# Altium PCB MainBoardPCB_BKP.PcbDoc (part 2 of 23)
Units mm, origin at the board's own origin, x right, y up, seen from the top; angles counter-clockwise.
Board outline 258.95 x 308.86 mm, 16 copper layers (L1, L2 (GND), L3 (Sign), L4 (GND), L5 (Sign), L6 (PWR/GND), L7(PWR/GND), L8 (Plane_GND), L9 (PWR/GND), L10 (PWR/GND), L11 (PWR/GND), L12 (Sign), L13 (GND), L14 (Sign), L15 (GND), L16), stack 2.502 mm thick; 2361 components, 1770 nets, 8410 pads, 3259 vias.
Unrouted connection lines stored in the file: 4700.

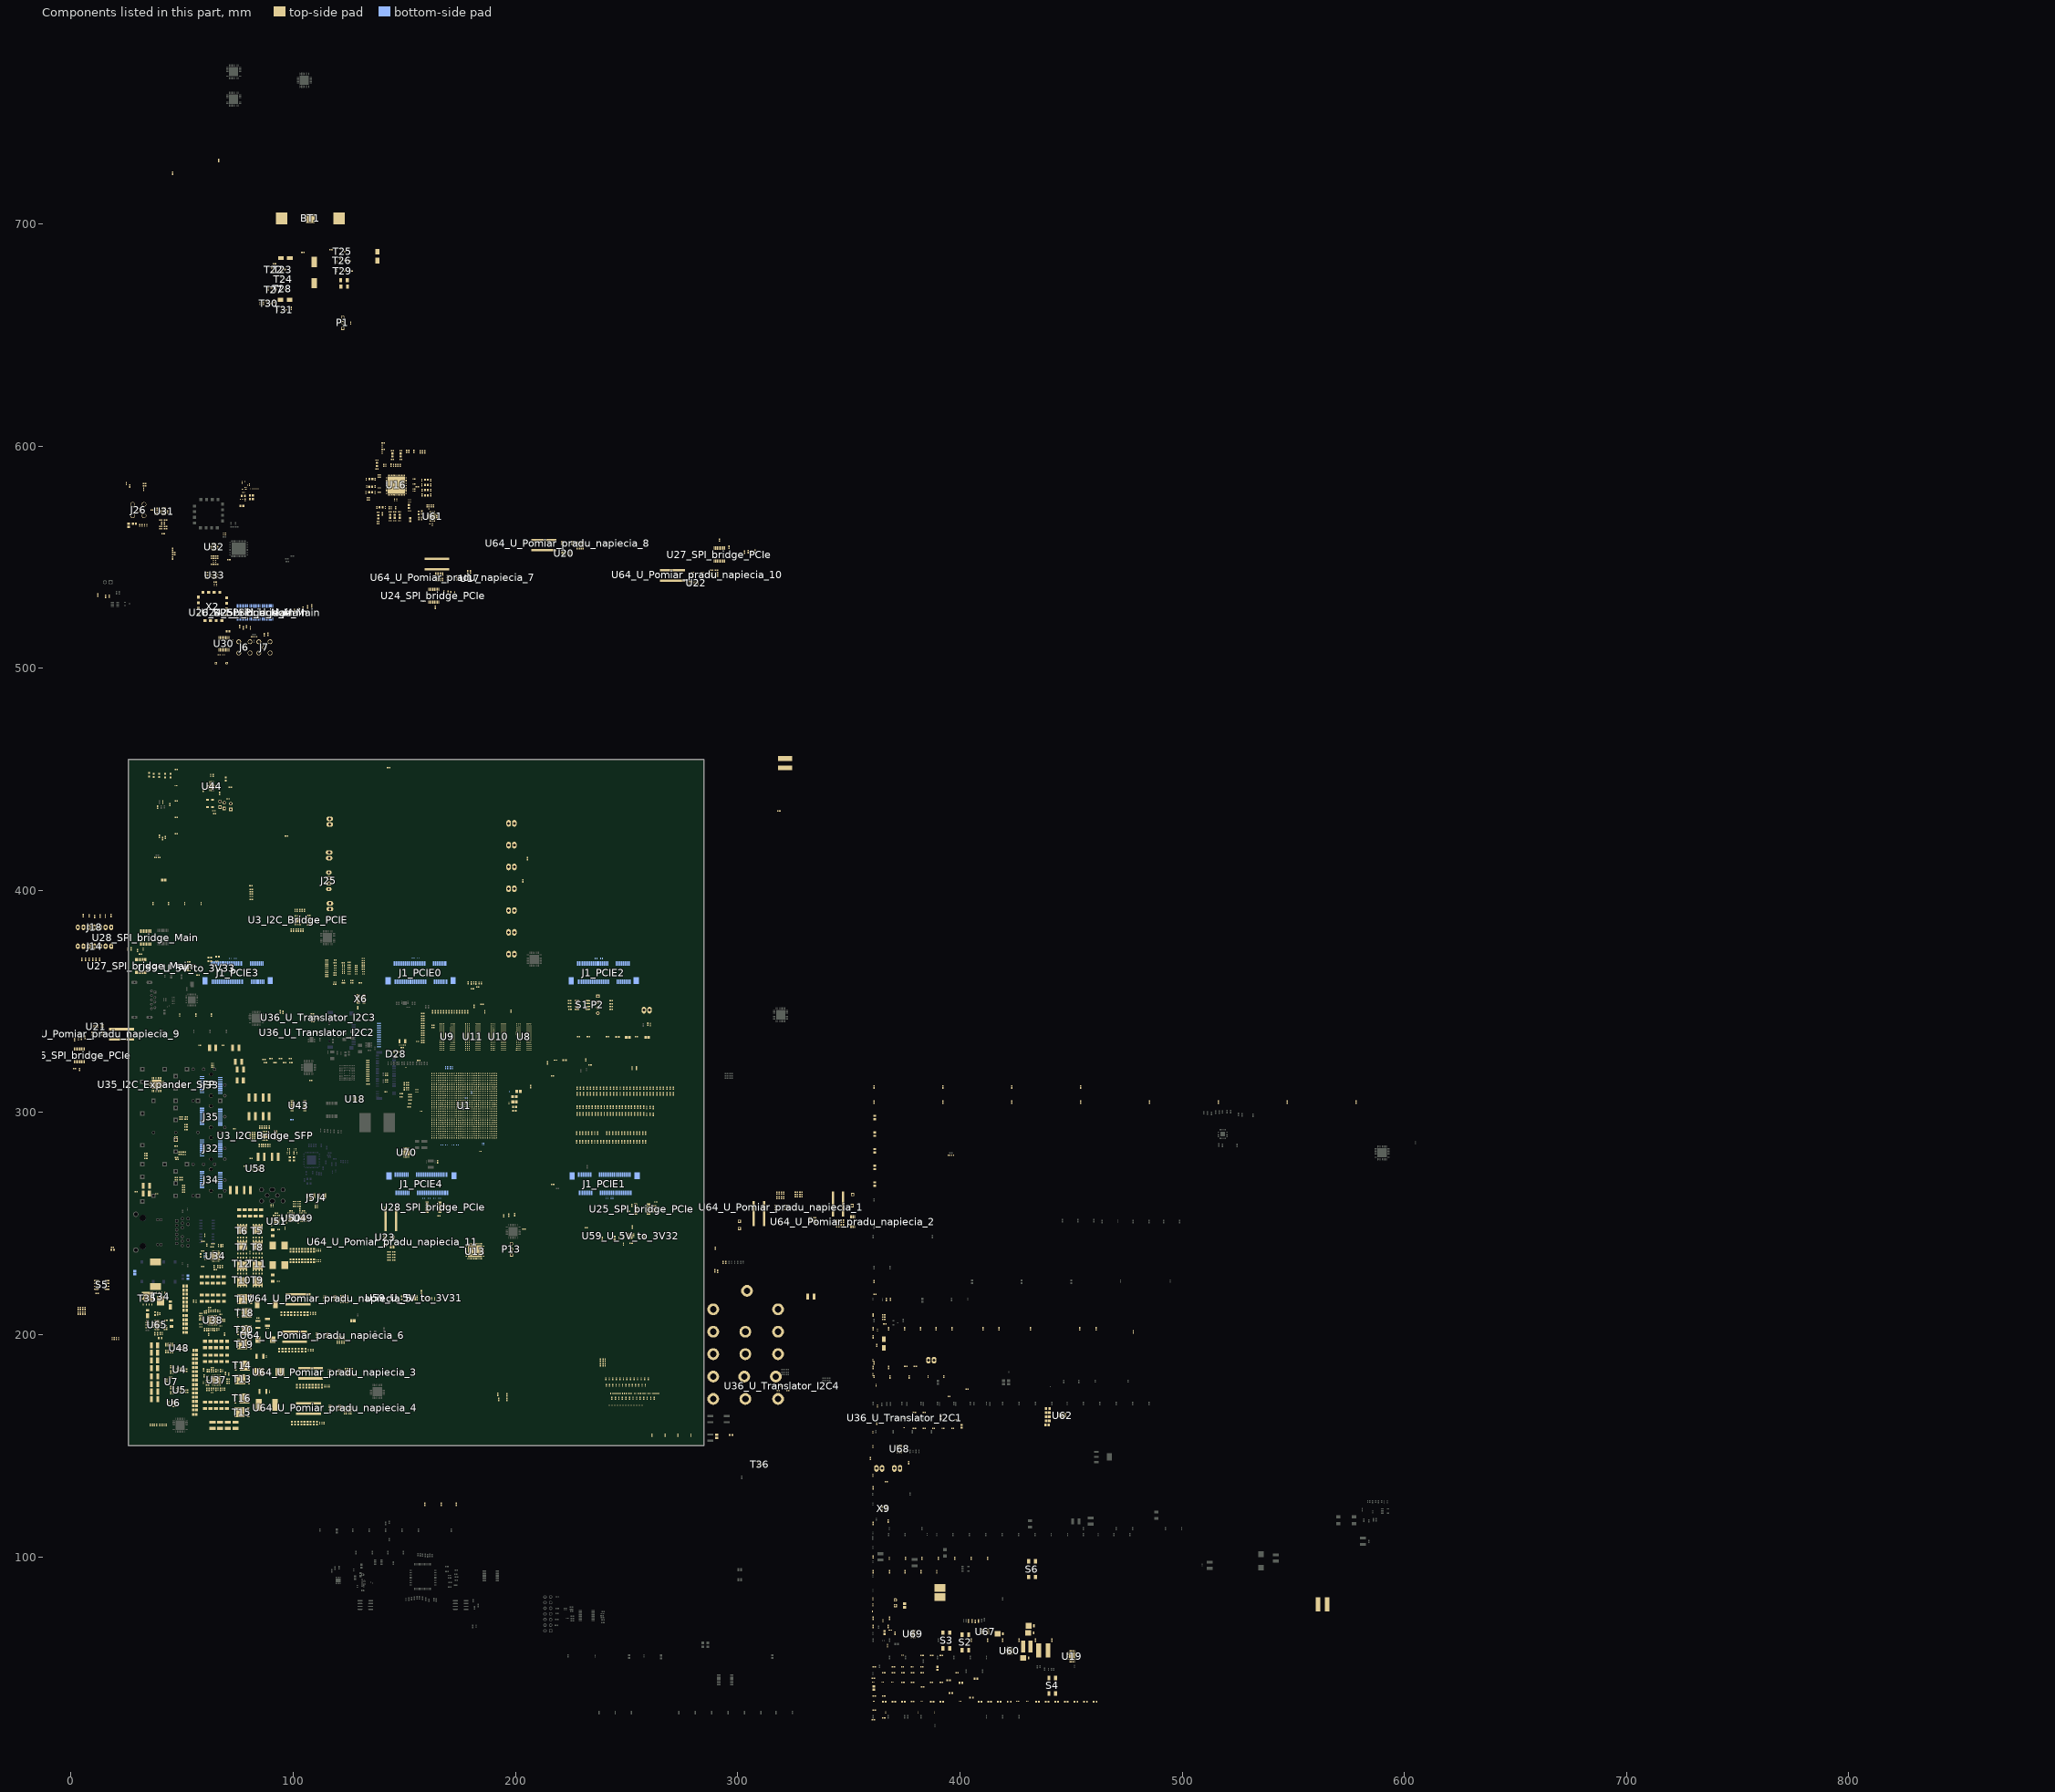
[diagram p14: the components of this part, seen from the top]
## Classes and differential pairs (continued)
component class U_TPS7A88_3V3_1V8_0V9V@2x1A: C705 C706 C707 C708 C709 C710 C711 C712 R671 R672 R673 R674 R676 R745 U70
component class U_ADP1741_3V3_0V85: C674 C675 C676 C719 FB45 R435 R644 R645 R646 R668 U69
component class LowCurr: C304 C305 C306 C307 C308 C354 C355 C603 C604 C605 C606 C607 C610 C611 C612 C613 C614 C615 C616 C617 C618 C619 C620 C621 C622 C623 C624 C625 C626 D16 D17 D18 D19 L13 L15 L16 L17 L18 R113 R114 R212 R214 R216 R218 R220 R274 R284 R305 R308 R309 U19 U67
component class U_Detektor_otwarcia: BT1 BT? C609 C678 C679 C680 D20 D21 D23 D24 J36 R647 R648 R649 R650 R651 R652 R653 R654 R655 R656 R657 R658 T22 T23 T24 T25 T26 T27 T28 T29 T30 T31
net class RAM_DQS_Strobe: DDR4_DQS_0_N DDR4_DQS_0_P DDR4_DQS_1_N DDR4_DQS_1_P DDR4_DQS_2_N DDR4_DQS_2_P DDR4_DQS_3_N DDR4_DQS_3_P DDR4_DQS_4_N DDR4_DQS_4_P DDR4_DQS_5_N DDR4_DQS_5_P DDR4_DQS_6_N DDR4_DQS_6_P DDR4_DQS_7_N DDR4_DQS_7_P DDR4_DQS_8_N DDR4_DQS_8_P
net class RAM_Data_IO: DDR4_DM0 DDR4_DM1 DDR4_DM2 DDR4_DM3 DDR4_DM4 DDR4_DM5 DDR4_DM6 DDR4_DM7 DDR4_DQ0 DDR4_DQ1 DDR4_DQ2 DDR4_DQ3 DDR4_DQ4 DDR4_DQ5 DDR4_DQ6 DDR4_DQ7 DDR4_DQ8 DDR4_DQ9 DDR4_DQ10 DDR4_DQ11 DDR4_DQ12 DDR4_DQ13 DDR4_DQ14 DDR4_DQ15 DDR4_DQ16 DDR4_DQ17 DDR4_DQ18 DDR4_DQ19 DDR4_DQ20 DDR4_DQ21 DDR4_DQ22 DDR4_DQ23 DDR4_DQ24 DDR4_DQ25 DDR4_DQ26 DDR4_DQ27 DDR4_DQ28 DDR4_DQ29 DDR4_DQ30 DDR4_DQ31 DDR4_DQ32 DDR4_DQ33 DDR4_DQ34 DDR4_DQ35 DDR4_DQ36 DDR4_DQ37 DDR4_DQ38 DDR4_DQ39 DDR4_DQ40 DDR4_DQ41 DDR4_DQ42 DDR4_DQ43 DDR4_DQ44 DDR4_DQ45 DDR4_DQ46 DDR4_DQ47 DDR4_DQ48 DDR4_DQ49 DDR4_DQ50 DDR4_DQ51 DDR4_DQ52 DDR4_DQ53 DDR4_DQ54 DDR4_DQ55 DDR4_DQ56 DDR4_DQ57 DDR4_DQ58 DDR4_DQ59 DDR4_DQ60 DDR4_DQ61 DDR4_DQ62 DDR4_DQ63
net class Power_Line_1A: 12V_LT3042 ADP1741_3.6V ETH_VDDIO NetD16_2 NetD17_1 NetD17_2 NetD18_1 NetD18_2 NetD19_1 NetD19_2 Power_3.3_1 Power_3.3_2 US+_MGTVccAux US+_Vcc_PS_DDR_504
net class Lenght_DQS_to_Data: DDR4_DM0 DDR4_DM1 DDR4_DM2 DDR4_DM3 DDR4_DM4 DDR4_DM5 DDR4_DM6 DDR4_DM7 DDR4_DQ0 DDR4_DQ1 DDR4_DQ2 DDR4_DQ3 DDR4_DQ4 DDR4_DQ5 DDR4_DQ6 DDR4_DQ7 DDR4_DQ8 DDR4_DQ9 DDR4_DQ10 DDR4_DQ11 DDR4_DQ12 DDR4_DQ13 DDR4_DQ14 DDR4_DQ15 DDR4_DQ16 DDR4_DQ17 DDR4_DQ18 DDR4_DQ19 DDR4_DQ20 DDR4_DQ21 DDR4_DQ22 DDR4_DQ23 DDR4_DQ24 DDR4_DQ25 DDR4_DQ26 DDR4_DQ27 DDR4_DQ28 DDR4_DQ29 DDR4_DQ30 DDR4_DQ31 DDR4_DQ32 DDR4_DQ33 DDR4_DQ34 DDR4_DQ35 DDR4_DQ36 DDR4_DQ37 DDR4_DQ38 DDR4_DQ39 DDR4_DQ40 DDR4_DQ41 DDR4_DQ42 DDR4_DQ43 DDR4_DQ44 DDR4_DQ45 DDR4_DQ46 DDR4_DQ47 DDR4_DQ48 DDR4_DQ49 DDR4_DQ50 DDR4_DQ51 DDR4_DQ52 DDR4_DQ53 DDR4_DQ54 DDR4_DQ55 DDR4_DQ56 DDR4_DQ57 DDR4_DQ58 DDR4_DQ59 DDR4_DQ60 DDR4_DQ61 DDR4_DQ62 DDR4_DQ63
net class Lenght_DQS_to_CK: DDR4_DQS_0_N DDR4_DQS_0_P DDR4_DQS_1_N DDR4_DQS_1_P DDR4_DQS_2_N DDR4_DQS_2_P DDR4_DQS_3_N DDR4_DQS_3_P DDR4_DQS_4_N DDR4_DQS_4_P DDR4_DQS_5_N DDR4_DQS_5_P DDR4_DQS_6_N DDR4_DQS_6_P DDR4_DQS_7_N DDR4_DQS_7_P DDR4_DQS_8_N DDR4_DQS_8_P
net class Lenght_CK_to_Addr: DDR4_CK_N DDR4_CK_P
differential pair class Diff_76_to_90_Ram_CLK: DDR4_CK
net class RAM_Adress: DDR4_A0 DDR4_A1 DDR4_A2 DDR4_A3 DDR4_A4 DDR4_A5 DDR4_A6 DDR4_A7 DDR4_A8 DDR4_A9 DDR4_A10 DDR4_A11 DDR4_A12 DDR4_A13 DDR4_ACT_N DDR4_ALERT_N DDR4_BA0 DDR4_BA1 DDR4_BG0 DDR4_CAS DDR4_CKE0 DDR4_CS_B DDR4_DQS_ODT0 DDR4_PARITY DDR4_RAM_RST_N DDR4_RAS DDR4_TEN DDR4_WE
component class U_Power_48_20V@3A: C595 C596 C597 C598 C693 C694 C695 C696 C697 C698 C699 C700 C701 C702 C703 C704 D26 D27 L22 R140 R149 R150 R159 R160 R665 R666 R667 R669 R670 R764 T34 T35 U65
net class WR_CLK_C: WR_LMK_CLK_IN_N WR_LMK_CLK_IN_P
net class WR_CLK2: WR_LMK_CLK_HF2_N WR_LMK_CLK_HF2_P
net class WR_CLK1: WR_LMK_CLK_HF1_N WR_LMK_CLK_HF1_P
component class U_Pomiar_pradu_napiecia_1: C309_U_Pomiar_pradu_napiecia_1 R448_U_Pomiar_pradu_napiecia_1 U64_U_Pomiar_pradu_napiecia_1
component class U_Pomiar_pradu_napiecia_2: C309_U_Pomiar_pradu_napiecia_2 R448_U_Pomiar_pradu_napiecia_2 U64_U_Pomiar_pradu_napiecia_2
component class U_Pomiar_pradu_napiecia_3: C309_U_Pomiar_pradu_napiecia_3 R448_U_Pomiar_pradu_napiecia_3 U64_U_Pomiar_pradu_napiecia_3
component class U_Pomiar_pradu_napiecia_4: C309_U_Pomiar_pradu_napiecia_4 R448_U_Pomiar_pradu_napiecia_4 U64_U_Pomiar_pradu_napiecia_4
net class LTC_6952_2_REF_SMA: LTC6952_1_C_N LTC6952_1_C_P
net class LTC_6952_2_REF: LTC6952_1_REF_N LTC6952_1_REF_P
component class DAC: C320 C321 C322 C323 R481 R608 R609 U30 X2 X3
net class Si53323_2_Q2_LVDS: Si53323_2_Q2_LVDS_N Si53323_2_Q2_LVDS_P
net class Si53323_1_Q2_LVDS: Si53323_1_Q2_LVDS_N Si53323_1_Q2_LVDS_P
component class SFP_Group+IMU: R469 R470 R471 R472 R473 R474 R475 R476 R477 R478 R479 R480
component class HighSpeed: R427 R449 R450 R451 R452 R453 R454 R538
component class CLK_MUX: C324 C325 C326 C327 C328 C329 C330 C333 C336 C337 C338 C339 C340 C341 C342 C343 C344 C724 C725 C726 C727 FB23 FB24 J26 R245 R246 R247 R248 R249 R250 R251 R252 R253 R254 R255 R256 R257 R258 R259 R260 R261 R262 R263 R264 R265 R291 R301 R384 R385 R386 R387 R482 R483 R484 R485 R486 R487 R488 R489 T36 U31 U32 U33
net class Si53323_2_Q2: Si53323_2_Q2_N Si53323_2_Q2_P
net class Si53323_2_Q1: Si53323_2_Q1_P
net class Si53323_2_CLK1: Si53323_2_CLK1_N Si53323_2_CLK1_P
net class Si53323_1_Q2: Si53323_1_Q2_N Si53323_1_Q2_P
net class Si53323_1_Q1: Si53323_1_Q1_N
net class RefClk_Si53323: RefClk_Si53323_P
net class MUX_DIV_OUT: OSC_Out_DIV_P
net class MUX_DIV_OUT_I: Osc_in_Si53323_2_P
net class CLM_M_OSC_IN_C: OSC_500Out
net class CLK_SMA1_C: AGND LTC6952_1_C_Out10_N LTC6952_1_C_Out10_P
net class CLK_M_OSC_In: CLK_M_OSC_In
differential pair class Diff_76_to_90_Ram_DQS: DDR4_DQS_0 DDR4_DQS_1 DDR4_DQS_2 DDR4_DQS_3 DDR4_DQS_4 DDR4_DQS_5 DDR4_DQS_6 DDR4_DQS_7 DDR4_DQS_8
net class Single_36_39_50_Adr: DDR4_A0 DDR4_A1 DDR4_A2 DDR4_A3 DDR4_A4 DDR4_A5 DDR4_A6 DDR4_A7 DDR4_A8 DDR4_A9 DDR4_A10 DDR4_A11 DDR4_A12 DDR4_A13 DDR4_ACT_N DDR4_ALERT_N DDR4_BA0 DDR4_BA1 DDR4_BG0 DDR4_CAS DDR4_CKE0 DDR4_CS_B DDR4_DQS_ODT0 DDR4_PARITY DDR4_RAM_RST_N DDR4_RAS DDR4_TEN DDR4_WE
net class Diff_76_86_90: DDR4_DQS_0_N DDR4_DQS_0_P DDR4_DQS_1_N DDR4_DQS_1_P DDR4_DQS_2_N DDR4_DQS_2_P DDR4_DQS_3_N DDR4_DQS_3_P DDR4_DQS_4_N DDR4_DQS_4_P DDR4_DQS_5_N DDR4_DQS_5_P DDR4_DQS_6_N DDR4_DQS_6_P DDR4_DQS_7_N DDR4_DQS_7_P DDR4_DQS_8_N DDR4_DQS_8_P
net class RAM_Clock_Signal: DDR4_CK_N DDR4_CK_P
component class U_Pomiar_pradu_napiecia_5: C309_U_Pomiar_pradu_napiecia_5 R448_U_Pomiar_pradu_napiecia_5 U64_U_Pomiar_pradu_napiecia_5
component class U_Pomiar_pradu_napiecia_6: C309_U_Pomiar_pradu_napiecia_6 R448_U_Pomiar_pradu_napiecia_6 U64_U_Pomiar_pradu_napiecia_6
component class U_Pomiar_pradu_napiecia_7: C309_U_Pomiar_pradu_napiecia_7 R448_U_Pomiar_pradu_napiecia_7 U64_U_Pomiar_pradu_napiecia_7
component class U_Pomiar_pradu_napiecia_8: C309_U_Pomiar_pradu_napiecia_8 R448_U_Pomiar_pradu_napiecia_8 U64_U_Pomiar_pradu_napiecia_8
component class U_Pomiar_pradu_napiecia_9: C309_U_Pomiar_pradu_napiecia_9 R448_U_Pomiar_pradu_napiecia_9 U64_U_Pomiar_pradu_napiecia_9
component class U_5V_to_3V31: C563_U_5V_to_3V31 C564_U_5V_to_3V31 C565_U_5V_to_3V31 C566_U_5V_to_3V31 C567_U_5V_to_3V31 R430_U_5V_to_3V31 R431_U_5V_to_3V31 R432_U_5V_to_3V31 U59_U_5V_to_3V31
channel class Pomiar_pradu_napiecia: U_Pomiar_pradu_napiecia_10 U_Pomiar_pradu_napiecia_11
net class Single_39_50_D: DDR4_DM0 DDR4_DM1 DDR4_DM2 DDR4_DM3 DDR4_DM4 DDR4_DM5 DDR4_DM6 DDR4_DM7 DDR4_DQ0 DDR4_DQ1 DDR4_DQ2 DDR4_DQ3 DDR4_DQ4 DDR4_DQ5 DDR4_DQ6 DDR4_DQ7 DDR4_DQ8 DDR4_DQ9 DDR4_DQ10 DDR4_DQ11 DDR4_DQ12 DDR4_DQ13 DDR4_DQ14 DDR4_DQ15 DDR4_DQ16 DDR4_DQ17 DDR4_DQ18 DDR4_DQ19 DDR4_DQ20 DDR4_DQ21 DDR4_DQ22 DDR4_DQ23 DDR4_DQ24 DDR4_DQ25 DDR4_DQ26 DDR4_DQ27 DDR4_DQ28 DDR4_DQ29 DDR4_DQ30 DDR4_DQ31 DDR4_DQ32 DDR4_DQ33 DDR4_DQ34 DDR4_DQ35 DDR4_DQ36 DDR4_DQ37 DDR4_DQ38 DDR4_DQ39 DDR4_DQ40 DDR4_DQ41 DDR4_DQ42 DDR4_DQ43 DDR4_DQ44 DDR4_DQ45 DDR4_DQ46 DDR4_DQ47 DDR4_DQ48 DDR4_DQ49 DDR4_DQ50 DDR4_DQ51 DDR4_DQ52 DDR4_DQ53 DDR4_DQ54 DDR4_DQ55 DDR4_DQ56 DDR4_DQ57 DDR4_DQ58 DDR4_DQ59 DDR4_DQ60 DDR4_DQ61 DDR4_DQ62 DDR4_DQ63
component class US+_Interrupts: R515 R522 R523 R530 R531 R546 R547 R548 R549 R550 R551 R552 R553 R554 R555 R556 R557 R607 R618 R659 R660 R661 R662 R663 R664 R688 R735 R736 R744 R765 R766 R767 R817 R818 R819 R820 R821 R822 R823 R824 R847 R848 R849 R850 R851 R852 R853 R854 R855 R856 R857 R858 R859 R860 R861 R862 R863 R864 R865 R866 R867 R868 R869 R870 R871 R872 R873 R874 R875 R876 R877 R878 R879 R880 R881 R882 R883 R884 R885 R886 R921 R922 R923 R924 R925 R926 R927 R928 R929 R930 R931 R932 R933 R934 R935 R936 R937 R938 R939 R940 R941 R942 R943 R944 R945 R946 R947 R948 R949 R950 R951 R952 R953 R954 R955 R956 R957 R958 R959 R960 R961 R962 R963 R964 R965 R966 R967 R968 R969 R970 R971 R972 R973 R974 R975 R976 R977 R978 R979 R980 R981 R982 R983 R984 R985 R986 R987 R988 R989 R990 R991 R992 R993 R994 R995 R996 R997 R998 R999 R1000
component class U_Pomiar_pradu_napiecia_10: C309_U_Pomiar_pradu_napiecia_10 R448_U_Pomiar_pradu_napiecia_10 U64_U_Pomiar_pradu_napiecia_10
component class U_Pomiar_pradu_napiecia_11: C309_U_Pomiar_pradu_napiecia_11 R448_U_Pomiar_pradu_napiecia_11 U64_U_Pomiar_pradu_napiecia_11
component class PowerDistribition: P7 P8 P9 P10 P11 R229 R230 R455 R456 R457 R458 R459 R460 R461 R462 R463 R464 R465 R466 R467 R468 R593 R594 R595 R596 R597 R598
net class Single_50: Bank505_MGTRREF0_C_N Bank505_MGTRREF0_C_P Bank505_MGTRREF2_C_N Bank505_MGTRREF2_C_P Bank505_MGTRREF3_C_N Bank505_MGTRREF3_C_P CLK_M_OSC_In CLK_SMA0_C_N CLK_SMA0_C_P LTC6952_0_Out0_N LTC6952_0_Out0_P LTC6952_0_Out1_N LTC6952_0_Out1_P LTC6952_0_Out2_N LTC6952_0_Out2_P LTC6952_0_Out3_N LTC6952_0_Out3_P LTC6952_0_Out4_N LTC6952_0_Out4_P LTC6952_0_Out5_N LTC6952_0_Out5_P LTC6952_0_Out6_N LTC6952_0_Out6_P LTC6952_0_Out7_N LTC6952_0_Out7_P LTC6952_0_Out8_N LTC6952_0_Out8_P LTC6952_0_Out9_N LTC6952_0_Out9_P LTC6952_0_Out10_N LTC6952_0_Out10_P LTC6952_0_REF_N LTC6952_0_REF_P LTC6952_1_C_N LTC6952_1_C_Out10_N LTC6952_1_C_Out10_P LTC6952_1_C_P LTC6952_1_Out0_N LTC6952_1_Out0_P LTC6952_1_Out1_N LTC6952_1_Out1_P LTC6952_1_Out2_N LTC6952_1_Out2_P LTC6952_1_Out3_N LTC6952_1_Out3_P LTC6952_1_Out4_N LTC6952_1_Out4_P LTC6952_1_Out5_N LTC6952_1_Out5_P LTC6952_1_Out6_N LTC6952_1_Out6_P LTC6952_1_Out7_N LTC6952_1_Out7_P LTC6952_1_Out8_N LTC6952_1_Out8_P LTC6952_1_Out9_N LTC6952_1_Out9_P LTC6952_1_Out10_N LTC6952_1_Out10_P LTC6952_1_REF_N LTC6952_1_REF_P LTC6952_1_VCO_N LTC6952_1_VCO_P NetC334_1 NetC335_2 NetC341_1 NetC588_1 NetC588_2 NetR543_1 NVME_C_RX_1_N NVME_C_RX_1_P NVME_C_RX_O_N NVME_C_RX_O_P NVME_C_TX_1_N NVME_C_TX_1_P NVME_C_TX_O_N NVME_C_TX_O_P NVMe_Rx_0_N NVMe_Rx_0_P NVMe_Rx_1_N NVMe_Rx_1_P NVMe_Tx_0_N NVMe_Tx_0_P NVMe_Tx_1_N NVMe_Tx_1_P OSC_500Out Osc_in_Si53323_2_P OSC_Out_DIV_N OSC_Out_DIV_P RefClk_Si53323_P SGMI_C_Rx_N SGMI_C_Rx_P SGMI_C_Tx_N SGMI_C_Tx_P SGMI_Rx_N SGMI_Rx_P SGMI_Tx_N SGMI_Tx_P Si53323_1_Q1_N Si53323_1_Q2_LVDS_N Si53323_1_Q2_LVDS_P Si53323_1_Q2_N Si53323_1_Q2_P Si53323_2_CLK1_N Si53323_2_CLK1_P Si53323_2_Q1_N Si53323_2_Q1_P Si53323_2_Q2_LVDS_N Si53323_2_Q2_LVDS_P Si53323_2_Q2_N Si53323_2_Q2_P TD_A_N TD_A_P TD_B_N TD_B_P TD_C_N TD_C_P TD_D_N TD_D_P WR_LMK_CLK_HF1_N WR_LMK_CLK_HF1_P WR_LMK_CLK_HF2_N WR_LMK_CLK_HF2_P WR_LMK_CLK_IN_N WR_LMK_CLK_IN_P XO_LMK05028_P
net class Bank505_MGTRREFx_C: Bank505_MGTRREF0_C_N Bank505_MGTRREF0_C_P Bank505_MGTRREF2_C_N Bank505_MGTRREF2_C_P Bank505_MGTRREF3_C_N Bank505_MGTRREF3_C_P NetU2_L25 NetU2_L26
net class Bank225_MGTREFx_C: Bank225_MGTREF0_C_N Bank225_MGTREF0_C_P Bank225_MGTREF1_C_N Bank225_MGTREF1_C_P
net class Bank224_MGTREFx_C: Bank224_MGTREF0_C_N Bank224_MGTREF0_C_P Bank224_MGTREF1_C_N Bank224_MGTREF1_C_P
net class Bank223_MGTREFx_C: Bank223_MGTREF0_C_N Bank223_MGTREF0_C_P Bank223_MGTREF1_C_N Bank223_MGTREF1_C_P
component class U_Translator_I2C4: TP60_U_Translator_I2C4 TP61_U_Translator_I2C4 U36_U_Translator_I2C4
differential pair class Diff_100: B223_Rx0 B223_Rx1 B223_Rx2 B223_Rx3 B223_Tx0_to_C B223_Tx0C_to_B B223_Tx1_to_C B223_Tx1C_to_B B223_Tx2_to_C B223_Tx2C_to_B B223_Tx3_to_C B223_Tx3C_to_B B224_Rx0 B224_Rx1 B224_Rx2 B224_Rx3 B224_Tx0_to_C B224_Tx0C_to_B B224_Tx1_to_C B224_Tx1C_to_B B224_Tx2_to_C B224_Tx2C_to_B B224_Tx3_to_C B224_Tx3C_to_B B225_Rx0 B225_Rx1 B225_Rx2 B225_Rx3 B225_Tx0_to_C B225_Tx0C_to_B B225_Tx1_to_C B225_Tx1C_to_B B225_Tx2_to_C B225_Tx2C_to_B B225_Tx3_to_C B225_Tx3C_to_B Bank223_MGTREF0 Bank223_MGTREF0_C Bank223_MGTREF1 Bank223_MGTREF1_C Bank224_MGTREF0 Bank224_MGTREF0_C Bank224_MGTREF1 Bank224_MGTREF1_C Bank225_MGTREF0 Bank225_MGTREF0_C Bank225_MGTREF1 Bank225_MGTREF1_C Bank505_MGTRREF0_C Bank505_MGTRREF2_C Bank505_MGTRREF3_C CLK_100 CLK_Fanout_In CLK_GTR_T1 CLK_GTR_T2 CLK_GTR_T3 CLK_Hi_Rail1 CLK_Hi_Rail1_SysRef CLK_Hi_Rail2 CLK_Hi_Rail2_SysRef CLK_M_OSC_In CLK_NVME_Conn CLK_Q223_T1 CLK_Q224_T1 CLK_Q225_T1 CLK_Q226_T1 CLK_SMA0 CLK_SMA0_C CLK_SMA1 CLK_SMA1_C CLK_SMA2 CLK_SMA2_C Data_2_RX_PCIE0 Data_2_RX_PCIE1 Data_2_RX_PCIE2 Data_2_RX_PCIE3 Data_2_TX_PCIE0 Data_2_TX_PCIE1 Data_2_TX_PCIE2 Data_2_TX_PCIE3 Data_3_RX_PCIE0 Data_3_RX_PCIE1 Data_3_RX_PCIE2 Data_3_RX_PCIE3 Data_3_TX_PCIE0 Data_3_TX_PCIE1 Data_3_TX_PCIE2 Data_3_TX_PCIE3 LTC6952_0_Out0 LTC6952_0_Out1 LTC6952_0_Out2 LTC6952_0_Out3 LTC6952_0_Out4 LTC6952_0_Out5 LTC6952_0_Out6 LTC6952_0_Out7 LTC6952_0_Out8 LTC6952_0_Out9 LTC6952_0_Out10 LTC6952_0_REF LTC6952_1_C LTC6952_1_C_Out10 LTC6952_1_Out0 LTC6952_1_Out1 LTC6952_1_Out2 LTC6952_1_Out3 LTC6952_1_Out4 LTC6952_1_Out5 LTC6952_1_Out6 LTC6952_1_Out7 LTC6952_1_Out8 LTC6952_1_Out9 LTC6952_1_Out10 LTC6952_1_REF LTC6952_1_VCO LTC6952_2_REF LTC6952_2_REF_SMA LTC6952_3_REF LTC6952_3_REF_SMA NVME_C_RX_1 NVME_C_RX_O NVME_C_TX_1 NVME_C_TX_O NVMe_CLK NVMe_Rx_0 NVMe_Rx_1 NVMe_Tx_0 NVMe_Tx_1 Osc_in_Si53323_2 OSC_Out_DIV PCIE0_CLK PCIE0_Sync PCIE0_SysRef PCIE0_SysRef_FPGA PCIE1_CLK PCIE1_Sync PCIE1_SysRef PCIE1_SysRef_FPGA PCIE2_CLK PCIE2_Sync PCIE2_SysRef PCIE2_SysRef_FPGA PCIE3_CLK PCIE3_Sync PCIE3_SysRef PCIE3_SysRef_FPGA PCIE4_CLK PCIE4_Sync PCIE4_SysRef PCIE4_SysRef_FPGA RefClk_Si53323 SFP0_Rx SFP0_Tx SFP1_Rx SFP1_Tx SFP2_Rx SFP2_Tx SFP3_Rx SFP3_Tx SGMI_C_Rx SGMI_C_Tx SGMI_CLK_C_Out SGMI_CLK_Out SGMI_Rx SGMI_Tx Si53323_1_Q1 Si53323_1_Q2 Si53323_1_Q2_LVDS Si53323_2_CLK1 Si53323_2_Q1 Si53323_2_Q2 Si53323_2_Q2_LVDS SYNC_PCIE0 SYNC_PCIE1 SYNC_PCIE2 SYNC_PCIE3 SYNC_PCIE4 SYSREF_PCIE0 SYSREF_PCIE1 SYSREF_PCIE2 SYSREF_PCIE3 SYSREF_PCIE4 TD_A TD_B TD_C TD_D WR_LMK_CLK_HF1 WR_LMK_CLK_HF2 WR_LMK_CLK_IN WR_Source_CLK
channel class Translator_I2C: U_Translator_I2C1 U_Translator_I2C2 U_Translator_I2C3
channel class 5V_to_3V3: 5V_to_3V3_for_FTDI U_5V_to_3V32 U_5V_to_3V33
net class SFP_diff: SFP0_Rx_N SFP0_Rx_P SFP0_Tx_N SFP0_Tx_P SFP1_Rx_N SFP1_Rx_P SFP1_Tx_N SFP1_Tx_P SFP2_Rx_N SFP2_Rx_P SFP2_Tx_N SFP2_Tx_P SFP3_Rx_N SFP3_Rx_P SFP3_Tx_N SFP3_Tx_P
net class C_to_Bank225: B225_Rx0_N B225_Rx0_P B225_Rx1_N B225_Rx1_P B225_Rx2_N B225_Rx2_P B225_Rx3_N B225_Rx3_P B225_Tx0C_to_B_N B225_Tx0C_to_B_P B225_Tx1C_to_B_N B225_Tx1C_to_B_P B225_Tx2C_to_B_N B225_Tx2C_to_B_P B225_Tx3C_to_B_N B225_Tx3C_to_B_P
net class C_to_Bank224: B224_Tx0C_to_B_N B224_Tx0C_to_B_P B224_Tx1C_to_B_N B224_Tx1C_to_B_P B224_Tx2C_to_B_N B224_Tx2C_to_B_P B224_Tx3C_to_B_N B224_Tx3C_to_B_P
net class C_to_Bank223: B223_Rx0_N B223_Rx0_P B223_Rx1_N B223_Rx1_P B223_Rx2_N B223_Rx2_P B223_Rx3_N B223_Rx3_P B223_Tx0C_to_B_N B223_Tx0C_to_B_P B223_Tx1C_to_B_N B223_Tx1C_to_B_P B223_Tx2C_to_B_N B223_Tx2C_to_B_P B223_Tx3C_to_B_N B223_Tx3C_to_B_P
component class U_Translator_I2C3: TP60_U_Translator_I2C3 TP61_U_Translator_I2C3 U36_U_Translator_I2C3
component class U_Translator_I2C2: TP60_U_Translator_I2C2 TP61_U_Translator_I2C2 U36_U_Translator_I2C2
component class U_Translator_I2C1: TP60_U_Translator_I2C1 TP61_U_Translator_I2C1 U36_U_Translator_I2C1
component class U_TPS7A88_5V_Dual_3: C572 C573 C574 C575 C576 C577 C578 C579 R436 R437 R438 R439 R440 R441 U61
component class U_LT3042_12V_5V_LNLDO: C580 C581 C582 C583 C584 FB34 R442 R443 R444 R445 U62
component class U_ADP1741_3: C568 C569 C570 C571 FB33 R433 R434 U60
component class U_5V_to_3V33: C563_U_5V_to_3V33 C564_U_5V_to_3V33 C565_U_5V_to_3V33 C566_U_5V_to_3V33 C567_U_5V_to_3V33 R430_U_5V_to_3V33 R431_U_5V_to_3V33 R432_U_5V_to_3V33 U59_U_5V_to_3V33
component class U_5V_to_3V32: C563_U_5V_to_3V32 C564_U_5V_to_3V32 C565_U_5V_to_3V32 C566_U_5V_to_3V32 C567_U_5V_to_3V32 R430_U_5V_to_3V32 R431_U_5V_to_3V32 R432_U_5V_to_3V32 U59_U_5V_to_3V32
component class Ram_Power: C219 C220 C221 C222 C223 C224 C225 C226 C227 C228 C229 C230 C231 C232 C233 C234 C235 C236 C237 C238 C239 C240 C241 C242 C243 C244 C245 C246 C247 C248 C249 C250 C251 C252 C253 C254 C255 C256 C257 C258 C259 C260 C261 C262 C263 C264 C265 C266 C782 C783 C784 C785 C786 C787 C788 C789 R165 R166 R167 R168 R169 R170 R171 R172
component class PS_Config: C531 C532 C533 C534 C535 C536 D5 D6 D7 D8 D9 D10 D11 D12 P2 P3 P4 P5 R346 R347 R348 R349 R350 R351 R352 R353 R354 R355 R356 R357 R358 R359 R360 R361 R367 R368 R369 R370 R371 R372 R373 R374 R375 R716 R717 R718 R719 R720 S1 S2 S3 S4 U43 U44 X5 X6
component class IMU: C561 C562 R429 R600 R601 U58
component class GTR: C525 C526 C527 C528 C529 C530 C649 C651 C653 C677 C715 C716 C717 C718 R69 R70 R126
component class "Bank 225": C291 C292 C293 C294 C295 C296 C297 C298 C299 C300 C301 C302
component class "Bank 224": C279 C280 C281 C282 C283 C284 C285 C286 C287 C288 C289 C290
component class "Bank 223": C267 C268 C269 C270 C271 C272 C273 C274 C275 C276 C277 C278
component class U_Power_Ethernet: C550 C551 C552 C553 C554 C555 C654 C655 C656 C657 R391 R392 R393 R394 R396 R397 R399 R632 R633 R634 U49 U50 U51 U68
component class U_Power_ADP1850_Dual_2: C430 C431 C432 C433 C434 C435 C436 C437 C438 C439 C440 C441 C442 C443 C444 C445 C446 C447 C448 C449 C450 C451 C452 C453 C454 C455 C456 C457 C458 C459 C460 C461 C462 C463 C464 C465 C466 C467 C468 C469 C470 C548 C549 C645 C646 C647 C648 C650 C652 L19 L20 R302 R303 R306 R307 R310 R312 R313 R314 R315 R316 R317 R318 R625 R626 R627 R628 R629 R631 R686 R687 T17 T18 T19 T20 U38
component class U_HI_Curr_ADP1850_3: C389 C390 C391 C392 C393 C394 C395 C396 C397 C398 C399 C400 C401 C402 C403 C404 C405 C406 C407 C408 C409 C410 C411 C412 C413 C414 C415 C416 C417 C418 C419 C420 C421 C422 C423 C424 C425 C426 C427 C428 C429 C637 C638 C639 C640 C641 C642 C643 C644 L11 L12 R285 R287 R288 R289 R290 R292 R293 R294 R295 R296 R297 R298 R299 R300 R619 R620 R621 R622 R623 R624 T13 T14 T15 T16 U37
component class "Zasilanie CLK": C55 C56 C57 C58 C59 C60 C61 C62 C63 C64 C65 C66 C67 C68 C69 C70 C71 C72 C73 C74 C75 C76 C77 C78 C79 C80 C81 C82 C83 C84 C85 C86 C87 C88 C89 C90 C91 C92 C93 C94 C95 C96 C97 C98 C99 C100 C101 C102 C103 C104 C105 C106 C107 C108 C109 C110 C111 C112 C113 C114 C115 C116 C117 C118 C119 C120 C121 C122 C123 C124 C125 C126 C127 C128 C129 C130 C131 C132 C133 C134 C135 C136 C137 C138 C139 C140 C141 C142 C143 C144 C145 C146 C147 C148 C149 C150 C151 C152 C153 C154 C155 C156 C157 C158 C159 C160 C161 C162 C163 C164 C165 C166 C167 C168 C169 C170 C171 C172 C173 C174 C175 C176 C177 C178 C179 C180 C181 C182 C183 C184 C185 C186 C187 C188 C189 C190 C191 C192 C193 C194 C195 C196 C197 C198 C199 C200 C201 C202 C203 C204 C205 C206 FB2 FB3 FB4 FB5 FB6 FB7 FB8 FB9 FB10 FB11 FB12 FB13 FB14 FB15 FB16 FB17 FB18 FB19 FB20 FB21 FB22 FB35 FB36 R738 R739 R740 R741 R742 R743 U16
component class PowerSelector: C4 C5 C6 C7 C8 C9 C10 C11 C12 C13 C14 C15 C16 C17 C18 C19 C20 C21 C22 C23 C24 C25 C26 C27 C28 C29 C30 C31 C32 C33 C34 C35 C312 C313 C314 C766 C767 C768 C769 C770 C771 C772 C773 C774 C775 C776 C777 C778 C779 C780 C781 R11 R12 R13 R15 R17 R18 R19 R20 R21 R23 R25 R26 R27 R28 R29 R30 R630 R677 R678 R679 R680 R681 R682 R683 R684 R685 R1052 R1053 U4 U5 U6 U7 U48
channel class SPI_Muxes: SPI_bridge_Main SPI_bridge_PCIe
channel class I2C_Expander: I2C_Expander4 I2C_Expander5
component class XilinxPower: B1 C627 C628 C629 C630 C631 C632 D28 FB38 FB39 FB40 FB41 FB42 J29 J30 R173 R276 R279 R282 R283 R286 R693 R694 R695 R696
component class "Xilinx Linux": J12 J13 J14 J15 J16 J17 J18 J19 J20 J21 J22 J23 J24 J25 P1 P13 R83 R84 R85 R86 R87 R88 R89 R90 R91 R92 R93 R94 R95 R96 R97 R98 R99 R100 R101 R102 R103 R104 R105 R106 R107 R108 R109 R110 R111 R112 R115 R116 R117 R118 R119 R120 R121 R122 R123 R362 R675 R737 R768 R769 R770 R771 R772 R773 R774 R775 R776 R777 R778 R779 R780 R781 R782 R783 R784 R785 R786 R787 R788 R789 R790 R791 R792 R793 R794 R795 R796 R797 R798 R799 R800 R801 R802 R803 R804 R805 R806 R807 R808 R809 R810 R811 R812 R813 R814 R815 R816 TP21 TP22 TP23 TP24 TP25 TP26 TP27 TP28 TP29 TP30 TP31 TP32 TP33 TP34 TP35 TP36 TP37 TP38 TP39 TP40 TP41 TP42
component class "WR CLK": C41 C42 C588 C589 C590 C591 C592 FB37 R1 R2 R125 R127 R128 R129 R130 R131 R132 R133 R134 R139 R311 R366 R498 R499 R540 R543 R544 R545 R692 R912 S6 X9
component class U_HI_Curr_ADP1850_1: C345 C346 C347 C348 C349 C350 C351 C352 C353 C356 C357 C358 C359 C360 C361 C362 C363 C364 C365 C366 C367 C368 C369 C370 C371 C372 C373 C374 C375 C376 C377 C378 C379 C380 C381 C382 C383 C384 C385 C386 C387 C388 C633 C634 C635 C636 L9 L10 R268 R271 R272 R273 R275 R277 R278 R280 R610 R611 R612 R613 R614 R615 R616 T5 T6 T7 T8 T9 T10 T11 T12 U34
component class SPI_bridge_Main: R231_SPI_bridge_Main R232_SPI_bridge_Main R233_SPI_bridge_Main R234_SPI_bridge_Main R235_SPI_bridge_Main R236_SPI_bridge_Main R237_SPI_bridge_Main R238_SPI_bridge_Main R239_SPI_bridge_Main R240_SPI_bridge_Main R425_SPI_bridge_Main R426_SPI_bridge_Main R602_SPI_bridge_Main R603_SPI_bridge_Main R604_SPI_bridge_Main R605_SPI_bridge_Main R606_SPI_bridge_Main R887_SPI_bridge_Main R888_SPI_bridge_Main R889_SPI_bridge_Main R890_SPI_bridge_Main R891_SPI_bridge_Main R892_SPI_bridge_Main R893_SPI_bridge_Main R894_SPI_bridge_Main R895_SPI_bridge_Main R896_SPI_bridge_Main R897_SPI_bridge_Main R898_SPI_bridge_Main R899_SPI_bridge_Main TP50_SPI_bridge_Main TP51_SPI_bridge_Main TP52_SPI_bridge_Main TP53_SPI_bridge_Main TP54_SPI_bridge_Main TP55_SPI_bridge_Main TP56_SPI_bridge_Main TP57_SPI_bridge_Main TP58_SPI_bridge_Main TP59_SPI_bridge_Main U24_SPI_bridge_Main U25_SPI_bridge_Main U26_SPI_bridge_Main U27_SPI_bridge_Main U28_SPI_bridge_Main
component class SPI_bridge_PCIe: R231_SPI_bridge_PCIe R232_SPI_bridge_PCIe R233_SPI_bridge_PCIe R234_SPI_bridge_PCIe R235_SPI_bridge_PCIe R236_SPI_bridge_PCIe R237_SPI_bridge_PCIe R238_SPI_bridge_PCIe R239_SPI_bridge_PCIe R240_SPI_bridge_PCIe R425_SPI_bridge_PCIe R426_SPI_bridge_PCIe R602_SPI_bridge_PCIe R603_SPI_bridge_PCIe R604_SPI_bridge_PCIe R605_SPI_bridge_PCIe R606_SPI_bridge_PCIe R887_SPI_bridge_PCIe R888_SPI_bridge_PCIe R889_SPI_bridge_PCIe R890_SPI_bridge_PCIe R891_SPI_bridge_PCIe R892_SPI_bridge_PCIe R893_SPI_bridge_PCIe R894_SPI_bridge_PCIe R895_SPI_bridge_PCIe R896_SPI_bridge_PCIe R897_SPI_bridge_PCIe R898_SPI_bridge_PCIe R899_SPI_bridge_PCIe TP50_SPI_bridge_PCIe TP51_SPI_bridge_PCIe TP52_SPI_bridge_PCIe TP53_SPI_bridge_PCIe TP54_SPI_bridge_PCIe TP55_SPI_bridge_PCIe TP56_SPI_bridge_PCIe TP57_SPI_bridge_PCIe TP58_SPI_bridge_PCIe TP59_SPI_bridge_PCIe U24_SPI_bridge_PCIe U25_SPI_bridge_PCIe U26_SPI_bridge_PCIe U27_SPI_bridge_PCIe U28_SPI_bridge_PCIe
component class SFP3: C215 C216 C217 C218 J35 L7 L8 R155 R156 R157 R158 R161 R162 R163 R164
component class SFP2: C211 C212 C213 C214 J34 L5 L6 R145 R146 R147 R148 R151 R152 R153 R154
component class SFP1: C207 C208 C209 C210 J33 L3 L4 R135 R136 R137 R138 R141 R142 R143 R144
component class Ram: C36 R31 R32 R33 R34 R35 R36 R37 R38 R39 R40 R41 R42 R43 R44 R45 R46 R47 R48 R49 R50 R51 R52 R53 R54 R55 R56 R57 R58 R59 R60 R61 R62 R63 R64 R920 U8 U9 U10 U11
component class Power4HighSpeed: R174 R175 R176 R177 R178 R179 R180 R181 R182 R183 R184 R185 R186 R187 R188 R189 R190 R191 R192 R193 R194 R195 R196 R197 R198 R199 R200 R201 R202 R203 R204 R205 R206 R207 R208 R209 R210 R211 R213 R215 R217 R219 R221 R222 R228 U17 U20 U21 U22 U23
component class I2C_Expander_SFP: C311_I2C_Expander_SFP U35_I2C_Expander_SFP
component class Ext_GPIO_Bank1: R516 R517 R518 R519 R520 R521 R524 R525 R526 R527 R528 R529 R697 R698 R699 R700 R701 R702
component class HiCurrent: C331 C332 R14 R16 R22 R24 R266 R267 R269 R304 R388 R389 R390 R561 R562 R563 R564 R565 R566 R567 R568 R569 R570 R571 R572 R573 R574 R575 R576 R577 R578 R579 R580 R581 R582 R583 R584 R585 R586 R587 R588 R589 R590 R591 R592 S5 U18
component class PCIE4: D1_PCIE4 F1_PCIE4 J1_PCIE4 MP1_PCIE4 MP2_PCIE4 MP3_PCIE4
component class PCIE3: D1_PCIE3 F1_PCIE3 J1_PCIE3 MP1_PCIE3 MP2_PCIE3 MP3_PCIE3
component class PCIE2: D1_PCIE2 F1_PCIE2 J1_PCIE2 MP1_PCIE2 MP2_PCIE2 MP3_PCIE2
component class PCIE1: D1_PCIE1 F1_PCIE1 J1_PCIE1 MP1_PCIE1 MP2_PCIE1 MP3_PCIE1
component class PCIE0: D1_PCIE0 F1_PCIE0 J1_PCIE0 MP1_PCIE0 MP2_PCIE0 MP3_PCIE0
component class LTC6952_1: C49 C50 C51 C52 J4 J5 J6 J7 R270 R534 R535 R536 U13
channel class PCIe: PCIE0 PCIE1 PCIE2 PCIE3 PCIE4
channel class I2C_Bridge: I2C_Bridge_PCIE I2C_Bridge_SFP
component class "Bank 226": U1
component class SFP0: C37 C38 C39 C40 J32 L1 L2 R65 R66 R67 R68 R71 R72 R73 R74
component class I2C_Bridge_SFP: C303_I2C_Bridge_SFP R3_I2C_Bridge_SFP R4_I2C_Bridge_SFP R5_I2C_Bridge_SFP R6_I2C_Bridge_SFP R7_I2C_Bridge_SFP R8_I2C_Bridge_SFP R9_I2C_Bridge_SFP R10_I2C_Bridge_SFP R223_I2C_Bridge_SFP R224_I2C_Bridge_SFP R225_I2C_Bridge_SFP R226_I2C_Bridge_SFP R227_I2C_Bridge_SFP R558_I2C_Bridge_SFP R559_I2C_Bridge_SFP R560_I2C_Bridge_SFP TP1_I2C_Bridge_SFP TP2_I2C_Bridge_SFP TP3_I2C_Bridge_SFP TP4_I2C_Bridge_SFP TP5_I2C_Bridge_SFP TP6_I2C_Bridge_SFP TP7_I2C_Bridge_SFP TP8_I2C_Bridge_SFP TP9_I2C_Bridge_SFP TP10_I2C_Bridge_SFP TP11_I2C_Bridge_SFP TP12_I2C_Bridge_SFP TP13_I2C_Bridge_SFP TP14_I2C_Bridge_SFP TP15_I2C_Bridge_SFP TP16_I2C_Bridge_SFP TP17_I2C_Bridge_SFP TP18_I2C_Bridge_SFP U3_I2C_Bridge_SFP
component class I2C_Bridge_PCIE: C303_I2C_Bridge_PCIE R3_I2C_Bridge_PCIE R4_I2C_Bridge_PCIE R5_I2C_Bridge_PCIE R6_I2C_Bridge_PCIE R7_I2C_Bridge_PCIE R8_I2C_Bridge_PCIE R9_I2C_Bridge_PCIE R10_I2C_Bridge_PCIE R223_I2C_Bridge_PCIE R224_I2C_Bridge_PCIE R225_I2C_Bridge_PCIE R226_I2C_Bridge_PCIE R227_I2C_Bridge_PCIE R558_I2C_Bridge_PCIE R559_I2C_Bridge_PCIE R560_I2C_Bridge_PCIE TP1_I2C_Bridge_PCIE TP2_I2C_Bridge_PCIE TP3_I2C_Bridge_PCIE TP4_I2C_Bridge_PCIE TP5_I2C_Bridge_PCIE TP6_I2C_Bridge_PCIE TP7_I2C_Bridge_PCIE TP8_I2C_Bridge_PCIE TP9_I2C_Bridge_PCIE TP10_I2C_Bridge_PCIE TP11_I2C_Bridge_PCIE TP12_I2C_Bridge_PCIE TP13_I2C_Bridge_PCIE TP14_I2C_Bridge_PCIE TP15_I2C_Bridge_PCIE TP16_I2C_Bridge_PCIE TP17_I2C_Bridge_PCIE TP18_I2C_Bridge_PCIE U3_I2C_Bridge_PCIE
differential pair Bank225_MGTREF1: +Bank225_MGTREF1_P -Bank225_MGTREF1_N
differential pair Bank225_MGTREF0: +Bank225_MGTREF0_P -Bank225_MGTREF0_N
differential pair Bank224_MGTREF1: +Bank224_MGTREF1_P -Bank224_MGTREF1_N
differential pair Bank224_MGTREF0: +Bank224_MGTREF0_P -Bank224_MGTREF0_N
differential pair Bank223_MGTREF1: +Bank223_MGTREF1_P -Bank223_MGTREF1_N
differential pair Bank223_MGTREF0: +Bank223_MGTREF0_P -Bank223_MGTREF0_N
differential pair B225_Tx3_to_C: +B225_Tx3_to_C_P -B225_Tx3_to_C_N
differential pair B225_Tx2_to_C: +B225_Tx2_to_C_P -B225_Tx2_to_C_N
differential pair B225_Tx1_to_C: +B225_Tx1_to_C_P -B225_Tx1_to_C_N
differential pair B225_Tx0_to_C: +B225_Tx0_to_C_P -B225_Tx0_to_C_N
differential pair B225_Rx3: +B225_Rx3_P -B225_Rx3_N
differential pair B225_Rx2: +B225_Rx2_P -B225_Rx2_N
differential pair B225_Rx1: +B225_Rx1_P -B225_Rx1_N
differential pair B225_Rx0: +B225_Rx0_P -B225_Rx0_N
differential pair B224_Tx3_to_C: +B224_Tx3_to_C_P -B224_Tx3_to_C_N
differential pair B224_Tx2_to_C: +B224_Tx2_to_C_P -B224_Tx2_to_C_N
differential pair B224_Tx1_to_C: +B224_Tx1_to_C_P -B224_Tx1_to_C_N
differential pair B224_Tx0_to_C: +B224_Tx0_to_C_P -B224_Tx0_to_C_N
differential pair B224_Rx3: +B224_Rx3_P -B224_Rx3_N
differential pair B224_Rx2: +B224_Rx2_P -B224_Rx2_N
differential pair B224_Rx1: +B224_Rx1_P -B224_Rx1_N
differential pair B224_Rx0: +B224_Rx0_P -B224_Rx0_N
differential pair B223_Tx3_to_C: +B223_Tx3_to_C_P -B223_Tx3_to_C_N
differential pair B223_Tx2_to_C: +B223_Tx2_to_C_P -B223_Tx2_to_C_N
differential pair B223_Tx1_to_C: +B223_Tx1_to_C_P -B223_Tx1_to_C_N
differential pair B223_Tx0_to_C: +B223_Tx0_to_C_P -B223_Tx0_to_C_N
differential pair B223_Rx3: +B223_Rx3_P -B223_Rx3_N
differential pair B223_Rx2: +B223_Rx2_P -B223_Rx2_N
differential pair B223_Rx1: +B223_Rx1_P -B223_Rx1_N
differential pair B223_Rx0: +B223_Rx0_P -B223_Rx0_N
differential pair NVME_C_RX_1: +NVME_C_RX_1_P -NVME_C_RX_1_N
differential pair LTC6952_1_VCO: +LTC6952_1_VCO_P -LTC6952_1_VCO_N
differential pair LTC6952_1_Out10: +LTC6952_1_Out10_P -LTC6952_1_Out10_N
differential pair LTC6952_1_Out9: +LTC6952_1_Out9_P -LTC6952_1_Out9_N
differential pair LTC6952_1_Out8: +LTC6952_1_Out8_P -LTC6952_1_Out8_N
differential pair LTC6952_1_Out7: +LTC6952_1_Out7_P -LTC6952_1_Out7_N
differential pair LTC6952_1_Out6: +LTC6952_1_Out6_P -LTC6952_1_Out6_N
differential pair LTC6952_1_Out5: +LTC6952_1_Out5_P -LTC6952_1_Out5_N
differential pair LTC6952_1_Out4: +LTC6952_1_Out4_P -LTC6952_1_Out4_N
differential pair LTC6952_1_Out3: +LTC6952_1_Out3_P -LTC6952_1_Out3_N
differential pair LTC6952_1_Out2: +LTC6952_1_Out2_P -LTC6952_1_Out2_N
differential pair LTC6952_1_Out1: +LTC6952_1_Out1_P -LTC6952_1_Out1_N
differential pair LTC6952_1_Out0: +LTC6952_1_Out0_P -LTC6952_1_Out0_N
differential pair LTC6952_1_C: +LTC6952_1_C_P -LTC6952_1_C_N
differential pair LTC6952_1_C_Out10: +LTC6952_1_C_Out10_P -LTC6952_1_C_Out10_N
differential pair LTC6952_0_REF: +LTC6952_0_REF_P -LTC6952_0_REF_N
differential pair LTC6952_0_Out10: +LTC6952_0_Out10_P -LTC6952_0_Out10_N
differential pair LTC6952_0_Out9: +LTC6952_0_Out9_P -LTC6952_0_Out9_N
differential pair LTC6952_0_Out8: +LTC6952_0_Out8_P -LTC6952_0_Out8_N
differential pair LTC6952_0_Out7: +LTC6952_0_Out7_P -LTC6952_0_Out7_N
differential pair LTC6952_0_Out6: +LTC6952_0_Out6_P -LTC6952_0_Out6_N
differential pair LTC6952_0_Out5: +LTC6952_0_Out5_P -LTC6952_0_Out5_N
differential pair LTC6952_0_Out4: +LTC6952_0_Out4_P -LTC6952_0_Out4_N
differential pair LTC6952_0_Out3: +LTC6952_0_Out3_P -LTC6952_0_Out3_N
differential pair LTC6952_0_Out2: +LTC6952_0_Out2_P -LTC6952_0_Out2_N
differential pair LTC6952_0_Out1: +LTC6952_0_Out1_P -LTC6952_0_Out1_N
differential pair LTC6952_0_Out0: +LTC6952_0_Out0_P -LTC6952_0_Out0_N
differential pair USB_TX: +USB_TX_P -USB_TX_N
differential pair USB_TX_C: +USB_TX_C_P -USB_TX_C_N
differential pair USB_RX: +USB_RX_P -USB_RX_N
differential pair USB_RX_C: +USB_RX_C_P -USB_RX_C_N
differential pair USB_D: +USB_D_P -USB_D_N
differential pair TD_D: +TD_D_P -TD_D_N
differential pair TD_C: +TD_C_P -TD_C_N
differential pair TD_B: +TD_B_P -TD_B_N
differential pair TD_A: +TD_A_P -TD_A_N
differential pair SGMI_Tx: +SGMI_Tx_P -SGMI_Tx_N
differential pair SGMI_Rx: +SGMI_Rx_P -SGMI_Rx_N
differential pair SGMI_C_Tx: +SGMI_C_Tx_P -SGMI_C_Tx_N
differential pair SGMI_C_Rx: +SGMI_C_Rx_P -SGMI_C_Rx_N
differential pair NVMe_Tx_1: +NVMe_Tx_1_P -NVMe_Tx_1_N
differential pair NVMe_Tx_0: +NVMe_Tx_0_P -NVMe_Tx_0_N
differential pair NVMe_Rx_1: +NVMe_Rx_1_P -NVMe_Rx_1_N
differential pair NVMe_Rx_0: +NVMe_Rx_0_P -NVMe_Rx_0_N
differential pair DDR4_DQS_8: +DDR4_DQS_8_P -DDR4_DQS_8_N
differential pair DDR4_DQS_4: +DDR4_DQS_4_P -DDR4_DQS_4_N
differential pair NVME_C_TX_O: +NVME_C_TX_O_P -NVME_C_TX_O_N
differential pair NVME_C_TX_1: +NVME_C_TX_1_P -NVME_C_TX_1_N
differential pair NVME_C_RX_O: +NVME_C_RX_O_P -NVME_C_RX_O_N
differential pair WR_LMK_CLK_IN: +WR_LMK_CLK_IN_P -WR_LMK_CLK_IN_N
differential pair WR_LMK_CLK_HF2: +WR_LMK_CLK_HF2_P -WR_LMK_CLK_HF2_N
differential pair WR_LMK_CLK_HF1: +WR_LMK_CLK_HF1_P -WR_LMK_CLK_HF1_N
differential pair LTC6952_1_REF: +LTC6952_1_REF_P -LTC6952_1_REF_N
differential pair Si53323_2_Q2_LVDS: +Si53323_2_Q2_LVDS_P -Si53323_2_Q2_LVDS_N
differential pair Si53323_1_Q2_LVDS: +Si53323_1_Q2_LVDS_P -Si53323_1_Q2_LVDS_N
differential pair Si53323_2_CLK1: +Si53323_2_CLK1_P -Si53323_2_CLK1_N
differential pair OSC_Out_DIV: +OSC_Out_DIV_P -OSC_Out_DIV_N
differential pair Osc_in_Si53323_2: +Osc_in_Si53323_2_P -Osc_in_Si53323_2_N
differential pair CLK_SMA0_C: +CLK_SMA0_C_P -CLK_SMA0_C_N
differential pair DDR4_DQS_7: +DDR4_DQS_7_P -DDR4_DQS_7_N
differential pair DDR4_DQS_6: +DDR4_DQS_6_P -DDR4_DQS_6_N
differential pair DDR4_DQS_5: +DDR4_DQS_5_P -DDR4_DQS_5_N
differential pair DDR4_DQS_3: +DDR4_DQS_3_P -DDR4_DQS_3_N
differential pair DDR4_DQS_2: +DDR4_DQS_2_P -DDR4_DQS_2_N
differential pair DDR4_DQS_1: +DDR4_DQS_1_P -DDR4_DQS_1_N
differential pair DDR4_DQS_0: +DDR4_DQS_0_P -DDR4_DQS_0_N
differential pair DDR4_CK: +DDR4_CK_P -DDR4_CK_N
differential pair Si53323_2_Q2: +Si53323_2_Q2_P -Si53323_2_Q2_N
differential pair Si53323_2_Q1: +Si53323_2_Q1_P -Si53323_2_Q1_N
differential pair Si53323_1_Q2: +Si53323_1_Q2_P -Si53323_1_Q2_N
differential pair Si53323_1_Q1: +Si53323_1_Q1_P -Si53323_1_Q1_N
differential pair RefClk_Si53323: +RefClk_Si53323_P -RefClk_Si53323_N
differential pair Bank505_MGTRREF3_C: +Bank505_MGTRREF3_C_P -Bank505_MGTRREF3_C_N
differential pair Bank505_MGTRREF2_C: +Bank505_MGTRREF2_C_P -Bank505_MGTRREF2_C_N
differential pair Bank505_MGTRREF0_C: +Bank505_MGTRREF0_C_P -Bank505_MGTRREF0_C_N
differential pair Bank225_MGTREF1_C: +Bank225_MGTREF1_C_P -Bank225_MGTREF1_C_N
differential pair Bank225_MGTREF0_C: +Bank225_MGTREF0_C_P -Bank225_MGTREF0_C_N
differential pair Bank224_MGTREF1_C: +Bank224_MGTREF1_C_P -Bank224_MGTREF1_C_N
differential pair Bank224_MGTREF0_C: +Bank224_MGTREF0_C_P -Bank224_MGTREF0_C_N
differential pair Bank223_MGTREF1_C: +Bank223_MGTREF1_C_P -Bank223_MGTREF1_C_N
differential pair Bank223_MGTREF0_C: +Bank223_MGTREF0_C_P -Bank223_MGTREF0_C_N
differential pair SFP3_Tx: +SFP3_Tx_P -SFP3_Tx_N
differential pair SFP3_Rx: +SFP3_Rx_P -SFP3_Rx_N
differential pair SFP2_Tx: +SFP2_Tx_P -SFP2_Tx_N
differential pair SFP2_Rx: +SFP2_Rx_P -SFP2_Rx_N
differential pair SFP1_Tx: +SFP1_Tx_P -SFP1_Tx_N
differential pair SFP1_Rx: +SFP1_Rx_P -SFP1_Rx_N
differential pair SFP0_Tx: +SFP0_Tx_P -SFP0_Tx_N
differential pair SFP0_Rx: +SFP0_Rx_P -SFP0_Rx_N
differential pair B225_Tx3C_to_B: +B225_Tx3C_to_B_P -B225_Tx3C_to_B_N
differential pair B225_Tx2C_to_B: +B225_Tx2C_to_B_P -B225_Tx2C_to_B_N
differential pair B225_Tx1C_to_B: +B225_Tx1C_to_B_P -B225_Tx1C_to_B_N
differential pair B225_Tx0C_to_B: +B225_Tx0C_to_B_P -B225_Tx0C_to_B_N
differential pair B224_Tx3C_to_B: +B224_Tx3C_to_B_P -B224_Tx3C_to_B_N
differential pair B224_Tx2C_to_B: +B224_Tx2C_to_B_P -B224_Tx2C_to_B_N
differential pair B224_Tx1C_to_B: +B224_Tx1C_to_B_P -B224_Tx1C_to_B_N
differential pair B224_Tx0C_to_B: +B224_Tx0C_to_B_P -B224_Tx0C_to_B_N
differential pair B223_Tx3C_to_B: +B223_Tx3C_to_B_P -B223_Tx3C_to_B_N
differential pair B223_Tx2C_to_B: +B223_Tx2C_to_B_P -B223_Tx2C_to_B_N
differential pair B223_Tx1C_to_B: +B223_Tx1C_to_B_P -B223_Tx1C_to_B_N
differential pair B223_Tx0C_to_B: +B223_Tx0C_to_B_P -B223_Tx0C_to_B_N

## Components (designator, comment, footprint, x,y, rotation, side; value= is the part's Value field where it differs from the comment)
B1 "TS920E-FL27E" Battery 253.457,320.027 r0 top
BT1 "79523141" 79523141 107.671,702.424 r0 top
C1 "100nF" "CAP 0402/1005 RF" 293.459,232.569 r90 top
C2 "100nF" "CAP 0402/1005 RF" 294.691,232.573 r90 top
C3 "100nF" "CAP 0402/1005 RF" 361.721,218.211 r0 top
C4 "22uF" "CAP 1210/3225 - 1MM" 37.591,170.893 r180 top
C5 "22uF" "CAP 1210/3225 - 1MM" 37.591,174.348 r180 top
C6 "22uF" "CAP 1210/3225 - 1MM" 37.591,181.257 r180 top
C7 "22uF" "CAP 1210/3225 - 1MM" 37.591,177.802 r180 top
C8 "100nF" "CAP 0402/1005 RF" 39.985,159.376 r270 top
C9 "100nF" "CAP 0402/1005 RF" 42.83,159.376 r270 top
C10 "100nF" "CAP 0402/1005 RF" 41.901,159.376 r270 top
C11 "100nF" "CAP 0402/1005 RF" 40.965,159.376 r270 top
C12 "22uF" "CAP 1210/3225 - 1MM" 37.51,184.916 r180 top
C13 "22uF" "CAP 1210/3225 - 1MM" 37.51,191.806 r180 top
C14 "22uF" "CAP 1210/3225 - 1MM" 37.51,195.251 r180 top
C15 "22uF" "CAP 1210/3225 - 1MM" 37.51,188.361 r180 top
C16 "100nF" "CAP 0402/1005 RF" 18.529,198.266 r270 top
C17 "100nF" "CAP 0402/1005 RF" 21.364,198.266 r270 top
C18 "100nF" "CAP 0402/1005 RF" 20.365,198.266 r270 top
C19 "100nF" "CAP 0402/1005 RF" 19.46,198.266 r270 top
C20 "10uF" "CAP 0805/2012 RF" 55.719,164.138 r180 top
C21 "10uF" "CAP 0805/2012 RF" 55.746,169.941 r180 top
C22 "10uF" "CAP 0805/2012 RF" 55.746,168.043 r180 top
C23 "10uF" "CAP 0805/2012 RF" 55.746,175.635 r180 top
C24 "4.7uF" "CAP 0805/2012 RF" 55.746,171.839 r180 top
C25 "4.7uF" "CAP 0805/2012 RF" 55.746,173.737 r180 top
C26 "4.7uF" "CAP 0805/2012 RF" 55.746,177.532 r180 top
C27 "4.7uF" "CAP 0805/2012 RF" 55.746,166.145 r180 top
C28 "10uF" "CAP 0805/2012 RF" 55.758,187.161 r180 top
C29 "10uF" "CAP 0805/2012 RF" 55.758,185.263 r180 top
C30 "10uF" "CAP 0805/2012 RF" 55.758,181.467 r180 top
C31 "10uF" "CAP 0805/2012 RF" 55.758,179.569 r180 top
C32 "4.7uF" "CAP 0805/2012 RF" 55.758,183.365 r180 top
C33 "4.7uF" "CAP 0805/2012 RF" 55.758,189.059 r180 top
C34 "4.7uF" "CAP 0805/2012 RF" 55.758,190.956 r180 top
C35 "4.7uF" "CAP 0805/2012 RF" 55.784,192.899 r180 top
C36 "10nF" "CAP 0402/1005 RF" 155.956,331.965 r180 top
C37 "100nF" "CAP 0402/1005 RF" 29.299,264.312 r0 top
C38 "22uF" "CAP 1210/3225 - 1MM" 33.871,263.55 r0 top
C39 "100nF" "CAP 0402/1005 RF" 38.57,263.423 r0 top
C40 "22uF" "CAP 1210/3225 - 1MM" 33.923,266.979 r0 top
C41 "100nF" "CAP 0402/1005 RF" 90.054,258.034 r270 top
C42 "100nF" "CAP 0402/1005 RF" 90.954,258.034 r270 top
C43 "1uF" "CAP 0402/1005 RF" 110.881,257.529 r270 top
C44 "1uF" "CAP 0402/1005 RF" 109.981,257.529 r270 top
C45 "5.6nF" "CAP 0402/1005 RF" 69.509,560.387 r270 top
C46 "200pF" "CAP 0402/1005 RF" 68.609,560.387 r270 top
C47 "1uF" "CAP 0402/1005 RF" 83.174,514.122 r0 top
C48 "1uF" "CAP 0402/1005 RF" 81.494,514.122 r180 top
C49 "1uF" "CAP 0402/1005 RF" 39.677,414.757 r0 top
C50 "1uF" "CAP 0402/1005 RF" 37.997,414.757 r180 top
C51 "1uF" "CAP 0402/1005 RF" 396.755,280.797 r0 top
C52 "1uF" "CAP 0402/1005 RF" 395.075,280.797 r180 top
C55 "0.1µF" "CAP 0201/0603 RF" 100.292,283.421 r90 top
C56 "0.1µF" "CAP 0201/0603 RF" 98.387,283.421 r90 top
C57 "0.1µF" "CAP 0201/0603 RF" 97.244,281.77 r270 top
C58 "10µF" "CAP 0402/1005 RF" 98.387,281.776 r270 top
C59 "0.1µF" "CAP 0201/0603 RF" 82.594,580.442 r90 top
C60 "0.1µF" "CAP 0201/0603 RF" 81.705,580.442 r90 top
C61 "0.1µF" "CAP 0201/0603 RF" 78.264,583.759 r90 top
C62 "10µF" "CAP 0402/1005 RF" 76.991,583.629 r90 top
C63 "100nF" "CAP 0402/1005 RF" 143.193,572.212 r270 top
C64 "100nF" "CAP 0402/1005 RF" 152.32,575.768 r0 top
C65 "0.1µF" "CAP 0201/0603 RF" 101.181,283.427 r90 top
C66 "0.1µF" "CAP 0201/0603 RF" 97.498,283.427 r90 top
C67 "100nF" "CAP 0402/1005 RF" 146.583,575.768 r270 top
C68 "10nF" "CAP 0201/0603 RF" 101.689,281.776 r270 top
C69 "10µF" "CAP 0402/1005 RF" 100.292,281.776 r270 top
C70 "100nF" "CAP 0402/1005 RF" 144.083,572.212 r270 top
C71 "0.1µF" "CAP 0201/0603 RF" 78.657,580.453 r0 top
C72 "0.1µF" "CAP 0201/0603 RF" 78.524,581.342 r0 top
C73 "0.1µF" "CAP 0201/0603 RF" 77.251,580.453 r180 top
C74 "10µF" "CAP 0402/1005 RF" 77.641,579.057 r180 top
C75 "100nF" "CAP 0402/1005 RF" 154.334,580.652 r0 top
C76 "100nF" "CAP 0402/1005 RF" 154.334,582.88 r0 top
C77 "100nF" "CAP 0402/1005 RF" 138.713,581.152 r180 top
C78 "10uF" "CAP 0402/1005 RF" 145.583,575.768 r90 top
C79 "10uF" "CAP 0402/1005 RF" 147.083,591.311 r270 top
C80 "10uF" "CAP 0402/1005 RF" 140.678,591.311 r270 top
C81 "100nF" "CAP 0402/1005 RF" 138.713,579.152 r180 top
C82 "100nF" "CAP 0402/1005 RF" 154.334,585.152 r0 top
C83 "100nF" "CAP 0402/1005 RF" 138.713,585.999 r180 top
C84 "0.1µF" "CAP 0201/0603 RF" 76.244,575.755 r90 top
C85 "0.1µF" "CAP 0201/0603 RF" 83.356,580.442 r90 top
C86 "10nF" "CAP 0201/0603 RF" 77.26,575.76 r90 top
C87 "10µF" "CAP 0402/1005 RF" 78.403,575.76 r90 top
C88 "100nF" "CAP 0402/1005 RF" 138.713,586.999 r180 top
C89 "100nF" "CAP 0402/1005 RF" 148.083,591.311 r90 top
C90 "100nF" "CAP 0402/1005 RF" 145.143,591.311 r90 top
C91 "100nF" "CAP 0402/1005 RF" 146.083,591.311 r90 top
C92 "100nF" "CAP 0402/1005 RF" 154.334,579.652 r0 top
C93 "100nF" "CAP 0402/1005 RF" 146.079,572.212 r270 top
C94 "0.1µF" "CAP 0201/0603 RF" 84.118,580.448 r90 top
C95 "0.1µF" "CAP 0201/0603 RF" 80.816,580.448 r90 top
C96 "100nF" "CAP 0402/1005 RF" 141.678,591.311 r90 top
C97 "10nF" "CAP 0201/0603 RF" 79.419,582.603 r90 top
C98 "10µF" "CAP 0402/1005 RF" 80.308,582.603 r90 top
C99 "100nF" "CAP 0402/1005 RF" 137.63,572.281 r90 top
C100 "100nF" "CAP 0402/1005 RF" 161.827,584.635 r90 top
C101 "10uF" "CAP 0402/1005 RF" 141.44,572.29 r90 top
C102 "10uF" "CAP 0402/1005 RF" 157.881,584.635 r90 top
C103 "100nF" "CAP 0402/1005 RF" 152.32,570.817 r180 top
C104 "100nF" "CAP 0402/1005 RF" 132.862,585.042 r90 top
C105 "10uF" "CAP 0402/1005 RF" 152.32,574.763 r180 top
C106 "10uF" "CAP 0402/1005 RF" 136.808,585.042 r90 top
C107 "100nF" "CAP 0402/1005 RF" 147.862,566.361 r180 top
C108 "100nF" "CAP 0402/1005 RF" 137.621,593.644 r0 top
C109 "10uF" "CAP 0402/1005 RF" 147.862,570.307 r180 top
C110 "10uF" "CAP 0402/1005 RF" 137.621,589.698 r0 top
C111 "10nF" "CAP 0201/0603 RF" 244.752,167.951 r90 top
C112 "10nF" "CAP 0201/0603 RF" 245.979,167.951 r90 top
C113 "10nF" "CAP 0201/0603 RF" 250.89,167.951 r90 top
C114 "10nF" "CAP 0201/0603 RF" 254.573,167.951 r90 top
C115 "10nF" "CAP 0201/0603 RF" 255.801,167.951 r90 top
C116 "10nF" "CAP 0201/0603 RF" 253.345,167.951 r90 top
C117 "10nF" "CAP 0201/0603 RF" 243.524,167.951 r90 top
C118 "10nF" "CAP 0201/0603 RF" 242.296,167.951 r90 top
C119 "10nF" "CAP 0201/0603 RF" 249.662,167.951 r90 top
C120 "10nF" "CAP 0201/0603 RF" 257.028,167.951 r90 top
C121 "10nF" "CAP 0201/0603 RF" 247.207,167.951 r90 top
C122 "10nF" "CAP 0201/0603 RF" 248.435,167.951 r90 top
C123 "10nF" "CAP 0201/0603 RF" 252.118,167.951 r90 top
C124 "100nF" "CAP 0402/1005 RF" 143.583,566.361 r180 top
C125 "100nF" "CAP 0402/1005 RF" 148.473,597.866 r180 top
C126 "10uF" "CAP 0402/1005 RF" 143.583,570.307 r180 top
C127 "10uF" "CAP 0402/1005 RF" 148.473,593.92 r180 top
C128 "1uF" "CAP 0402/1005 RF" 246.531,171.368 r90 top
C129 "1uF" "CAP 0402/1005 RF" 254.502,171.368 r90 top
C130 "1uF" "CAP 0402/1005 RF" 248.125,171.368 r90 top
C131 "1uF" "CAP 0402/1005 RF" 256.096,171.368 r90 top
C132 "1uF" "CAP 0402/1005 RF" 260.879,171.368 r90 top
C133 "1uF" "CAP 0402/1005 RF" 243.343,171.368 r90 top
C134 "1uF" "CAP 0402/1005 RF" 251.314,171.368 r90 top
C135 "1uF" "CAP 0402/1005 RF" 249.72,171.368 r90 top
C136 "1uF" "CAP 0402/1005 RF" 257.69,171.368 r90 top
C137 "1uF" "CAP 0402/1005 RF" 262.473,171.368 r90 top
C138 "1uF" "CAP 0402/1005 RF" 244.937,171.368 r90 top
C139 "1uF" "CAP 0402/1005 RF" 252.908,171.368 r90 top
C140 "1uF" "CAP 0402/1005 RF" 259.284,171.368 r90 top
C141 "100nF" "CAP 0402/1005 RF" 161.867,580.115 r270 top
C142 "100nF" "CAP 0402/1005 RF" 144.653,597.866 r0 top
C143 "10uF" "CAP 0402/1005 RF" 157.921,580.115 r270 top
C144 "10uF" "CAP 0402/1005 RF" 144.653,593.92 r0 top
C145 "100nF" "CAP 0402/1005 RF" 161.827,582.49 r90 top
C146 "100nF" "CAP 0402/1005 RF" 161.867,577.918 r270 top
C147 "10uF" "CAP 0402/1005 RF" 157.881,582.49 r90 top
C148 "10uF" "CAP 0402/1005 RF" 157.921,577.918 r270 top
C149 "10nF" "CAP 0201/0603 RF" 257.361,173.521 r90 top
C150 "10nF" "CAP 0201/0603 RF" 260.98,173.521 r90 top
C151 "10nF" "CAP 0201/0603 RF" 256.457,173.521 r90 top
C152 "10nF" "CAP 0201/0603 RF" 259.171,173.521 r90 top
C153 "10nF" "CAP 0201/0603 RF" 254.648,173.521 r90 top
C154 "10nF" "CAP 0201/0603 RF" 260.075,173.521 r90 top
C155 "10nF" "CAP 0201/0603 RF" 255.552,173.521 r90 top
C156 "10nF" "CAP 0201/0603 RF" 258.266,173.521 r90 top
C157 "10nF" "CAP 0201/0603 RF" 253.743,173.521 r90 top
C158 "10nF" "CAP 0201/0603 RF" 263.631,173.533 r90 top
C159 "10nF" "CAP 0201/0603 RF" 262.789,173.521 r90 top
C160 "10nF" "CAP 0201/0603 RF" 264.393,173.533 r90 top
C161 "10nF" "CAP 0201/0603 RF" 261.884,173.521 r90 top
C162 "100nF" "CAP 0402/1005 RF" 132.998,581.71 r270 top
C163 "100nF" "CAP 0402/1005 RF" 145.689,566.361 r180 top
C164 "10uF" "CAP 0402/1005 RF" 136.808,581.71 r90 top
C165 "10uF" "CAP 0402/1005 RF" 145.689,570.307 r180 top
C166 "10nF" "CAP 0201/0603 RF" 242.803,173.521 r90 top
C167 "10nF" "CAP 0201/0603 RF" 246.666,173.521 r90 top
C168 "10nF" "CAP 0201/0603 RF" 250.529,173.521 r90 top
C169 "10nF" "CAP 0201/0603 RF" 243.576,173.521 r90 top
C170 "10nF" "CAP 0201/0603 RF" 247.439,173.521 r90 top
C171 "10nF" "CAP 0201/0603 RF" 244.348,173.521 r90 top
C172 "10nF" "CAP 0201/0603 RF" 248.211,173.521 r90 top
C173 "10nF" "CAP 0201/0603 RF" 252.074,173.521 r90 top
C174 "10nF" "CAP 0201/0603 RF" 245.893,173.521 r90 top
C175 "10nF" "CAP 0201/0603 RF" 248.984,173.521 r90 top
C176 "10nF" "CAP 0201/0603 RF" 251.302,173.521 r90 top
C177 "10nF" "CAP 0201/0603 RF" 245.121,173.521 r90 top
C178 "10nF" "CAP 0201/0603 RF" 249.756,173.521 r90 top
C179 "100nF" "CAP 0402/1005 RF" 132.762,579.061 r90 top
C180 "10uF" "CAP 0402/1005 RF" 136.808,579.061 r90 top
C181 "1uF" "CAP 0402/1005 RF" 258.424,177.198 r90 top
C182 "1uF" "CAP 0402/1005 RF" 240.898,177.198 r90 top
C183 "1uF" "CAP 0402/1005 RF" 249.661,177.198 r90 top
C184 "1uF" "CAP 0402/1005 RF" 242.359,177.198 r90 top
C185 "1uF" "CAP 0402/1005 RF" 251.122,177.198 r90 top
C186 "1uF" "CAP 0402/1005 RF" 248.201,177.198 r90 top
C187 "1uF" "CAP 0402/1005 RF" 256.964,177.198 r90 top
C188 "1uF" "CAP 0402/1005 RF" 243.819,177.198 r90 top
C189 "1uF" "CAP 0402/1005 RF" 252.582,177.198 r90 top
C190 "1uF" "CAP 0402/1005 RF" 246.74,177.198 r90 top
C191 "1uF" "CAP 0402/1005 RF" 255.503,177.198 r90 top
C192 "1uF" "CAP 0402/1005 RF" 245.28,177.198 r90 top
C193 "1uF" "CAP 0402/1005 RF" 254.043,177.198 r90 top
C194 "1uF" "CAP 0402/1005 RF" 248.588,180.137 r90 top
C195 "1uF" "CAP 0402/1005 RF" 258.142,180.137 r90 top
C196 "1uF" "CAP 0402/1005 RF" 254.957,180.137 r90 top
C197 "1uF" "CAP 0402/1005 RF" 246.995,180.137 r90 top
C198 "1uF" "CAP 0402/1005 RF" 259.734,180.137 r90 top
C199 "1uF" "CAP 0402/1005 RF" 253.365,180.137 r90 top
C200 "1uF" "CAP 0402/1005 RF" 251.772,180.137 r90 top
C201 "1uF" "CAP 0402/1005 RF" 256.549,180.137 r90 top
C202 "1uF" "CAP 0402/1005 RF" 250.18,180.137 r90 top
C203 "1uF" "CAP 0402/1005 RF" 240.626,180.137 r90 top
C204 "1uF" "CAP 0402/1005 RF" 243.811,180.137 r90 top
C205 "1uF" "CAP 0402/1005 RF" 242.219,180.137 r90 top
C206 "1uF" "CAP 0402/1005 RF" 245.403,180.137 r90 top
C207 "100nF" "CAP 0402/1005 RF" 57.874,330.225 r0 top
C208 "22uF" "CAP 1210/3225 - 1MM" 63.716,329.082 r0 top
C209 "100nF" "CAP 0402/1005 RF" 68.415,330.225 r0 top
C210 "22uF" "CAP 1210/3225 - 1MM" 74.13,329.082 r0 top
C211 "100nF" "CAP 0402/1005 RF" 73.546,292.659 r180 top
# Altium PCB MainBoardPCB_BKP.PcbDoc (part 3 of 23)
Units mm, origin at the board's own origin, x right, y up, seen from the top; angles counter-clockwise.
Board outline 258.95 x 308.86 mm, 16 copper layers (L1, L2 (GND), L3 (Sign), L4 (GND), L5 (Sign), L6 (PWR/GND), L7(PWR/GND), L8 (Plane_GND), L9 (PWR/GND), L10 (PWR/GND), L11 (PWR/GND), L12 (Sign), L13 (GND), L14 (Sign), L15 (GND), L16), stack 2.502 mm thick; 2361 components, 1770 nets, 8410 pads, 3259 vias.
Unrouted connection lines stored in the file: 4700.

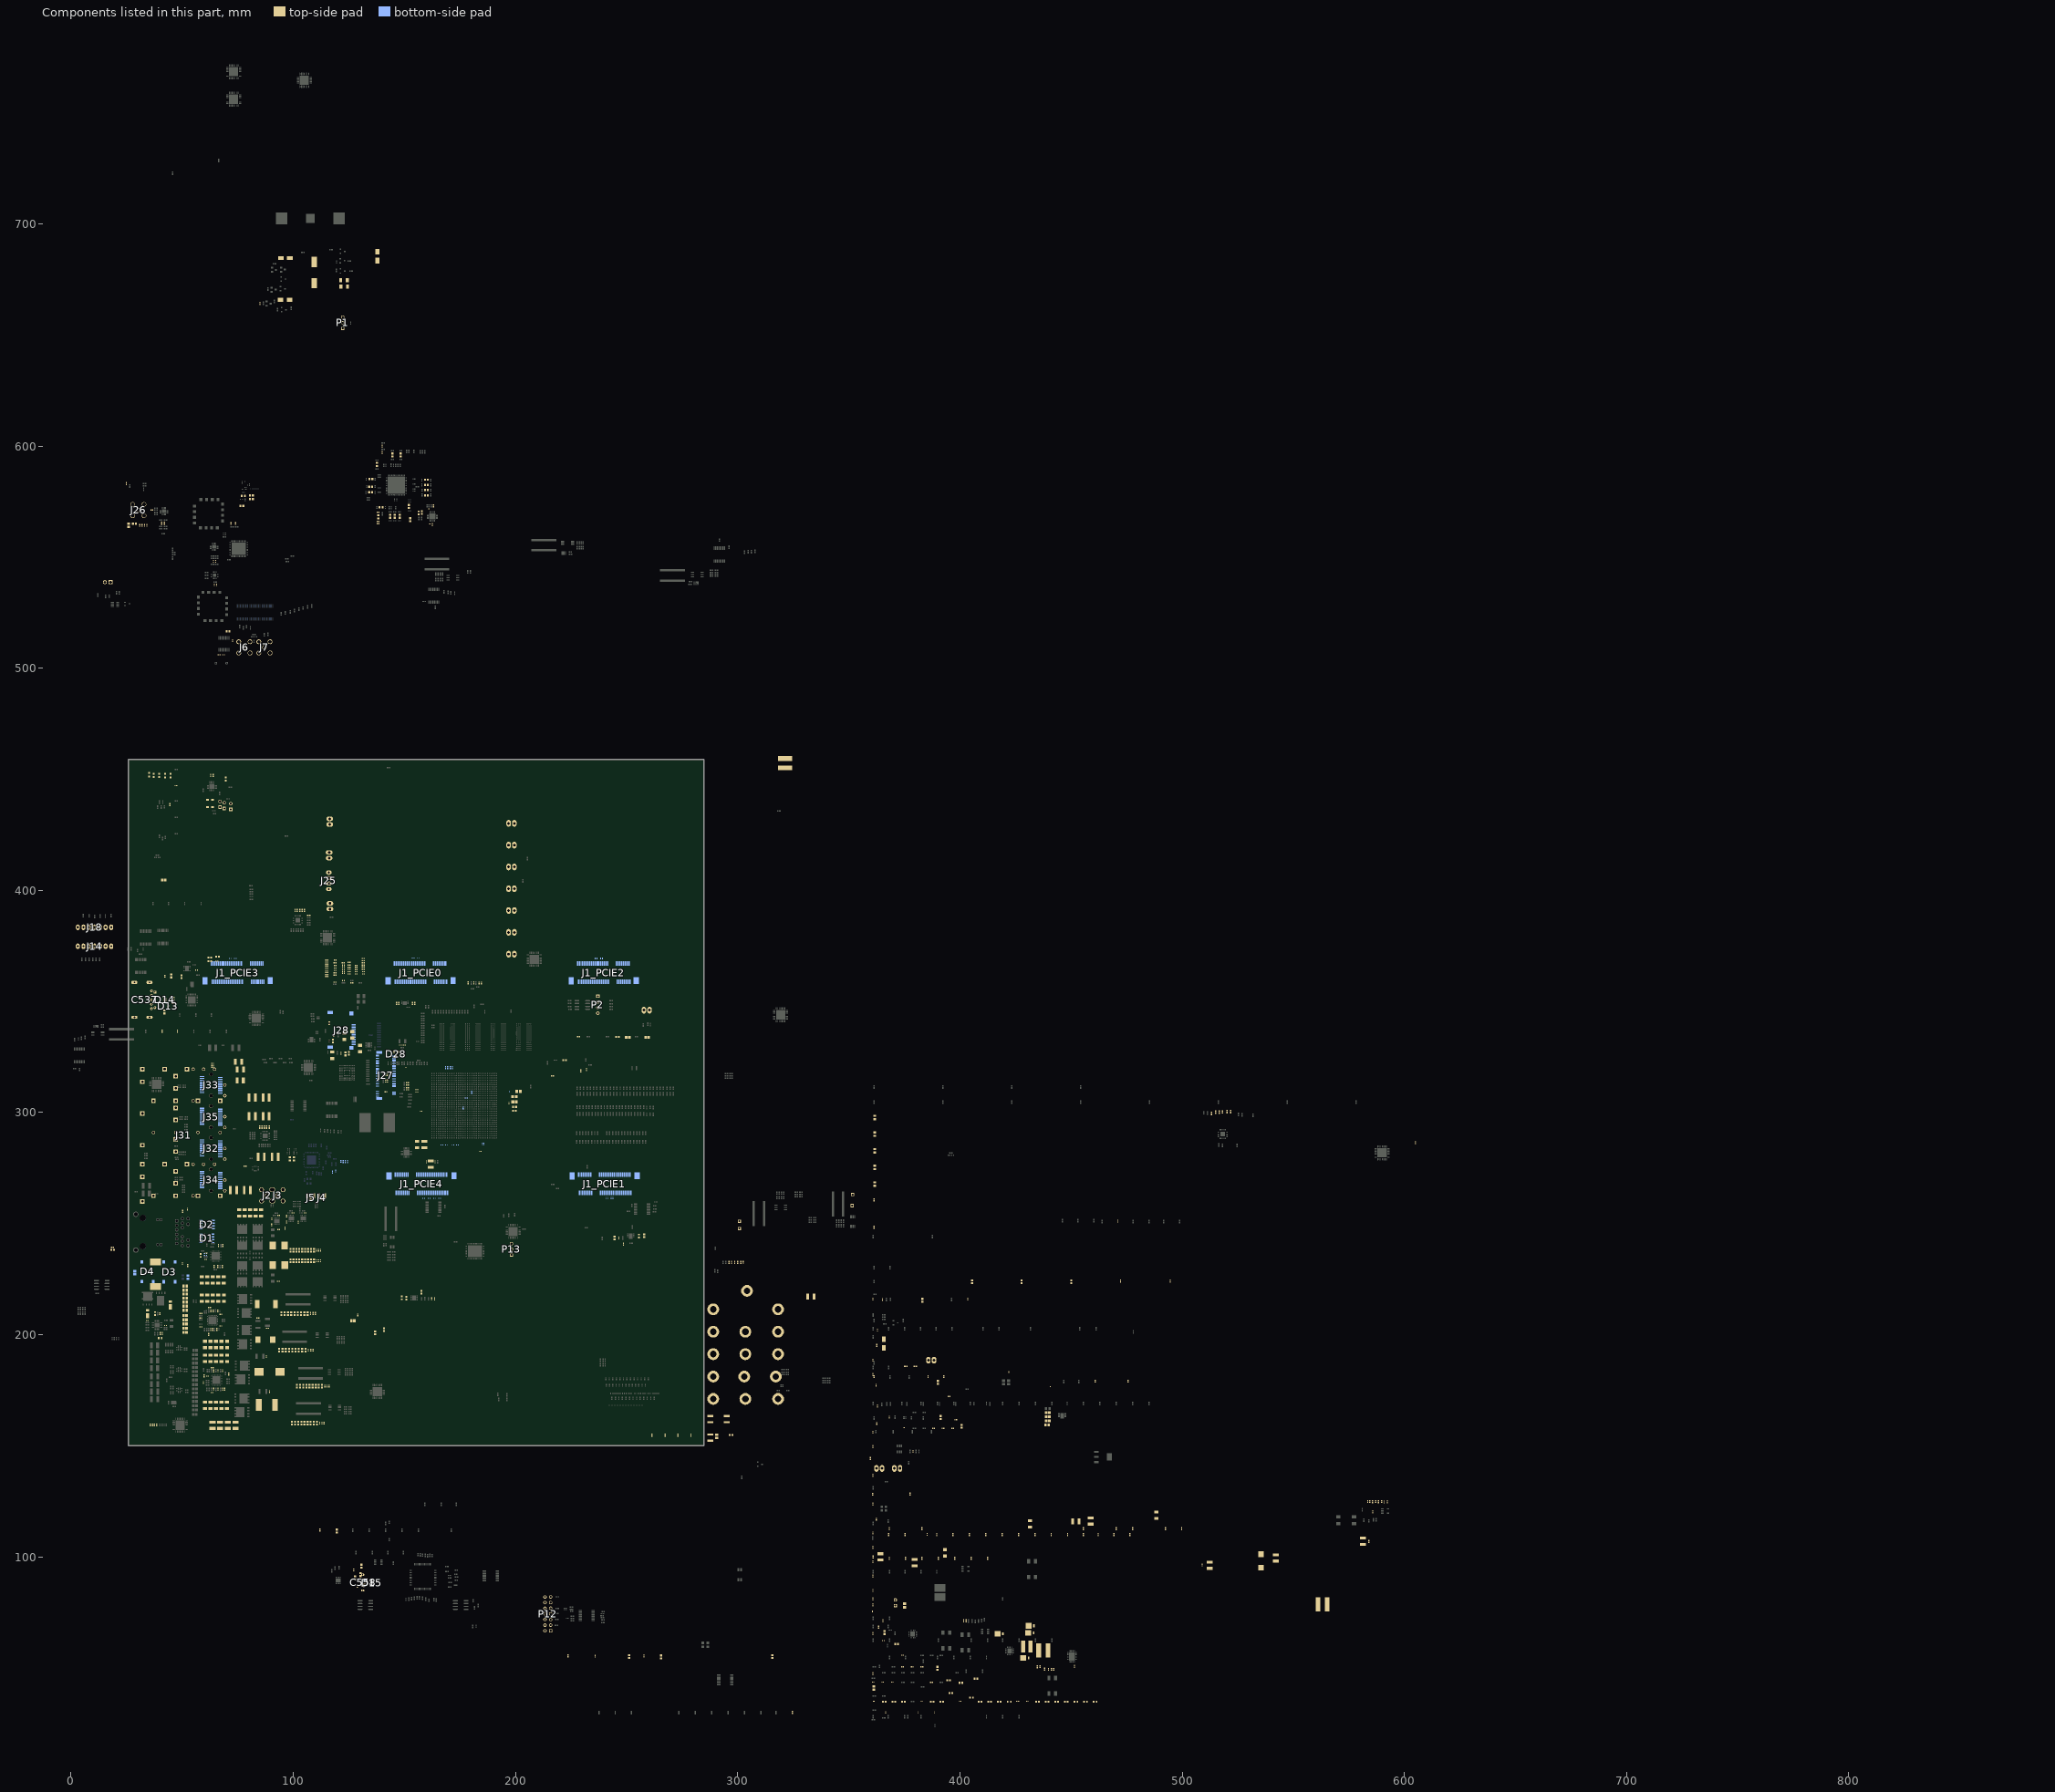
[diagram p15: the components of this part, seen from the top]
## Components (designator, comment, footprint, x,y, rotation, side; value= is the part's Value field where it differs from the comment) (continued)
C212 "22uF" "CAP 1210/3225 - 1MM" 332.956,217.068 r0 top
C213 "100nF" "CAP 0402/1005 RF" 63.716,320.358 r0 top
C214 "22uF" "CAP 1210/3225 - 1MM" 76.136,314.49 r0 top
C215 "100nF" "CAP 0402/1005 RF" 63.716,322.136 r0 top
C216 "22uF" "CAP 1210/3225 - 1MM" 75.387,322.91 r0 top
C217 "100nF" "CAP 0402/1005 RF" 63.716,321.247 r0 top
C218 "22uF" "CAP 1210/3225 - 1MM" 76.187,319.265 r0 top
C219 "100nF" "CAP 0402/1005 RF" 181.281,358.296 r90 top
C220 "100nF" "CAP 0402/1005 RF" 184.677,358.28 r90 top
C221 "100nF" "CAP 0402/1005 RF" 178.725,358.296 r90 top
C222 "100nF" "CAP 0402/1005 RF" 183.678,358.28 r90 top
C223 "4.7uF" "CAP 0402/1005 RF" 118.82,368.554 r0 top
C224 "470nF" "CAP 0402/1005 RF" 122.568,366.395 r0 top
C225 "470nF" "CAP 0402/1005 RF" 115.084,362.077 r0 top
C226 "68nF" "CAP 0402/1005 RF" 125.166,367.538 r0 top
C227 "68nF" "CAP 0402/1005 RF" 115.075,363.982 r0 top
C228 "4.7uF" "CAP 0402/1005 RF" 122.441,367.411 r0 top
C229 "470nF" "CAP 0402/1005 RF" 125.157,366.395 r0 top
C230 "470nF" "CAP 0402/1005 RF" 115.066,363.093 r0 top
C231 "68nF" "CAP 0402/1005 RF" 115.075,368.554 r0 top
C232 "68nF" "CAP 0402/1005 RF" 118.82,366.141 r0 top
C233 "4.7uF" "CAP 0402/1005 RF" 125.166,364.363 r0 top
C234 "470nF" "CAP 0402/1005 RF" 115.075,367.665 r0 top
C235 "470nF" "CAP 0402/1005 RF" 118.82,364.998 r0 top
C236 "68nF" "CAP 0402/1005 RF" 118.811,367.411 r0 top
C237 "68nF" "CAP 0402/1005 RF" 122.559,365.506 r0 top
C238 "4.7uF" "CAP 0402/1005 RF" 125.157,363.347 r0 top
C239 "470nF" "CAP 0402/1005 RF" 115.075,366.776 r0 top
C240 "470nF" "CAP 0402/1005 RF" 118.82,363.982 r0 top
C241 "68nF" "CAP 0402/1005 RF" 122.568,362.585 r0 top
C242 "68nF" "CAP 0402/1005 RF" 122.568,363.474 r0 top
C243 "100nF" "CAP 0402/1005 RF" 122.568,359.418 r0 top
C244 "100nF" "CAP 0402/1005 RF" 125.175,365.379 r180 top
C245 "100nF" "CAP 0402/1005 RF" 118.758,358.656 r0 top
C246 "100nF" "CAP 0402/1005 RF" 122.568,364.49 r180 top
C247 "4.7uF" "CAP 0402/1005 RF" 115.084,361.188 r0 top
C248 "470nF" "CAP 0402/1005 RF" 126.378,358.402 r0 top
C249 "470nF" "CAP 0402/1005 RF" 125.166,362.331 r0 top
C250 "68nF" "CAP 0402/1005 RF" 115.084,365.887 r0 top
C251 "68nF" "CAP 0402/1005 RF" 118.749,362.839 r0 top
C252 "4.7uF" "CAP 0402/1005 RF" 128.274,363.347 r0 top
C253 "470nF" "CAP 0402/1005 RF" 128.274,365.252 r0 top
C254 "470nF" "CAP 0402/1005 RF" 128.283,366.141 r0 top
C255 "68nF" "CAP 0402/1005 RF" 115.075,364.998 r0 top
C256 "68nF" "CAP 0402/1005 RF" 118.758,361.823 r0 top
C257 "4.7uF" "CAP 0402/1005 RF" 128.274,364.236 r0 top
C258 "470nF" "CAP 0402/1005 RF" 131.449,365.506 r0 top
C259 "470nF" "CAP 0402/1005 RF" 131.576,363.347 r0 top
C260 "68nF" "CAP 0402/1005 RF" 131.449,367.411 r0 top
C261 "68nF" "CAP 0402/1005 RF" 131.449,369.316 r0 top
C262 "4.7uF" "CAP 0402/1005 RF" 131.449,364.49 r0 top
C263 "470nF" "CAP 0402/1005 RF" 131.576,362.331 r0 top
C264 "470nF" "CAP 0402/1005 RF" 131.449,366.395 r0 top
C265 "68nF" "CAP 0402/1005 RF" 131.449,368.3 r0 top
C266 "68nF" "CAP 0402/1005 RF" 128.274,362.331 r0 top
C267 "100nF" "CAP 0201/0603 RF" 156.737,369.297 r90 bottom
C268 "100nF" "CAP 0201/0603 RF" 155.937,369.297 r90 bottom
C269 "100nF" "CAP 0201/0603 RF" 154.337,369.297 r90 bottom
C270 "100nF" "CAP 0201/0603 RF" 153.537,369.297 r90 bottom
C271 "100nF" "CAP 0201/0603 RF" 240.69,261.449 r270 bottom
C272 "100nF" "CAP 0201/0603 RF" 241.49,261.449 r270 bottom
C273 "10nF" "CAP 0201/0603 RF" 185.839,285.871 r270 bottom
C274 "100nF" "CAP 0201/0603 RF" 243.09,261.449 r270 bottom
C275 "100nF" "CAP 0201/0603 RF" 243.89,261.449 r270 bottom
C276 "10nF" "CAP 0201/0603 RF" 185.091,285.871 r270 bottom
C277 "10nF" "CAP 0201/0603 RF" 173.533,285.655 r270 bottom
C278 "10nF" "CAP 0201/0603 RF" 174.231,285.655 r270 bottom
C279 "100nF" "CAP 0201/0603 RF" 239.09,369.335 r90 bottom
C280 "100nF" "CAP 0201/0603 RF" 238.29,369.335 r90 bottom
C281 "100nF" "CAP 0201/0603 RF" 236.69,369.335 r90 bottom
C282 "100nF" "CAP 0201/0603 RF" 235.89,369.335 r90 bottom
C283 "100nF" "CAP 0201/0603 RF" 74.385,369.563 r90 bottom
C284 "100nF" "CAP 0201/0603 RF" 73.585,369.563 r90 bottom
C285 "10nF" "CAP 0201/0603 RF" 171.526,285.612 r270 bottom
C286 "100nF" "CAP 0201/0603 RF" 71.985,369.563 r90 bottom
C287 "100nF" "CAP 0201/0603 RF" 71.185,369.563 r90 bottom
C288 "10nF" "CAP 0201/0603 RF" 172.263,285.626 r270 bottom
C289 "10nF" "CAP 0201/0603 RF" 168.491,285.63 r270 bottom
C290 "10nF" "CAP 0201/0603 RF" 169.278,285.63 r270 bottom
C291 "100nF" "CAP 0201/0603 RF" 158.337,261.601 r270 bottom
C292 "100nF" "CAP 0201/0603 RF" 159.137,261.601 r270 bottom
C293 "100nF" "CAP 0201/0603 RF" 160.737,261.601 r270 bottom
C294 "100nF" "CAP 0201/0603 RF" 161.537,261.601 r270 bottom
C295 "100nF" "CAP 0201/0603 RF" 163.137,261.601 r270 bottom
C296 "100nF" "CAP 0201/0603 RF" 163.937,261.601 r270 bottom
C297 "10nF" "CAP 0201/0603 RF" 166.472,285.63 r270 bottom
C298 "100nF" "CAP 0201/0603 RF" 165.537,261.601 r270 bottom
C299 "100nF" "CAP 0201/0603 RF" 166.337,261.601 r270 bottom
C300 "10nF" "CAP 0201/0603 RF" 167.297,285.63 r270 bottom
C301 "10nF" "CAP 0201/0603 RF" 157.569,300.546 r0 top
C302 "10nF" "CAP 0201/0603 RF" 155.976,300.466 r0 top
C303_I2C_Bridge_GPIO "100nF" "CAP 0402/1005 RF" 604.952,286.398 r90 top (schematic designator C303)
C303_I2C_Bridge_PCIE "100nF" "CAP 0402/1005 RF" 365.392,71.231 r90 top (schematic designator C303)
C303_I2C_Bridge_SFP "100nF" "CAP 0402/1005 RF" 360.832,81.026 r90 top (schematic designator C303)
C304 "4.7µF" "CAP 0603/1608 RF" 447.942,34.836 r0 top
C305 "4.7µF" "CAP 0603/1608 RF" 452.26,34.836 r0 top
C306 "4.7µF" "CAP 0603/1608 RF" 456.578,34.836 r0 top
C307 "4.7µF" "CAP 0603/1608 RF" 460.896,34.836 r0 top
C308 "4.7 µF" "CAP 0603/1608 RF" 434.988,34.836 r0 top
C309_U_Pomiar_pradu_napiecia_1 "100nF" "CAP 0402/1005 RF" 360.832,136.677 r90 top (schematic designator C309)
C309_U_Pomiar_pradu_napiecia_2 "100nF" "CAP 0402/1005 RF" 359.74,144.301 r90 top (schematic designator C309)
C309_U_Pomiar_pradu_napiecia_3 "100nF" "CAP 0402/1005 RF" 360.832,149.631 r90 top (schematic designator C309)
C309_U_Pomiar_pradu_napiecia_4 "100nF" "CAP 0402/1005 RF" 360.832,156.108 r90 top (schematic designator C309)
C309_U_Pomiar_pradu_napiecia_5 "100nF" "CAP 0402/1005 RF" 362.585,160.004 r90 top (schematic designator C309)
C309_U_Pomiar_pradu_napiecia_6 "100nF" "CAP 0402/1005 RF" 362.928,167.852 r90 top (schematic designator C309)
C309_U_Pomiar_pradu_napiecia_7 "100nF" "CAP 0402/1005 RF" 362.306,177.245 r90 top (schematic designator C309)
C309_U_Pomiar_pradu_napiecia_8 "100nF" "CAP 0402/1005 RF" 360.832,182.016 r90 top (schematic designator C309)
C309_U_Pomiar_pradu_napiecia_9 "100nF" "CAP 0402/1005 RF" 360.832,188.493 r90 top (schematic designator C309)
C309_U_Pomiar_pradu_napiecia_10 "100nF" "CAP 0402/1005 RF" 362.61,195.139 r90 top (schematic designator C309)
C309_U_Pomiar_pradu_napiecia_11 "100nF" "CAP 0402/1005 RF" 362.915,202.053 r90 top (schematic designator C309)
C310 "100nF" "CAP 0402/1005 RF" 360.832,47.447 r90 top
C311_I2C_Expander_00 "1uF" "CAP 0402/1005 RF" 360.832,91.338 r90 top (schematic designator C311)
C311_I2C_Expander_01 "1uF" "CAP 0402/1005 RF" 360.832,97.815 r90 top (schematic designator C311)
C311_I2C_Expander_02 "1uF" "CAP 0402/1005 RF" 360.832,104.292 r90 top (schematic designator C311)
C311_I2C_Expander_10 "1uF" "CAP 0402/1005 RF" 360.832,110.769 r90 top (schematic designator C311)
C311_I2C_Expander_11 "1uF" "CAP 0402/1005 RF" 362.42,116.9 r90 top (schematic designator C311)
C311_I2C_Expander_12 "1uF" "CAP 0402/1005 RF" 360.832,123.723 r90 top (schematic designator C311)
C311_I2C_Expander_16 "1uF" "CAP 0402/1005 RF" 360.705,128.19 r90 top (schematic designator C311)
C311_I2C_Expander_17 "1uF" "CAP 0402/1005 RF" 361.302,248.323 r90 top (schematic designator C311)
C311_I2C_Expander_18 "1uF" "CAP 0402/1005 RF" 361.302,260.667 r90 top (schematic designator C311)
C311_I2C_Expander_Main_Rst "1uF" "CAP 0402/1005 RF" 360.832,84.861 r90 top (schematic designator C311)
C311_I2C_Expander_PWR_CLK "1uF" "CAP 0402/1005 RF" 363.353,68.386 r90 top (schematic designator C311)
C311_I2C_Expander_PWR_Dist "1uF" "CAP 0402/1005 RF" 360.832,65.43 r90 top (schematic designator C311)
C311_I2C_Expander_SFP "1uF" "CAP 0402/1005 RF" 360.832,78.384 r90 top (schematic designator C311)
C312 "100nF" "CAP 0402/1005 RF" 392.798,181.089 r90 top
C313 "100nF" "CAP 0402/1005 RF" 385.686,181.089 r90 top
C314 "100nF" "CAP 0402/1005 RF" 361.302,181.089 r90 top
C320 "10nF" "CAP 0402/1005 RF" 72.682,512.381 r270 top
C321 "3.3nF" "CAP 0603/1608 RF" 70.574,516.572 r180 top
C322 "27pF" "CAP 0402/1005 RF" 68.595,506.031 r180 top
C323 "27pF" "CAP 0402/1005 RF" 66.615,506.031 r0 top
C324 "10uF" "CAP 0805/2012 RF" 290.538,154.203 r90 top
C325 "100nF" "CAP 0402/1005 RF" 42.013,565.172 r270 top
C326 "1uF" "CAP 0402/1005 RF" 261.455,154.711 r90 top
C327 "1uF" "CAP 0402/1005 RF" 267.297,154.711 r90 top
C328 "1uF" "CAP 0402/1005 RF" 273.139,154.711 r90 top
C329 "1uF" "CAP 0402/1005 RF" 278.981,154.711 r90 top
C330 "100nF" "CAP 0402/1005 RF" 40.812,565.172 r270 top
C331 "1uF" "CAP 0402/1005 RF" 24.892,583.095 r270 top
C332 "1uF" "CAP 0402/1005 RF" 141.694,309.283 r180 top
C333 "10nF" "CAP 0201/0603 RF" 64.427,537.533 r270 top
C334 "100nF" "CAP 0402/1005 RF" 71.966,565.087 r270 top
C335 "100nF" "CAP 0402/1005 RF" 74.056,565.087 r270 top
C336 "100nF" "CAP 0402/1005 RF" 31.996,564.265 r90 top
C337 "100nF" "CAP 0402/1005 RF" 33.054,564.265 r90 top
C338 "100nF" "CAP 0402/1005 RF" 34.112,564.265 r90 top
C339 "10uF" "CAP 0805/2012 RF" 25.857,564.336 r90 top
C340 "1uF" "CAP 0402/1005 RF" 30.937,564.265 r90 top
C341 "100nF" "CAP 0402/1005 RF" 36.389,571.132 r0 top
C342 "100nF" "CAP 0402/1005 RF" 65.091,548.068 r90 top
C343 "100nF" "CAP 0402/1005 RF" 64.091,548.068 r90 top
C344 "10nF" "CAP 0201/0603 RF" 65.512,537.533 r270 top
C345 "22pF" "CAP 0402/1005 RF" 66.32,240.08 r270 top
C346 "100nF" "CAP 0402/1005 RF" 68.336,240.08 r90 top
C347 "10uF" "CAP 1206/3216" 78.111,254.825 r270 top
C348 "10uF" "CAP 1206/3216" 75.629,254.825 r270 top
C349 "22pF" "CAP 0402/1005 RF" 66.055,230.697 r90 top
C350 "100nF" "CAP 0402/1005 RF" 68.072,230.712 r270 top
C351 "1uF" "CAP 0402/1005 RF" 60.756,236.764 r0 top
C352 "10uF" "CAP 1206/3216" 62.772,195.58 r90 top
C353 "10uF" "CAP 1206/3216" 60.29,195.58 r90 top
C354 "4.7 µF" "CAP 0603/1608 RF" 439.306,34.836 r0 top
C355 "4.7 µF" "CAP 0603/1608 RF" 443.624,34.836 r0 top
C356 "1uF" "CAP 0402/1005 RF" 60.541,233.839 r0 top
C357 "100nF" "CAP 0402/1005 RF" 64.44,230.697 r90 top
C358 "1uF" "CAP 0603/1608 RF" 58.293,235.623 r270 top
C359 "100nF" "CAP 0402/1005 RF" 112.323,233.238 r270 top
C360 "470nF" "CAP 0402/1005 RF" 112.324,237.989 r90 top
C361 "1uF" "CAP 0402/1005 RF" 110.434,233.237 r270 top
C362 "4.7uF" "CAP 0603/1608 RF" 101.381,237.989 r90 top
C363 "10uF" "CAP 0603/1608 RF" 100.061,237.989 r90 top
C364 "22uF" "CAP 0603/1608 RF" 102.7,237.989 r90 top
C365 "10uF" "CAP 0603/1608 RF" 98.742,233.237 r270 top
C366 "22uF" "CAP 0603/1608 RF" 98.742,237.989 r90 top
C367 "10uF" "CAP 0603/1608 RF" 101.381,233.237 r270 top
C368 "22uF" "CAP 0603/1608 RF" 100.061,233.237 r270 top
C369 "10uF" "CAP 0603/1608 RF" 102.7,233.237 r270 top
C370 "22uF" "CAP 0603/1608 RF" 104.02,237.989 r90 top
C371 "10uF" "CAP 1206/3216 - 0.8MM" 67.736,195.58 r90 top
C372 "10uF" "CAP 1206/3216 - 0.8MM" 80.593,254.825 r270 top
C373 "10uF" "CAP 1206/3216 - 0.8MM" 85.557,254.825 r270 top
C374 "10uF" "CAP 1206/3216 - 0.8MM" 65.254,195.58 r90 top
C375 "10uF" "CAP 1206/3216 - 0.8MM" 83.075,254.825 r270 top
C376 "10uF" "CAP 1206/3216 - 0.8MM" 70.218,195.58 r90 top
C377 "100nF" "CAP 0402/1005 RF" 111.364,233.238 r270 top
C378 "470nF" "CAP 0402/1005 RF" 110.435,237.989 r90 top
C379 "1uF" "CAP 0402/1005 RF" 111.365,237.989 r90 top
C380 "4.7uF" "CAP 0603/1608 RF" 105.339,237.989 r90 top
C381 "10uF" "CAP 0603/1608 RF" 105.339,233.237 r270 top
C382 "22uF" "CAP 0603/1608 RF" 106.659,233.237 r270 top
C383 "10uF" "CAP 0603/1608 RF" 109.298,237.989 r90 top
C384 "22uF" "CAP 0603/1608 RF" 107.978,233.238 r270 top
C385 "10uF" "CAP 0603/1608 RF" 104.02,233.237 r270 top
C386 "22uF" "CAP 0603/1608 RF" 106.659,237.989 r90 top
C387 "10uF" "CAP 0603/1608 RF" 109.297,233.238 r270 top
C388 "22uF" "CAP 0603/1608 RF" 107.978,237.989 r90 top
C389 "22pF" "CAP 0402/1005 RF" 68.211,183.823 r270 top
C390 "100nF" "CAP 0402/1005 RF" 70.891,182.214 r90 top
C391 "10uF" "CAP 1206/3216" 61.258,224.638 r270 top
C392 "10uF" "CAP 1206/3216" 58.776,224.638 r90 top
C393 "22pF" "CAP 0402/1005 RF" 68.185,175.427 r90 top
C394 "100nF" "CAP 0402/1005 RF" 69.151,175.427 r270 top
C395 "1uF" "CAP 0402/1005 RF" 59.93,181.401 r270 top
C396 "10uF" "CAP 1206/3216" 61.334,216.433 r270 top
C397 "10uF" "CAP 1206/3216" 58.852,216.433 r90 top
C398 "1uF" "CAP 0402/1005 RF" 61.458,181.317 r0 top
C399 "100nF" "CAP 0402/1005 RF" 59.524,178.467 r90 top
C400 "10uF" "CAP 1206/3216 - 0.8MM" 68.78,216.433 r270 top
C401 "10uF" "CAP 1206/3216 - 0.8MM" 66.298,216.433 r270 top
C402 "10uF" "CAP 1206/3216 - 0.8MM" 63.816,216.433 r270 top
C403 "10uF" "CAP 1206/3216 - 0.8MM" 68.704,224.607 r90 top
C404 "10uF" "CAP 1206/3216 - 0.8MM" 66.222,224.637 r90 top
C405 "10uF" "CAP 1206/3216 - 0.8MM" 63.74,224.637 r90 top
C406 "100nF" "CAP 0402/1005 RF" 116.15,176.851 r90 top
C407 "470nF" "CAP 0402/1005 RF" 115.176,176.847 r90 top
C408 "1uF" "CAP 0402/1005 RF" 114.205,176.851 r90 top
C409 "4.7uF" "CAP 0603/1608 RF" 110.122,176.847 r90 top
C410 "10uF" "CAP 0603/1608 RF" 108.699,176.847 r90 top
C411 "22uF" "CAP 0603/1608 RF" 112.941,176.847 r90 top
C412 "10uF" "CAP 0603/1608 RF" 111.544,176.847 r90 top
C413 "22uF" "CAP 0603/1608 RF" 107.302,176.847 r90 top
C414 "10uF" "CAP 0603/1608 RF" 103.061,176.847 r90 top
C415 "22uF" "CAP 0603/1608 RF" 101.638,176.847 r90 top
C416 "10uF" "CAP 0603/1608 RF" 105.905,176.847 r90 top
C417 "22uF" "CAP 0603/1608 RF" 104.47,176.851 r90 top
C418 "100nF" "CAP 0402/1005 RF" 113.877,160.146 r90 top
C419 "470nF" "CAP 0402/1005 RF" 112.903,160.146 r90 top
C420 "1uF" "CAP 0402/1005 RF" 111.932,160.146 r90 top
C421 "4.7uF" "CAP 0603/1608 RF" 107.849,160.146 r90 top
C422 "10uF" "CAP 0603/1608 RF" 106.426,160.146 r90 top
C423 "22uF" "CAP 0603/1608 RF" 110.668,160.146 r90 top
C424 "10uF" "CAP 0603/1608 RF" 109.271,160.146 r90 top
C425 "22uF" "CAP 0603/1608 RF" 105.029,160.147 r90 top
C426 "10uF" "CAP 0603/1608 RF" 100.787,160.147 r90 top
C427 "22uF" "CAP 0603/1608 RF" 99.37,160.137 r90 top
C428 "10uF" "CAP 0603/1608 RF" 103.632,160.147 r90 top
C429 "22uF" "CAP 0603/1608 RF" 102.197,160.147 r90 top
C430 "22pF" "CAP 0402/1005 RF" 65.978,210.639 r270 top
C431 "100nF" "CAP 0402/1005 RF" 67.391,209.114 r0 top
C432 "10uF" "CAP 1206/3216" 62.758,168.173 r270 top
C433 "10uF" "CAP 1206/3216" 60.276,168.173 r90 top
C434 "22pF" "CAP 0402/1005 RF" 65.578,202.374 r90 top
C435 "100nF" "CAP 0402/1005 RF" 67.406,203.864 r0 top
C436 "1uF" "CAP 0402/1005 RF" 58.356,207.523 r0 top
C437 "10uF" "CAP 1206/3216" 62.772,189.281 r270 top
C438 "10uF" "CAP 1206/3216" 60.29,189.281 r90 top
C439 "1uF" "CAP 0402/1005 RF" 58.455,209.529 r0 top
C440 "100nF" "CAP 0402/1005 RF" 58.449,203.522 r0 top
C441 "10uF" "CAP 1206/3216 - 0.8MM" 70.218,189.281 r270 top
C442 "10uF" "CAP 1206/3216 - 0.8MM" 67.736,189.281 r270 top
C443 "10uF" "CAP 1206/3216 - 0.8MM" 65.254,189.281 r270 top
C444 "10uF" "CAP 1206/3216 - 0.8MM" 70.204,168.173 r90 top
C445 "10uF" "CAP 1206/3216 - 0.8MM" 67.722,168.173 r90 top
C446 "10uF" "CAP 1206/3216 - 0.8MM" 65.24,168.173 r90 top
C447 "100nF" "CAP 0402/1005 RF" 109.987,209.5 r90 top
C448 "470nF" "CAP 0402/1005 RF" 108.87,209.5 r90 top
C449 "1uF" "CAP 0402/1005 RF" 107.777,209.5 r90 top
C450 "4.7uF" "CAP 0603/1608 RF" 106.482,209.5 r90 top
C451 "10uF" "CAP 0603/1608 RF" 104.983,209.5 r90 top
C452 "22uF" "CAP 0603/1608 RF" 103.51,209.499 r90 top
C453 "10uF" "CAP 0603/1608 RF" 102.037,209.499 r90 top
C454 "22uF" "CAP 0603/1608 RF" 100.564,209.499 r90 top
C455 "10uF" "CAP 0603/1608 RF" 99.091,209.499 r90 top
C456 "22uF" "CAP 0603/1608 RF" 97.617,209.499 r90 top
C457 "10uF" "CAP 0603/1608 RF" 96.144,209.498 r90 top
C458 "22uF" "CAP 0603/1608 RF" 94.671,209.498 r90 top
C459 "100nF" "CAP 0402/1005 RF" 108.979,192.987 r90 top
C460 "470nF" "CAP 0402/1005 RF" 107.861,192.987 r90 top
C461 "1uF" "CAP 0402/1005 RF" 106.769,192.987 r90 top
C462 "4.7uF" "CAP 0603/1608 RF" 105.474,192.987 r90 top
C463 "10uF" "CAP 0603/1608 RF" 103.975,192.986 r90 top
C464 "22uF" "CAP 0603/1608 RF" 102.502,192.971 r90 top
C465 "10uF" "CAP 0603/1608 RF" 101.028,192.986 r90 top
C466 "22uF" "CAP 0603/1608 RF" 99.555,192.986 r90 top
C467 "10uF" "CAP 0603/1608 RF" 98.082,192.986 r90 top
C468 "22uF" "CAP 0603/1608 RF" 96.609,192.986 r90 top
C469 "10uF" "CAP 0603/1608 RF" 95.136,192.986 r90 top
C470 "22uF" "CAP 0603/1608 RF" 93.662,192.986 r90 top
C471 "100nF" "CAP 0402/1005 RF" 52.457,231.085 r90 top
C472 "100nF" "CAP 0402/1005 RF" 50.082,231.991 r90 top
C473 "100nF" "CAP 0402/1005 RF" 52.387,256.453 r270 top
C474 "100nF" "CAP 0402/1005 RF" 50.178,255.53 r270 top
C475 "Capacitor_1210" CAPC3326X17L 287.68,162.001 r90 top
C476 "Capacitor_1210" CAPC3326X17L 295.046,162.001 r90 top
C479 "100nF" "CAP 0402/1005 RF" 124.389,277.877 r90 bottom
C480 "27pF" "CAP 0402/1005 RF" 117.665,273.146 r90 bottom
C481 "27pF" "CAP 0402/1005 RF" 119.05,273.654 r90 bottom
C482 "100nF" "CAP 0402/1005 RF" 123.424,277.852 r90 bottom
C483 "100nF" "CAP 0402/1005 RF" 122.509,277.903 r90 bottom
C484 "100nF" "CAP 0402/1005 RF" 121.468,277.941 r90 bottom
C485 "1uF" "CAP 0402/1005 RF" 299.974,232.553 r90 top
C486 "1uF" "CAP 0402/1005 RF" 297.205,232.553 r90 top
C487 "100nF" "CAP 0402/1005 RF" 302.489,232.585 r90 top
C488 "100nF" "CAP 0402/1005 RF" 296.113,232.522 r90 top
C489 "10uF" "CAP 0402/1005 RF" 301.397,232.553 r90 top
C490 "10nF" "CAP 0402/1005 RF" 298.628,232.553 r90 top
C491 "1uF" "CAP 0402/1005 RF" 583.559,124.847 r90 top
C492 "1uF" "CAP 0402/1005 RF" 588.296,124.745 r90 top
C493 "1uF" "CAP 0402/1005 RF" 585.648,124.771 r90 top
C494 "100nF" "CAP 0402/1005 RF" 590.893,124.669 r90 top
C495 "100nF" "CAP 0402/1005 RF" 584.486,124.936 r90 top
C496 "100nF" "CAP 0402/1005 RF" 589.731,124.834 r90 top
C497 "10uF" "CAP 0402/1005 RF" 587.07,124.86 r90 top
C498 "10nF" "CAP 0402/1005 RF" 592.328,124.758 r90 top
C499 "1uF" "CAP 0402/1005 RF" 367.944,109.982 r90 top
C500 "1uF" "CAP 0402/1005 RF" 375.31,109.982 r90 top
C501 "100nF" "CAP 0402/1005 RF" 385.255,110.105 r90 top
C502 "100nF" "CAP 0402/1005 RF" 389.547,109.982 r90 top
C503 "10uF" "CAP 0402/1005 RF" 396.913,109.982 r90 top
C504 "10nF" "CAP 0402/1005 RF" 404.279,109.982 r90 top
C505 "1uF" "CAP 0402/1005 RF" 411.645,109.982 r90 top
C506 "1uF" "CAP 0402/1005 RF" 419.011,109.982 r90 top
C507 "1uF" "CAP 0402/1005 RF" 426.39,109.982 r90 top
C508 "1uF" "CAP 0402/1005 RF" 433.756,109.982 r90 top
C509 "100nF" "CAP 0402/1005 RF" 441.122,109.982 r90 top
C510 "100nF" "CAP 0402/1005 RF" 448.488,109.982 r90 top
C511 "100nF" "CAP 0402/1005 RF" 455.6,109.982 r90 top
C512 "100nF" "CAP 0402/1005 RF" 462.216,109.982 r90 top
C513 "10uF" "CAP 0402/1005 RF" 469.328,109.982 r90 top
C514 "10nF" "CAP 0402/1005 RF" 476.44,109.982 r90 top
C515 "4.7uF" "CAP 0603/1608 RF" 136.804,200.812 r90 top
C516 "4.7uF" "CAP 0603/1608 RF" 140.83,202.298 r90 top
C517 "100nF" "CAP 0402/1005 RF" 118.173,334.607 r90 top
C518 "2.2uF" "CAP 1206/3216 - 0.8MM" 126.632,334.937 r90 top
C519 "100nF" "CAP 0402/1005 RF" 121.45,326.621 r90 top
C520 "2.2uF" "CAP 1206/3216 - 0.8MM" 117.602,325.734 r90 top
C521 "100nF" "CAP 0402/1005 RF" 401.676,71.209 r90 top
C522 "1uF" "CAP 0402/1005 RF" 402.857,71.26 r90 top
C523 "4.7uF" "CAP 0603/1608 RF" 117.907,332.121 r90 top
C524 "4.7uF" "CAP 0603/1608 RF" 125.057,326.649 r90 top
C525 "10nF" "CAP 0402/1005 RF" 151.355,313.343 r180 top
C526 "10nF" "CAP 0402/1005 RF" 151.355,312.332 r180 top
C527 "10nF" "CAP 0402/1005 RF" 155.622,309.179 r180 top
C528 "10nF" "CAP 0402/1005 RF" 155.622,310.274 r180 top
C529 "10nF" "CAP 0402/1005 RF" 151.355,310.185 r180 top
C530 "10nF" "CAP 0402/1005 RF" 151.355,311.189 r180 top
C531 "100nF" "CAP 0402/1005 RF" 47.206,447.065 r180 top
C532 "100nF" "CAP 0402/1005 RF" 63.97,451.688 r90 top
C533 "100nF" "CAP 0402/1005 RF" 62.87,451.688 r90 top
C534 "100nF" "CAP 0402/1005 RF" 44.47,438.625 r270 top
C535 "22pF" "CAP 0402/1005 RF" 148.213,330.314 r180 top
C536 "22pF" "CAP 0402/1005 RF" 149.933,330.314 r0 top
C537 "WE-Communication Connectors 692121130100" 692121130100 35.291,358.548 r90 bottom
C538 "1uF" "CAP 0402/1005 RF" 42.177,361.364 r90 top
C539 "4.7uF" "CAP 0603/1608 RF" 49.721,361.034 r90 top
C540 "100nF" "CAP 0402/1005 RF" 45.996,351.904 r180 top
C541 "100nF" "CAP 0402/1005 RF" 46.025,351.079 r180 top
C542 "100nF" "CAP 0402/1005 RF" 46.063,350.101 r180 top
C543 "100nF" "CAP 0402/1005 RF" 46.038,348.996 r180 top
C544 "1uF" "CAP 0402/1005 RF" 403.504,215.989 r90 top
C545 "100nF" "CAP 0402/1005 RF" 360.832,215.989 r90 top
C546 "100nF" "CAP 0402/1005 RF" 365.185,215.849 r90 top
C547 "100nF" "CAP 0402/1005 RF" 378.879,147.511 r90 top
C548 "11pF" "CAP 0402/1005 RF" 62.953,210.639 r270 top
C549 "220pF" "CAP 0402/1005 RF" 62.338,212.229 r180 top
C550 "4.7uF" "CAP 0402/1005 RF" 102.225,250.563 r90 top
C551 "10uF" "CAP 0402/1005 RF" 96.268,247.873 r90 top
C552 "4.7uF" "CAP 0402/1005 RF" 96.964,250.684 r90 top
C553 "10uF" "CAP 0402/1005 RF" 96.964,253.376 r90 top
C554 "4.7uF" "CAP 0402/1005 RF" 90.265,249.429 r90 top
C555 "10uF" "CAP 0402/1005 RF" 90.322,252.088 r90 top
C558 "WR-Communication Connectors 614105150721" 614105150721 131.022,88.373 r90 top
C559 "1uF" "CAP 0402/1005 RF" 127.127,94.103 r90 top
C560 "4.7uF" "CAP 0603/1608 RF" 127.762,90.678 r90 top
C561 "100nF" "CAP 0402/1005 RF" 78.331,275.773 r0 top
C562 "100nF" "CAP 0402/1005 RF" 395.088,172.212 r0 top
C563_5V_to_3V3_for_FTDI "4.7uF" "CAP 0603/1608 RF" 405.447,223.749 r90 top (schematic designator C563)
C563_U_5V_to_3V31 "4.7uF" "CAP 0603/1608 RF" 148.838,216.538 r90 top (schematic designator C563)
C563_U_5V_to_3V32 "4.7uF" "CAP 0603/1608 RF" 255.552,244.424 r270 top (schematic designator C563)
C563_U_5V_to_3V33 "4.7uF" "CAP 0603/1608 RF" 62.446,368.071 r0 top (schematic designator C563)
C564_5V_to_3V3_for_FTDI "4.7uF" "CAP 0603/1608 RF" 427.799,223.749 r90 top (schematic designator C564)
C564_U_5V_to_3V31 "4.7uF" "CAP 0603/1608 RF" 150.832,216.448 r90 top (schematic designator C564)
C564_U_5V_to_3V32 "4.7uF" "CAP 0603/1608 RF" 257.937,244.526 r270 top (schematic designator C564)
C564_U_5V_to_3V33 "4.7uF" "CAP 0603/1608 RF" 65.875,370.103 r0 top (schematic designator C564)
C565_5V_to_3V3_for_FTDI "4.7uF" "CAP 0603/1608 RF" 450.139,223.749 r90 top (schematic designator C565)
C565_U_5V_to_3V31 "4.7uF" "CAP 0603/1608 RF" 157.664,219.018 r270 top (schematic designator C565)
C565_U_5V_to_3V32 "4.7uF" "CAP 0603/1608 RF" 244.615,243.489 r270 top (schematic designator C565)
C565_U_5V_to_3V33 "4.7uF" "CAP 0603/1608 RF" 62.423,369.722 r0 top (schematic designator C565)
C566_5V_to_3V3_for_FTDI "100nF" "CAP 0402/1005 RF" 472.313,224.079 r90 top (schematic designator C566)
C566_U_5V_to_3V31 "100nF" "CAP 0402/1005 RF" 163.601,216.148 r90 top (schematic designator C566)
C566_U_5V_to_3V32 "100nF" "CAP 0402/1005 RF" 246.545,243.522 r270 top (schematic designator C566)
C566_U_5V_to_3V33 "100nF" "CAP 0402/1005 RF" 65.568,368.071 r0 top (schematic designator C566)
C567_5V_to_3V3_for_FTDI "2.2uF" "CAP 0402/1005 RF" 494.665,224.079 r90 top (schematic designator C567)
C567_U_5V_to_3V31 "2.2uF" "CAP 0402/1005 RF" 162.312,216.16 r90 top (schematic designator C567)
C567_U_5V_to_3V32 "2.2uF" "CAP 0402/1005 RF" 248.588,240.767 r90 top (schematic designator C567)
C567_U_5V_to_3V33 "2.2uF" "CAP 0402/1005 RF" 56.473,364.058 r0 top (schematic designator C567)
C568 "4.7uF" "CAP 0402/1005 RF" 392.43,157.861 r0 top
C569 "4.7uF" "CAP 0402/1005 RF" 396.748,157.861 r0 top
C570 "4.7uF" "CAP 0402/1005 RF" 388.112,157.861 r0 top
C571 "1nF" "CAP 0201/0603 RF" 374.777,158.115 r0 top
C572 "10uF" "CAP 0603/1608 RF" 156.493,569.926 r270 top
C573 "10nF" "CAP 0201/0603 RF" 161.329,564.973 r180 top
C574 "10uF" "CAP 0805/2012 RF" 126.822,206.235 r0 top
C575 "10uF" "CAP 0805/2012 RF" 41.641,404.621 r0 top
C576 "10uF" "CAP 0603/1608 RF" 157.89,569.957 r270 top
C577 "10nF" "CAP 0201/0603 RF" 160.882,571.704 r180 top
C578 "100nF" "CAP 0402/1005 RF" 163.089,572.974 r270 top
C579 "100nF" "CAP 0402/1005 RF" 162.589,564.583 r90 top
C580 "4.7uF" "CAP 0805/2012 RF" 439.547,161.275 r0 top
C581 "10uF" "CAP 0805/2012 RF" 439.547,163.068 r0 top
C582 "4.7uF" "CAP 0805/2012 RF" 439.547,164.846 r0 top
C583 "100nF" "CAP 0402/1005 RF" 398.154,161.671 r0 top
C584 "4.7uF" "CAP 0805/2012 RF" 439.293,159.385 r0 top
C585 "100nF" "CAP 0402/1005 RF" 368.198,162.865 r90 top
C586 "2.2uF" "CAP 1206/3216 - 0.8MM" 122.999,334.34 r90 top
C587 "2.2uF" "CAP 1206/3216 - 0.8MM" 130.035,328.79 r90 top
C588 "100nF" "CAP 0402/1005 RF" 139.983,599.863 r270 top
C589 "100nF" "CAP 0402/1005 RF" 139.983,597 r270 top
C590 "100nF" "CAP 0402/1005 RF" 138.214,570.104 r0 top
C591 "10uF" "CAP 0402/1005 RF" 138.214,566.04 r0 top
C592 "100nF" "CAP 0402/1005 RF" 138.214,564.955 r0 top
C595 "10uF" "CAP 0805/2012 RF" 28.639,227.851 r90 bottom
C596 "10uF" "CAP 0805/2012 RF" 52.54,225.895 r90 bottom
C597 "1uF" "CAP 0402/1005 RF" 34.332,206.35 r0 top
C598 "10uF" "CAP 0603/1608 RF" 37.846,209.537 r270 top
C603 "43pF" "CAP 0201/0603 RF" 430.339,35.014 r0 top
C604 "1µF" "CAP 0402/1005 RF" 426.022,35.014 r0 top
C605 "100pF" "CAP 0201/0603 RF" 400.126,35.014 r0 top
C606 "4.7 µF" "CAP 0603/1608 RF" 405.267,36.589 r0 top
C607 "4.7 µF" "CAP 0603/1608 RF" 409.092,34.836 r0 top
C609 "FC0H224ZFTBR24" FC0H224ZFTBR24 109.499,678.04 r270 top
C610 "4.7 µF" "CAP 0603/1608 RF" 413.41,34.836 r0 top
C611 "4.7 µF" "CAP 0603/1608 RF" 417.728,34.836 r0 top
C612 "43pF" "CAP 0201/0603 RF" 382.854,35.014 r0 top
C613 "4.7 µF" "CAP 0603/1608 RF" 387.502,34.836 r0 top
C614 "4.7 µF" "CAP 0603/1608 RF" 391.82,34.836 r0 top
C615 "4.7 µF" "CAP 0603/1608 RF" 395.938,38.697 r0 top
C616 "100pF" "CAP 0201/0603 RF" 361.251,35.014 r0 top
C617 "4.7 µF" "CAP 0603/1608 RF" 365.9,34.836 r0 top
C618 "4.7 µF" "CAP 0603/1608 RF" 370.218,34.836 r0 top
C619 "4.7 µF" "CAP 0603/1608 RF" 374.536,34.836 r0 top
C620 "4.7 µF" "CAP 0603/1608 RF" 394.945,44.374 r0 top
C621 "4.7 µF" "CAP 0603/1608 RF" 400.494,43.307 r0 top
C622 "4.7 µF" "CAP 0603/1608 RF" 407.276,45.174 r0 top
C623 "100nF" "CAP 0402/1005 RF" 387.198,43.485 r0 top
C624 "10nF" "CAP 0201/0603 RF" 360.934,43.637 r0 top
C625 "10nF" "CAP 0201/0603 RF" 365.252,43.637 r0 top
C626 "10nF" "CAP 0201/0603 RF" 369.57,43.637 r0 top
C627 "100nF" "CAP 0201/0603 RF" 197.272,309.647 r90 bottom
C628 "470nF" "CAP 0402/1005 RF" 180.397,309.042 r90 bottom
C629 "100nF" "CAP 0201/0603 RF" 197.104,304.165 r90 top
C630 "470nF" "CAP 0402/1005 RF" 176.39,302.031 r90 bottom
C631 "10uF" "CAP 0603/1608 RF" 199.567,300.723 r180 top
C632 "470nF" "CAP 0402/1005 RF" 177.902,306.54 r0 bottom
C633 "3nF" "CAP 0402/1005 RF" 93.442,247.284 r180 top
C634 "330pF" "CAP 0402/1005 RF" 61.028,236.114 r270 bottom
C635 "6.8nF" "CAP 0402/1005 RF" 60.062,236.114 r270 bottom
C636 "3nF" "CAP 0402/1005 RF" 93.332,224.031 r180 top
C637 "1.2nF" "CAP 0402/1005 RF" 87.909,190.2 r270 top
C638 "1.2nF" "CAP 0402/1005 RF" 89.332,174.38 r270 top
C639 "47nF" "CAP 0402/1005 RF" 66.141,183.759 r270 top
C640 "47nF" "CAP 0402/1005 RF" 66.161,175.503 r90 top
C641 "470pF" "CAP 0402/1005 RF" 64.175,175.557 r90 top
C642 "56pF" "CAP 0402/1005 RF" 64.175,183.66 r270 top
C643 "8.2nF" "CAP 0402/1005 RF" 63.51,173.949 r180 top
C644 "820pF" "CAP 0402/1005 RF" 63.565,185.176 r180 top
C645 "1.2nF" "CAP 0402/1005 RF" 88.354,202.857 r180 top
C646 "1.2nF" "CAP 0402/1005 RF" 84.112,207.488 r0 top
C647 "47nF" "CAP 0402/1005 RF" 63.953,210.654 r270 top
C648 "47nF" "CAP 0402/1005 RF" 63.741,202.373 r90 top
C649 "100nF" "CAP 0402/1005 RF" 170.726,320.189 r90 bottom
C650 "180pF" "CAP 0402/1005 RF" 62.828,202.374 r90 top
C651 "100nF" "CAP 0402/1005 RF" 171.635,320.189 r90 bottom
C652 "2.2nF" "CAP 0402/1005 RF" 61.925,200.059 r90 top
C653 "100nF" "CAP 0402/1005 RF" 141.944,313.674 r180 top
C654 "100nF" "CAP 0402/1005 RF" 374.205,55.74 r0 top
C655 "5.6nF" "CAP 0402/1005 RF" 105.362,254.83 r0 top
C656 "5.6nF" "CAP 0402/1005 RF" 99.88,254.796 r0 top
C657 "5.6nF" "CAP 0402/1005 RF" 93.466,253.617 r0 top
C658 "100nF" "CAP 0402/1005 RF" 324.574,29.985 r90 top
C659 "4.7uF" "CAP 0603/1608 RF" 315.62,55.118 r90 top
C660 "100nF" "CAP 0402/1005 RF" 112.022,112.083 r90 top
C661 "4.7uF" "CAP 0603/1608 RF" 251.142,55.118 r90 top
C662 "100nF" "CAP 0402/1005 RF" 257.823,55.448 r90 top
C663 "27pF" "CAP 0402/1005 RF" 235.852,55.258 r90 top
C664 "27pF" "CAP 0402/1005 RF" 223.609,55.448 r90 top
C665 "100nF" "CAP 0402/1005 RF" 131.686,86.868 r90 top
C666 "100nF" "CAP 0402/1005 RF" 434.81,50.47 r90 top
C667 "100nF" "CAP 0402/1005 RF" 436.08,50.568 r90 top
C668 "100nF" "CAP 0402/1005 RF" 438.175,49.441 r90 top
C669 "100nF" "CAP 0402/1005 RF" 439.839,49.39 r90 top
C670 "100nF" "CAP 0402/1005 RF" 441.164,49.336 r90 top
C671 "100nF" "CAP 0402/1005 RF" 442.239,49.39 r90 top
C672 "Capacitor_1210" CAPC3326X17L 287.68,153.683 r90 top
C673 "100nF" "CAP 0402/1005 RF" 128.791,86.716 r90 top
C674 "4.7uF" "CAP 0402/1005 RF" 378.549,50.521 r0 top
C675 "4.7uF" "CAP 0402/1005 RF" 382.867,50.521 r0 top
C676 "4.7uF" "CAP 0402/1005 RF" 374.231,50.521 r0 top
C677 "100nF" "CAP 0402/1005 RF" 141.944,314.574 r180 top
C678 "100uF" "CAP 1206/3216" 122.911,671.703 r0 top
C679 "100uF" "CAP 1206/3216" 122.834,674.662 r0 top
C680 "1uF" "CAP 0402/1005 RF" 85.026,664.096 r90 top
C693 "470nF" "CAP 0402/1005 RF" 39.98,209.427 r90 top
C694 "4.7uF" "CAP 0603/1608 RF" 18.637,238.218 r0 top
C695 "10uF" "CAP 0805/2012 RF" 51.294,206.694 r180 top
C696 "10uF" "CAP 0805/2012 RF" 51.294,202.914 r180 top
C697 "10uF" "CAP 0805/2012 RF" 51.294,204.804 r180 top
C698 "10uF" "CAP 0805/2012 RF" 51.294,208.585 r180 top
C699 "10uF" "CAP 0805/2012 RF" 51.294,201.023 r180 top
C700 "1uF" "CAP 0402/1005 RF" 18.637,239.357 r0 top
C701 "12nF" "CAP 0402/1005 RF" 41.097,200.511 r90 top
C702 "36pF" "CAP 0402/1005 RF" 40.17,200.511 r90 top
C703 "15nF" "CAP 0402/1005 RF" 42.517,204.097 r180 top
C704 "1uF" "CAP 0603/1608 RF" 40.157,198.45 r180 top
C705 "10uF" "CAP 0603/1608 RF" 222.045,323.494 r0 top
C706 "10nF" "CAP 0201/0603 RF" 184.219,282.55 r180 top
C707 "10uF" "CAP 0805/2012 RF" 259.183,333.794 r0 top
C708 "10uF" "CAP 0805/2012 RF" 250.534,333.794 r0 top
C709 "10uF" "CAP 0603/1608 RF" 245.988,333.997 r0 top
C710 "10nF" "CAP 0201/0603 RF" 236.679,334.327 r0 top
C711 "100nF" "CAP 0402/1005 RF" 216.682,316.433 r0 top
C712 "100nF" "CAP 0402/1005 RF" 228.36,334.175 r0 top
C713 "100nF" "CAP 0402/1005 RF" 365.57,62.319 r0 top
C714 "330nF" "CAP 0603/1608 RF" 371.479,60.719 r0 top
C715 "100nF" "CAP 0402/1005 RF" 141.944,316.674 r180 top
C716 "100nF" "CAP 0402/1005 RF" 141.944,317.575 r180 top
C717 "100nF" "CAP 0402/1005 RF" 168.542,320.189 r90 bottom
C718 "100nF" "CAP 0402/1005 RF" 169.451,320.189 r90 bottom
C719 "1nF" "CAP 0201/0603 RF" 360.68,75.425 r90 top
C720 "1uF" "CAP 0402/1005 RF" 146.52,349.06 r90 top
C721 "1uF" "CAP 0402/1005 RF" 147.511,349.06 r90 top
C722 "1uF" "CAP 0402/1005 RF" 153.683,349.142 r90 top
C723 "1uF" "CAP 0402/1005 RF" 154.673,349.142 r90 top
C724 "10nF" "CAP 0201/0603 RF" 388.645,29.985 r90 top
C725 "10nF" "CAP 0201/0603 RF" 381.279,29.985 r90 top
C726 "10nF" "CAP 0201/0603 RF" 150.703,320.51 r90 top
C727 "10nF" "CAP 0201/0603 RF" 366.535,29.985 r90 top
C731 "2.2uF" "CAP 0402/1005 RF" 40.97,336.575 r90 top
C732 "100nF" "CAP 0402/1005 RF" 47.828,336.575 r90 top
C733 "1uF" "CAP 0402/1005 RF" 129.003,208.851 r90 top
C734 "1uF" "CAP 0402/1005 RF" 475.615,179.032 r90 top
C735 "100nF" "CAP 0402/1005 RF" 460.87,179.032 r90 top
C736 "9pF" "CAP 0201/0603 RF" 421.932,183.172 r90 top
C737 "9pF" "CAP 0201/0603 RF" 440.741,176.352 r90 top
C738 "6TPE680MI" "CAP POL 2917/7343" 535.47,98.158 r90 top
C739 "100uF" "CAP 1210/3225 - 1MM" 542.1,99.517 r90 top
C740 "4.7uF" "CAP 0402/1005 RF" 377.609,128.283 r90 top
C741 "4.7uF" "CAP 0402/1005 RF" 159.918,277.794 r90 top
C742 "100uF" "CAP 1210/3225 - 1MM" 581.393,107.01 r90 top
C743 "4.7uF" "CAP 0402/1005 RF" 584.022,106.892 r270 top
C744 "47uF" "CAP 1206/3216 - 0.8MM" 488.455,118.732 r90 top
C745 "4.7uF" "CAP 0402/1005 RF" 492.455,112.674 r90 top
C746 "4.7uF" "CAP 0402/1005 RF" 499.821,112.674 r90 top
C747 "100uF" "CAP 1210/3225 - 1MM" 512.356,96.203 r90 top
C748 "4.7uF" "CAP 0402/1005 RF" 509.029,96.317 r270 top
C749 "47uF" "CAP 1206/3216 - 0.8MM" 155.753,285.612 r270 top
C750 "4.7uF" "CAP 0402/1005 RF" 231.951,319.325 r90 top
C751 "100uF" "CAP 1210/3225 - 1MM" 452.183,115.875 r0 top
C752 "4.7uF" "CAP 0402/1005 RF" 455.612,112.674 r90 top
C753 "100uF" "CAP 1210/3225 - 1MM" 458.902,116.116 r90 top
C754 "4.7uF" "CAP 0402/1005 RF" 470.357,112.674 r90 top
C755 "4.7uF" "CAP 0402/1005 RF" 477.723,112.674 r90 top
C756 "47uF" "CAP 1206/3216 - 0.8MM" 431.546,114.821 r90 top
C757 "100uF" "CAP 1210/3225 - 1MM" 158.966,285.56 r90 top
C758 "4.7uF" "CAP 0402/1005 RF" 229.361,318.746 r90 top
C759 "47uF" "CAP 1206/3216 - 0.8MM" 393.268,101.803 r90 top
C760 "100uF" "CAP 1210/3225 - 1MM" 161.874,276.784 r270 top
C761 "4.7uF" "CAP 0402/1005 RF" 163.792,277.794 r90 top
C762 "100uF" "CAP 1210/3225 - 1MM" 364.236,99.971 r90 top
C763 "4.7uF" "CAP 0402/1005 RF" 368.211,112.674 r90 top
C764 "100uF" "CAP 1210/3225 - 1MM" 379.705,97.399 r90 top
C765 "4.7uF" "CAP 0402/1005 RF" 382.943,112.674 r90 top
C766 "22uF" "CAP 1210/3225 - 1MM" 73.992,159.249 r270 top
C767 "22uF" "CAP 1210/3225 - 1MM" 70.524,159.25 r270 top
C768 "22uF" "CAP 1210/3225 - 1MM" 67.084,159.249 r270 top
C769 "22uF" "CAP 1210/3225 - 1MM" 63.68,159.249 r270 top
C770 "100nF" "CAP 0402/1005 RF" 38.538,159.341 r270 top
C771 "100nF" "CAP 0402/1005 RF" 37.531,159.341 r270 top
C772 "100nF" "CAP 0402/1005 RF" 36.624,159.341 r270 top
C773 "100nF" "CAP 0402/1005 RF" 35.693,159.341 r270 top
C774 "10uF" "CAP 0805/2012 RF" 51.366,221.852 r0 top
C775 "10uF" "CAP 0805/2012 RF" 51.366,220.038 r0 top
C776 "10uF" "CAP 0805/2012 RF" 51.366,218.215 r0 top
C777 "10uF" "CAP 0805/2012 RF" 51.366,216.47 r0 top
C778 "4.7uF" "CAP 0805/2012 RF" 51.366,214.657 r0 top
C779 "4.7uF" "CAP 0805/2012 RF" 51.366,212.847 r0 top
C780 "4.7uF" "CAP 0805/2012 RF" 51.366,210.952 r0 top
C781 "4.7uF" "CAP 0805/2012 RF" 361.201,40.919 r90 top
C782 "4.7uF" "CAP 0402/1005 RF" 405.041,99.314 r90 top
C783 "100nF" "CAP 0402/1005 RF" 412.407,99.314 r90 top
C784 "4.7uF" "CAP 0402/1005 RF" 390.309,99.314 r90 top
C785 "100nF" "CAP 0402/1005 RF" 397.675,99.314 r90 top
C786 "4.7uF" "CAP 0402/1005 RF" 375.564,99.314 r90 top
C787 "100nF" "CAP 0402/1005 RF" 382.93,99.314 r90 top
C788 "4.7uF" "CAP 0402/1005 RF" 360.98,99.924 r90 top
C789 "100nF" "CAP 0402/1005 RF" 368.198,99.314 r90 top
C790 "100nF" "CAP 0402/1005 RF" 585.769,120.269 r90 top
C791 "100nF" "CAP 0402/1005 RF" 471.068,251.092 r90 top
C792 "100nF" "CAP 0402/1005 RF" 451.536,50.66 r90 top
D1 "SLVU2.8-4BTG TVS Array" SLVU2.8-4 61.176,243.357 r0 bottom
D2 "SLVU2.8-4BTG TVS Array" SLVU2.8-4 61.189,249.58 r0 bottom
D3 "DF01S2" "DF005S2 - DF10S2" 44.298,228.282 r90 bottom locked
D4 "DF01S2" "DF005S2 - DF10S2" 34.43,228.346 r90 bottom locked
D5 "LTST-C190GKT" "LED 0603/1608 GREEN" 37.231,451.764 r90 top
D6 "LTST-C190GKT" "LED 0603/1608 GREEN" 35.199,452.018 r90 top
D7 "LTST-C190GKT" "LED 0603/1608 GREEN" 39.629,451.764 r90 top
D8 "LTST-C190GKT" "LED 0603/1608 GREEN" 44.724,451.637 r90 top
D9 "LTST-C190GKT" "LED 0603/1608 GREEN" 42.311,451.637 r270 top
D10 "LTST-C190GKT" "LED 0603/1608 GREEN" 69.708,450.037 r270 top
D11 "BAT54T1G" BAT54T1G 63.745,439.095 r90 top
D12 "BAT54T1G" BAT54T1G 61.326,439.095 r90 top
D13 "TPD2EUSB30DRTR" TPD2EUSB30 43.739,347.942 r0 top
D14 "TPD4EUSB30DQAR" TPD4EUSB30 42.137,350.757 r180 top
D15 "TPD2EUSB30DRTR" TPD2EUSB30 135.293,88.176 r0 top
D16 "MBRM140T3" "CASE 457" 432.475,65.773 r0 top
D17 "MBRM140T3" "CASE 457" 432.576,68.961 r0 top
D18 "MBRM140T3" "CASE 457" 418.594,65.316 r0 top
D19 "MBRM140T3" "CASE 457" 430.212,54.508 r0 top
D20 "S1M-13-F" S1M-13-F 96.456,684.53 r180 top
D21 "S1M-13-F" S1M-13-F 96.291,665.798 r180 top
D23 "S1M-13-F" S1M-13-F 137.884,685.419 r270 top
D24 "S1M-13-F" S1M-13-F 365.785,195.999 r90 top
D26 "DFLS1100-7" DFLS1100 34.353,210.071 r270 top
D27 "DFLS1100-7" DFLS1100 44.666,214.084 r270 top
D28 "BAS40-04-TP" BAS40-04-TP 146.24,326.314 r270 top
F1_PCIE0 "Current" "RES 0805/2012 RF" 361.645,267.779 r90 top (schematic designator F1)
F1_PCIE1 "Current" "RES 0805/2012 RF" 361.645,275.272 r90 top (schematic designator F1)
F1_PCIE2 "Current" "RES 0805/2012 RF" 361.645,282.765 r90 top (schematic designator F1)
F1_PCIE3 "Current" "RES 0805/2012 RF" 361.645,290.258 r90 top (schematic designator F1)
F1_PCIE4 "Current" "RES 0805/2012 RF" 361.645,297.751 r90 top (schematic designator F1)
FB2 "220Ohm" "FER 0603/1608" 98.514,279.109 r90 top
FB3 "220Ohm" "FER 0603/1608" 81.157,576.135 r180 top
FB4 "220Ohm" "FER 0603/1608" 100.292,279.109 r90 top
FB5 "220Ohm" "FER 0603/1608" 77.514,577.533 r180 top
FB6 "220Ohm" "FER 0603/1608" 76.839,573.087 r180 top
FB7 "220Ohm" "FER 0603/1608" 81.157,577.786 r180 top
FB8 "220R" "FER 0603/1608" 139.493,572.359 r0 top
FB9 "220R" "FER 0603/1608" 159.922,584.827 r180 top
FB10 "220R" "FER 0603/1608" 151.93,572.731 r90 top
FB11 "220R" "FER 0603/1608" 134.885,585.046 r0 top
FB12 "220R" "FER 0603/1608" 147.857,568.362 r90 top
FB13 "220R" "FER 0603/1608" 137.57,591.701 r270 top
FB14 "220R" "FER 0603/1608" 143.583,568.362 r90 top
FB15 "220R" "FER 0603/1608" 148.365,595.961 r270 top
FB16 "220R" "FER 0603/1608" 159.922,580.152 r180 top
FB17 "220R" "FER 0603/1608" 144.583,595.961 r270 top
FB18 "220R" "FER 0603/1608" 159.922,582.499 r180 top
FB19 "220R" "FER 0603/1608" 159.922,577.8 r180 top
FB20 "220R" "FER 0603/1608" 134.863,581.652 r0 top
FB21 "220R" "FER 0603/1608" 145.583,568.362 r90 top
FB22 "220R" "FER 0603/1608" 134.863,579.152 r0 top
FB23 "Ferrite Chip" "FER 0603/1608" 297.015,154.838 r0 top
FB24 "Ferrite Chip" "FER 0603/1608" 28.564,565.036 r0 top
FB25 "Ferrite Chip" "FER 0603/1608" 123.533,326.369 r90 top
FB26 "220R" "FER 0603/1608" 45.11,361.44 r90 top
FB27 "220R" "FER 0603/1608" 41.93,345.237 r90 top
FB28 "220R" "FER 0603/1608" 390.042,178.498 r90 top
FB29 "220R" "FER 0603/1608" 383.184,215.456 r90 top
FB31 "220R" "FER 0603/1608" 130.264,91.999 r90 top
FB32 "220R" "FER 0603/1608" 130.607,95.822 r90 top
FB33 "120R" "FER 0603/1608" 400.685,158.75 r90 top
FB34 "330R" "FER 0603/1608" 391.325,162.672 r90 top
FB35 "220Ohm" "FER 0603/1608" 366.022,65.915 r90 top
FB36 "220R" "FER 0603/1608" 152.71,566.805 r270 top
FB37 "220R" "FER 0603/1608" 138.214,568.072 r270 top
FB38 "600R" "FER 0805/2012" 201.358,309.448 r180 top
FB39 "600R" "FER 0805/2012" 199.568,307.149 r180 top
FB40 "600R" "FER 0805/2012" 199.579,304.749 r180 top
FB41 "600R" "FER 0805/2012" 375.12,78.105 r90 top
FB42 "120R" "FER 0603/1608" 199.593,302.489 r180 top
FB43 "220R" "FER 0603/1608" 119.642,111.55 r90 top
FB44 "220R" "FER 0603/1608" 265.443,54.915 r90 top
FB45 "120R" "FER 0603/1608" 389.903,49.784 r90 top
J1_PCIE0 "2041262-1" "PCI Express / PCI Connectors Mini PCI-E 6.8H G/F - z otowrami" 161.187,362.892 r180 bottom locked (schematic designator J1)
J1_PCIE1 "2041262-1" "PCI Express / PCI Connectors Mini PCI-E 6.8H G/F - z otowrami" 236.24,267.894 r0 bottom locked (schematic designator J1)
J1_PCIE2 "2041262-1" "PCI Express / PCI Connectors Mini PCI-E 6.8H G/F - z otowrami" 243.54,362.892 r180 bottom locked (schematic designator J1)
J1_PCIE3 "2041262-1" "PCI Express / PCI Connectors Mini PCI-E 6.8H G/F - z otowrami" 78.835,362.892 r180 bottom locked (schematic designator J1)
J1_PCIE4 "2041262-1" "PCI Express / PCI Connectors Mini PCI-E 6.8H G/F - z otowrami" 153.887,267.894 r0 bottom locked (schematic designator J1)
J2 "5-1814832-1" TECO-5-1814832-1_V 88.279,262.674 r0 top
J3 "5-1814832-1" TECO-5-1814832-1_V 92.854,262.674 r0 top
J4 "1909763-1" TECO-1909763-1_V 112.869,262.534 r0 top
J5 "1909763-1" TECO-1909763-1_V 107.815,262.534 r0 top
J6 "5-1814832-1" TECO-5-1814832-1_V 78.016,509.333 r180 bottom
J7 "5-1814832-1" TECO-5-1814832-1_V 87.033,509.334 r180 bottom
J12 "I2C_0Master" "MOLEX KK 0022272021" 259.067,346.054 r0 top
J13 "I2C1_Master" "MOLEX KK 0022272021" 116.408,430.898 r270 top
J14 "7 Pin" "JST XH B7B-XH-A" 10.551,374.797 r180 bottom
J15 "GPIO0_12" "MOLEX KK 0022272021" 198.196,400.704 r0 top
J16 "GPIO0_23" "MOLEX KK 0022272021" 198.196,371.259 r0 top
J17 "GPIO1_38" "MOLEX KK 0022272021" 198.196,410.519 r0 top
J18 "7 Pin" "JST XH B7B-XH-A" 10.551,383.362 r0 bottom
J19 "GPIO2_66" "MOLEX KK 0022272021" 198.196,420.334 r0 top
J20 "GPIO2_70" "MOLEX KK 0022272021" 198.196,430.149 r0 top
J21 "GPIO2_72" "MOLEX KK 0022272021" 198.196,390.889 r0 top
J22 "GPIO2_73" "MOLEX KK 0022272021" 198.196,381.074 r0 top
J23 "GPIO2_74" "MOLEX KK 0022272021" 116.154,415.773 r90 top
J24 "GPIO2_75" "MOLEX KK 0022272021" 116.497,392.836 r90 top
J25 "SPI1" "JST XH B4B-XH-A" 115.989,404.283 r90 top
J26 "5-1814832-1" TECO-5-1814832-1_V 30.272,571.132 r90 bottom
J27 "Key M-SATA CHINA" "M.2 KEY M - NVMe" 141.668,316.624 r270 bottom locked
J28 "693071020811" 693071020811 119.487,337.182 r90 bottom locked
J29 "SYSMON_VP_VN" "MOLEX KK 0022272021" 371.78,139.789 r0 top
J30 "DxN_DxP" "MOLEX KK 0022272021" 363.703,139.789 r0 top
J31 "SFP Connector" 2007132 37.104,262.472 r90 bottom locked
J32 "1703820001" 1703820001 63.005,279.047 r90 bottom locked
J33 "1703820001" 1703820001 63.005,307.547 r90 bottom locked
J34 "1703820001" 1703820001 63.005,264.797 r90 bottom locked
J35 "1703820001" 1703820001 63.004,293.297 r90 bottom locked
J36 "Key" "MOLEX KK 0022272021" 387.071,188.519 r0 top
L1 "NRS4018T4R7MDGJV" NRS8040 79.329,264.987 r0 top
L2 "NRS4018T4R7MDGJV" NRS8040 73.055,264.987 r0 top
L3 "NRS4018T4R7MDGJV" NRS8040 91.846,279.997 r0 top
L4 "NRS4018T4R7MDGJV" NRS8040 85.573,279.997 r0 top
L5 "NRS4018T4R7MDGJV" NRS8040 87.768,298.256 r0 top
L6 "NRS4018T4R7MDGJV" NRS8040 81.494,298.256 r0 top
L7 "NRS4018T4R7MDGJV" NRS8040 87.768,306.777 r0 top
L8 "NRS4018T4R7MDGJV" NRS8040 81.494,306.777 r0 top
L9 "MGV0605R22M-10" MGV0605 93.417,240.05 r0 top
L10 "MGV0605R22M-10" MGV0605 93.442,231.202 r0 top
L11 "MGV10041R2M-10" "MGV1004 Series" 89.295,183.236 r0 top
L12 "744373560068" 744373560068 88.108,168.37 r0 top
L13 "CDRH5D28-8R2" CDRH5D28 321.272,457.225 r90 top
L15 "Inductance" FB0603 422.25,34.76 r0 top
L16 "CDRH5D28-4R2" CDRH5D28 437.54,57.899 r0 top
L17 "CDRH5D28-8R2" CDRH5D28 563.182,78.562 r0 top
L18 "CDRH4D28NP-3R3NC" CDRH4D28NP 430.098,59.55 r0 top
L19 "3.3uH, 13.8A" WE-CHSA_1011 87.928,213.721 r0 top
L20 "1.5 uH, 16.5 A" WE-HCC_8070 87.389,197.752 r0 top
L22 "SRP1265A-220M" SRP1265A-220M 37.948,227.19 r90 top locked
MP1_PCIE0 "M2x2.5mm" 9774025243 288.976,171.069 r90 top (schematic designator MP1)
MP1_PCIE1 "M2x2.5mm" 9774025243 288.976,181.153 r90 top (schematic designator MP1)
MP1_PCIE2 "M2x2.5mm" 9774025243 288.976,191.237 r90 top (schematic designator MP1)
MP1_PCIE3 "M2x2.5mm" 9774025243 288.976,201.32 r90 top (schematic designator MP1)
MP1_PCIE4 "M2x2.5mm" 9774025243 288.976,211.404 r90 top (schematic designator MP1)
MP2_PCIE0 "M2x2.5mm" 9774025243 303.454,171.069 r90 top (schematic designator MP2)
MP2_PCIE1 "M2x2.5mm" 9774025243 302.946,181.153 r90 top (schematic designator MP2)
MP2_PCIE2 "M2x2.5mm" 9774025243 303.454,191.237 r90 top (schematic designator MP2)
MP2_PCIE3 "M2x2.5mm" 9774025243 303.454,201.32 r90 top (schematic designator MP2)
MP2_PCIE4 "M2x2.5mm" 9774025243 304.181,219.71 r90 top (schematic designator MP2)
MP3_PCIE0 "M2x2.5mm" 9774025243 318.186,171.069 r90 top (schematic designator MP3)
MP3_PCIE1 "M2x2.5mm" 9774025243 317.17,181.153 r90 top (schematic designator MP3)
MP3_PCIE2 "M2x2.5mm" 9774025243 318.186,191.237 r90 top (schematic designator MP3)
MP3_PCIE3 "M2x2.5mm" 9774025243 318.186,201.32 r90 top (schematic designator MP3)
MP3_PCIE4 "M2x2.5mm" 9774025243 318.186,211.404 r90 top (schematic designator MP3)
P1 "Header 3" HDR1X3 122.247,652.894 r90 top
P2 "Header 4" HDR1X4 237.071,352.323 r270 top
P3 "Header 2" HDR1X2 67.041,437.464 r90 top
P4 "Header 2" HDR1X2 68.946,436.829 r90 top
P5 "Header 2" HDR1X2 71.867,436.448 r90 top
P6 "640456-2" TECO-640456-2_V 16.502,538.67 r0 top
P7 "Plug" PIN1 300.774,247.764 r90 top
P8 "Plug" PIN1 300.774,251.066 r0 top
P9 "Plug" PIN1 351.752,263.042 r90 top
P10 "Plug" PIN1 351.498,258.089 r0 top
P11 "Header 2" HDR1X2 370.942,78.054 r90 top
P12 "Header 7X2" HDR2X7 215.824,66.7 r90 top
P13 "Header 3" HDR1X3 198.222,235.864 r90 top
R1 "0R" "RES 0402/1005 RF" 379.959,185.649 r0 top
R2 "0R" "RES 0402/1005 RF" 375.628,185.649 r0 top
R3_I2C_Bridge_GPIO "1kR" "RES 0402/1005 RF" 521.872,300.439 r90 top (schematic designator R3)
R3_I2C_Bridge_PCIE "1kR" "RES 0402/1005 RF" 100.82,390.989 r90 top (schematic designator R3)
R3_I2C_Bridge_SFP "1kR" "RES 0402/1005 RF" 84.834,293.434 r90 top (schematic designator R3)
R4_I2C_Bridge_GPIO "1kR" "RES 0402/1005 RF" 520.196,300.363 r90 top (schematic designator R4)
R4_I2C_Bridge_PCIE "1kR" "RES 0402/1005 RF" 101.82,390.989 r90 top (schematic designator R4)
R4_I2C_Bridge_SFP "1kR" "RES 0402/1005 RF" 85.912,293.434 r90 top (schematic designator R4)
R5_I2C_Bridge_GPIO "1kR" "RES 0402/1005 RF" 518.202,300.253 r90 top (schematic designator R5)
R5_I2C_Bridge_PCIE "1kR" "RES 0402/1005 RF" 102.895,390.989 r90 top (schematic designator R5)
R5_I2C_Bridge_SFP "1kR" "RES 0402/1005 RF" 86.989,293.434 r90 top (schematic designator R5)
R6_I2C_Bridge_GPIO "1kR" "RES 0402/1005 RF" 516.742,300.223 r90 top (schematic designator R6)
R6_I2C_Bridge_PCIE "1kR" "RES 0402/1005 RF" 103.955,390.989 r90 top (schematic designator R6)
R6_I2C_Bridge_SFP "1kR" "RES 0402/1005 RF" 88.067,293.434 r90 top (schematic designator R6)
R7_I2C_Bridge_GPIO "1kR" "RES 0402/1005 RF" 515.065,300.096 r90 top (schematic designator R7)
R7_I2C_Bridge_PCIE "1kR" "RES 0402/1005 RF" 105.028,390.989 r90 top (schematic designator R7)
R7_I2C_Bridge_SFP "1kR" "RES 0402/1005 RF" 89.144,293.434 r90 top (schematic designator R7)
R8_I2C_Bridge_GPIO "1kR" "RES 0402/1005 RF" 513.147,299.601 r90 top (schematic designator R8)
R8_I2C_Bridge_PCIE "1kR" "RES 0402/1005 RF" 106.896,388.645 r0 top (schematic designator R8)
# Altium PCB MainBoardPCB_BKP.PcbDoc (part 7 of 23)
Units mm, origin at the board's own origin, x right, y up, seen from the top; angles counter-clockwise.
Board outline 258.95 x 308.86 mm, 16 copper layers (L1, L2 (GND), L3 (Sign), L4 (GND), L5 (Sign), L6 (PWR/GND), L7(PWR/GND), L8 (Plane_GND), L9 (PWR/GND), L10 (PWR/GND), L11 (PWR/GND), L12 (Sign), L13 (GND), L14 (Sign), L15 (GND), L16), stack 2.502 mm thick; 2361 components, 1770 nets, 8410 pads, 3259 vias.
Unrouted connection lines stored in the file: 4700.

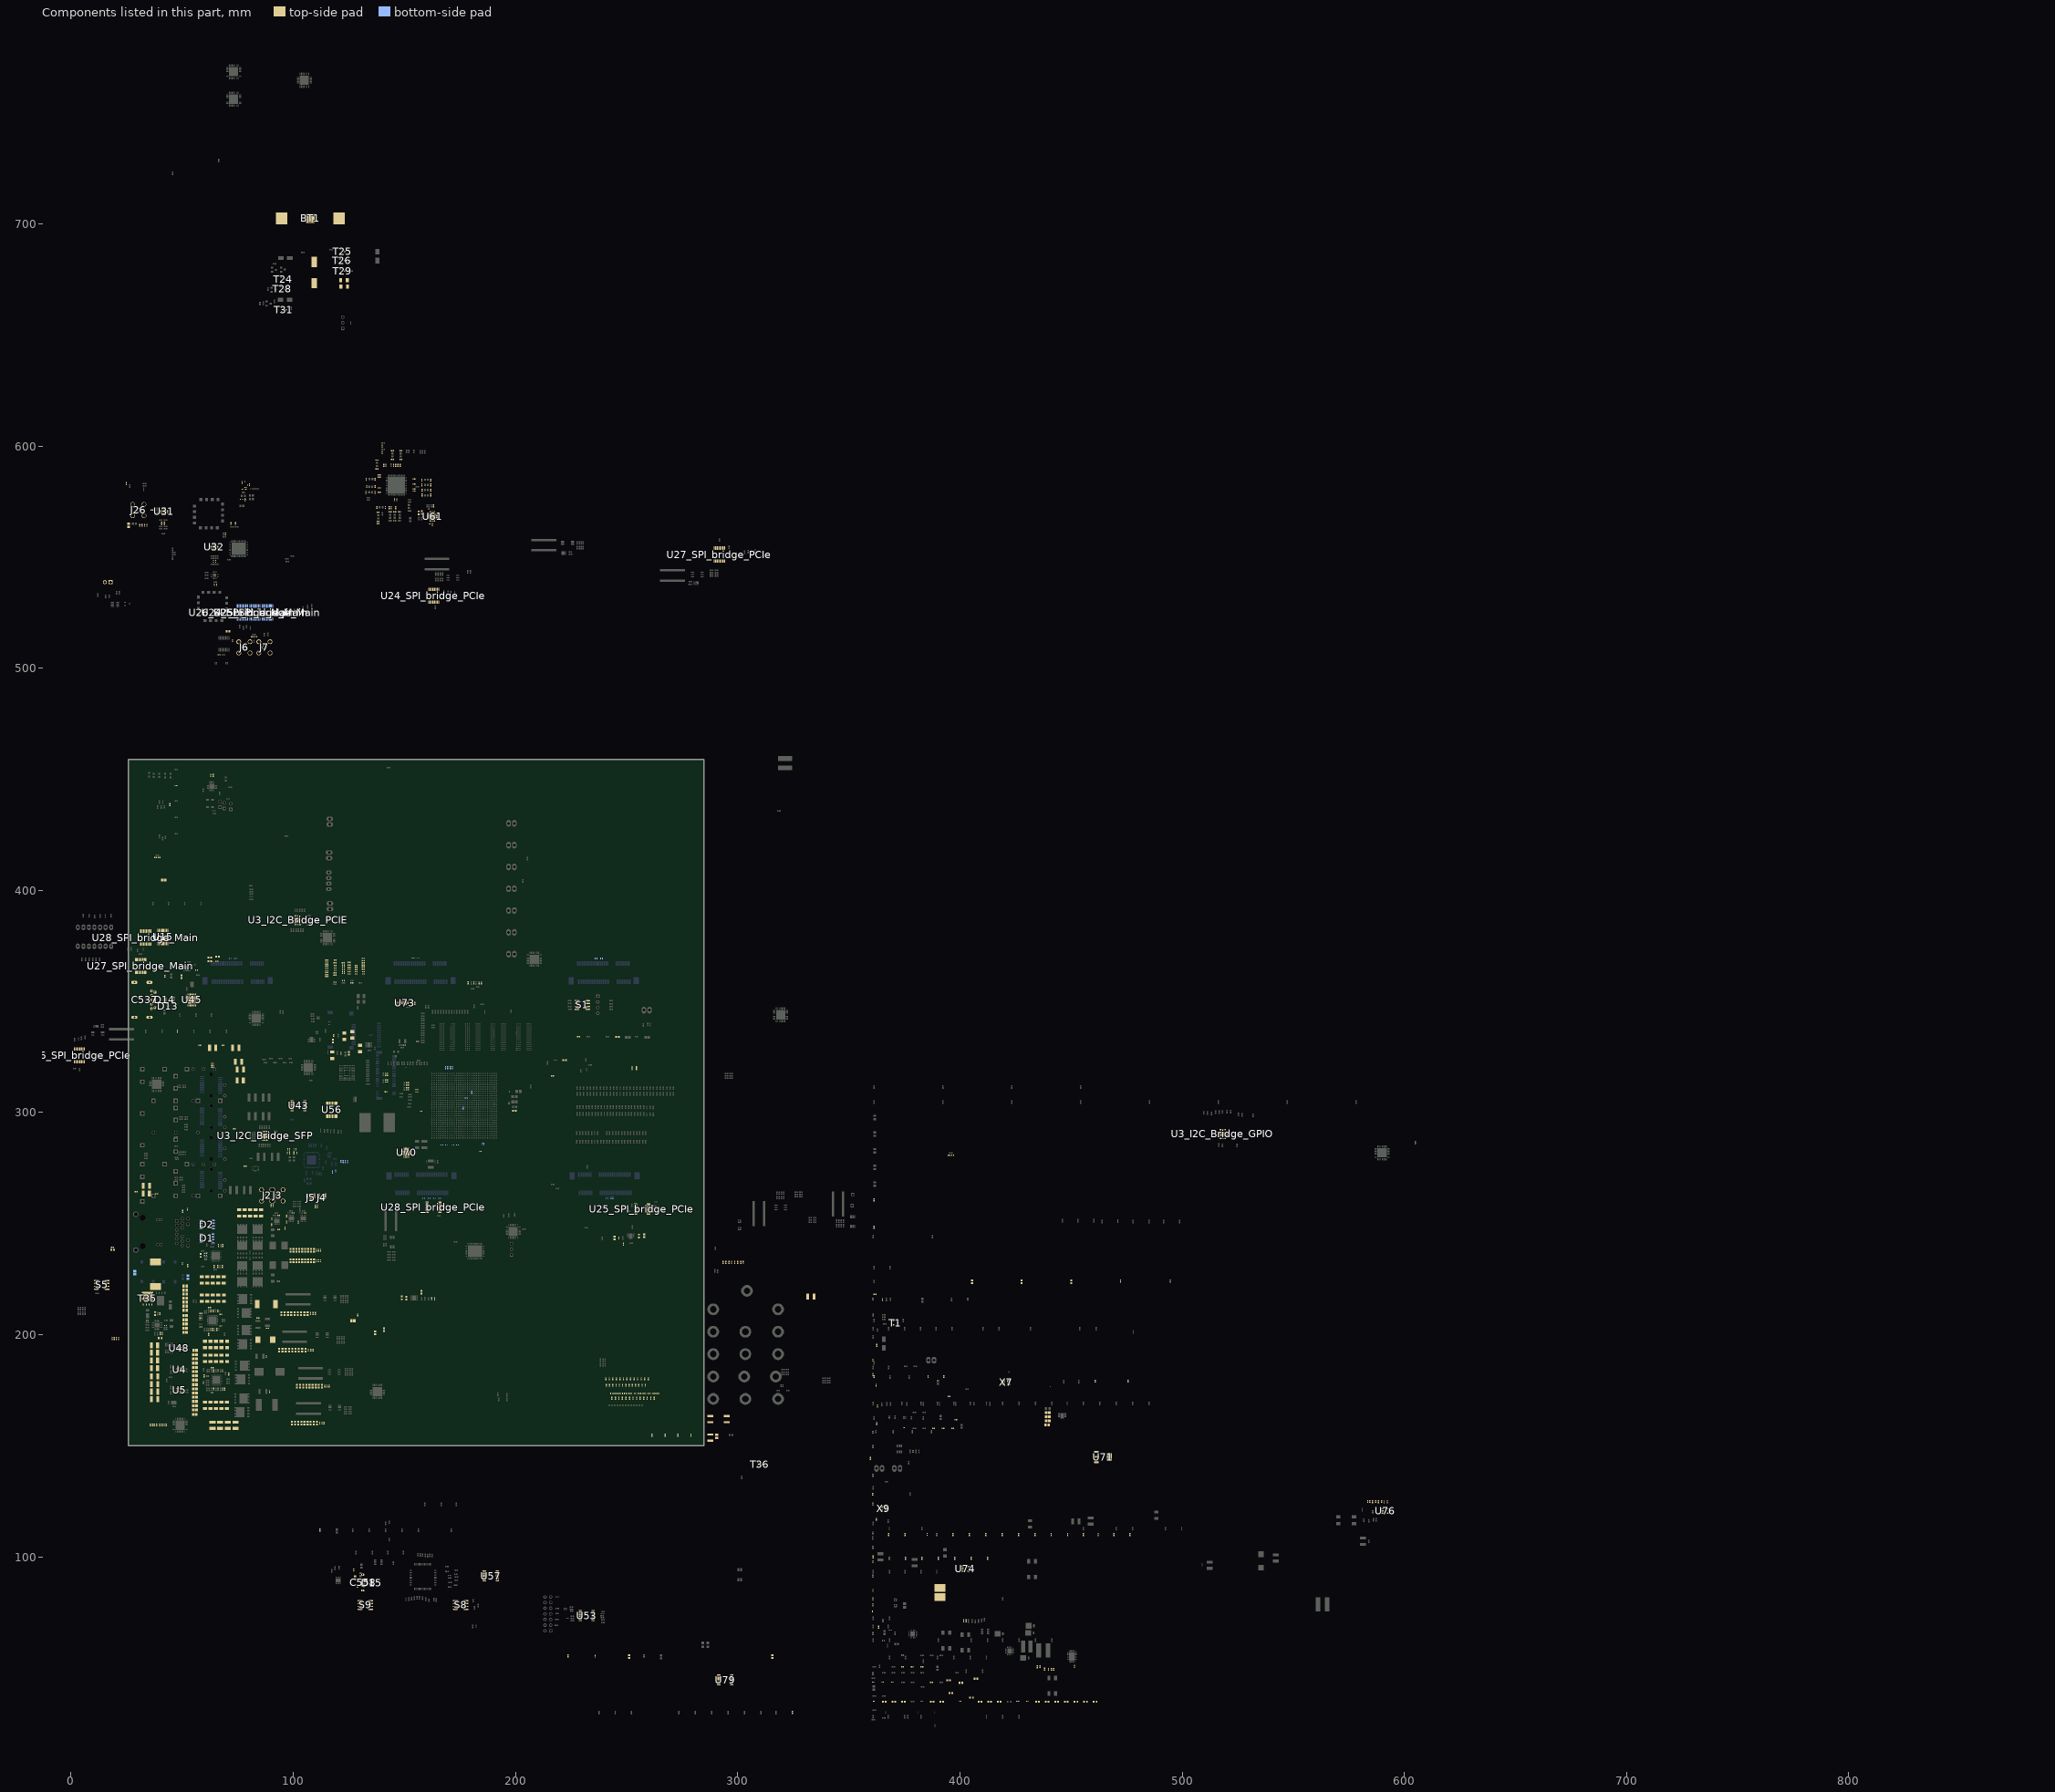
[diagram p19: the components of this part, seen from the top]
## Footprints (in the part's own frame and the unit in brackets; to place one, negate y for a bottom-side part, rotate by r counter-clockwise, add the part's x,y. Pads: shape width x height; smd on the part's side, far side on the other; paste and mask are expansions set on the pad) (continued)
SI2342DS-T1-GE3 [mm] "SOT23, 3-Leads, Body 2,92x2,37mm, Pitch 0,95mm, IPC High Density"
  rect 0.724x0.6 smd: 1(-0.984,0.95) 2(-0.984,-0.95) 3(0.984,0)
  silkscreen extent -1.11,-1.5 0.7,1.92, body extent -1.32,-1.52 1.32,1.52, height 1.12
SI53323-B-GM [mm] "QFN, 16-Leads, Body 3,00x3,00mm, Pitch 0,50mm, Thermal Pad 1,75x1,75mm, IPC High Density"
  rect 0.8x0.3 smd: 1(-1.5,0.75) 2(-1.5,0.25) 3(-1.5,-0.25) 4(-1.5,-0.75) 9(1.5,-0.75) 10(1.5,-0.25) 11(1.5,0.25) 12(1.5,0.75)
  rect 0.3x0.8 smd: 5(-0.75,-1.5) 6(-0.25,-1.5) 7(0.25,-1.5) 8(0.75,-1.5) 13(0.75,1.5) 14(0.25,1.5) 15(-0.25,1.5) 16(-0.75,1.5)
  rect 1.75x1.75 smd: 17(0,0)
  silkscreen extent -2.42,-1.65 1.65,1.65, body extent -1.5,-1.5 1.5,1.5, height 0.9
SiJ482DP [mm] "PowerPAK® SO-8L Case Outline 1"
  rect 0.82x0.41 smd: 1(-2.715,1.905) 2(-2.715,0.635) 3(-2.715,-0.635) 4(-2.715,-1.905)
  rect 3.63x4.061 smd: 5(0.75,0)
  rect 0.61x0.595 smd: ""(-0.05,2.286) ""(-0.05,-2.286)
  rect 0.51x5 smd: ""(2.8,0)
  silkscreen extent -2.84,-2.65 -1.47,2.78, body extent -2.67,-2.63 3.48,2.63, height 1.14
SiT1602B [mm] "2.5 x 2.0 x 0.75 mm"
  rect 1.1x1 smd: 1(-0.95,-0.75) 2(0.95,-0.75) 3(0.95,0.75) 4(-0.95,0.75)
  silkscreen extent -1.76,-1.31 -1.66,-1.21, body extent -1.28,-1.02 1.28,1.02, height 0.8
SLVU2.8-4 [mm] "SOIC-8 Pins 8"
  rect 1.3x0.6 smd: 1(-2.75,1.905) 2(-2.75,0.635) 3(-2.75,-0.635) 4(-2.75,-1.905) 5(2.75,-1.905) 6(2.75,-0.635) 7(2.75,0.635) 8(2.75,1.905)
  silkscreen extent -2.87,-2.5 1.6,2.88, body extent -3,-2.5 3,2.5, height 1.75
SN74AXC4T774PWR [mm] "TSOP,PW0016A, 16-Leads, Body 5,00x4,40mm, Pitch 0,65mm, IPC High Density"
  rect 1.5x0.45 smd: 1(-2.9,2.275) 2(-2.9,1.625) 3(-2.9,0.975) 4(-2.9,0.325) 5(-2.9,-0.325) 6(-2.9,-0.975) 7(-2.9,-1.625) 8(-2.9,-2.275) 9(2.9,-2.275) 10(2.9,-1.625) 11(2.9,-0.975) 12(2.9,-0.325) 13(2.9,0.325) 14(2.9,0.975) 15(2.9,1.625) 16(2.9,2.275)
  silkscreen extent -3.02,-2.55 1.85,3.17, body extent -3.2,-2.55 3.2,2.55, height 1.2
SN74LVC1G08DBVR [mm] "SOT23, 5-Leads, Body 2,90x2,80mm, Pitch 0,95mm, IPC High Density"
  rect 1.1x0.6 smd: 1(-1.3,0.95) 2(-1.3,0) 3(-1.3,-0.95) 4(1.3,-0.95) 5(1.3,0.95)
  silkscreen extent -1.42,-1.55 0.5,1.92, body extent -1.5,-1.53 1.5,1.53, height 1.45
SO8_N [mm] "SOIC, 8-Leads, Body 4.9x3.9mm, Pitch 1.27mm, IPC Medium Density"
  oval 2.2x0.6 smd: 1(-2.4,1.905) 2(-2.4,0.635) 3(-2.4,-0.635) 4(-2.4,-1.905) 5(2.4,-1.905) 6(2.4,-0.635) 7(2.4,0.635) 8(2.4,1.905)
  silkscreen extent -2.53,-2.5 0.9,2.88, body extent -2,-2.5 2,2.5, height 1.75
SRP1265A-220M [mm] "Precision Wire Wound Inductor, 2-Leads, Body 13,50x12,50mm, IPC High Density"
  rect 3.1x5 smd: 1(-5.55,0) 2(5.55,0)
  silkscreen extent -7,-6.4 7,6.4, body extent -6.85,-6.25 6.85,6.25, height 6.6
ST1L08 [mm] "DFN8 (2x3 mm) package outline"
  rect 0.5x0.3 smd: 1(-1.4,0.75) 2(-1.4,0.25) 3(-1.4,-0.25) 4(-1.4,-0.75) 5(1.4,-0.75) 6(1.4,-0.25) 7(1.4,0.25) 8(1.4,0.75)
  rect 1.9x1.75 smd: 9(0,0)
  silkscreen extent -1.91,1.06 -1.81,1.16, body extent -1.5,-1 1.5,1, height 0.9
TCA9548 [mm]
  rect 0.6x0.26 smd: 1(-1.935,1.25) 2(-1.935,0.75) 3(-1.935,0.25) 4(-1.935,-0.25) 5(-1.935,-0.75) 6(-1.935,-1.25) 13(1.935,-1.25) 14(1.935,-0.75) 15(1.935,-0.25) 16(1.935,0.25) 17(1.935,0.75) 18(1.935,1.25)
  rect 0.26x0.6 smd: 7(-1.25,-1.935) 8(-0.75,-1.935) 9(-0.25,-1.935) 10(0.25,-1.935) 11(0.75,-1.935) 12(1.25,-1.935) 19(1.25,1.935) 20(0.75,1.935) 21(0.25,1.935) 22(-0.25,1.935) 23(-0.75,1.935) 24(-1.25,1.935)
  rect 2.1x2.1 smd paste-100: 25(0,0)
  silkscreen extent -2.88,-2 2,2
TECO-5-1814832-1_V [mm] "THD, 5-Leads, Body 6.4x6.4mm, Pitch 5.08mm"
  round 2 hole 1.5: 1(0,0)
  round 2.1 hole 1.6: 2(-2.54,2.54) 3(-2.54,-2.54) 4(2.54,-2.54) 5(2.54,2.54)
  silkscreen extent -3.2,-3.2 3.2,3.2, body extent -3.21,-3.21 3.19,3.19, height 9.5
TECO-640456-2_V [mm] "HDR, 2-Leads, Body 5.715x5.08mm, Pitch 2.54mm"
  rect 1.8x1.8 hole 1.3: 1(1.27,0)
  round 1.8 hole 1.3: 2(-1.27,0)
  silkscreen extent -2.54,-2.54 3.26,3.17, body extent -2.54,-2.67 2.54,3.17, height 10.49
TECO-1909763-1_V [mm] "SMD, 3-Leads, Body 2.6x2.6mm, Height 1.25mm"
  rect 1.05x2.2 smd: 1(-1.475,0) 3(1.475,0)
  rect 1x1.05 smd: 2(0,-1.525)
  silkscreen extent -1.9,-1.77 0.55,1.3, body extent -1.5,-1.55 1.5,1.55, height 1.25
TestPoint [mm] "TestPoint,  Body 1,00x2,54x4,60mm, IPC Low Density"
  silkscreen extent -0.37,-1.27 0.5,1.27, body extent -1.27,-1.27 1.26,1.27, height 4.6
TPD2EUSB30 [mm] "SOT23, 3-Leads, Body 1,00x1,00mm, Pitch 0,35mm, IPC High Density"
  rect 0.3x0.3 smd: 1(-0.425,0.35) 2(-0.425,-0.35) 3(0.425,0)
  silkscreen extent -0.55,-0.55 0.43,1.17, body extent -0.6,-0.53 0.6,0.53, height 0.5
TPD4EUSB30 [mm] "DQA0010A, 10-Leads, Body 2,50x1,00mm, Pitch 0,50mm, IPC High Density"
  rect 0.565x0.2 smd: 1(-0.417,1) 2(-0.418,0.5) 4(-0.417,-0.5) 5(-0.417,-1) 6(0.417,-1) 7(0.417,-0.5) 9(0.417,0.5) 10(0.417,1)
  rect 0.565x0.4 smd paste-0.04: 3(-0.417,0) 8(0.417,0)
  silkscreen extent -1,-1.45 0.55,1.5, body extent -0.63,-1.3 0.63,1.3, height 0.55
TPS7A88 [mm] "RTJ (S-PWQFN-N20) 20-Leads, Body 4,00x4,00mm, Pitch 0,50mm, Thermal Pad 2,70x2,70mm, IPC High Density"
  rect 0.85x0.28 smd: 1(-1.975,1) 2(-1.975,0.5) 3(-1.975,0) 4(-1.975,-0.5) 5(-1.975,-1) 11(1.975,-1) 12(1.975,-0.5) 13(1.975,0) 14(1.975,0.5) 15(1.975,1)
  rect 0.28x0.85 smd: 6(-1,-1.975) 7(-0.5,-1.975) 8(0,-1.975) 9(0.5,-1.975) 10(1,-1.975) 16(1,1.975) 17(0.5,1.975) 18(0,1.975) 19(-0.5,1.975) 20(-1,1.975)
  rect 2.7x2.7 smd paste-3: 21(0,0)
  silkscreen extent -2.85,-2.08 2.07,2.07, body extent -2.07,-2.07 2.07,2.07, height 0.8
TPS212x [mm] "VQFN-HR - 1 mm max height"
  rect 1.05x0.4 smd: 1(-0.675,0.35) 2(-0.675,-0.35) 7(0.675,-0.35) 8(0.675,0.35)
  rect 0.2x0.6 smd: 3(-0.75,-1.15) 4(-0.25,-1.15) 5(0.25,-1.15) 6(0.75,-1.15) 9(0.75,1.15) 10(0.25,1.15) 11(-0.25,1.15) 12(-0.75,1.15)
  silkscreen extent -1.82,-1.3 1.05,1.3, body extent -1.05,-1.3 1.05,1.3, height 1
"TSX-3225 24.0000MF15X-AC6" [mm] "Ceramic Package, 4-Leads, Body 2,50x3,20mm, Pitch 1,60mm, IPC High Density"
  rect 1.4x1.15 smd: 1(-1.1,-0.8) 2(1.1,-0.8) 3(1.1,0.8) 4(-1.1,0.8)
  silkscreen extent -2,-1.7 -1.9,-1.6, body extent -1.6,-1.25 1.6,1.25, height 0.6
UA78M [mm] "SOT223, 4-Leads, DCY (R-PDSO-G4)"
  rect 2.15x0.95 smd: 1(-2.9,2.3) 2(-2.9,0) 3(-2.9,-2.3)
  rect 2.15x3.25 smd: 2(2.9,0)
  silkscreen extent -3.02,-3.35 2.05,3.45, body extent -3.5,-3.35 3.5,3.35, height 1.8
USB3320 [mm] "32-PIN QFN, 5X5MM BODY, 0.5MM PITCH"
  rect 0.75x0.25 smd: 1(-2.45,1.75) 2(-2.45,1.25) 3(-2.45,0.75) 4(-2.45,0.25) 5(-2.45,-0.25) 6(-2.45,-0.75) 7(-2.45,-1.25) 8(-2.45,-1.75) 17(2.45,-1.75) 18(2.45,-1.25) 19(2.45,-0.75) 20(2.45,-0.25) 21(2.45,0.25) 22(2.45,0.75) 23(2.45,1.25) 24(2.45,1.75)
  rect 0.25x0.75 smd: 9(-1.75,-2.45) 10(-1.25,-2.45) 11(-0.75,-2.45) 12(-0.25,-2.45) 13(0.25,-2.45) 14(0.75,-2.45) 15(1.25,-2.45) 16(1.75,-2.45) 25(1.75,2.45) 26(1.25,2.45) 27(0.75,2.45) 28(0.25,2.45) 29(-0.25,2.45) 30(-0.75,2.45) 31(-1.25,2.45) 32(-1.75,2.45)
  rect 3.3x3.3 smd paste-2: 33(0,0)
  silkscreen extent -3.47,2.43 -3.22,2.67, body extent -2.57,-2.57 2.57,2.57, height 1
WE-CHSA_1011 [mm] "SMT High Current Inductor, 2-Leads, body 10.6x10.6mm"
  rect 2.05x3.6 smd: 1(-4.05,0) 2(4.05,0)
  silkscreen extent -5.45,-5.45 5.45,5.45, body extent -5.3,-5.3 5.3,5.3, height 11
WE-HCC_8070 [mm] "SMT High Current Cube Inductor, 2-Leads, body 7.9x7.9mm"
  rect 2.3x3 smd: 1(-3.35,0) 2(3.35,0)
  silkscreen extent -4.1,-4.1 4.1,4.1, body extent -4.2,-3.95 4.2,3.95, height 7.23
WSHP2818 [mm] "Chip Resistor, 2-Leads, Body 7,10x4,60mm, IPC High Density"
  rect 3.5x5.1 smd: 1(-2.055,0) 2(2.055,0)
  body extent -3.67,-2.42 3.67,2.42, height 1.75

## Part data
B1: "BATT LITH 1.5V 5.5MAH COIN 9.5MM", Capacity=5.5mAh, Manufacturer=Seiko, Supplier Part Number 1=728-1082-ND, Voltage Rating=1.5V
BT1: "WA-BCMC Battery Holder, SMT, Battery Type 2016/2020/2025/2032"
C1 C3 C41 C42 C341 C479 C482 C483 C484 C540 C541 C542 C543 C732 C735 C790: library part Capacitor, Case/Package=0402, Case Code (Metric)=1005, Dielectric=X7R, Dielectric Material=Ceramic, Insulation Resistance=10GR, Manufacturer=Murata, Manufacturer Part Number=GRM155R71C104KA88D, Max Operating Temperature=125°C, Min Operating Temperature=-55°C, Package Quantity=1, Supplier Part Number 1=490-3261-6-ND, Tolerance=10%, Voltage=16V
C2: library part Capacitor, Case/Package=0402, Dielectric=X7R, Dielectric Material=Ceramic, Insulation Resistance=10GR, Manufacturer=Murata, Manufacturer Part Number=GRM155R71C104KA88D, Max Operating Temperature=125°C, Min Operating Temperature=-55°C, Package Quantity=1, Supplier Part Number 1=490-3261-6-ND, Tolerance=10%, Voltage=16V
C4 C5 C6 C7 C12 C13 C14 C15 C38 C40 C212 C214 C216 C218 C766 C767 C768 C769: library part Capacitor, Case Code (Imperial)=1210, Case Code (Metric)=3225, Dielectric=X5R, Manufacturer=Samsung, Manufacturer Part Number=CL32A226KAJNNNE, Max Operating Temperature=85°C, Min Operating Temperature=-55°C, Package Quantity=1, Supplier Part Number 1=1276-1101-1-ND, Tolerance=10%, Voltage=25V
C8 C9 C10 C11 C16 C17 C18 C19 C37 C39 C211 C213 C215 C217 C770 C771 C772 C773: library part Capacitor, Case Code (Imperial)=0402, Case Code (Metric)=1005, Dielectric=X7R, Manufacturer=Murata, Manufacturer Part Number=GRM155R71E104KE14J, Max Operating Temperature=125°C, Min Operating Temperature=-55°C, Package Quantity=50000, Supplier Part Number 1=490-14603-1-ND, Tolerance=10%, Voltage Rating=25V
C20 C21 C22 C23 C28 C29 C30 C31 C574 C575 C581 C774 C775 C776 C777: library part Capacitor, "CAP CER 10UF 25V X5R 0805", Case Code (Imperial)=0805, Case Code (Metric)=2012, Dielectric=X5R, Dielectric Material=Ceramic, Manufacturer=KEMET, Manufacturer Part Number=C0805C106K3PACTU, Max Operating Temperature=85°C, Min Operating Temperature=-55°C, Supplier Part Number 1=399-11939-6-ND, Tolerance=10%, Voltage=25V
C24 C25 C26 C27 C32 C33 C34 C35 C580 C582 C584 C778 C779 C780: library part Capacitor, "CAP CER 4.7UF 25V X5R 0805", Case Code (Imperial)=0805, Case Code (Metric)=2012, Dielectric=X5R, Manufacturer=Murata, Manufacturer Part Number=GRM219R61E475KA73D, Max Operating Temperature=85°C, Min Operating Temperature=-55°C, Package Quantity=4000, Supplier Part Number 1=490-12753-1-ND, Tolerance=10%, Voltage Rating=25V
C36: library part Capacitor, Case/Package=0402, Case Code (Metric)=1005, Dielectric=X7R, Dielectric Material=Ceramic, Manufacturer=KEMET, Manufacturer Part Number=C0402C103K4RACTU, Max Operating Temperature=125°C, Min Operating Temperature=-55°C, Package Quantity=1, Supplier Part Number 1=399-1038-1-ND, Tolerance=10%, Voltage=16V
C43 C44 C47 C48 C49 C50 C51 C52 C340: library part Capacitor, Case Code (Imperial)=0402, Dielectric=X5R, Dielectric Material=Ceramic, Manufacturer=KEMET, Manufacturer Part Number=C0402C105K9PACTU, Max Operating Temperature=85°C, Min Operating Temperature=-55°C, Package Quantity=1, Supplier Part Number 1=399-4873-6-ND, Tolerance=10%, Voltage=6.3V
C45: library part Capacitor, "Cap Ceramic 0.0056uF 25V X7R 10% SMD 0402 125C Paper T/R", Case Code (Imperial)=0402, Case Code (Metric)=1005, Dielectric=X7R, Manufacturer=Yageo, Manufacturer Part Number=CC0402KRX7R8BB562, Max Operating Temperature=125°C, Min Operating Temperature=-55°C, Supplier Part Number 1=311-1718-1-ND, Tolerance=10%, Voltage Rating=25V
C46: library part Capacitor, "Multilayer Ceramic Capacitors MLCC - SMD/SMT 200pF 50V NPO 5%", Case Code (Imperial)=0402, Case Code (Metric)=1005, Dielectric=C0G, Manufacturer=Yageo, Manufacturer Part Number=CC0402JRNPO9BN201, Max Operating Temperature=125°C, Min Operating Temperature=-55°C, Supplier Part Number 1=311-1664-1-ND, Tolerance=5%, Voltage Rating=50V
C55 C56 C57 C59 C60 C61 C65 C66 C71 C72 C73 C84 C85 C94 C95: library part Capacitor, "SMT Capacitor", Part Number=GRM033R61C104ME84D, Supplier Part Number 1=490-9986-1-ND
C58 C62 C69 C74 C87 C98: library part Capacitor, "SMT Capacitor", Part Number=AMK105CBJ106MV-F, Supplier Part Number 1=587-3237-1-ND
C63 C64 C67 C70 C75 C76 C77 C81 C82 C83 C88 C89 C90 C91 C92 C93 C96 C99 C100 C103 C104 C107 C108 C124 C125 C141 C142 C145 C146 C162 C163 C179 C336 C337 C338 C578 C579 C583 C590: library part Capacitor, "CAP CER 0.1UF 50V X5R 0402", Case Code (Imperial)=0402, Case Code (Metric)=1005, Dielectric=X5R, Dielectric Material=Ceramic, Manufacturer=Murata, Manufacturer Part Number=GRM155R61H104KE14D, Max Operating Temperature=85°C, Min Operating Temperature=-55°C, Package Quantity=10000, Supplier Part Number 1=490-10697-1-ND, Tolerance=10%, Voltage=50V
C68 C86 C97 C111 C112 C113 C114 C115 C116 C117 C118 C119 C120 C121 C122 C123 C149 C150 C151 C152 C153 C154 C155 C156 C157 C158 C159 C160 C161 C166 C167 C168 C169 C170 C171 C172 C173 C174 C175 C176 C177 C178 C333 C344 C573 C577: library part Capacitor, "Cap Ceramic 0.01uF 16V X5R 10% SMD 0201 85C Paper T/R", Case Code (Imperial)=0201, Case Code (Metric)=0603, Dielectric=X5R, Manufacturer=Yageo, Manufacturer Part Number=CC0201KRX5R7BB103, Max Operating Temperature=85°C, Min Operating Temperature=-55°C, Supplier Part Number 1=311-1596-1-ND, Tolerance=10%, Voltage Rating=16V
C78 C79 C80 C101 C102 C105 C106 C109 C110 C126 C127 C143 C144 C147 C148 C164 C165 C180 C591: library part Capacitor, "CAP CER 10UF 10V X5R 0402", Case Code (Imperial)=0402, Case Code (Metric)=1005, Manufacturer=Samsung, Manufacturer Part Number=CL05A106MP8NUB8, Max Operating Temperature=85°C, Min Operating Temperature=-55°C, Supplier Part Number 1=1276-6830-1-ND, Tolerance=20%, Voltage Rating=10V
C128 C129 C130 C131 C132 C133 C134 C135 C136 C137 C138 C139 C140 C181 C182 C183 C184 C185 C186 C187 C188 C189 C190 C191 C192 C193 C194 C195 C196 C197 C198 C199 C200 C201 C202 C203 C204 C205 C206: library part Capacitor, "CAP CER 1UF 10V X5R 0402", Case Code (Imperial)=0402, Case Code (Metric)=1005, Dielectric=X5R, Manufacturer=Yageo, Manufacturer Part Number=CC0402KRX5R6BB105, Max Operating Temperature=85°C, Min Operating Temperature=-55°C, Package Quantity=1, Supplier Part Number 1=311-1439-1-ND, Tolerance=10%, Voltage Rating=10V
C207 C209 C312 C313 C314: library part Capacitor, Case/Package=0402, Case Code (Metric)=1005, Dielectric=X7R, Manufacturer=Murata, Manufacturer Part Number=GRM155R71E104KE14J, Max Operating Temperature=125°C, Min Operating Temperature=-55°C, Package Quantity=50000, Supplier Part Number 1=490-14603-1-ND, Tolerance=10%, Voltage Rating=25V
C208 C210: library part Capacitor, Case/Package=1210, Case Code (Metric)=3225, Dielectric=X5R, Manufacturer=Samsung, Manufacturer Part Number=CL32A226KAJNNNE, Max Operating Temperature=85°C, Min Operating Temperature=-55°C, Package Quantity=1, Supplier Part Number 1=1276-1101-1-ND, Tolerance=10%, Voltage=25V
C219 C220 C221 C222 C243 C244 C245 C246 C359 C377 C566_U_5V_to_3V31 C566_U_5V_to_3V32 C566_U_5V_to_3V33: library part Capacitor, Case Code (Imperial)=0402, Case Code (Metric)=1005, Dielectric=X5R, Insulation Resistance=10GR, Manufacturer=Yageo, Manufacturer Part Number=CC0402KRX5R6BB104, Max Operating Temperature=85°C, Min Operating Temperature=-55°C, Package Quantity=1, Supplier Part Number 1=311-1336-1-ND, Tolerance=10%, Voltage Rating=10V
C223 C228 C233 C238 C247 C252 C257 C262 C550 C552 C554 C568 C569 C570: library part Capacitor, "0402 10 V 4.7 uF ±20% Tolerance X5R Multilayer Ceramic Chip Capacitor", Case Code (Imperial)=0402, Case Code (Metric)=1005, Manufacturer=Murata, Manufacturer Part Number=GRM155R61A475MEAAD, Max Operating Temperature=85°C, Min Operating Temperature=-55°C, Supplier Part Number 1=490-14306-1-ND, Tolerance=20%, Voltage Rating=10V
C224 C225 C229 C230 C234 C235 C239 C240 C248 C249 C253 C254 C258 C259 C263 C264: library part Capacitor, "Cap Ceramic 0.47uF 10V X5R 10% SMD 0402 85C Paper T/R", Case Code (Imperial)=0402, Case Code (Metric)=1005, Dielectric=X5R, Manufacturer=Samsung, Manufacturer Part Number=CL05A474KP5NNNC, Max Operating Temperature=85°C, Min Operating Temperature=-55°C, Supplier Part Number 1=1276-1173-1-ND, Tolerance=10%, Voltage Rating=10V
C226 C227 C231 C232 C236 C237 C241 C242 C250 C251 C255 C256 C260 C261 C265 C266: library part Capacitor, "KEMET - C0402C683K4RACTU - CAP, 0.068µF, 16V, 10%, X7R, 0402", Case Code (Imperial)=0402, Case Code (Metric)=1005, Dielectric=X7R, Dielectric Material=Ceramic, Manufacturer=KEMET, Manufacturer Part Number=C0402C683K4RACTU, Max Operating Temperature=125°C, Min Operating Temperature=-55°C, Package Quantity=1, Supplier Part Number 1=399-4904-1-ND, Tolerance=10%, Voltage=16V
C267 C269 C271 C274 C279 C281 C283 C286 C291 C293 C295 C298: library part Capacitor, "CAP CER 0.1UF 16V X5R 0201", Case Code (Metric)=0603, Case/Package=0201, Dielectric=X5R, Manufacturer=Murata, Manufacturer Part Number=GRM033R61C104ME84D, Max Operating Temperature=85°C, Min Operating Temperature=-55°C, Package Quantity=15000, Supplier Part Number 1=490-9986-1-ND, Tolerance=20%, Voltage Rating=16V
C268 C270 C272 C275 C280 C282 C284 C287 C292 C294 C296 C299 C629: library part Capacitor, "CAP CER 0.1UF 16V X5R 0201", Case Code (Imperial)=0201, Case Code (Metric)=0603, Dielectric=X5R, Manufacturer=Murata, Manufacturer Part Number=GRM033R61C104ME84D, Max Operating Temperature=85°C, Min Operating Temperature=-55°C, Package Quantity=15000, Supplier Part Number 1=490-9986-1-ND, Tolerance=20%, Voltage Rating=16V
C273 C276 C277 C278 C285 C288 C289 C290 C297 C300 C301 C302: library part Capacitor, "CAP CER 10000PF 16V X7R 0201", Dielectric=X7R, Manufacturer=Murata, Manufacturer Part Number=GRM033R71C103KE14D, Supplier Part Number 1=490-14453-1-ND, Tolerance=10%, Voltage Rating (DC)=16V
C303_I2C_Bridge_GPIO C303_I2C_Bridge_PCIE C303_I2C_Bridge_SFP C406 C418 C447 C459 C517 C519 C521 C545 C546 C547 C566_5V_to_3V3_for_FTDI C623 C649 C651 C653 C654 C677 C715 C716 C717 C718: library part Capacitor, Case/Package=0402, Case Code (Metric)=1005, Dielectric=X5R, Insulation Resistance=10GR, Manufacturer=Yageo, Manufacturer Part Number=CC0402KRX5R6BB104, Max Operating Temperature=85°C, Min Operating Temperature=-55°C, Package Quantity=1, Supplier Part Number 1=311-1336-1-ND, Tolerance=10%, Voltage Rating=10V
C304 C305 C306 C307: library part Capacitor, "SMT Capacitor", Part Number=CL10A475KO8NNNC, Supplier Part Number 1=1276-1784-2-ND
C308 C354 C355 C606 C607 C610 C611 C613 C614 C615 C617 C618 C619 C620 C621 C622: library part Capacitor, "SMT Capacitor", Part Number=CL10A475KQ8NNNC, Supplier Part Number 1=1276-1045-1-ND
C309_U_Pomiar_pradu_napiecia_1 C309_U_Pomiar_pradu_napiecia_2 C309_U_Pomiar_pradu_napiecia_3 C309_U_Pomiar_pradu_napiecia_4 C309_U_Pomiar_pradu_napiecia_5 C309_U_Pomiar_pradu_napiecia_6 C309_U_Pomiar_pradu_napiecia_7 C309_U_Pomiar_pradu_napiecia_8 C309_U_Pomiar_pradu_napiecia_9 C309_U_Pomiar_pradu_napiecia_10 C309_U_Pomiar_pradu_napiecia_11 C310 C585 C711 C712: library part Capacitor, "CAP CER 0.1UF 50V X5R 0402", Case/Package=0402, Case Code (Metric)=1005, Dielectric=X5R, Dielectric Material=Ceramic, Manufacturer=Murata, Manufacturer Part Number=GRM155R61H104KE14D, Max Operating Temperature=85°C, Min Operating Temperature=-55°C, Package Quantity=10000, Supplier Part Number 1=490-10697-1-ND, Tolerance=10%, Voltage=50V
C311_I2C_Expander_00 C311_I2C_Expander_01 C311_I2C_Expander_02 C311_I2C_Expander_10 C311_I2C_Expander_11 C311_I2C_Expander_12 C311_I2C_Expander_16 C311_I2C_Expander_17 C311_I2C_Expander_18 C311_I2C_Expander_Main_Rst C311_I2C_Expander_PWR_CLK C311_I2C_Expander_PWR_Dist C311_I2C_Expander_SFP C544 C700 C720 C721 C722 C723: library part Capacitor, "MURATA - GRT155R61E105KE01D - SMD Multilayer Ceramic Capacitor, 1 µF, 25 V, 0402 [1005 Metric], ± 10%, X5R, GRT Series - SMD Multilayer Ceramic Capacitor, 1 µF, 25 V, 0402 [1005 Metric], ± 10%, X5R, GRT Series", Case/Package=0402, Case Code (Metric)=1005, Dielectric=X5R, Manufacturer=Murata, Manufacturer Part Number=GRT155R61E105KE01D, Max Operating Temperature=85°C, Min Operating Temperature=-55°C, Ratings=AEC-Q200, Supplier Part Number 1=490-12263-1-ND, Tolerance=10%, Voltage Rating=25V
C320: library part Capacitor, Case/Package=0402, Case Code (Metric)=1005, Dielectric=X7R, Dielectric Material=Ceramic, Manufacturer=KEMET, Manufacturer Part Number=C0402C103K8RACAUTO, Max Operating Temperature=125°C, Min Operating Temperature=-55°C, Package Quantity=1, Ratings=AEC-Q200, Supplier Part Number 1=399-6827-1-ND, Tolerance=10%, Voltage Rating=10V
C321: library part Capacitor, Case/Package=0603, Case Code (Metric)=1608, Manufacturer="Wurth Electronics", Manufacturer Part Number=885012006016, Max Operating Temperature=125°C, Min Operating Temperature=-55°C, Supplier Part Number 1=732-7759-1-ND, Tolerance=5%, Voltage Rating=10V
C322 C323: library part Capacitor, Case/Package=0402, Case Code (Metric)=1005, Dielectric=C0G, Dielectric Material=Ceramic, Manufacturer=KEMET, Manufacturer Part Number=C0402C270K5GACTU, Max Operating Temperature=125°C, Min Operating Temperature=-55°C, Package Quantity=1, Supplier Part Number 1=399-8960-1-ND, Tolerance=10%, Voltage Rating=50V
C324: library part Capacitor, Case/Package=0805, Case Code (Metric)=2012, Manufacturer=Samsung, Manufacturer Part Number=CL21A106KQCLRNC, Max Operating Temperature=85°C, Min Operating Temperature=-55°C, Package Quantity=1, Supplier Part Number 1=1276-2405-1-ND, Tolerance=10%, Voltage Rating=6.3V
C325 C330 C334 C335 C342 C343: library part Capacitor, Case Code (Imperial)=0402, Case Code (Metric)=1005, Dielectric=X7R, Dielectric Material=Ceramic, Insulation Resistance=10GR, Manufacturer=Murata, Manufacturer Part Number=GRM155R71C104KA88D, Max Operating Temperature=125°C, Min Operating Temperature=-55°C, Package Quantity=1, Supplier Part Number 1=490-3261-6-ND, Tolerance=10%, Voltage=16V
C326 C327 C328 C329: library part Capacitor, Case/Package=0402, Dielectric=X5R, Dielectric Material=Ceramic, Manufacturer=KEMET, Manufacturer Part Number=C0402C105K9PACTU, Max Operating Temperature=85°C, Min Operating Temperature=-55°C, Package Quantity=1, Supplier Part Number 1=399-4873-6-ND, Tolerance=10%, Voltage=6.3V
C331 C332 C395 C398 C408 C420 C436 C439 C449 C461 C522 C538 C559 C733 C734: library part Capacitor, Case/Package=0402, Case Code (Metric)=1005, Dielectric=X5R, Manufacturer=Yageo, Manufacturer Part Number=CC0402KRX5R6BB105, Max Operating Temperature=85°C, Min Operating Temperature=-55°C, Package Quantity=1, Supplier Part Number 1=311-1439-1-ND, Tolerance=10%, Voltage Rating=10V
C339: library part Capacitor, Case Code (Imperial)=0805, Case Code (Metric)=2012, Manufacturer=Samsung, Manufacturer Part Number=CL21A106KQCLRNC, Max Operating Temperature=85°C, Min Operating Temperature=-55°C, Package Quantity=1, Supplier Part Number 1=1276-2405-1-ND, Tolerance=10%, Voltage Rating=6.3V
C345 C349 C535 C536: library part Capacitor, Case Code (Imperial)=0402, Case Code (Metric)=1005, Dielectric=C0G, Manufacturer="Kyocera AVX", Manufacturer Part Number=04025A220JAT2A, Max Operating Temperature=125°C, Min Operating Temperature=-55°C, Package Quantity=1, Supplier Part Number 1=478-1074-1-ND, Temperature Coefficient=30ppm/°C, Tolerance=5%, Voltage=50V
C346 C350 C713: library part Capacitor, Case Code (Imperial)=0402, Case Code (Metric)=1005, Dielectric=X5R, Manufacturer=Multicomp, Manufacturer Part Number=MC0402X104K160CT, Max Operating Temperature=85°C, Min Operating Temperature=-55°C, Supplier Part Number 1=2310529, Tolerance=10%, Voltage Rating=16V
C347 C348 C352 C353 C391 C392 C396 C397 C432 C433 C437 C438: library part Capacitor, Case/Package=1206, Case Code (Metric)=3216, Dielectric=X7R, Manufacturer 1=Murata, Manufacturer Part Number 1=GRM31CR71E106MA12L, Max Operating Temperature=125°C, Min Operating Temperature=-55°C, Package Quantity=1, Supplier Part Number 1=490-6519-1-ND, Tolerance=20%, Voltage=25V
C351 C356 C361 C379 C680: library part Capacitor, Case Code (Imperial)=0402, Case Code (Metric)=1005, Dielectric=X5R, Manufacturer=Yageo, Manufacturer Part Number=CC0402KRX5R6BB105, Max Operating Temperature=85°C, Min Operating Temperature=-55°C, Package Quantity=1, Supplier Part Number 1=311-1439-1-ND, Tolerance=10%, Voltage Rating=10V
C357 C399 C440: library part Capacitor, Case/Package=0402, Case Code (Metric)=1005, Dielectric=X5R, Dielectric Material=Ceramic, Manufacturer 1=KEMET, Manufacturer Part Number 1=C0402C104M8PACTU, Max Operating Temperature=85°C, Min Operating Temperature=-55°C, Package Quantity=1, Supplier Part Number 1=399-7764-1-ND, Tolerance=20%, Voltage=10V
C358: library part Capacitor, "Cap Ceramic 1uF 10V X5R 10% SMD 0603 85C Paper T/R", Case Code (Imperial)=0603, Case Code (Metric)=1608, Dielectric=X5R, Manufacturer=Samsung, Manufacturer Part Number=CL10A105KP8NNNC, Max Operating Temperature=85°C, Min Operating Temperature=-55°C, Package Quantity=1, Supplier Part Number 1=1276-1182-1-ND, Tolerance=10%, Voltage=10V
C360 C378: library part Capacitor, Case Code (Imperial)=0402, Case Code (Metric)=1005, Dielectric=X5R, Manufacturer=Samsung, Manufacturer Part Number=CL05A474KP5NNNC, Max Operating Temperature=85°C, Min Operating Temperature=-55°C, Supplier Part Number 1=1276-1173-1-ND, Tolerance=10%, Voltage Rating=10V
C362 C380 C563_U_5V_to_3V31 C563_U_5V_to_3V32 C563_U_5V_to_3V33 C564_U_5V_to_3V31 C564_U_5V_to_3V32 C564_U_5V_to_3V33 C565_U_5V_to_3V31 C565_U_5V_to_3V32 C565_U_5V_to_3V33: library part Capacitor, Case Code (Imperial)=0603, Case Code (Metric)=1608, Dielectric=X5R, Manufacturer=Samsung, Manufacturer Part Number=CL10A475KP8NNNC, Max Operating Temperature=85°C, Min Operating Temperature=-55°C, Package Quantity=1, Supplier Part Number 1=1276-1044-1-ND, Tolerance=10%, Voltage Rating=10V
C363 C365 C367 C369 C381 C383 C385 C387 C572 C576 C598 C631: library part Capacitor, Case Code (Imperial)=0603, Case Code (Metric)=1608, Dielectric=X5R, Manufacturer=Murata, Manufacturer Part Number=GRM188R61A106KE69D, Max Operating Temperature=85°C, Min Operating Temperature=-55°C, Supplier Part Number 1=490-10474-1-ND, Tolerance=10%, Voltage=10V
C364 C366 C368 C370 C382 C384 C386 C388: library part Capacitor, Case Code (Imperial)=0603, Case Code (Metric)=1608, Dielectric=X5R, Manufacturer=Murata, Manufacturer Part Number=GRM188R61A226ME15D, Max Operating Temperature=85°C, Min Operating Temperature=-55°C, Package Quantity=4000, Supplier Part Number 1=490-10476-1-ND, Tolerance=20%, Voltage Rating=10V
C371 C372 C373 C374 C375 C376: library part Capacitor, "Cap Ceramic 10uF 25V X5R 10% SMD 1206 85C Embossed T/R", Case Code (Imperial)=1206, Case Code (Metric)=3216, Dielectric=X5R, Manufacturer=Samsung, Manufacturer Part Number=CL31A106KAHNNNE, Max Operating Temperature=85°C, Min Operating Temperature=-55°C, Supplier Part Number 1=1276-1075-1-ND, Tolerance=10%, Voltage=25V
C389 C393 C430 C434: library part Capacitor, Case/Package=0402, Case Code (Metric)=1005, Dielectric=C0G, Manufacturer="Kyocera AVX", Manufacturer Part Number=04025A220JAT2A, Max Operating Temperature=125°C, Min Operating Temperature=-55°C, Package Quantity=1, Supplier Part Number 1=478-1074-1-ND, Temperature Coefficient=30ppm/°C, Tolerance=5%, Voltage=50V
C390 C394 C431 C435 C658 C660 C662 C665 C666 C667 C668 C669 C670 C671 C673 C783 C785 C787 C789 C791 C792: library part Capacitor, Case/Package=0402, Case Code (Metric)=1005, Dielectric=X5R, Manufacturer=Multicomp, Manufacturer Part Number=MC0402X104K160CT, Max Operating Temperature=85°C, Min Operating Temperature=-55°C, Supplier Part Number 1=2310529, Tolerance=10%, Voltage Rating=16V
C400 C401 C402 C403 C404 C405 C441 C442 C443 C444 C445 C446: library part Capacitor, "Cap Ceramic 10uF 25V X5R 10% SMD 1206 85C Embossed T/R", Case/Package=1206, Case Code (Metric)=3216, Dielectric=X5R, Manufacturer=Samsung, Manufacturer Part Number=CL31A106KAHNNNE, Max Operating Temperature=85°C, Min Operating Temperature=-55°C, Supplier Part Number 1=1276-1075-1-ND, Tolerance=10%, Voltage=25V
C407 C419 C448 C460: library part Capacitor, Case/Package=0402, Case Code (Metric)=1005, Dielectric=X5R, Manufacturer=Samsung, Manufacturer Part Number=CL05A474KP5NNNC, Max Operating Temperature=85°C, Min Operating Temperature=-55°C, Supplier Part Number 1=1276-1173-1-ND, Tolerance=10%, Voltage Rating=10V
C409 C421 C450 C462 C515 C516 C523 C524 C539 C560 C563_5V_to_3V3_for_FTDI C564_5V_to_3V3_for_FTDI C565_5V_to_3V3_for_FTDI C659 C661: library part Capacitor, Case/Package=0603, Case Code (Metric)=1608, Dielectric=X5R, Manufacturer=Samsung, Manufacturer Part Number=CL10A475KP8NNNC, Max Operating Temperature=85°C, Min Operating Temperature=-55°C, Package Quantity=1, Supplier Part Number 1=1276-1044-1-ND, Tolerance=10%, Voltage Rating=10V
C410 C412 C414 C416 C422 C424 C426 C428 C451 C453 C455 C457 C463 C465 C467 C469 C705 C709: library part Capacitor, Case/Package=0603, Case Code (Metric)=1608, Dielectric=X5R, Manufacturer=Murata, Manufacturer Part Number=GRM188R61A106KE69D, Max Operating Temperature=85°C, Min Operating Temperature=-55°C, Supplier Part Number 1=490-10474-1-ND, Tolerance=10%, Voltage=10V
C411 C413 C415 C417 C423 C425 C427 C429 C452 C454 C456 C458 C464 C466 C468 C470: library part Capacitor, Case/Package=0603, Case Code (Metric)=1608, Dielectric=X5R, Manufacturer=Murata, Manufacturer Part Number=GRM188R61A226ME15D, Max Operating Temperature=85°C, Min Operating Temperature=-55°C, Package Quantity=4000, Supplier Part Number 1=490-10476-1-ND, Tolerance=20%, Voltage Rating=10V
C471 C472 C473 C474: library part Capacitor, Case/Package=0402, Case Code (Metric)=1005, Dielectric=X5R, Manufacturer 1=Yageo, Manufacturer Part Number 1=CC0402KRX5R8BB104, Max Operating Temperature=85°C, Min Operating Temperature=-55°C, Supplier Part Number 1=311-1697-1-ND, Tolerance=10%, Voltage Rating=25V
C475 C476 C672: "CAP CER 1210 4.7NF 2000V X7R 10%", Capacitance="#Circular Reference?", Case/Package=1210, Case Code (Metric)=3225, Manufacturer=KEMET, Manufacturer Part Number=C1210X472KGRACAUTO, Max Operating Temperature=125°C, Min Operating Temperature=-55°C, Ratings=AEC-Q200, Supplier Part Number 1=399-16765-1-ND, Tolerance=10%, Voltage Rating=2kV
C480 C481: library part Capacitor, "Multilayer Ceramic Capacitors MLCC - SMD/SMT 16V 27pF C0G 0402 10% Tol", Case/Package=0402, Case Code (Metric)=1005, Dielectric=C0G, Manufacturer="Kyocera AVX", Manufacturer Part Number=0402YA270KAT2A, Max Operating Temperature=125°C, Min Operating Temperature=-55°C, Package Quantity=10000, Supplier Part Number 1=66M2135, Tolerance=10%, Voltage Rating=16V
C485 C486 C491 C492 C493 C499 C500 C505 C506 C507 C508: library part Capacitor, Case/Package=0402, Dielectric=X5R, Dielectric Material=Ceramic, Manufacturer 1=KEMET, Manufacturer Part Number 1=C0402C105K9PACTU, Max Operating Temperature=85°C, Min Operating Temperature=-55°C, Package Quantity=1, Supplier Part Number 1=399-4873-6-ND, Tolerance=10%, Voltage=6.3V
C487 C488 C494 C495 C496 C501 C502 C509 C510 C511 C512 C561 C562: library part Capacitor, Case/Package=0402, Case Code (Metric)=1005, Dielectric=X5R, Dielectric Material=Ceramic, Manufacturer 1=KEMET, Manufacturer Part Number 1=C0402C104M9PACTU, Max Operating Temperature=85°C, Min Operating Temperature=-55°C, Package Quantity=1, Supplier Part Number 1=399-8944-1-ND, Tolerance=20%, Voltage Rating=6.3V
C489 C497 C503 C513: library part Capacitor, Case/Package=0402, Case Code (Metric)=1005, Manufacturer 1=Murata, Manufacturer Part Number 1=GRJ155R60J106ME11D, Max Operating Temperature=85°C, Min Operating Temperature=-55°C, Supplier Part Number 1=490-13211-1-ND, Tolerance=20%, Voltage Rating=6.3V
C490 C498 C504 C514: library part Capacitor, Case/Package=0402, Case Code (Metric)=1005, Dielectric=X5R, Dielectric Material=Ceramic, Manufacturer 1=KEMET, Manufacturer Part Number 1=C0402C103K4PACTU, Max Operating Temperature=85°C, Min Operating Temperature=-55°C, Supplier Part Number 1=399-11930-1-ND, Tolerance=10%, Voltage Rating=16V
C518 C520 C567_5V_to_3V3_for_FTDI C586 C587: library part Capacitor, "CAP CER 2.2UF 6.3V X5R 0402", Case/Package=0402, Case Code (Metric)=1005, Dielectric=X5R, Manufacturer="Taiyo Yuden", Manufacturer Part Number=JMK105BJ225KV-F, Max Operating Temperature=85°C, Min Operating Temperature=-55°C, Package Quantity=10000, Supplier Part Number 1=587-5867-1-ND, Tolerance=10%, Voltage Rating=6.3V
C525 C526 C527 C528 C529 C530: library part Capacitor, Case Code (Imperial)=0402, Case Code (Metric)=1005, Dielectric=X7R, Dielectric Material=Ceramic, Manufacturer=KEMET, Manufacturer Part Number=C0402C103K8RACAUTO, Max Operating Temperature=125°C, Min Operating Temperature=-55°C, Package Quantity=1, Ratings=AEC-Q200, Supplier Part Number 1=399-6827-1-ND, Tolerance=10%, Voltage Rating=10V
C531 C532 C533 C534 C588 C589 C592: library part Capacitor, "Cap Ceramic 0.1uF 25V X7R 20% SMD 0402 125C Paper T/R", Case Code (Imperial)=0402, Case Code (Metric)=1005, Dielectric=X7R, Manufacturer=Murata, Manufacturer Part Number=GRM155R71E104ME14D, Max Operating Temperature=125°C, Min Operating Temperature=-55°C, Package Quantity=10000, Supplier Part Number 1=490-13341-1-ND, Tolerance=20%, Voltage Rating=25V
C537: "WR-COM USB 3.0 Horizontal Type A", Manufacturer="Würth Elektronik eiSos GmbH", partNo=692121130100
C548: library part Capacitor, Case/Package=0402, Case Code (Metric)=1005, Dielectric=C0G, Manufacturer=Yageo, Manufacturer Part Number=CC0402JRNPO9BN110, Max Operating Temperature=125°C, Min Operating Temperature=-55°C, Package Quantity=1, Supplier Part Number 1=311-1015-1-ND, Tolerance=5%, Voltage Rating=50V
C549: library part Capacitor, Case/Package=0402, Case Code (Metric)=1005, Dielectric=X7R, Dielectric Material=Ceramic, Insulation Resistance=100GR, Manufacturer=Yageo, Manufacturer Part Number=CC0402KRX7R9BB221, Max Operating Temperature=125°C, Min Operating Temperature=-55°C, Package Quantity=1, Supplier Part Number 1=311-1035-1-ND, Tolerance=10%, Voltage Rating=50V
C551 C553 C555: library part Capacitor, "CAP CER 10UF 6.3V X5R 0402", Case/Package=0402, Case Code (Metric)=1005, Manufacturer=Murata, Manufacturer Part Number=GRJ155R60J106ME11D, Max Operating Temperature=85°C, Min Operating Temperature=-55°C, Supplier Part Number 1=490-13211-1-ND, Tolerance=20%, Voltage Rating=6.3V
C558: "WR-COM_USB_Micro Type B_Vertical_THT", Manufacturer="Würth Elektronik eiSos GmbH", partNo=614105150721
C567_U_5V_to_3V31 C567_U_5V_to_3V32 C567_U_5V_to_3V33: library part Capacitor, "CAP CER 2.2UF 6.3V X5R 0402", Case Code (Imperial)=0402, Case Code (Metric)=1005, Dielectric=X5R, Manufacturer="Taiyo Yuden", Manufacturer Part Number=JMK105BJ225KV-F, Max Operating Temperature=85°C, Min Operating Temperature=-55°C, Package Quantity=10000, Supplier Part Number 1=587-5867-1-ND, Tolerance=10%, Voltage Rating=6.3V
C571 C719: library part Capacitor, "CAP CER 1000PF 25V X5R 0201", Case/Package=0201, Dielectric=X5R, Manufacturer=Murata, Manufacturer Part Number=GRM033R61E102KA01D, Max Operating Temperature=85°C, Min Operating Temperature=-55°C, Supplier Part Number 1=490-14452-1-ND, Tolerance=10%, Voltage Rating (DC)=25V
C595 C596 C695 C696 C697 C698 C699: library part Capacitor, Dielectric=X5R, Manufacturer=Murata, Manufacturer Part Number=GRM21BR61H106KE43L, Supplier Part Number 1=490-18663-1-ND, Tolerance=10%, Voltage Rating (DC)=50V
C597: library part Capacitor, "MURATA - GRT155R61E105KE01D - SMD Multilayer Ceramic Capacitor, 1 µF, 25 V, 0402 [1005 Metric], ± 10%, X5R, GRT Series - SMD Multilayer Ceramic Capacitor, 1 µF, 25 V, 0402 [1005 Metric], ± 10%, X5R, GRT Series", Case Code (Imperial)=0402, Case Code (Metric)=1005, Dielectric=X5R, Manufacturer=Murata, Manufacturer Part Number=GRT155R61E105KE01D, Max Operating Temperature=85°C, Min Operating Temperature=-55°C, Ratings=AEC-Q200, Supplier Part Number 1=490-12263-1-ND, Tolerance=10%, Voltage Rating=25V
C603 C612: library part Capacitor, Case/Package=0201, Case Code (Metric)=0603, Dielectric=C0G, Manufacturer=Murata, Manufacturer Part Number=GRM0335C1H430GA01D, Max Operating Temperature=125°C, Min Operating Temperature=-55°C, Package Quantity=15000, Supplier Part Number 1=490-14799-1-ND, Tolerance=2%, Voltage Rating=50V
C604: library part Capacitor, "SMT Capacitor", Part Number=CL05A105MQ5NNNC, Supplier Part Number 1=1276-1235-6-ND
C605 C616: library part Capacitor, Case/Package=0201, Case Code (Metric)=0603, Dielectric=C0G, Manufacturer=Murata, Manufacturer Part Number=GRM0335C1E101JA01D, Max Operating Temperature=125°C, Min Operating Temperature=-55°C, Package Quantity=15000, Supplier Part Number 1=490-3160-1-ND, Tolerance=5%, Voltage=25V
C609: "Supercapacitors / Ultracapacitors 0.22F 5.5volts SMD Super Capacitor", Capacitance=220mF, Case/Package=Radial, ESR (Equivalent Series Resistance)=25R, Leakage Current=330uA, Manufacturer=KEMET, Max Operating Temperature=70°C, Min Operating Temperature=-25°C, Package Quantity=500, Supplier Part Number 1=18X4838, Tolerance=80%, Voltage=5.5V
C624 C625 C626: library part Capacitor, Case/Package=0201, Case Code (Metric)=0603, Dielectric=X5R, Manufacturer=Yageo, Manufacturer Part Number=CC0201KRX5R7BB103, Max Operating Temperature=85°C, Min Operating Temperature=-55°C, Supplier Part Number 1=311-1596-1-ND, Tolerance=10%, Voltage Rating=16V
C627: library part Capacitor, "CAP CER 0.1UF 16V X5R 0201", Case/Package=0201, Case Code (Metric)=0603, Dielectric=X5R, Manufacturer=Murata, Manufacturer Part Number=GRM033R61C104ME84D, Max Operating Temperature=85°C, Min Operating Temperature=-55°C, Package Quantity=15000, Supplier Part Number 1=490-9986-1-ND, Tolerance=20%, Voltage Rating=16V
C628: library part Capacitor, "Multilayer Ceramic Capacitors MLCC - SMD/SMT 470nF 6.3V X5R 10%", Case/Package=0402, Case Code (Metric)=1005, Dielectric=X5R, Manufacturer=Yageo, Manufacturer Part Number=CC0402KRX5R5BB474, Max Operating Temperature=85°C, Min Operating Temperature=-55°C, Supplier Part Number 1=311-1684-1-ND, Tolerance=10%, Voltage Rating=6.3V
C630 C632: library part Capacitor, "Multilayer Ceramic Capacitors MLCC - SMD/SMT 470nF 6.3V X5R 10%", Case Code (Imperial)=0402, Case Code (Metric)=1005, Dielectric=X5R, Manufacturer=Yageo, Manufacturer Part Number=CC0402KRX5R5BB474, Max Operating Temperature=85°C, Min Operating Temperature=-55°C, Supplier Part Number 1=311-1684-1-ND, Tolerance=10%, Voltage Rating=6.3V
C633 C636: library part Capacitor, Case/Package=0402, Case Code (Metric)=1005, Dielectric=U2J, Manufacturer=Murata, Manufacturer Part Number=GRM1557U1A302JA01D, Max Operating Temperature=125°C, Min Operating Temperature=-55°C, Package Quantity=10000, Supplier Part Number 1=490-8243-1-ND, Tolerance=5%, Voltage Rating=10V
C634: library part Capacitor, Case/Package=0402, Case Code (Metric)=1005, Dielectric=X7R, Dielectric Material=Ceramic, Insulation Resistance=100GR, Manufacturer=Yageo, Manufacturer Part Number=CC0402KRX7R9BB331, Max Operating Temperature=125°C, Min Operating Temperature=-55°C, Package Quantity=1, Supplier Part Number 1=311-1027-1-ND, Tolerance=10%, Voltage Rating=50V
C635: library part Capacitor, Case/Package=0402, Case Code (Metric)=1005, Dielectric=X7R, Manufacturer=Yageo, Manufacturer Part Number=CC0402KRX7R9BB682, Max Operating Temperature=125°C, Min Operating Temperature=-55°C, Supplier Part Number 1=311-1726-1-ND, Tolerance=10%, Voltage=50V
C637 C638 C645 C646: library part Capacitor, "CAP CER 1200PF 50V X7R 0402", Case Code (Imperial)=0402, Case Code (Metric)=1005, Dielectric=X7R, Manufacturer=Yageo, Manufacturer Part Number=CC0402KRX7R9BB122, Max Operating Temperature=125°C, Min Operating Temperature=-55°C, Package Quantity=1, Supplier Part Number 1=311-1031-1-ND, Tolerance=10%, Voltage Rating=50V
C639 C640 C647 C648: library part Capacitor, Case/Package=0402, Case Code (Metric)=1005, Dielectric=X7R, Insulation Resistance=10GR, Manufacturer=Yageo, Manufacturer Part Number=CC0402KRX7R8BB473, Max Operating Temperature=125°C, Min Operating Temperature=-55°C, Supplier Part Number 1=311-1717-1-ND, Tolerance=10%, Voltage Rating=25V
C641: library part Capacitor, Case/Package=0402, Dielectric=X7R, Dielectric Material=Ceramic, Manufacturer=KEMET, Manufacturer Part Number=C0402C471K5RACTU, Max Operating Temperature=125°C, Min Operating Temperature=-55°C, Supplier Part Number 1=399-1025-1-ND, Tolerance=10%, Voltage=50V
C642: library part Capacitor, Case/Package=0402, Case Code (Metric)=1005, Dielectric=C0G, Manufacturer=Yageo, Manufacturer Part Number=CC0402JRNPO9BN560, Max Operating Temperature=125°C, Min Operating Temperature=-55°C, Package Quantity=1, Supplier Part Number 1=311-1022-1-ND, Tolerance=5%, Voltage Rating=50V
C643: library part Capacitor, Case/Package=0402, Case Code (Metric)=1005, Dielectric=X7R, Manufacturer=Yageo, Manufacturer Part Number=CC0402KRX7R7BB822, Max Operating Temperature=125°C, Min Operating Temperature=-55°C, Package Quantity=1, Supplier Part Number 1=311-1041-1-ND, Tolerance=10%, Voltage Rating=16V
C644: library part Capacitor, Case/Package=0402, Case Code (Metric)=1005, Dielectric=X7R, Manufacturer=Yageo, Manufacturer Part Number=CC0402KRX7R9BB821, Max Operating Temperature=125°C, Min Operating Temperature=-55°C, Package Quantity=10000, Supplier Part Number 1=311-1727-1-ND, Tolerance=10%, Voltage=50V
C650: library part Capacitor, Case/Package=0402, Case Code (Metric)=1005, Dielectric=C0G, Manufacturer=Yageo, Manufacturer Part Number=CC0402JRNPO9BN181, Max Operating Temperature=125°C, Min Operating Temperature=-55°C, Supplier Part Number 1=311-1663-1-ND, Tolerance=5%, Voltage Rating=50V
C652: library part Capacitor, Case/Package=0402, Case Code (Metric)=1005, Dielectric=X7R, Manufacturer=Yageo, Manufacturer Part Number=CC0402KRX7R7BB222, Max Operating Temperature=125°C, Min Operating Temperature=-55°C, Package Quantity=10000, Supplier Part Number 1=311-1707-1-ND, Tolerance=10%, Voltage Rating=16V
C655 C656 C657: library part Capacitor, Case/Package=0402, Case Code (Metric)=1005, Dielectric=X7R, Manufacturer=Yageo, Manufacturer Part Number=CC0402KRX7R8BB562, Max Operating Temperature=125°C, Min Operating Temperature=-55°C, Supplier Part Number 1=311-1718-1-ND, Tolerance=10%, Voltage Rating=25V
C663 C664: library part Capacitor, "KEMET - C0402C270J5GACTU - Multilayer Ceramic Capacitor, C Series, 27 pF, -  5%, C0G / NP0, 50 V, 0402 [1005 Metric] RoHS Compliant: Yes", Case/Package=0402, Case Code (Metric)=1005, Dielectric=C0G, Dielectric Material=Ceramic, Manufacturer=KEMET, Manufacturer Part Number=C0402C270J5GACTU, Max Operating Temperature=125°C, Min Operating Temperature=-55°C, Package Quantity=1, Supplier Part Number 1=399-1016-1-ND, Temperature Coefficient=30ppm/°C, Tolerance=5%, Voltage=50V
C674 C675 C676 C782 C784 C786 C788: library part Capacitor, "0402 10 V 4.7 uF ±20% Tolerance X5R Multilayer Ceramic Chip Capacitor", Case/Package=0402, Case Code (Metric)=1005, Manufacturer=Murata, Manufacturer Part Number=GRM155R61A475MEAAD, Max Operating Temperature=85°C, Min Operating Temperature=-55°C, Supplier Part Number 1=490-14306-1-ND, Tolerance=20%, Voltage Rating=10V
C678 C679: library part Capacitor, "Cap Ceramic 100uF 6.3V X6T 20% Pad SMD 1206 105C T/R", Case Code (Imperial)=1206, Case Code (Metric)=3216, Dielectric=X6T, Dielectric Material=Ceramic, Manufacturer=Murata, Manufacturer Part Number=GRM31CD80J107ME39L, Max Operating Temperature=105°C, Min Operating Temperature=-55°C, Package Quantity=2000, Supplier Part Number 1=490-10525-1-ND, Tolerance=20%, Voltage=6.3V
C693: library part Capacitor, "CAP CER 0.47UF 25V X5R 0402", Case/Package=0402, Case Code (Metric)=1005, Manufacturer=Murata, Manufacturer Part Number=GRT155R61E474KE01D, Max Operating Temperature=85°C, Min Operating Temperature=-55°C, Ratings=AEC-Q200, Supplier Part Number 1=490-12269-1-ND, Tolerance=10%, Voltage Rating=25V
C694: library part Capacitor, "0603 4.7 uF 35 V ±10% Tolerance X5R Multilayer Ceramic Chip Capacitor", Case/Package=0603, Case Code (Metric)=1608, Dielectric=X5R, Manufacturer=Murata, Manufacturer Part Number=GRM188R6YA475KE15D, Max Operating Temperature=85°C, Min Operating Temperature=-55°C, Package Quantity=4000, Supplier Part Number 1=490-7205-6-ND, Tolerance=10%, Voltage=35V
C701: library part Capacitor, "CAP, MLCC, X7R, 0.012UF, 16V, 0402; Product Range:C Series; Capacitance:0.012 F; Capacitance Tolerance: 10%; Dielectric Characteristic:X7R; Voltage Rating:16V; Ceramic Capacitor Case:0402 [1005 Metric]; Operating Temperature ;RoHS Compliant: Yes", Case/Package=0402, Case Code (Metric)=1005, Dielectric=X7R, Dielectric Material=Ceramic, Manufacturer=KEMET, Manufacturer Part Number=C0402C123K4RACTU, Max Operating Temperature=125°C, Min Operating Temperature=-55°C, Package Quantity=1, Supplier Part Number 1=399-4875-1-ND, Tolerance=10%, Voltage=16V
C702: library part Capacitor, "Ceramic Capacitor 36PF 50V, C0G, 5%, 0402, Full Reel", Case/Package=0402, Case Code (Metric)=1005, Dielectric=C0G, Manufacturer="Kyocera AVX", Manufacturer Part Number=04025A360JAT2A, Max Operating Temperature=125°C, Min Operating Temperature=-55°C, Package Quantity=10000, Supplier Part Number 1=478-10099-1-ND, Tolerance=5%, Voltage Rating=50V
C703: library part Capacitor, "Cap Ceramic 0.015uF 25V X7R 10% SMD 0402 125C Paper T/R", Case/Package=0402, Case Code (Metric)=1005, Dielectric=X7R, Manufacturer=Yageo, Manufacturer Part Number=CC0402KRX7R8BB153, Max Operating Temperature=125°C, Min Operating Temperature=-55°C, Supplier Part Number 1=311-1713-1-ND, Tolerance=10%, Voltage Rating=25V
C704: library part Capacitor, "Cap Ceramic 1uF 10V X5R 10% SMD 0603 85C Paper T/R", Case/Package=0603, Case Code (Metric)=1608, Dielectric=X5R, Manufacturer=Samsung, Manufacturer Part Number=CL10A105KP8NNNC, Max Operating Temperature=85°C, Min Operating Temperature=-55°C, Package Quantity=1, Supplier Part Number 1=1276-1182-1-ND, Tolerance=10%, Voltage=10V
C706 C710: library part Capacitor, "Cap Ceramic 0.01uF 16V X5R 10% SMD 0201 85C Paper T/R", Case/Package=0201, Case Code (Metric)=0603, Dielectric=X5R, Manufacturer=Yageo, Manufacturer Part Number=CC0201KRX5R7BB103, Max Operating Temperature=85°C, Min Operating Temperature=-55°C, Supplier Part Number 1=311-1596-1-ND, Tolerance=10%, Voltage Rating=16V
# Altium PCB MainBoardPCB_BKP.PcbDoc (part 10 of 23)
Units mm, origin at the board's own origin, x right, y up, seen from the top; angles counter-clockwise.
Board outline 258.95 x 308.86 mm, 16 copper layers (L1, L2 (GND), L3 (Sign), L4 (GND), L5 (Sign), L6 (PWR/GND), L7(PWR/GND), L8 (Plane_GND), L9 (PWR/GND), L10 (PWR/GND), L11 (PWR/GND), L12 (Sign), L13 (GND), L14 (Sign), L15 (GND), L16), stack 2.502 mm thick; 2361 components, 1770 nets, 8410 pads, 3259 vias.
Unrouted connection lines stored in the file: 4700.

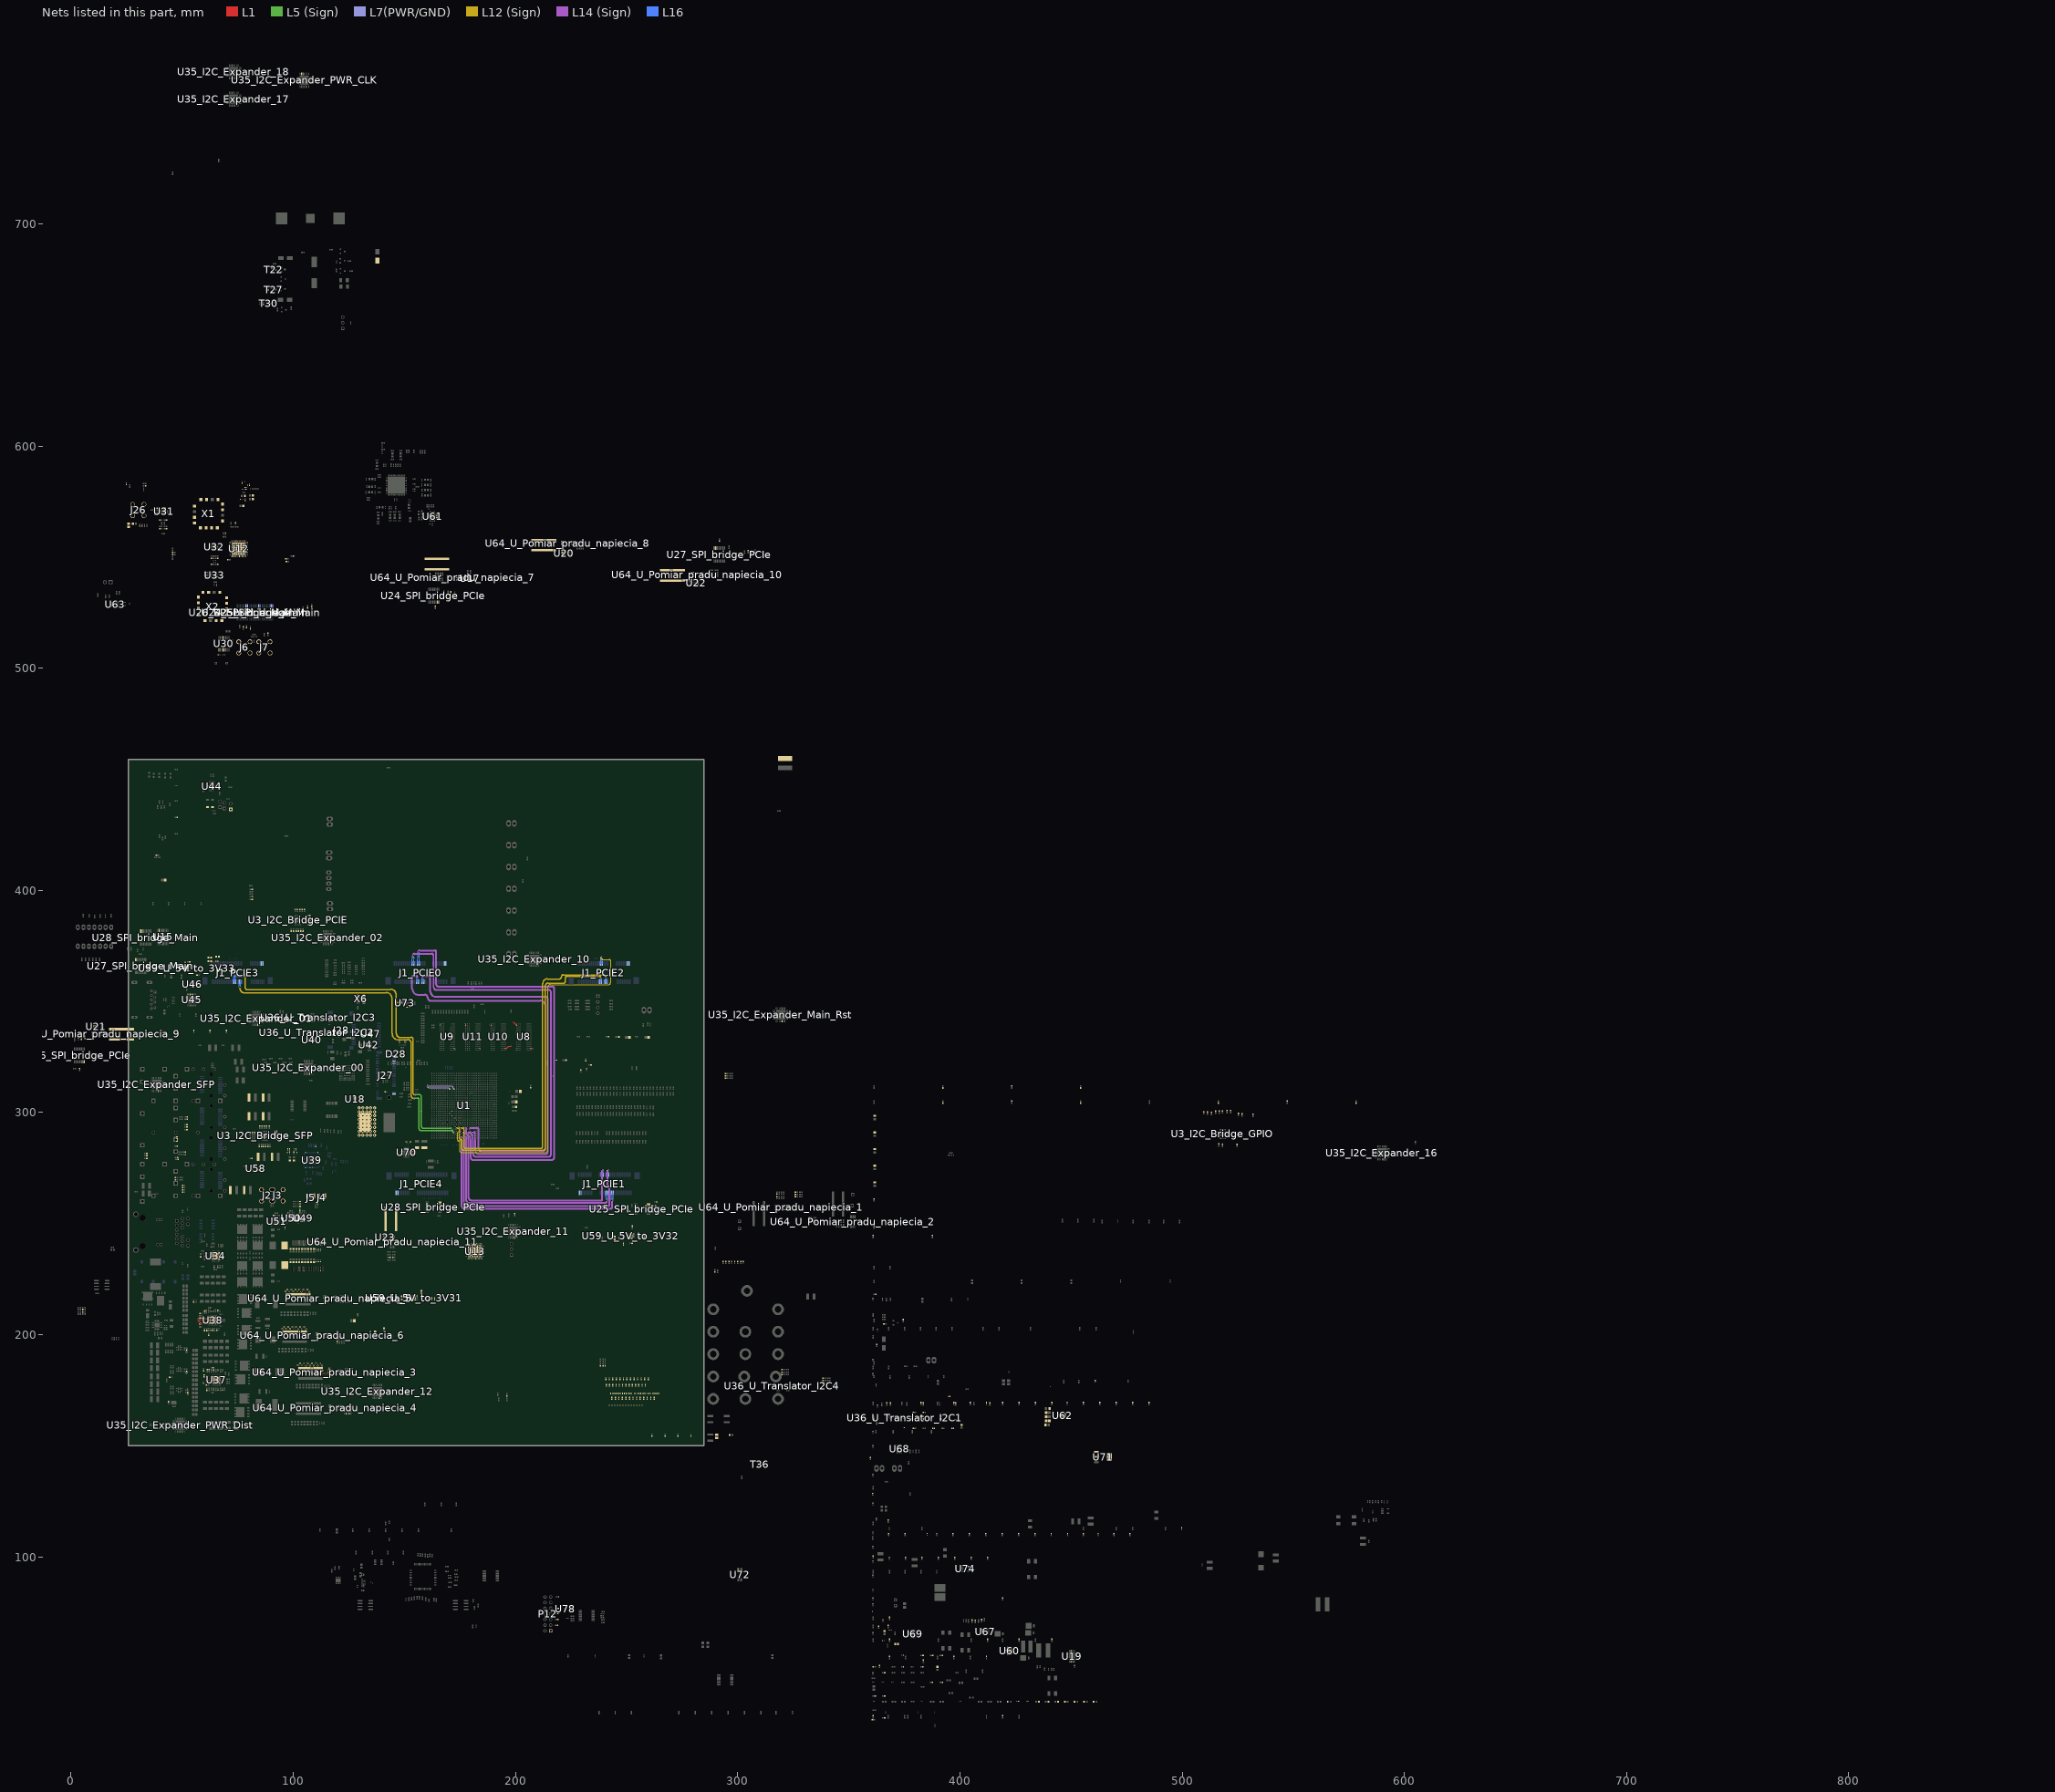
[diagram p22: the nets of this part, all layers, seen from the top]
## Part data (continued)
X3: library part MP024S, "CRYSTAL 2.4576MHZ 32PF T/H", ESR (Equivalent Series Resistance)=300R, Frequency Stability=50ppm, Frequency Tolerance=30ppm, Load Capacitance=32pF, Manufacturer=CTS, Max Operating Temperature=70°C, Min Operating Temperature=-20°C, Package Quantity=100, Supplier Part Number 1=CTX069-ND
X4: "CRYSTAL 25.0000MHZ 18PF SMD", Case/Package=SMD/SMT, ESR (Equivalent Series Resistance)=50R, Frequency=25MHz, Frequency Stability=30ppm, Frequency Tolerance=50ppm, Load Capacitance=18pF, Manufacturer 1=Epson, Max Operating Temperature=70°C, Min Operating Temperature=-20°C, Package Quantity=250, Supplier Part Number 1=SER3691CT-ND
X5: library part FC-13532.7680KA-A5, "CRYSTAL 32.7680 KHZ 12.5PF SMD", Case/Package=SMD/SMT, ESR (Equivalent Series Resistance)=70kR, Frequency Tolerance=20ppm, Load Capacitance=12.5pF, Manufacturer=Epson, Max Operating Temperature=85°C, Min Operating Temperature=-40°C, Supplier Part Number 1=SER4103CT-ND
X6: "SMD Crystal Oscillator 50MHz 3.3V 4-Pin SMD Tray", Case/Package=SMD/SMT, Frequency=50MHz, Frequency Stability=20ppm, Manufacturer="Silicon Labs", Operating Supply Voltage=3.3V, Package Quantity=1, Supplier Part Number 1=336-5245-ND
X7: "CRYSTAL 24.00 MHZ 9.0PF SMD", Case/Package=SMD/SMT, ESR (Equivalent Series Resistance)=40R, Frequency=24MHz, Frequency Stability=15ppm, Frequency Tolerance=10ppm, Load Capacitance=9pF, Manufacturer 1=Epson, Max Operating Temperature=85°C, Min Operating Temperature=-40°C, Supplier Part Number 1=SER4180DKR-ND
X8: Manufacturer 1="ECS International", Supplier Part Number 1=XC2904CT-ND
X9: "OSC MEMS 48.0000MHZ LVCMOS SMD", Case/Package=SMD/SMT, Frequency=48MHz, Frequency Stability=25ppm, Manufacturer=SiTime, Max Operating Temperature=85°C, Max Supply Current=4.5mA, Min Operating Temperature=-40°C, Supplier Part Number 1=1473-30890-1-ND

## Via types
v1: diameter 0.5, hole 0.2, L1 to L16, tented both sides, 1212 vias
v2: diameter 0.5, hole 0.2, L1 to L16, 476 vias
v3: diameter 0.5/0.35/0.35/0.35/0.35/0.35/0.35/0.35/0.35/0.35/0.35/0.35/0.35/0.35/0.35/0.5 (per signal layer), hole 0.15, L1 to L16, tented both sides, 463 vias
v4: diameter 0.35/0/0.35 (per signal layer), hole 0.127, L1 to L3 (Sign), tented both sides, 282 vias
v5: diameter 0.5/0.35/0.35/0.35/0.35/0.35/0.35/0.35/0.35/0.35/0.35/0.35/0.35/0.35/0.35/0.5 (per signal layer), hole 0.2, L1 to L16, tented both sides, 222 vias
v6: diameter 0.8, hole 0.4, L1 to L16, tented both sides, 168 vias
v7: diameter 2.54, hole 1.02, L1 to L16, 113 vias
v8: diameter 1.4, hole 0.5, L1 to L16, tented both sides, 80 vias
v9: diameter 0.5/0/0.5 (per signal layer), hole 0.2, L14 (Sign) to L16, tented both sides, 52 vias
v10: diameter 0.35, hole 0.127, L1 to L2 (GND), tented both sides, 36 vias
v11: diameter 0.35, hole 0.127, L1 to L16, tented both sides, 16 vias
v12: diameter 0.4, hole 0.2, L1 to L16, 16 vias
v13: diameter 0.25, hole 0.2, L1 to L16, 16 vias
v14: diameter 0.3, hole 0.2, L1 to L16, 15 vias
v15: diameter 0.35/0/0.35 (per signal layer), hole 0.127, L1 to L3 (Sign), 12 vias
v16: diameter 0.45, hole 0.15, L1 to L16, 12 vias
v17: diameter 0.5/0.35/0.35/0.35/0.35/0.35/0.35/0.35/0.35/0.35/0.35/0.35/0.35/0.35/0.35/0.45 (per signal layer), hole 0.15, L1 to L16, tented both sides, 10 vias
v18: diameter 0.2/0/0.2 (per signal layer), hole 0.1, L1 to L3 (Sign), tented both sides, 9 vias
v19: diameter 0.4, hole 0.1, L1 to L16, 7 vias
v20: diameter 1.15, hole 1.15, L1 to L16, 6 vias
v21: diameter 1.65, hole 1.65, L1 to L16, 6 vias
v22: diameter 0.5, hole 0.2, L3 (Sign) to L6 (PWR/GND), tented both sides, 6 vias
v23: diameter 0.35/0/0.35 (per signal layer), hole 0.127, L14 (Sign) to L16, tented both sides, 5 vias
v24: diameter 0.2, hole 0.1, L1 to L16, 4 vias
v25: diameter 0.4, hole 0.2, L1 to L16, tented both sides, 2 vias
v26: diameter 0.4, hole 0.15, L1 to L16, 2 vias
v27: diameter 0.5/0.35/0.35/0.35/0.35/0.35/0.35/0.35/0.35/0.35/0.35/0.35/0.35/0.35/0.35/0.5 (per signal layer), hole 0.15, L1 to L16, 2 vias
v28: diameter 0.35, hole 0.127, L3 (Sign) to L6 (PWR/GND), tented both sides, 2 vias
v29: diameter 5.5, hole 3.5, L1 to L16, 1 vias
v30: diameter 0.5/0.35/0.35/0.35/0.35/0.35/0.35/0.35/0.35/0.35/0.35/0.35/0.35/0.35/0.35/0.5 (per signal layer), hole 0.2, L1 to L16, 1 vias
v31: diameter 0.35/0.35/0.35 (per signal layer), hole 0.127, L1 to L3 (Sign), tented both sides, 1 vias
v32: diameter 0.45/0/0.45 (per signal layer), hole 0.15, L1 to L3 (Sign), tented both sides, 1 vias
v33: diameter 0.45/0/0.45 (per signal layer), hole 0.2, L14 (Sign) to L16, tented both sides, 1 vias
v34: diameter 0.35, hole 0.127, L2 (GND) to L3 (Sign), 1 vias
v35: diameter 0.35, hole 0.127, L1 to L2 (GND), 1 vias

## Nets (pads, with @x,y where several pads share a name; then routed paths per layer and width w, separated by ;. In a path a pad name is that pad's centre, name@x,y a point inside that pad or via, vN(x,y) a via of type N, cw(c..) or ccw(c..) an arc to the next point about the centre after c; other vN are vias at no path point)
0.85V@40A_INA: C359.2 C360.2 C361.2 C362.2 C363.2 C364.2 C365.2 C366.2 C367.2 C368.2 C369.2 C370.2 C377.2 C378.2 C379.2 C380.2 C381.2 C382.2 C383.2 C384.2 C385.2 C386.2 C387.2 C388.2 L9.2 L10.2 R617.1 U72.10 | length 0.2
  L7(PWR/GND) w0.3: 116.278,181.956 116.278,182.159
  other v1: 99.543,228.727 100.232,228.727 100.922,228.727 101.612,228.727 102.302,228.727 102.991,228.727 103.681,228.727 104.371,228.727 105.061,228.727 105.75,228.727 106.44,228.727 107.13,228.727 107.82,228.727 108.509,228.727 109.199,228.727 109.889,228.727 110.579,228.727 111.268,228.727 111.958,228.727 112.648,228.727 113.338,228.727 99.554,229.517 100.244,229.517 100.933,229.517 101.623,229.517 102.313,229.517 103.003,229.517 103.693,229.517 104.382,229.517 105.072,229.517 105.762,229.517 106.452,229.517 107.141,229.517 107.831,229.517 108.521,229.517 109.211,229.517 109.9,229.517 110.59,229.517 111.28,229.517 111.97,229.517 112.659,229.517 113.349,229.517 99.554,230.34 100.244,230.34 100.933,230.34 101.623,230.34 102.313,230.34 103.003,230.34 103.693,230.34 104.382,230.34 105.072,230.34 105.762,230.34 106.452,230.34 107.141,230.34 107.831,230.34 108.521,230.34 109.211,230.34 109.9,230.34 110.59,230.34 111.28,230.34 111.97,230.34 112.659,230.34 113.349,230.34 99.543,240.424 100.232,240.424 100.922,240.424 101.612,240.424 102.302,240.424 102.991,240.424 103.681,240.424 104.371,240.424 105.061,240.424 105.75,240.424 106.44,240.424 107.13,240.424 107.82,240.424 108.509,240.424 109.199,240.424 109.889,240.424 110.579,240.424 111.268,240.424 111.958,240.424 112.648,240.424 113.338,240.424 99.554,241.214 100.244,241.214 100.933,241.214 101.623,241.214 102.313,241.214 103.003,241.214 103.693,241.214 104.382,241.214 105.072,241.214 105.762,241.214 106.452,241.214 107.141,241.214 107.831,241.214 108.521,241.214 109.211,241.214 109.9,241.214 110.59,241.214 111.28,241.214 111.97,241.214 112.659,241.214 113.349,241.214 99.554,242.037 100.244,242.037 100.933,242.037 101.623,242.037 102.313,242.037 103.003,242.037 103.693,242.037 104.382,242.037 105.072,242.037 105.762,242.037 106.452,242.037 107.141,242.037 107.831,242.037 108.521,242.037 109.211,242.037 109.9,242.037 110.59,242.037 111.28,242.037 111.97,242.037 112.659,242.037 113.349,242.037
  other v8: 129.565,289.776 131.318,289.776 133.071,289.776 134.823,289.776 136.576,289.776 129.565,291.529 131.318,291.529 133.071,291.529 134.823,291.529 136.576,291.529 129.565,293.282 131.318,293.282 133.071,293.282 134.823,293.282 136.576,293.282 129.565,295.034 131.318,295.034 133.071,295.034 134.823,295.034 136.576,295.034 129.565,296.787 131.318,296.787 133.071,296.787 134.823,296.787 136.576,296.787 129.565,298.539 131.318,298.539 133.071,298.539 134.823,298.539 136.576,298.539 129.565,300.292 131.318,300.292 133.071,300.292 134.823,300.292 136.576,300.292 129.565,302.045 131.318,302.045 133.071,302.045 134.823,302.045 136.576,302.045
  other v20: 143.119,326.624
  other v21: 143.118,306.624
0V9@1A_REG3: C709.2 C710.2 R673.2 U1.A10 U1.C10 U1.F8 U1.H8 U1.M8 U1.P8 U70.11 U70.12 | length 2.8
  L1 w0.3: U70.11@152.889,281.004 v6(153.784,281.004) v6@153.797,281.004 ; U70.12@152.889,281.504 v6(154.745,281.503)
  other v3: 167.397,295.539 169.397,295.539 173.397,295.539 175.397,295.539 162.397,297.539 164.397,297.539
  other v6: 151.752,286.093 150.812,286.74 152.781,286.779
0V85@2A: C675.2 C746.2 FB45.2 U1.J23 U1.L23 | length 24.2
  L7(PWR/GND) w0.254: 160.122,311.721 160.769,311.074 169.862,311.074 170.397,310.539 ; 160.223,312.509 160.706,312.026 171.59,312.026 171.907,311.709 171.907,311.029 172.397,310.539
1V0@1.5A: C505.2 C506.2 C507.2 C508.2 C509.2 C510.2 C511.2 C512.2 C513.2 C514.2 C555.2 R397.2 U39.6 U39.24 U39.31 U39.42 U51.8
1V8@0.5A_ADC_filtered: C705.2 C706.2 C749.2 C750.2 C757.1 C758.2 D28.3 FB38.1 FB40.1 FB42.1 R671.2 R694.1 R745.2 U1.K10 U1.L10 U1.M10 U1.N10 U1.P10 U1.T22 U1.U21 U1.V21 U1.V22 U70.14 U70.15 | length 3.6
  L1 w0.254: v5(183.074,282.55) C706.2@183.959,282.55
  L1 w0.3: U70.14@152.889,282.504 v6(154.745,282.504) ; U70.15@152.889,283.003 v6(153.784,283.003) v6@153.797,283.003
  other v3: 171.397,297.539 172.397,297.539 173.397,297.539 174.397,297.539 175.397,297.539
  other v5: 178.397,308.539 179.397,308.539 177.397,309.539 179.397,309.539
1V8@1.5A: C1.2 C2.2 C485.2 C486.2 C487.2 C488.2 C489.2 C490.2 C553.2 C561.2 R394.2 U39.13 U39.48 U45.28 U45.30 U50.8 U58.8
2V5@1.5A: C499.2 C500.2 C501.2 C502.2 C503.2 C504.2 C551.2 C782.2 C783.2 C784.2 C785.2 C786.2 C787.2 C788.2 C789.2 R391.2 R392.2 U8.B1 U8.R6 U9.B1 U9.R6 U10.B1 U10.R6 U11.B1 U11.R6 U39.3 U39.9 U49.8 | length 8.4
  L1 w0.2: U8.B1@206.857,328.86 v3(207.785,328.86)
  L1 w0.25: U9.B1@172.476,328.86 v3(172.879,328.457) ; v3(177.133,339.664) U11.R6@177.536,339.26 ; U11.B1@183.936,328.86 v3(184.507,328.86) ; v3(188.593,339.664) U10.R6@188.997,339.26
  L1 w0.254: 199.032,340.739 199.094,340.676 199.094,340.623 U8.R6@200.457,339.26
  L1 w0.3: U10.B1@195.397,328.86 195.841,328.86 196.888,329.908 198.022,329.908 198.044,329.886 v1(198.044,329.87)
  L16 w0.3: v1(198.044,329.87) v1@198.044,329.895
3.3V_LN_1: C55.2 C56.2 C59.2 C60.2 C65.2 C66.2 C71.2 C72.2 C84.2 C85.2 C94.2 C95.2 C569.2 FB2.1 FB3.1 FB4.1 FB5.1 FB6.1 FB7.1 FB33.2
3.3V_PS_Config: X6.1 X6.4
3.3V_Stable_1: C149.2 C150.2 C151.2 C152.2 C153.2 C154.2 C155.2 C156.2 C157.2 C158.2 C159.2 C160.2 C161.2 C181.2 C182.2 C183.2 C184.2 C185.2 C186.2 C187.2 C188.2 C189.2 C190.2 C191.2 C192.2 C193.2 C565_U_5V_to_3V33.2 C566_U_5V_to_3V33.2 C567_U_5V_to_3V33.2 R430_U_5V_to_3V33.2 R431_U_5V_to_3V33.2 U12.2 U12.5 U12.8 U12.11 U12.14 U12.17 U12.20 U12.23 U12.26 U12.29 U12.32 U12.35 U59_U_5V_to_3V33.8
3.3V_Stable_2: C166.2 C167.2 C168.2 C169.2 C170.2 C171.2 C172.2 C173.2 C174.2 C175.2 C176.2 C177.2 C178.2 C194.2 C195.2 C196.2 C197.2 C198.2 C199.2 C200.2 C201.2 C202.2 C203.2 C204.2 C205.2 C206.2 C565_U_5V_to_3V32.2 C566_U_5V_to_3V32.2 C567_U_5V_to_3V32.2 R430_U_5V_to_3V32.2 R431_U_5V_to_3V32.2 U13.2 U13.5 U13.8 U13.11 U13.14 U13.17 U13.20 U13.23 U13.26 U13.29 U13.32 U13.35 U59_U_5V_to_3V32.8
3.3V_Stable_3: C111.2 C112.2 C113.2 C114.2 C115.2 C116.2 C117.2 C118.2 C119.2 C120.2 C121.2 C122.2 C123.2 C128.2 C129.2 C130.2 C131.2 C132.2 C133.2 C134.2 C135.2 C136.2 C137.2 C138.2 C139.2 C140.2 C565_U_5V_to_3V31.2 C566_U_5V_to_3V31.2 C567_U_5V_to_3V31.2 R430_U_5V_to_3V31.2 R431_U_5V_to_3V31.2 U59_U_5V_to_3V31.8
3V3_NVMe: C332.2 J27.2 J27.4 J27.12 J27.14 J27.16 J27.18 J27.62 J27.64 J27.66 U18.C2 U18.D1 U18.D2 U18.E1 U18.E2 U18.F1 U18.F2
3V3_RAIL: C303_I2C_Bridge_GPIO.2 C303_I2C_Bridge_PCIE.2 C303_I2C_Bridge_SFP.2 C309_U_Pomiar_pradu_napiecia_1.2 C309_U_Pomiar_pradu_napiecia_2.2 C309_U_Pomiar_pradu_napiecia_3.2 C309_U_Pomiar_pradu_napiecia_4.2 C309_U_Pomiar_pradu_napiecia_5.2 C309_U_Pomiar_pradu_napiecia_6.2 C309_U_Pomiar_pradu_napiecia_7.2 C309_U_Pomiar_pradu_napiecia_8.2 C309_U_Pomiar_pradu_napiecia_9.2 C309_U_Pomiar_pradu_napiecia_10.2 C309_U_Pomiar_pradu_napiecia_11.2 C310.2 C311_I2C_Expander_00.2 C311_I2C_Expander_01.2 C311_I2C_Expander_02.2 C311_I2C_Expander_10.2 C311_I2C_Expander_11.2 C311_I2C_Expander_12.2 C311_I2C_Expander_16.2 C311_I2C_Expander_17.2 C311_I2C_Expander_18.2 C311_I2C_Expander_Main_Rst.2 C311_I2C_Expander_PWR_CLK.2 C311_I2C_Expander_PWR_Dist.2 C311_I2C_Expander_SFP.2 C324.2 C331.2 C339.2 C545.2 C546.2 C550.2 C552.2 C554.2 C562.2 C585.2 C623.2 C654.2 C676.2 C707.2 C708.2 C721.2 C732.2 C735.2 C792.2 F1_PCIE0.2 F1_PCIE1.2 F1_PCIE2.2 F1_PCIE3.2 F1_PCIE4.2 FB23.1 FB24.1 J28.4 L1.1 L2.1 L3.1 L4.1 L5.1 L6.1 L7.1 L8.1 P12.1 R3_I2C_Bridge_GPIO.2 R3_I2C_Bridge_PCIE.2 R3_I2C_Bridge_SFP.2 R4_I2C_Bridge_GPIO.2 R4_I2C_Bridge_PCIE.2 R4_I2C_Bridge_SFP.2 R5_I2C_Bridge_GPIO.2 R5_I2C_Bridge_PCIE.2 R5_I2C_Bridge_SFP.2 R6_I2C_Bridge_GPIO.2 R6_I2C_Bridge_PCIE.2 R6_I2C_Bridge_SFP.2 R7_I2C_Bridge_GPIO.2 R7_I2C_Bridge_PCIE.2 R7_I2C_Bridge_SFP.2 R8_I2C_Bridge_GPIO.2 R8_I2C_Bridge_PCIE.2 R8_I2C_Bridge_SFP.2 R9_I2C_Bridge_GPIO.2 R9_I2C_Bridge_PCIE.2 R9_I2C_Bridge_SFP.2 R10_I2C_Bridge_GPIO.2 R10_I2C_Bridge_PCIE.2 R10_I2C_Bridge_SFP.2 R11.2 R13.1 R16.1 R29.2 R30.2 R65.2 R66.2 R67.2 R68.2 R71.2 R72.2 R124.2 R135.2 R136.2 R137.2 R138.2 R141.2 R142.2 R145.2 R146.2 R147.2 R148.2 R151.2 R152.2 R155.2 R156.2 R157.2 R158.2 R161.2 R162.2 R175.1 R179.1 R184.1 R188.1 R193.1 R197.1 R202.1 R206.1 R211.1 R219.1 R223_I2C_Bridge_GPIO.2 R223_I2C_Bridge_PCIE.2 R223_I2C_Bridge_SFP.2 R224_I2C_Bridge_GPIO.2 R224_I2C_Bridge_PCIE.2 R224_I2C_Bridge_SFP.2 R225_I2C_Bridge_GPIO.2 R225_I2C_Bridge_PCIE.2 R225_I2C_Bridge_SFP.2 R226_I2C_Bridge_GPIO.2 R226_I2C_Bridge_PCIE.2 R226_I2C_Bridge_SFP.2 R227_I2C_Bridge_GPIO.2 R227_I2C_Bridge_PCIE.2 R227_I2C_Bridge_SFP.2 R230.1 R231_SPI_bridge_Main.2 R231_SPI_bridge_PCIe.2 R233_SPI_bridge_Main.2 R233_SPI_bridge_PCIe.2 R236_SPI_bridge_Main.2 R236_SPI_bridge_PCIe.2 R238_SPI_bridge_PCIe.2 R240_SPI_bridge_Main.2 R240_SPI_bridge_PCIe.2 R241.2 R243.2 R252.2 R253.2 R281.2 R287.2 R376.2 R377.2 R378.2 R388.1 R425_SPI_bridge_Main.2 R425_SPI_bridge_PCIe.2 R426_SPI_bridge_Main.1 R426_SPI_bridge_PCIe.1 R427.2 R428.2 R429.2 R448_U_Pomiar_pradu_napiecia_3.2 R449.2 R451.2 R453.2 R455.2 R458.2 R462.2 R463.1 R468.1 R469.2 R471.2 R473.2 R475.2 R477.2 R479.2 R492.2 R494.2 R496.2 R500.2 R502.2 R504.2 R508.2 R510.2 R512.2 R516.2 R518.2 R520.2 R524.2 R526.2 R528.2 R538.2 R558_I2C_Bridge_GPIO.2 R558_I2C_Bridge_PCIE.2 R558_I2C_Bridge_SFP.2 R559_I2C_Bridge_GPIO.2 R559_I2C_Bridge_PCIE.2 R559_I2C_Bridge_SFP.2 R560_I2C_Bridge_GPIO.2 R560_I2C_Bridge_PCIE.2 R560_I2C_Bridge_SFP.2 R562.1 R566.1 R570.1 R574.1 R578.1 R582.1 R586.1 R590.1 R596.1 R599.2 R600.2 R603_SPI_bridge_Main.1 R603_SPI_bridge_PCIe.1 R604_SPI_bridge_Main.2 R604_SPI_bridge_PCIe.2 R605_SPI_bridge_Main.1 R605_SPI_bridge_PCIe.1 R630.1 R632.2 R633.2 R634.2 R646.1 R676.2 R691.1 R697.2 R699.2 R701.2 R703.2 R705.2 R707.2 R730.2 R731.2 R732.2 R733.2 R734.2 R738.2 R740.2 R742.2 R746.2 R747.2 R748.2 R749.2 R750.2 R751.2 R752.2 R753.2 R754.2 R755.2 R756.2 R757.2 R758.2 R760.2 R762.2 R825.1 R826.1 R827.1 R828.1 R829.2 R831.2 R833.2 R841.2 R843.2 R845.2 R887_SPI_bridge_Main.1 R887_SPI_bridge_PCIe.1 R888_SPI_bridge_Main.2 R888_SPI_bridge_PCIe.2 R889_SPI_bridge_Main.1 R889_SPI_bridge_PCIe.1 R891_SPI_bridge_Main.1 R891_SPI_bridge_PCIe.1 R892_SPI_bridge_Main.2 R892_SPI_bridge_PCIe.2 R893_SPI_bridge_Main.1 R893_SPI_bridge_PCIe.1 R895_SPI_bridge_Main.1 R895_SPI_bridge_PCIe.1 R896_SPI_bridge_Main.2 R896_SPI_bridge_PCIe.2 R897_SPI_bridge_Main.1 R897_SPI_bridge_PCIe.1 R899_SPI_bridge_Main.1 R899_SPI_bridge_PCIe.1 R1002.2 U3_I2C_Bridge_GPIO.21 U3_I2C_Bridge_PCIE.21 U3_I2C_Bridge_SFP.21 U15.15 U18.C3 U18.D3 U18.D4 U18.E3 U18.E4 U18.F3 U18.F4 U19.13 U19.16 U24_SPI_bridge_Main.15 U24_SPI_bridge_Main.16 U24_SPI_bridge_PCIe.15 U24_SPI_bridge_PCIe.16 U25_SPI_bridge_Main.15 U25_SPI_bridge_Main.16 U25_SPI_bridge_PCIe.15 U25_SPI_bridge_PCIe.16 U26_SPI_bridge_Main.15 U26_SPI_bridge_Main.16 U26_SPI_bridge_PCIe.15 U26_SPI_bridge_PCIe.16 U27_SPI_bridge_Main.16 U27_SPI_bridge_PCIe.15 U27_SPI_bridge_PCIe.16 U28_SPI_bridge_Main.15 U28_SPI_bridge_Main.16 U28_SPI_bridge_PCIe.15 U28_SPI_bridge_PCIe.16 U35_I2C_Expander_00.5 U35_I2C_Expander_01.5 U35_I2C_Expander_02.5 U35_I2C_Expander_10.5 U35_I2C_Expander_11.5 U35_I2C_Expander_12.5 U35_I2C_Expander_16.5 U35_I2C_Expander_17.5 U35_I2C_Expander_18.5 U35_I2C_Expander_Main_Rst.5 U35_I2C_Expander_PWR_CLK.5 U35_I2C_Expander_PWR_Dist.5 U35_I2C_Expander_SFP.5 U36_U_Translator_I2C1.7 U36_U_Translator_I2C2.7 U36_U_Translator_I2C3.2 U36_U_Translator_I2C3.7 U36_U_Translator_I2C4.7 U45.32 U47.A4 U49.1 U49.2 U50.1 U50.2 U51.1 U51.2 U58.5 U63.3 U64_U_Pomiar_pradu_napiecia_1.6 U64_U_Pomiar_pradu_napiecia_2.6 U64_U_Pomiar_pradu_napiecia_3.6 U64_U_Pomiar_pradu_napiecia_3.8 U64_U_Pomiar_pradu_napiecia_3.9 U64_U_Pomiar_pradu_napiecia_4.6 U64_U_Pomiar_pradu_napiecia_5.6 U64_U_Pomiar_pradu_napiecia_6.6 U64_U_Pomiar_pradu_napiecia_7.6 U64_U_Pomiar_pradu_napiecia_8.6 U64_U_Pomiar_pradu_napiecia_9.6 U64_U_Pomiar_pradu_napiecia_10.6 U64_U_Pomiar_pradu_napiecia_11.6 U67.1 U68.1 U69.1 U69.2 U69.3 U69.15 U69.16 U70.1 U70.2 U70.4 U70.5 U72.6 U73.2 U74.5 U78.5 | length 15
  L1 w0.254: U64_U_Pomiar_pradu_napiecia_3.9@116.278,182.659 U64_U_Pomiar_pradu_napiecia_3.8@116.278,183.159 ; U64_U_Pomiar_pradu_napiecia_3.6@116.278,184.159 116.278,184.858 v6(116.281,184.861)
  L1 w0.3: R448_U_Pomiar_pradu_napiecia_3.2@107.759,184.901 107.759,183.101 108.201,182.659 U64_U_Pomiar_pradu_napiecia_3.9@116.278,182.659
  L1 w0.5: v6(52.01,182.749) R11.2@52.01,183.563 ; v6(52.018,192.237) R13.1@52.018,193.051 ; v6(52.5,173.277) R630.1@52.5,174.091 ; 52.5,175.125 52.5,175.939
  other v6: 112.903,186.048 109.306,186.088 111.104,186.068 107.508,186.109 105.71,186.129 103.911,186.149 102.113,186.169 110.215,186.977 112.014,186.957 108.417,186.998 106.619,187.018 103.022,187.058 104.821,187.038
5V_LN: C580.2 R443.2 R608.2 U12.42 U30.1 U30.5 U62.9 U62.10 X2.14
5V_RAIL: C3.2 C515.2 C516.2 C563_U_5V_to_3V31.2 C563_U_5V_to_3V32.2 C563_U_5V_to_3V33.2 C564_U_5V_to_3V31.2 C564_U_5V_to_3V32.2 C564_U_5V_to_3V33.2 C574.2 C575.2 C720.2 C733.2 D23.2 R315.2 R448_U_Pomiar_pradu_napiecia_6.2 R651.2 R656.2 T22.1 T27.2 T30.2 U40.1 U40.2 U40.3 U42.1 U42.2 U42.3 U45.21 U46.C3 U46.D3 U46.D4 U46.E3 U46.E4 U46.F3 U46.F4 U59_U_5V_to_3V31.1 U59_U_5V_to_3V31.2 U59_U_5V_to_3V32.1 U59_U_5V_to_3V32.2 U59_U_5V_to_3V33.1 U59_U_5V_to_3V33.2 U61.1 U61.2 U61.4 U61.5 U64_U_Pomiar_pradu_napiecia_6.8 U64_U_Pomiar_pradu_napiecia_6.9 U73.1
  other v6: 105.778,202.507 102.181,202.548 103.98,202.527 100.383,202.568 98.585,202.588 96.787,202.608 94.988,202.629 103.091,203.437 104.889,203.416 101.292,203.457 99.494,203.477 95.898,203.517 97.696,203.497
12V_LT3042: C304.1 C305.1 C306.1 C307.1 C604.2 C714.2 FB34.1 L15.1 R448_U_Pomiar_pradu_napiecia_5.2 R626.2 U17.C3 U17.D3 U17.D4 U17.E3 U17.E4 U17.F3 U17.F4 U19.9 U19.11 U19.26 U19.28 U20.C3 U20.D3 U20.D4 U20.E3 U20.E4 U20.F3 U20.F4 U21.C3 U21.D3 U21.D4 U21.E3 U21.E4 U21.F3 U21.F4 U22.C3 U22.D3 U22.D4 U22.E3 U22.E4 U22.F3 U22.F4 U23.C3 U23.D3 U23.D4 U23.E3 U23.E4 U23.F3 U23.F4 U64_U_Pomiar_pradu_napiecia_5.8 U64_U_Pomiar_pradu_napiecia_5.9 U71.1 | length 0.4
  L1 w0.254: R626.2@59.997,210.611 59.997,210.961
  other v6: 107.235,219.335 105.437,219.355 103.638,219.375 100.042,219.416 101.84,219.395 98.244,219.436 96.446,219.456 106.346,220.244 104.548,220.264 100.951,220.305 102.749,220.284 99.153,220.325 97.355,220.345
12V_PCIE0: R448_U_Pomiar_pradu_napiecia_7.1 U17.C2 U17.D1 U17.D2 U17.E1 U17.E2 U17.F1 U17.F2 U64_U_Pomiar_pradu_napiecia_7.10
12V_PCIE0_CM: J1_PCIE0.2 J1_PCIE0.4 R448_U_Pomiar_pradu_napiecia_7.2 U64_U_Pomiar_pradu_napiecia_7.8 U64_U_Pomiar_pradu_napiecia_7.9
12V_PCIE1: R448_U_Pomiar_pradu_napiecia_8.1 U20.C2 U20.D1 U20.D2 U20.E1 U20.E2 U20.F1 U20.F2 U64_U_Pomiar_pradu_napiecia_8.10
12V_PCIE1_CM: J1_PCIE1.2 J1_PCIE1.4 R448_U_Pomiar_pradu_napiecia_8.2 U64_U_Pomiar_pradu_napiecia_8.8 U64_U_Pomiar_pradu_napiecia_8.9
12V_PCIE2: R448_U_Pomiar_pradu_napiecia_9.1 U21.C2 U21.D1 U21.D2 U21.E1 U21.E2 U21.F1 U21.F2 U64_U_Pomiar_pradu_napiecia_9.10
12V_PCIE2_CM: J1_PCIE2.2 J1_PCIE2.4 R448_U_Pomiar_pradu_napiecia_9.2 U64_U_Pomiar_pradu_napiecia_9.8 U64_U_Pomiar_pradu_napiecia_9.9
12V_PCIE3: R448_U_Pomiar_pradu_napiecia_10.1 U22.C2 U22.D1 U22.D2 U22.E1 U22.E2 U22.F1 U22.F2 U64_U_Pomiar_pradu_napiecia_10.10
12V_PCIE3_CM: J1_PCIE3.2 J1_PCIE3.4 R448_U_Pomiar_pradu_napiecia_10.2 U64_U_Pomiar_pradu_napiecia_10.8 U64_U_Pomiar_pradu_napiecia_10.9
12V_PCIE4: R448_U_Pomiar_pradu_napiecia_11.1 U23.C2 U23.D1 U23.D2 U23.E1 U23.E2 U23.F1 U23.F2 U64_U_Pomiar_pradu_napiecia_11.10
12V_PCIE4_CM: J1_PCIE4.2 J1_PCIE4.4 R448_U_Pomiar_pradu_napiecia_11.2 U64_U_Pomiar_pradu_napiecia_11.8 U64_U_Pomiar_pradu_napiecia_11.9
\I\N\T\: R709.2 U39.44
\M\R\: D11.1 D12.1 P5.1 R371.1 U44.13
ADP1741_3.6V: C308.2 C354.2 C355.2 C570.2 C603.2 L13.2 R113.2 U60.1 U60.2 U60.3 U60.15 U60.16
ADP1741_EN: U35_I2C_Expander_PWR_CLK.20 U60.4
ADP1741_PG: U35_I2C_Expander_PWR_CLK.19 U60.5
ADP_Vin_1: C395.2 R285.2 U37.3
ADP_Vin_2: C436.2 R303.2 U38.3 | length 2.8
  L1 w0.254: C436.2@58.746,207.523 59.82,207.523 60.129,207.214 U38.3@61.453,207.214
AGND: C45.1 C46.1 C55.1 C56.1 C57.1 C58.1 C59.1 C60.1 C61.1 C62.1 C65.1 C66.1 C68.1 C69.1 C71.1 C72.1 C73.1 C74.1 C84.1 C85.1 C86.1 C87.1 C94.1 C95.1 C97.1 C98.1 C111.1 C112.1 C113.1 C114.1 C115.1 C116.1 C117.1 C118.1 C119.1 C120.1 C121.1 C122.1 C123.1 C128.1 C129.1 C130.1 C131.1 C132.1 C133.1 C134.1 C135.1 C136.1 C137.1 C138.1 C139.1 C140.1 C149.1 C150.1 C151.1 C152.1 C153.1 C154.1 C155.1 C156.1 C157.1 C158.1 C159.1 C160.1 C161.1 C166.1 C167.1 C168.1 C169.1 C170.1 C171.1 C172.1 C173.1 C174.1 C175.1 C176.1 C177.1 C178.1 C181.1 C182.1 C183.1 C184.1 C185.1 C186.1 C187.1 C188.1 C189.1 C190.1 C191.1 C192.1 C193.1 C194.1 C195.1 C196.1 C197.1 C198.1 C199.1 C200.1 C201.1 C202.1 C203.1 C204.1 C205.1 C206.1 C322.1 C323.1 C324.1 C326.1 C327.1 C328.1 C329.1 C335.1 C336.1 C337.1 C338.1 C339.1 C340.1 C344.2 C563_U_5V_to_3V31.1 C563_U_5V_to_3V32.1 C563_U_5V_to_3V33.1 C564_U_5V_to_3V31.1 C564_U_5V_to_3V32.1 C564_U_5V_to_3V33.1 C565_U_5V_to_3V31.1 C565_U_5V_to_3V32.1 C565_U_5V_to_3V33.1 C566_U_5V_to_3V31.1 C566_U_5V_to_3V32.1 C566_U_5V_to_3V33.1 C567_U_5V_to_3V31.1 C567_U_5V_to_3V32.1 C567_U_5V_to_3V33.1 C568.1 C569.1 C570.1 C571.2 C580.1 C581.1 C582.1 C583.1 C584.1 C713.1 C714.1 FB35.2 J2.2 J2.3 J2.4 J2.5 J3.2 J3.3 J3.4 J3.5 J4.1 J4.3 J5.1 J5.3 J6.2 J6.3 J6.4 J6.5 J7.2 J7.3 J7.4 J7.5 J26.2 J26.3 J26.4 J26.5 R76.2 R79.1 R246.1 R247.1 R248.1 R249.2 R254.1 R255.1 R256.1 R258.2 R261.1 R262.1 R263.1 R264.1 R265.1 R291.2 R301.2 R387.1 R432_U_5V_to_3V31.1 R432_U_5V_to_3V32.1 R432_U_5V_to_3V33.1 R434.1 R444.1 R445.1 R482.2 R483.2 R487.1 R609.1 T36.2 U12.36 U12.41 U12.53 U13.36 U13.41 U13.53 U30.4 U30.13 U31.1 U31.2 U31.17 U32.1 U32.17 U33.5 U33.6 U33.14 U33.17 U59_U_5V_to_3V31.4 U59_U_5V_to_3V31.9 U59_U_5V_to_3V32.4 U59_U_5V_to_3V32.9 U59_U_5V_to_3V33.4 U59_U_5V_to_3V33.9 U60.6 U60.17 U62.5 U62.8 U62.11 U71.2 X1.1 X1.3 X1.4 X1.5 X1.6 X1.7 X1.8 X1.9 X1.11 X1.12 X1.13 X1.15 X1.16 X2.1 X2.3 X2.4 X2.5 X2.6 X2.7 X2.8 X2.9 X2.11 X2.12 X2.13 X2.15 X2.16
  other v2: 421.804,57.122 422.904,57.122 421.804,58.222 422.904,58.222 445.646,162.76 446.408,162.76 445.646,163.522 446.408,163.522 445.646,164.284 446.408,164.284 153.862,215.991 154.862,215.991 153.862,216.991 154.862,216.991 179.025,235.341 180.125,235.341 181.225,235.341 182.325,235.341 183.425,235.341 184.525,235.341 179.025,236.441 180.125,236.441 181.225,236.441 182.325,236.441 183.425,236.441 184.525,236.441 179.025,237.541 180.125,237.541 181.225,237.541 182.325,237.541 183.425,237.541 184.525,237.541 179.025,238.641 180.125,238.641 181.225,238.641 182.325,238.641 183.425,238.641 184.525,238.641 179.025,239.741 180.125,239.741 181.225,239.741 182.325,239.741 183.425,239.741 184.525,239.741 251.341,243.886 252.341,243.886 251.341,244.886 252.341,244.886 51.646,364.32 52.646,364.32 51.646,365.32 52.646,365.32 72.752,551.515 73.852,551.515 74.952,551.515 76.052,551.515 77.152,551.515 78.252,551.515 72.752,552.614 73.852,552.614 74.952,552.614 76.052,552.614 77.152,552.614 78.252,552.614 72.752,553.715 73.852,553.715 74.952,553.715 76.052,553.715 77.152,553.715 78.252,553.715 72.752,554.814 73.852,554.814 74.952,554.814 76.052,554.814 77.152,554.814 78.252,554.814 72.752,555.915 73.852,555.915 74.952,555.915 76.052,555.915 77.152,555.915 78.252,555.915
  other v12: 64.083,541.374 65.033,541.374 64.083,542.323 65.033,542.323
AGND_1: C389.1 C393.1 C395.1 C398.1 C399.1 C639.1 C640.1 C641.1 C642.1 C643.1 C644.1 R290.1 R294.1 R300.1 U37.6 U37.33
  other v2: 64.825,178.017 66.025,178.017 63.875,178.967 64.825,178.967 66.025,178.967 66.975,178.967 63.875,180.167 64.825,180.167 66.025,180.167 66.975,180.167 64.825,181.117 66.025,181.117
AGND_2: C430.1 C434.1 C436.1 C439.1 C440.1 C548.1 C549.1 C647.1 C648.1 C650.1 C652.1 R312.1 R318.1 R627.1 U38.6 U38.33 | length 7.4
  L1 w0.254: R312.1@57.926,204.716 57.926,205.54 57.15,206.316 57.15,207.205 57.468,207.523 C436.1@57.967,207.523 ; 57.937,205.529 59.906,205.529 60.091,205.714 U38.6@61.453,205.714
  other v2: 63.103,204.914 64.303,204.914 62.153,205.864 63.103,205.864 64.303,205.864 65.253,205.864 62.153,207.064 63.103,207.064 64.303,207.064 65.253,207.064 63.103,208.014 64.303,208.014
  other v16: 60.944,210.483 62.953,211.029 63.953,211.044 62.838,212.229
Analog0_R: R395.1 U1.K11
Analog1_R: R398.1 U1.K13
Analog2_R: R506.1 U1.J12
ANGD: C345.1 C349.1 C351.1 C356.1 C357.1 C358.2 C634.1 C635.1 R273.1 U34.6 U34.33
  other v2: 64.472,233.839 65.672,233.839 63.522,234.789 64.472,234.789 65.672,234.789 66.622,234.789 63.522,235.989 64.472,235.989 65.672,235.989 66.622,235.989 64.472,236.939 65.672,236.939
  other v16: 66.055,230.182 64.44,230.197 59.876,233.839 60.241,236.629 63.839,239.52 66.32,240.47
B223_Rx0_N: J1_PCIE0.21 U1.W3 | length 181.2
  L14 (Sign) w0.076: v3(180.397,290.539) 180.397,290.732 cw(c180.584,290.732) 180.584,290.919 181.534,290.919 cw(c181.534,290.652) 181.8,290.652 181.8,287.539 ccw(c181.8,287.487) 181.748,287.487
  L14 (Sign) w0.08: v9(158.037,360.528) ccw(c158.037,360.638) 158.147,360.638 158.147,360.947 cw(c158.819,360.947) 158.819,361.619 161.315,361.619 cw(c161.315,361.009) 161.925,361.009 161.925,354.495 ccw(c164.06,354.495) 164.06,352.36 164.224,352.36 209.588,352.36 213.296,352.36 cw(c213.296,350.825) 214.832,350.825 214.832,282.283 cw(c213.728,282.283) 213.728,281.179 183.375,281.179 cw(c183.375,282.806) 181.748,282.806 181.748,287.487
  L16 w0.081: J1_PCIE0.21@157.937,358.792 157.937,359.725 cw(c158.044,359.725) 158.044,359.832 158.044,360.528 v9(158.037,360.528)
B223_Rx0_P: J1_PCIE0.19 U1.W4 | length 179.2
  L14 (Sign) w0.076: v3(180.397,291.539) 180.397,291.381 ccw(c180.584,291.381) 180.584,291.195 181.534,291.195 cw(c181.534,290.652) 182.076,290.652 182.076,287.539 cw(c182.076,287.487) 182.128,287.487
  L14 (Sign) w0.08: v9(158.637,360.528) cw(c158.637,360.638) 158.527,360.638 158.527,360.947 cw(c158.819,360.947) 158.819,361.239 161.315,361.239 cw(c161.315,361.009) 161.545,361.009 161.545,354.495 ccw(c164.06,354.495) 164.06,351.98 164.224,351.98 209.588,351.981 213.296,351.981 cw(c213.296,350.825) 214.452,350.825 214.452,282.283 cw(c213.728,282.283) 213.728,281.559 183.375,281.559 cw(c183.375,282.806) 182.128,282.806 182.128,287.487
  L16 w0.081: v9(158.637,360.528) 158.63,360.528 158.63,359.832 cw(c158.63,359.725) 158.737,359.725 J1_PCIE0.19@158.737,358.792
B223_Rx1_N: J1_PCIE0.27 U1.V5 | length 183.3
  L14 (Sign) w0.076: v3(179.397,292.539) cw(c179.759,292.539) 179.759,292.902 182.791,292.902 cw(c182.791,292.417) 183.275,292.417 183.275,287.539 ccw(c183.275,287.487) 183.223,287.487
  L14 (Sign) w0.08: v9(155.637,360.528) ccw(c155.637,360.638) 155.747,360.638 155.747,360.952 ccw(c155.461,360.952) 155.461,361.239 154,361.239 ccw(c154,360.959) 153.721,360.959 153.721,355.764 ccw(c156.261,355.764) 156.261,353.224 159.246,353.224 cw(c159.246,351.815) 160.655,351.815 ccw(c162.002,351.815) 162.002,350.468 163.678,350.468 207.899,350.468 211.136,350.468 cw(c211.136,347.928) 213.676,347.928 213.676,283.87 cw(c212.204,283.87) 212.204,282.398 184.836,282.398 cw(c184.836,284.011) 183.223,284.011 183.223,287.487
  L16 w0.081: J1_PCIE0.27@155.537,358.792 155.537,359.725 cw(c155.644,359.725) 155.644,359.832 155.644,360.528 v9(155.637,360.528)
B223_Rx1_P: J1_PCIE0.25 U1.V6 | length 183.8
  L14 (Sign) w0.076: v3(179.397,293.539) ccw(c179.759,293.539) 179.759,293.177 182.791,293.177 cw(c182.791,292.417) 183.551,292.417 183.551,287.539 cw(c183.551,287.487) 183.603,287.487
  L14 (Sign) w0.08: v9(156.237,360.528) cw(c156.237,360.638) 156.127,360.638 156.127,360.952 ccw(c155.461,360.952) 155.461,361.619 154,361.619 ccw(c154,360.959) 153.341,360.959 153.341,355.764 ccw(c156.261,355.764) 156.261,352.844 159.246,352.844 cw(c159.246,351.815) 160.275,351.815 ccw(c162.002,351.815) 162.002,350.088 163.678,350.088 207.899,350.088 211.136,350.088 cw(c211.136,347.928) 213.296,347.928 213.296,283.87 cw(c212.204,283.87) 212.204,282.778 184.836,282.778 cw(c184.836,284.011) 183.603,284.011 183.603,287.487
  L16 w0.081: v9(156.237,360.528) 156.23,360.528 156.23,359.832 cw(c156.23,359.725) 156.337,359.725 J1_PCIE0.25@156.337,358.792
B223_Rx2_N: J1_PCIE1.21 U1.T5 | length 110
  L14 (Sign) w0.076: v3(177.397,292.539) 177.397,292.765 cw(c177.533,292.765) 177.533,292.902 177.608,292.902 cw(c177.608,292.76) 177.749,292.76 177.749,290.313 ccw(c178.156,290.313) 178.156,289.907 178.523,289.907 cw(c178.523,289.674) 178.755,289.674 178.755,287.591 cw(c178.703,287.591) 178.703,287.539
  L14 (Sign) w0.08: 178.703,287.539 178.703,261.645 ccw(c180.022,261.645) 180.022,260.326 238.773,260.326 ccw(c238.773,260.833) 239.28,260.833 239.28,274.121 cw(c239.39,274.121) v9(239.39,274.231)
  L16 w0.081: v9(239.39,274.231) 239.382,274.231 239.382,273.034 cw(c239.382,272.927) 239.49,272.927 J1_PCIE1.21@239.49,271.994
B223_Rx2_P: J1_PCIE1.19 U1.T6 | length 109.2
  L14 (Sign) w0.076: v3(177.397,293.539) 177.397,293.314 ccw(c177.533,293.314) 177.533,293.177 177.608,293.177 cw(c177.608,292.76) 178.025,292.76 178.025,290.313 ccw(c178.156,290.313) 178.156,290.182 178.523,290.182 cw(c178.523,289.674) 179.031,289.674 179.031,287.591 ccw(c179.083,287.591) 179.083,287.539
  L14 (Sign) w0.08: 179.083,287.539 179.083,261.645 ccw(c180.022,261.645) 180.022,260.706 238.773,260.706 ccw(c238.773,260.833) 238.9,260.833 238.9,274.121 ccw(c238.79,274.121) v9(238.79,274.231)
  L16 w0.081: J1_PCIE1.19@238.69,271.994 238.69,272.927 cw(c238.797,272.927) 238.797,273.034 238.797,274.231 v9(238.79,274.231)
B223_Rx3_N: J1_PCIE1.27 U1.R3 | length 117.9
  L14 (Sign) w0.076: v3(176.397,290.539) 176.397,290.756 cw(c176.543,290.756) 176.543,290.902 176.664,290.902 cw(c176.664,290.779) 176.786,290.779 176.786,290.449 176.786,287.591 cw(c176.734,287.591) 176.734,287.539
  L14 (Sign) w0.08: 176.734,287.539 176.734,258.775 ccw(c177.787,258.775) 177.787,257.722 241.643,257.722 ccw(c241.643,258.61) 242.531,258.61 242.531,265.134 ccw(c240.586,265.134) 241.961,266.509 ; v9(241.79,274.231) ccw(c241.79,274.121) 241.68,274.121 241.68,267.188 ccw(c242.639,267.188) 241.96,266.509
  L16 w0.081: v9(241.79,274.231) 241.782,274.231 241.782,273.034 cw(c241.782,272.927) 241.89,272.927 J1_PCIE1.27@241.89,271.994
B223_Rx3_P: J1_PCIE1.25 U1.R4 | length 117.2
  L14 (Sign) w0.076: v3(176.397,291.539) 176.397,291.323 ccw(c176.543,291.323) 176.543,291.177 176.664,291.177 cw(c176.664,290.779) 177.062,290.779 177.062,287.591 ccw(c177.114,287.591) 177.114,287.539
  L14 (Sign) w0.08: 177.114,287.539 177.114,258.775 ccw(c177.787,258.775) 177.787,258.102 241.643,258.102 ccw(c241.643,258.61) 242.151,258.61 242.151,265.133 ccw(c240.584,265.133) 241.692,266.241 241.691,266.242 cw(c242.634,267.186) 241.3,267.186 241.3,274.121 ccw(c241.19,274.121) v9(241.19,274.231)
  L16 w0.081: J1_PCIE1.25@241.09,271.994 241.09,272.927 cw(c241.197,272.927) 241.197,273.034 241.197,274.231 v9(241.19,274.231)
B223_Tx0_to_C_N: C268.1 J1_PCIE0.26 | length 2
  L16 w0.081: J1_PCIE0.26@155.937,366.992 C268.1@155.937,369.037
B223_Tx0_to_C_P: C267.1 J1_PCIE0.24 | length 2
  L16 w0.081: J1_PCIE0.24@156.737,366.992 C267.1@156.737,369.037
B223_Tx0C_to_B_N: C268.2 U1.V1 | length 206.3
  L14 (Sign) w0.076: v3(179.397,288.539) 179.397,288.657 cw(c179.641,288.657) 179.641,288.902 cw(c179.641,288.813) 179.73,288.813 179.73,287.539 ccw(c179.73,287.487) 179.678,287.487
  L14 (Sign) w0.08: v9(156.063,372.428) 156.071,372.428 ccw(c156.071,372.529) 156.173,372.529 cw(c156.807,372.529) 156.807,373.163 163.652,373.163 cw(c163.652,372.223) 164.592,372.223 164.592,357.478 ccw(c165.113,357.478) 165.113,356.958 211.76,356.958 216.294,356.958 cw(c216.294,355.511) 217.74,355.511 217.74,279.959 cw(c216.319,279.959) 216.319,278.538 180.861,278.538 cw(c180.861,279.72) 179.678,279.72 179.678,287.487
  L16 w0.08: 156.063,369.747 v9(156.063,372.428)
  L16 w0.081: C268.2@155.937,369.557 155.937,369.621 cw(c156.063,369.621) 156.063,369.747
B223_Tx0C_to_B_P: C267.2 U1.V2 | length 204.3
  L14 (Sign) w0.076: v3(179.397,289.539) 179.397,289.422 ccw(c179.641,289.422) 179.641,289.177 cw(c179.641,288.813) 180.006,288.813 180.006,287.539 cw(c180.006,287.487) 180.058,287.487
  L14 (Sign) w0.08: v9(156.663,372.428) 156.654,372.428 cw(c156.654,372.529) 156.553,372.529 cw(c156.807,372.529) 156.807,372.783 163.652,372.783 cw(c163.652,372.223) 164.212,372.223 164.212,357.478 ccw(c165.113,357.478) 165.113,356.578 211.76,356.578 216.294,356.578 cw(c216.294,355.511) 217.361,355.511 217.361,279.959 cw(c216.319,279.959) 216.319,278.917 180.861,278.917 cw(c180.861,279.72) 180.058,279.72 180.058,287.487
  L16 w0.08: v9(156.663,372.428) 156.663,369.821 ccw(c156.737,369.821) 156.737,369.747
  L16 w0.081: C267.2@156.737,369.557 156.737,369.747
B223_Tx1_to_C_N: C270.1 J1_PCIE0.32 | length 2
  L16 w0.081: J1_PCIE0.32@153.537,366.992 C270.1@153.537,369.037
B223_Tx1_to_C_P: C269.1 J1_PCIE0.30 | length 2
  L16 w0.081: J1_PCIE0.30@154.337,366.992 C269.1@154.337,369.037
B223_Tx1C_to_B_N: C270.2 U1.U3 | length 202.2
  L14 (Sign) w0.076: v3(178.397,290.539) 178.397,290.648 cw(c178.651,290.648) 178.651,290.902 179.506,290.902 cw(c179.506,290.678) 179.73,290.678 179.73,290.427 ccw(c180.276,290.427) 180.276,289.881 180.425,289.881 cw(c180.425,289.547) 180.759,289.547 180.759,287.539 ccw(c180.759,287.487) 180.707,287.487
  L14 (Sign) w0.08: v9(153.637,370.637) ccw(c153.637,370.747) 153.747,370.747 153.747,370.942 cw(c154.445,370.942) 154.445,371.639 162.255,371.639 cw(c162.255,370.51) 163.384,370.51 163.384,356.222 ccw(c164.173,356.222) 164.173,355.434 164.694,355.434 211.137,355.434 214.681,355.434 cw(c214.681,353.847) 216.267,353.847 216.267,281.241 cw(c214.947,281.241) 214.947,279.922 182.181,279.922 cw(c182.181,281.396) 180.707,281.396 180.707,287.487
  L16 w0.081: C270.2@153.537,369.557 153.537,369.64 cw(c153.644,369.64) 153.644,369.747 v9@153.644,370.637 ; v9(153.637,370.637) v9@153.644,370.637 ; v9@153.637,370.713 153.644,370.713 v9@153.644,370.637
B223_Tx1C_to_B_P: C269.2 U1.U4 | length 200.3
  L14 (Sign) w0.076: v3(178.397,291.539) 178.397,291.431 ccw(c178.651,291.431) 178.651,291.177 179.506,291.177 cw(c179.506,290.678) 180.006,290.678 180.006,290.427 ccw(c180.276,290.427) 180.276,290.157 180.425,290.157 cw(c180.425,289.547) 181.035,289.547 181.035,287.539 cw(c181.035,287.487) 181.087,287.487
  L14 (Sign) w0.08: v9(154.237,370.637) cw(c154.237,370.747) 154.127,370.747 154.127,370.942 cw(c154.445,370.942) 154.445,371.259 162.255,371.259 cw(c162.255,370.51) 163.005,370.51 163.005,356.222 ccw(c164.173,356.222) 164.173,355.054 164.706,355.054 211.137,355.054 214.681,355.054 cw(c214.681,353.847) 215.887,353.847 215.887,281.241 cw(c214.947,281.241) 214.947,280.302 182.181,280.302 cw(c182.181,281.396) 181.087,281.396 181.087,287.487
  L16 w0.081: v9(154.237,370.637) v9@154.23,370.637 ; v9@154.237,370.713 154.23,370.713 v9@154.23,370.637 ; C269.2@154.337,369.557 154.337,369.64 ccw(c154.23,369.64) 154.23,369.747 v9@154.23,370.637
B223_Tx2_to_C_N: C272.1 J1_PCIE1.26 | length 2.1
  L16 w0.081: C272.1@241.49,261.709 241.49,262.753 J1_PCIE1.26@241.49,263.794
B223_Tx2_to_C_P: C271.1 J1_PCIE1.24 | length 2.1
  L16 w0.081: C271.1@240.69,261.709 J1_PCIE1.24@240.69,263.794
B223_Tx2C_to_B_N: C272.2 U1.T1 | length 95.1
  L14 (Sign) w0.076: v3(177.397,288.539) 177.397,288.803 cw(c177.495,288.803) 177.495,288.902 177.595,288.902 cw(c177.595,288.76) 177.737,288.76 177.737,287.539 ccw(c177.737,287.487) 177.684,287.487
  L14 (Sign) w0.08: 177.684,287.487 177.684,260.416 ccw(c178.854,260.416) 178.854,259.246 240.589,259.246 ccw(c240.589,259.944) 241.286,259.944 241.286,260.335 v9(241.39,260.439)
  L16 w0.081: v9(241.39,260.439) v9(241.39,260.439) 241.382,260.445 241.382,261.082 C272.2@241.49,261.189
B223_Tx2C_to_B_P: C271.2 U1.T2 | length 94.4
  L14 (Sign) w0.076: v3(177.397,289.539) 177.397,289.276 ccw(c177.495,289.276) 177.495,289.177 177.595,289.177 cw(c177.595,288.76) 178.012,288.76 178.012,287.539 cw(c178.012,287.487) 178.064,287.487
  L14 (Sign) w0.08: 178.064,287.487 178.064,260.416 ccw(c178.854,260.416) 178.854,259.626 240.589,259.626 ccw(c240.589,259.944) 240.906,259.944 240.906,260.322 v9(240.79,260.439)
  L16 w0.081: C271.2@240.69,261.189 240.797,261.082 240.797,260.445 240.791,260.439 v9(240.79,260.439)
B223_Tx3_to_C_N: C275.1 J1_PCIE1.32 | length 2.1
  L16 w0.081: C275.1@243.89,261.709 J1_PCIE1.32@243.89,263.794
B223_Tx3_to_C_P: C274.1 J1_PCIE1.30 | length 2.1
  L16 w0.081: C274.1@243.09,261.709 J1_PCIE1.30@243.09,263.794
B223_Tx3C_to_B_N: C275.2 U1.P1 | length 104.8
  L14 (Sign) w0.076: v3(175.397,288.539) 175.397,288.696 cw(c175.603,288.696) 175.603,288.902 cw(c175.603,288.747) 175.758,288.747 175.758,287.591 cw(c175.706,287.591) 175.706,287.539
  L14 (Sign) w0.08: 175.706,287.539 175.706,257.785 ccw(c176.949,257.785) 176.949,256.541 242.9,256.541 ccw(c242.9,257.321) 243.68,257.321 243.68,260.342 v11(243.782,260.445)
  L16 w0.081: v11(243.782,260.445) 243.782,261.082 C275.2@243.89,261.189
B223_Tx3C_to_B_P: C274.2 U1.P2 | length 104
  L14 (Sign) w0.076: v3(175.397,289.539) 175.397,289.383 ccw(c175.603,289.383) 175.603,289.177 cw(c175.603,288.747) 176.033,288.747 176.033,287.591 ccw(c176.085,287.591) 176.085,287.539
  L14 (Sign) w0.08: 176.085,287.539 176.085,257.785 ccw(c176.949,257.785) 176.949,256.921 242.9,256.921 ccw(c242.9,257.321) 243.3,257.321 243.3,260.342 v11(243.197,260.445)
  L16 w0.081: C274.2@243.09,261.189 243.197,261.082 v11(243.197,260.445)
B224_Rx0_N: J1_PCIE2.21 U1.P5 | length 153.1
  L12 (Sign) w0.073: v3(175.397,292.539) cw(c175.797,292.539) 175.797,292.939 176.478,292.939 cw(c176.478,292.633) 176.784,292.633 176.784,287.539 176.784,284.293 ccw(c177.228,284.293) 177.228,283.849 211.544,283.849 ccw(c211.544,284.582) 212.277,284.582 212.277,357.895 cw(c214.351,357.895) 214.351,359.969 219.706,359.969 ccw(c219.706,361.023) 220.76,361.023 cw(c221.611,361.023) 221.611,361.874 239.712,361.874 cw(c239.712,361.008) 240.578,361.008 240.578,360.619 cw(c240.386,360.619) v11(240.386,360.426)
  L16 w0.081: J1_PCIE2.21@240.29,358.792 240.29,359.725 cw(c240.397,359.725) 240.397,359.832 240.397,360.426 v11(240.386,360.426)
B224_Rx0_P: J1_PCIE2.19 U1.P6 | length 153.4
  L12 (Sign) w0.073: v3(175.397,293.539) ccw(c175.797,293.539) 175.797,293.139 176.478,293.139 cw(c176.478,292.633) 176.984,292.633 176.984,287.539 176.984,284.293 ccw(c177.228,284.293) 177.228,284.048 211.544,284.048 ccw(c211.544,284.582) 212.077,284.582 212.077,357.895 cw(c214.351,357.895) 214.351,360.168 219.706,360.168 ccw(c219.706,361.023) 220.561,361.023 cw(c221.611,361.023) 221.611,362.073 239.712,362.073 cw(c239.712,361.008) 240.778,361.008 240.778,360.619 ccw(c240.971,360.619) v11(240.971,360.426)
  L16 w0.081: v11(240.971,360.426) 240.971,360.312 240.982,360.312 240.982,359.832 cw(c240.982,359.725) 241.09,359.725 J1_PCIE2.19@241.09,358.792
B224_Rx1_N: J1_PCIE2.27 U1.M5 | length 153.6
  L12 (Sign) w0.073: v3(173.397,292.539) cw(c173.797,292.539) 173.797,292.939 174.497,292.939 cw(c174.497,292.659) 174.777,292.659 174.777,288.09 ccw(c175.209,288.09) 175.209,287.658 175.713,287.658 cw(c175.713,287.539) 175.832,287.539 175.832,283.607 ccw(c176.327,283.607) 176.327,283.112 212.865,283.112 ccw(c212.865,283.909) 213.661,283.909 213.661,357.26 cw(c214.541,357.26) 214.541,358.14 221.624,358.14 ccw(c221.624,359.169) 222.653,359.169 222.653,360.867 cw(c223.037,360.867) 223.037,361.251 237.924,361.251 cw(c237.924,361.01) 238.165,361.01 238.165,360.644 cw(c237.973,360.644) v11(237.973,360.451)
  L16 w0.081: J1_PCIE2.27@237.89,358.792 237.89,359.725 cw(c237.997,359.725) 237.997,359.832 237.997,360.427 ccw(c237.973,360.427) v11(237.973,360.451)
B224_Rx1_P: J1_PCIE2.25 U1.M6 | length 153.9
  L12 (Sign) w0.073: v3(173.397,293.539) ccw(c173.797,293.539) 173.797,293.139 174.497,293.139 cw(c174.497,292.659) 174.977,292.659 174.977,288.09 ccw(c175.209,288.09) 175.209,287.858 175.713,287.858 cw(c175.713,287.539) 176.031,287.539 176.031,283.607 ccw(c176.327,283.607) 176.327,283.312 212.865,283.312 ccw(c212.865,283.909) 213.462,283.909 213.462,357.26 cw(c214.541,357.26) 214.541,358.34 221.624,358.34 ccw(c221.624,359.169) 222.453,359.169 222.453,360.867 cw(c223.037,360.867) 223.037,361.451 237.924,361.451 cw(c237.924,361.01) 238.365,361.01 238.365,360.644 ccw(c238.558,360.644) v11(238.558,360.451)
  L16 w0.081: v11(238.558,360.451) 238.558,360.273 ccw(c238.582,360.273) 238.582,360.248 238.582,359.832 cw(c238.582,359.725) 238.69,359.725 J1_PCIE2.25@238.69,358.792
B224_Rx2_N: J1_PCIE3.21 U1.L3 | length 160.2
  L5 (Sign) w0.073: v1(154.445,306.14) cw(c154.645,306.14) 154.645,306.34 156.168,306.34 cw(c156.168,305.981) 156.528,305.981 156.528,292.57 ccw(c157.159,292.57) 157.159,291.939 161.397,291.939 171.599,291.938 cw(c171.599,291.719) 171.818,291.719 171.818,291.303 ccw(c172.161,291.303) 172.161,290.96 cw(c172.161,290.725) 172.397,290.725 v3(172.397,290.539)
  L12 (Sign) w0.073: v1(75.685,356.4) cw(c75.685,356.2) 75.885,356.2 75.885,355.841 ccw(c77.901,355.841) 77.901,353.826 141.834,353.826 cw(c141.834,351.286) 144.374,351.286 144.374,335.47 ccw(c147.113,335.47) 147.113,332.731 151.393,332.731 cw(c151.393,331.013) 153.111,331.013 153.111,307.191 ccw(c153.962,307.191) 153.962,306.34 154.244,306.34 cw(c154.244,306.14) v1(154.445,306.14)
  L16 w0.081: J1_PCIE3.21@75.585,358.792 75.585,357.859 ccw(c75.692,357.859) 75.692,357.751 75.692,356.4 v1(75.685,356.4)
B224_Rx2_P: J1_PCIE3.19 U1.L4 | length 159.8
  L5 (Sign) w0.073: v1(154.445,306.74) ccw(c154.645,306.74) 154.645,306.54 156.168,306.54 cw(c156.168,305.981) 156.727,305.981 156.727,292.57 ccw(c157.159,292.57) 157.159,292.138 161.397,292.138 171.599,292.138 cw(c171.599,291.719) 172.018,291.719 172.018,291.303 ccw(c172.161,291.303) 172.161,291.16 ccw(c172.161,291.396) 172.397,291.396 v3(172.397,291.539)
  L12 (Sign) w0.073: v1(76.285,356.4) ccw(c76.285,356.2) 76.084,356.2 76.084,355.841 ccw(c77.901,355.841) 77.901,354.025 141.834,354.025 cw(c141.834,351.286) 144.573,351.286 144.573,335.47 ccw(c147.113,335.47) 147.113,332.93 151.393,332.93 cw(c151.393,331.013) 153.311,331.013 153.311,307.191 ccw(c153.962,307.191) 153.962,306.54 154.244,306.54 ccw(c154.244,306.74) v1(154.445,306.74)
  L16 w0.081: v1(76.285,356.4) 76.277,356.4 76.277,357.751 ccw(c76.277,357.859) 76.385,357.859 J1_PCIE3.19@76.385,358.792
B224_Rx3_N: J1_PCIE3.27 U1.K5 | length 168.2
  L5 (Sign) w0.073: v1(154.862,307.762) cw(c155.062,307.762) 155.062,307.962 156.62,307.962 cw(c156.62,306.984) 157.598,306.984 157.598,293.599 ccw(c158.257,293.599) 158.257,292.94 161.397,292.94 171.247,292.939 cw(c171.247,292.789) 171.397,292.789 v3(171.397,292.539)
  L12 (Sign) w0.073: v1(78.237,362.522) cw(c78.237,362.321) 78.438,362.321 78.438,355.867 ccw(c78.996,355.867) 78.996,355.308 143.84,355.308 cw(c143.84,352.866) 146.282,352.866 146.282,335.47 ccw(c148.048,335.47) 148.048,333.705 153.039,333.705 cw(c153.039,332.778) 153.966,332.778 153.966,308.429 ccw(c154.432,308.429) 154.432,307.962 154.662,307.962 cw(c154.662,307.762) v1(154.862,307.762)
  L16 w0.081: J1_PCIE3.27@73.185,358.792 73.185,359.725 cw(c73.292,359.725) 73.292,359.832 73.292,361.111 cw(c74.068,361.111) 74.068,361.888 78.005,361.888 ccw(c78.005,362.128) 78.245,362.128 78.245,362.522 v1(78.237,362.522)
B224_Rx3_P: J1_PCIE3.25 U1.K6 | length 167.9
  L5 (Sign) w0.073: v1(154.862,308.362) ccw(c155.062,308.362) 155.062,308.162 156.62,308.162 cw(c156.62,306.984) 157.797,306.984 157.797,293.599 ccw(c158.257,293.599) 158.257,293.139 161.397,293.139 171.247,293.139 ccw(c171.247,293.289) 171.397,293.289 v3(171.397,293.539)
  L12 (Sign) w0.073: v1(78.837,362.522) ccw(c78.837,362.321) 78.637,362.321 78.637,355.867 ccw(c78.996,355.867) 78.996,355.507 143.84,355.507 cw(c143.84,352.866) 146.482,352.866 146.482,335.47 ccw(c148.048,335.47) 148.048,333.904 153.039,333.904 cw(c153.039,332.778) 154.165,332.778 154.165,308.429 ccw(c154.432,308.429) 154.432,308.162 154.662,308.162 ccw(c154.662,308.362) v1(154.862,308.362)
  L16 w0.081: J1_PCIE3.25@73.985,358.792 73.985,359.725 ccw(c73.877,359.725) 73.877,359.832 73.877,361.111 cw(c74.068,361.111) 74.068,361.302 78.005,361.302 ccw(c78.005,362.128) 78.83,362.128 78.83,362.522 v1(78.837,362.522)
B224_Tx0_to_C_N: C280.1 J1_PCIE2.26 | length 2.2
  L16 w0.081: J1_PCIE2.26@238.29,366.992 238.397,367.099 238.397,368.967 C280.1@238.29,369.075
B224_Tx0_to_C_P: C279.1 J1_PCIE2.24 | length 2.2
  L16 w0.081: J1_PCIE2.24@239.09,366.992 238.982,367.099 238.982,368.967 C279.1@239.09,369.075
B224_Tx0C_to_B_N: C280.2 U1.N3 | length 169.5
  L12 (Sign) w0.073: v3(174.397,290.539) 174.397,290.698 ccw(c174.155,290.698) 174.155,290.939 ccw(c174.155,290.774) 173.99,290.774 173.99,287.539 ccw(c174.332,287.539) 174.332,287.198 174.634,287.198 cw(c174.634,286.74) 175.091,286.74 175.091,282.464 ccw(c175.539,282.464) 175.539,282.016 213.373,282.016 ccw(c213.373,283.248) 214.605,283.248 214.605,356.464 cw(c215.697,356.464) 215.697,357.556 241.795,357.556 ccw(c241.795,358.635) 242.875,358.635 242.875,368.109 ccw(c242.16,368.109) 242.16,368.824 239.208,368.824 cw(c239.208,369.443) 238.59,369.443 238.59,370.177 ccw(c238.397,370.177) v11(238.397,370.37)
  L16 w0.081: C280.2@238.29,369.595 238.29,369.678 cw(c238.397,369.678) 238.397,369.785 v11(238.397,370.37)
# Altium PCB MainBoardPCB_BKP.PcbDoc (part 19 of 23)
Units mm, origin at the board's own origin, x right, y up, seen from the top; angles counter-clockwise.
Board outline 258.95 x 308.86 mm, 16 copper layers (L1, L2 (GND), L3 (Sign), L4 (GND), L5 (Sign), L6 (PWR/GND), L7(PWR/GND), L8 (Plane_GND), L9 (PWR/GND), L10 (PWR/GND), L11 (PWR/GND), L12 (Sign), L13 (GND), L14 (Sign), L15 (GND), L16), stack 2.502 mm thick; 2361 components, 1770 nets, 8410 pads, 3259 vias.
Unrouted connection lines stored in the file: 4700.

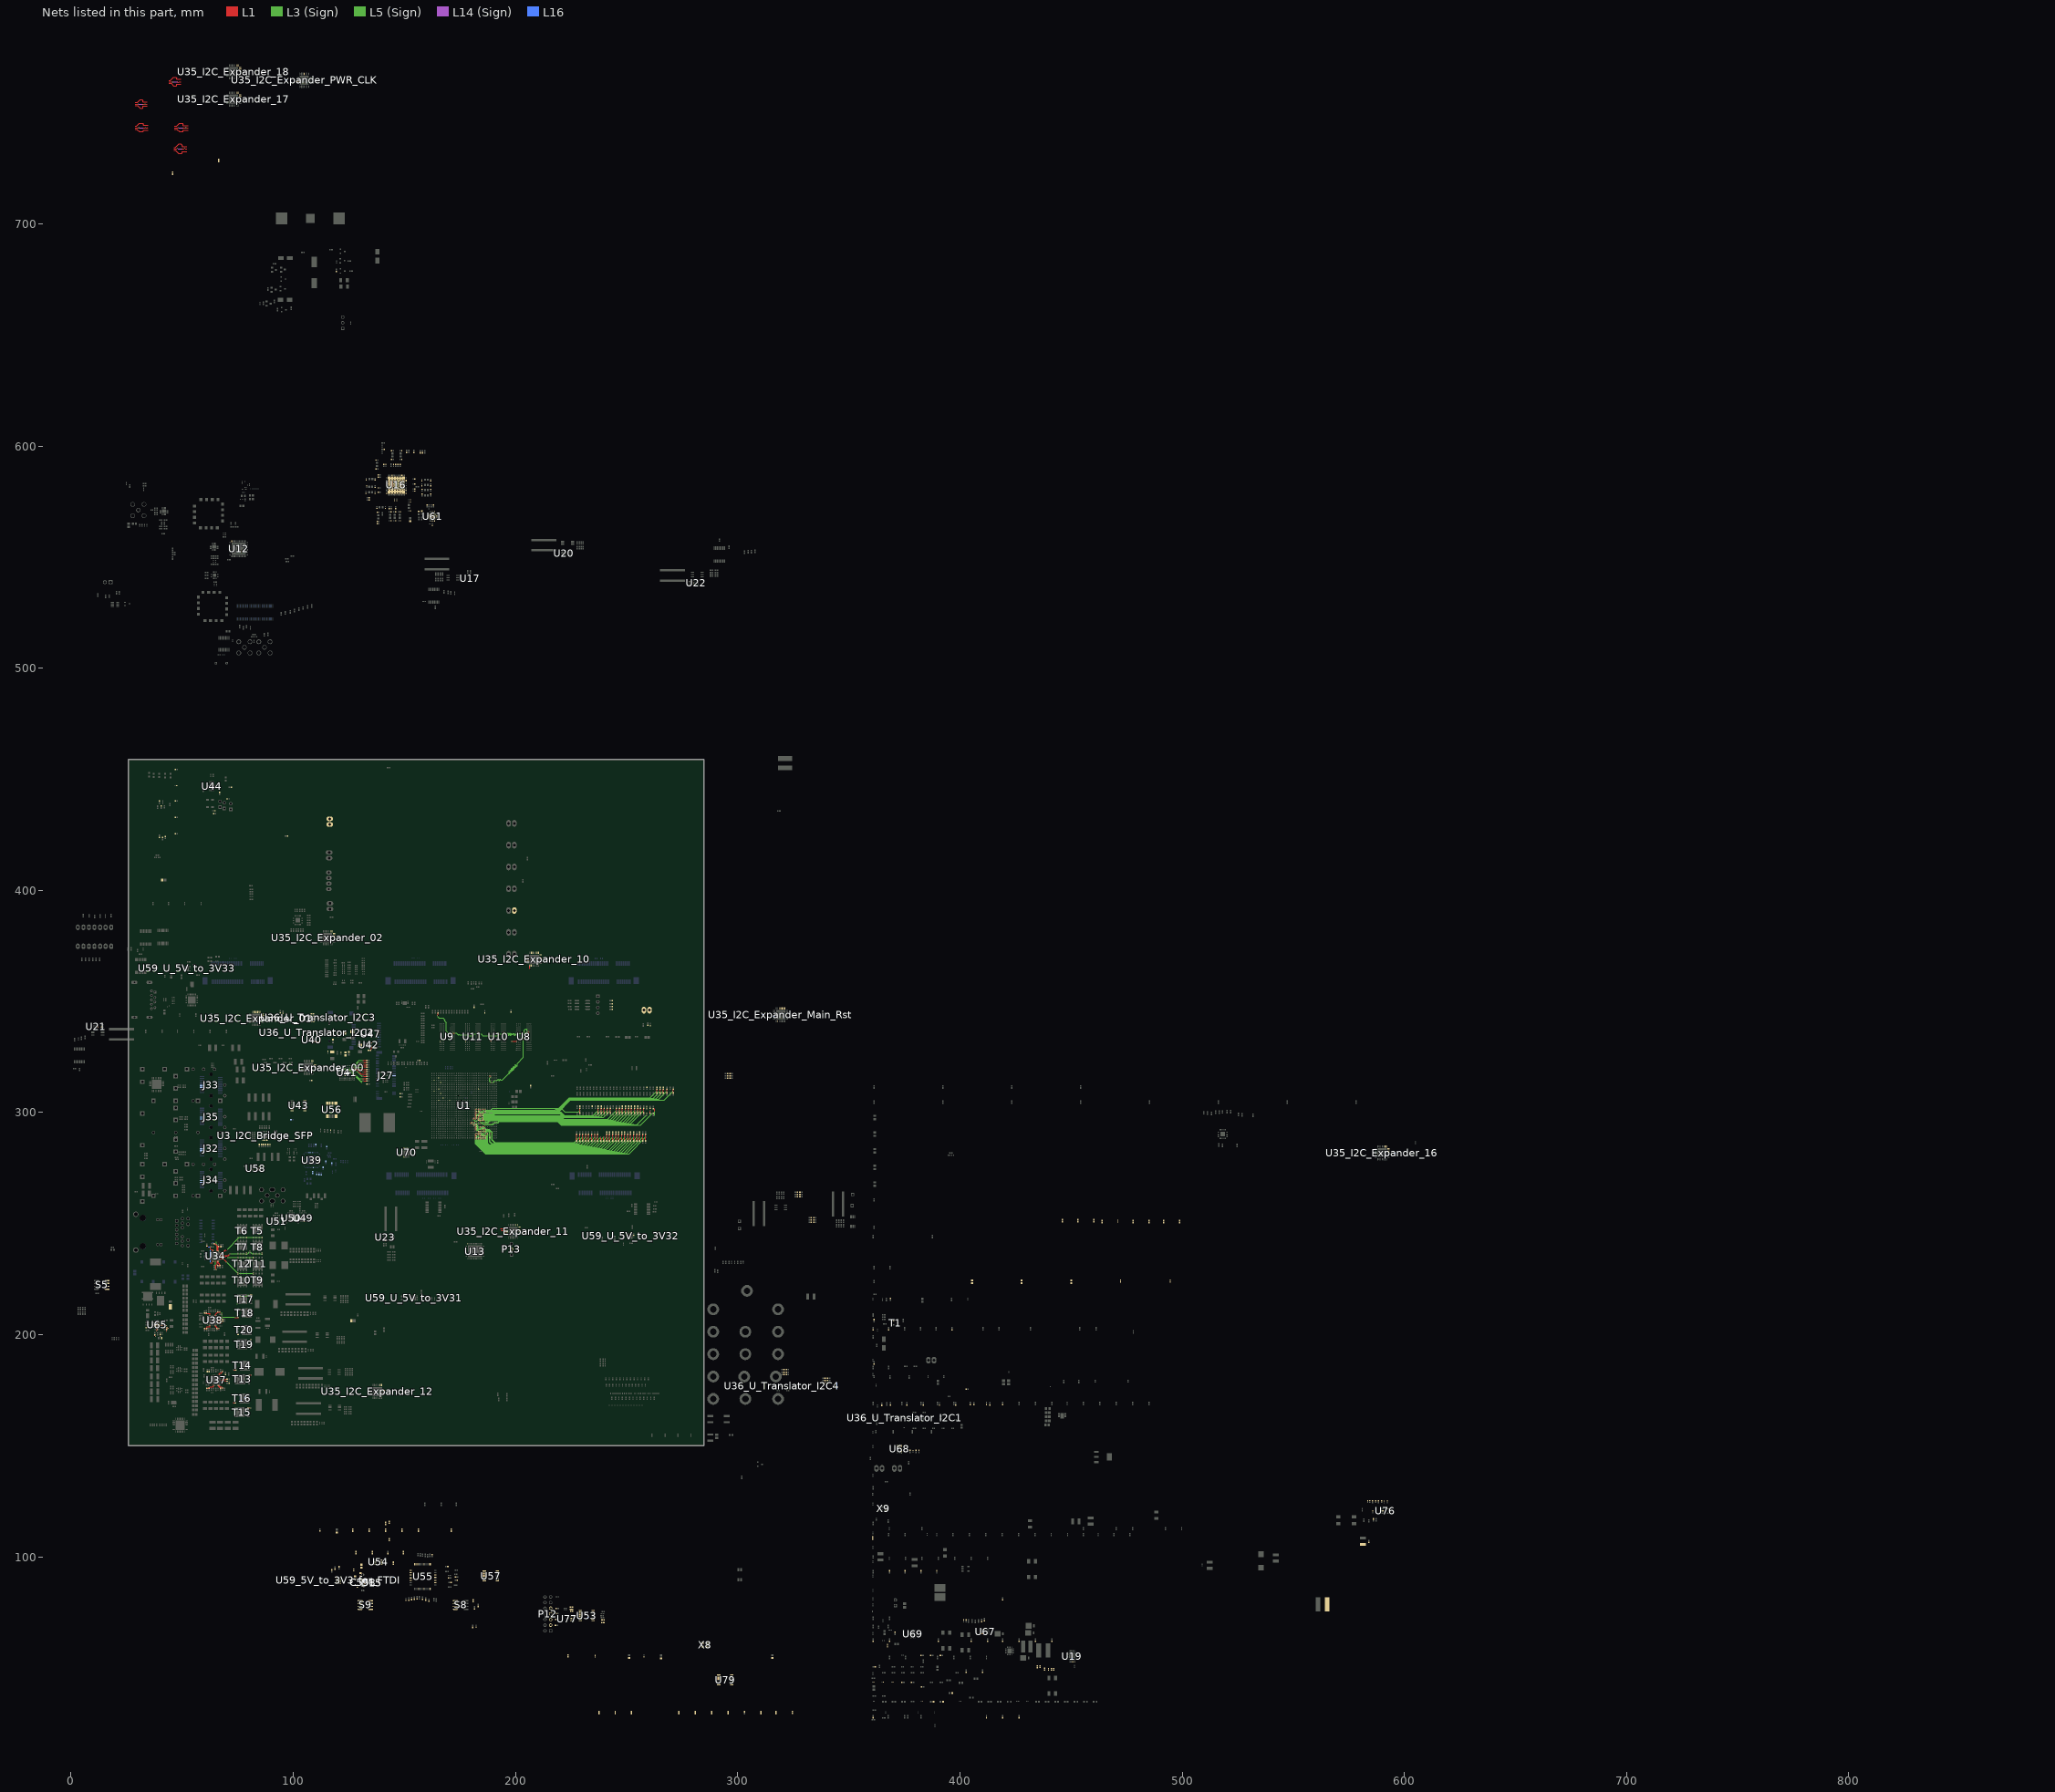
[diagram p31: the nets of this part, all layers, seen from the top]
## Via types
v1: diameter 0.5, hole 0.2, L1 to L16, tented both sides, 1212 vias
v2: diameter 0.5, hole 0.2, L1 to L16, 476 vias
v3: diameter 0.5/0.35/0.35/0.35/0.35/0.35/0.35/0.35/0.35/0.35/0.35/0.35/0.35/0.35/0.35/0.5 (per signal layer), hole 0.15, L1 to L16, tented both sides, 463 vias
v4: diameter 0.35/0/0.35 (per signal layer), hole 0.127, L1 to L3 (Sign), tented both sides, 282 vias
v5: diameter 0.5/0.35/0.35/0.35/0.35/0.35/0.35/0.35/0.35/0.35/0.35/0.35/0.35/0.35/0.35/0.5 (per signal layer), hole 0.2, L1 to L16, tented both sides, 222 vias
v6: diameter 0.8, hole 0.4, L1 to L16, tented both sides, 168 vias
v7: diameter 2.54, hole 1.02, L1 to L16, 113 vias
v8: diameter 1.4, hole 0.5, L1 to L16, tented both sides, 80 vias
v9: diameter 0.5/0/0.5 (per signal layer), hole 0.2, L14 (Sign) to L16, tented both sides, 52 vias
v10: diameter 0.35, hole 0.127, L1 to L2 (GND), tented both sides, 36 vias
v11: diameter 0.35, hole 0.127, L1 to L16, tented both sides, 16 vias
v12: diameter 0.4, hole 0.2, L1 to L16, 16 vias
v13: diameter 0.25, hole 0.2, L1 to L16, 16 vias
v14: diameter 0.3, hole 0.2, L1 to L16, 15 vias
v15: diameter 0.35/0/0.35 (per signal layer), hole 0.127, L1 to L3 (Sign), 12 vias
v16: diameter 0.45, hole 0.15, L1 to L16, 12 vias
v17: diameter 0.5/0.35/0.35/0.35/0.35/0.35/0.35/0.35/0.35/0.35/0.35/0.35/0.35/0.35/0.35/0.45 (per signal layer), hole 0.15, L1 to L16, tented both sides, 10 vias
v18: diameter 0.2/0/0.2 (per signal layer), hole 0.1, L1 to L3 (Sign), tented both sides, 9 vias
v19: diameter 0.4, hole 0.1, L1 to L16, 7 vias
v20: diameter 1.15, hole 1.15, L1 to L16, 6 vias
v21: diameter 1.65, hole 1.65, L1 to L16, 6 vias
v22: diameter 0.5, hole 0.2, L3 (Sign) to L6 (PWR/GND), tented both sides, 6 vias
v23: diameter 0.35/0/0.35 (per signal layer), hole 0.127, L14 (Sign) to L16, tented both sides, 5 vias
v24: diameter 0.2, hole 0.1, L1 to L16, 4 vias
v25: diameter 0.4, hole 0.2, L1 to L16, tented both sides, 2 vias
v26: diameter 0.4, hole 0.15, L1 to L16, 2 vias
v27: diameter 0.5/0.35/0.35/0.35/0.35/0.35/0.35/0.35/0.35/0.35/0.35/0.35/0.35/0.35/0.35/0.5 (per signal layer), hole 0.15, L1 to L16, 2 vias
v28: diameter 0.35, hole 0.127, L3 (Sign) to L6 (PWR/GND), tented both sides, 2 vias
v29: diameter 5.5, hole 3.5, L1 to L16, 1 vias
v30: diameter 0.5/0.35/0.35/0.35/0.35/0.35/0.35/0.35/0.35/0.35/0.35/0.35/0.35/0.35/0.35/0.5 (per signal layer), hole 0.2, L1 to L16, 1 vias
v31: diameter 0.35/0.35/0.35 (per signal layer), hole 0.127, L1 to L3 (Sign), tented both sides, 1 vias
v32: diameter 0.45/0/0.45 (per signal layer), hole 0.15, L1 to L3 (Sign), tented both sides, 1 vias
v33: diameter 0.45/0/0.45 (per signal layer), hole 0.2, L14 (Sign) to L16, tented both sides, 1 vias
v34: diameter 0.35, hole 0.127, L2 (GND) to L3 (Sign), 1 vias
v35: diameter 0.35, hole 0.127, L1 to L2 (GND), 1 vias

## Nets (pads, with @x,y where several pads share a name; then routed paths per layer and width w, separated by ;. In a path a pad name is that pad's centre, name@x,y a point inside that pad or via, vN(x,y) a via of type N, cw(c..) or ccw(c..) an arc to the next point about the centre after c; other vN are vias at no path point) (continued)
DDR4_WE: R55.1 U1.AG29 U8.L2 U9.L2 U10.L2 U11.L2 | length 108.5
  L1 w0.116: U9.L2@171.676,336.06 v3(172.079,335.657) ; U11.L2@183.136,336.06 v3(183.54,335.657) ; U1.AG29@188.397,316.539 188.811,316.125 v4(188.811,316.088) ; U10.L2@194.597,336.06 v3(195,335.657) ; v3(205.653,336.464) U8.L2@206.057,336.06
  L1 w0.155: v1(165.186,343.555) R55.1@165.186,344.8
  L5 (Sign) w0.092: 168.291,341.085 168.291,341.007 168.793,340.505 168.793,336.675 170.132,335.336 170.605,335.336 170.62,335.351 170.791,335.351 171.097,335.657 171.317,335.657 v3(172.079,335.657) 172.129,335.706 173.291,335.706 174.157,334.84 174.291,334.84 ccw(c174.291,334.93) 174.38,334.93 174.38,334.97 cw(c174.47,334.97) 174.47,335.06 174.739,335.06 cw(c174.739,334.97) 174.828,334.97 174.828,334.93 ccw(c174.918,334.93) 174.918,334.84 176.289,334.84 178.225,334.84 178.587,334.478 180.897,334.478 181.669,335.25 182.326,335.25 182.733,335.657 ; v3(205.653,336.464) 205.316,336.464 204.486,335.634 204.352,335.634 cw(c204.352,335.724) 204.262,335.724 204.262,335.829 ccw(c204.173,335.829) 204.173,335.919 203.904,335.919 ccw(c203.904,335.829) 203.814,335.829 203.814,335.724 cw(c203.725,335.724) 203.725,335.634 203.456,335.634 cw(c203.456,335.724) 203.367,335.724 203.367,335.75 ccw(c203.277,335.75) 203.277,335.839 203.008,335.839 ccw(c203.008,335.75) 202.919,335.75 202.919,335.724 cw(c202.829,335.724) 202.829,335.634 202.552,335.634 201.349,335.634 200.925,335.21 200.79,335.21 ccw(c200.79,335.12) 200.701,335.12 200.701,335.023 cw(c200.611,335.023) 200.611,334.933 200.342,334.933 cw(c200.342,335.023) 200.253,335.023 200.253,335.21 200.253,335.257 ccw(c200.163,335.257) 200.163,335.347 199.895,335.347 ccw(c199.895,335.257) 199.805,335.257 199.805,335.21 199.805,334.893 cw(c199.715,334.893) 199.715,334.803 199.447,334.803 cw(c199.447,334.893) 199.357,334.893 199.357,335.21 199.357,335.257 ccw(c199.268,335.257) 199.268,335.347 198.999,335.347 ccw(c198.999,335.257) 198.909,335.257 cw(c198.862,335.257) 198.862,335.21 198.509,335.21 cw(c198.509,335.257) 198.462,335.257 ccw(c198.372,335.257) 198.372,335.347 198.103,335.347 ccw(c198.103,335.257) 198.014,335.257 198.014,335.209 198.014,334.893 cw(c197.924,334.893) 197.924,334.803 197.656,334.803 cw(c197.656,334.893) 197.566,334.893 197.566,335.209 197.566,335.526 ccw(c197.476,335.526) 197.476,335.616 197.208,335.616 ccw(c197.208,335.526) 197.118,335.526 197.118,335.209 197.118,334.893 cw(c197.029,334.893) 197.029,334.803 196.76,334.803 cw(c196.76,334.893) 196.67,334.893 196.67,335.209 196.67,335.526 ccw(c196.581,335.526) 196.581,335.616 196.312,335.616 ccw(c196.312,335.526) 196.223,335.526 196.223,335.299 cw(c196.133,335.299) 196.133,335.209 195.783,335.209 195.721,335.209 195.274,335.657 v3(195,335.657) 194.193,335.657 193.797,335.26 192.558,335.26 191.777,334.48 188.561,334.48 188.457,334.48 ccw(c188.457,334.411) 188.387,334.411 cw(c188.318,334.411) 188.318,334.341 188.111,334.341 cw(c188.111,334.411) 188.041,334.411 188.041,334.48 188.041,334.707 ccw(c187.972,334.707) 187.972,334.776 187.764,334.776 ccw(c187.764,334.707) 187.695,334.707 187.695,334.549 cw(c187.626,334.549) 187.626,334.48 186.969,334.48 185.344,334.48 184.556,335.267 184.187,335.267 183.798,335.657 v3(183.54,335.657) ; 182.733,335.657 v3(183.54,335.657) ; 182.733,335.657 v3(183.54,335.657)
  L5 (Sign) w0.151: v1(165.186,343.555) 165.186,342.893 165.535,342.544 167.348,342.544 168.291,341.601 168.291,341.085
  L3 (Sign) w0.092: v4(188.811,316.088) 188.92,316.088 188.563,315.731 188.563,315.57 188.335,315.341 188.335,314.327 188.397,314.264 188.397,314.06 188.826,313.631 190.119,313.631 190.33,313.842 190.33,314.212 190.592,314.473 191.534,314.473 191.651,314.59 191.872,314.59 191.971,314.59 ccw(c191.971,314.689) 192.07,314.689 cw(c192.169,314.689) 192.169,314.788 192.368,314.788 cw(c192.368,314.689) 192.467,314.689 192.467,314.59 ccw(c192.566,314.59) 192.566,314.491 192.765,314.491 ccw(c192.765,314.59) 192.864,314.59 192.864,314.697 cw(c192.963,314.697) 192.963,314.796 193.162,314.796 cw(c193.162,314.697) 193.261,314.697 193.261,314.689 ccw(c193.36,314.689) 193.36,314.59 193.789,314.59 194.01,314.59 ; 194.009,314.591 196.884,317.466 196.995,317.576 cw(c197.065,317.506) 197.135,317.576 197.133,317.579 ; 197.132,317.579 ccw(c197.203,317.649) 197.273,317.579 197.413,317.719 ccw(c197.343,317.79) 197.413,317.86 197.345,317.927 196.991,318.281 cw(c197.062,318.352) 196.991,318.422 197.132,318.562 cw(c197.202,318.492) 197.272,318.562 197.626,318.208 197.694,318.14 ccw(c197.764,318.211) 197.834,318.14 197.975,318.281 ccw(c197.904,318.351) 197.975,318.421 197.907,318.489 197.553,318.843 cw(c197.623,318.913) 197.553,318.983 197.693,319.124 cw(c197.763,319.053) 197.834,319.124 198.188,318.77 198.255,318.702 ccw(c198.325,318.772) 198.396,318.702 198.536,318.842 ccw(c198.466,318.912) 198.536,318.983 198.468,319.05 198.114,319.404 cw(c198.184,319.475) 198.114,319.545 198.255,319.685 cw(c198.325,319.615) 198.395,319.685 198.749,319.331 198.817,319.263 ccw(c198.887,319.333) 198.957,319.263 199.097,319.404 ccw(c199.027,319.474) 199.097,319.544 199.03,319.612 198.676,319.966 cw(c198.746,320.036) 198.676,320.106 198.816,320.247 cw(c198.886,320.176) 198.956,320.247 199.311,319.892 199.376,319.827 ccw(c199.446,319.897) 199.516,319.827 199.656,319.968 ccw(c199.586,320.038) 199.656,320.108 199.591,320.173 199.237,320.527 cw(c199.307,320.597) 199.237,320.668 199.377,320.808 cw(c199.448,320.738) 199.518,320.808 199.872,320.454 199.937,320.389 ccw(c200.007,320.459) 200.078,320.389 200.218,320.529 ccw(c200.148,320.599) 200.218,320.669 200.153,320.735 199.799,321.089 cw(c199.869,321.159) 199.799,321.229 199.939,321.369 cw(c200.009,321.299) 200.079,321.369 200.433,321.015 200.504,320.945 ccw(c200.574,321.015) 200.644,320.945 200.784,321.085 ccw(c200.714,321.156) 200.784,321.226 cw(c200.855,321.296) 200.784,321.366 200.855,321.436 200.855,322.107 203.626,324.879 203.626,335.895 203.898,336.168 203.898,336.931 203.91,336.942 203.91,336.947 204.419,337.456 204.423,337.456 204.635,337.668 205.034,337.668 205.263,337.439 205.263,336.855 v3(205.653,336.464)
DDR4_ZQ: R920.1 U1.AB23
DDR4_ZQ_1: R61.1 U8.F6 | length 2.2
  L1 w0.254: v1(198.343,331.916) 198.475,332.048 200.445,332.048 U8.F6@200.457,332.06
DDR4_ZQ_2: R62.1 U10.F6 | length 0.6
  L1 w0.25: v3(188.593,332.464) U10.F6@188.997,332.06
DDR4_ZQ_3: R63.1 U9.F6
DDR4_ZQ_4: R64.1 U11.F6
DEVSLP: J27.38
DH1: T5.4 T6.4 U34.23 | length 21.5
  L1 w0.254: U34.23@67.322,236.639 67.949,236.639 69.436,238.125 v4(70.117,238.125) ; T5.4@85.882,243.723 v4(85.882,243.755)
  L3 (Sign) w0.254: v4(70.117,238.125) 75.714,243.723 v4(78.882,243.723) 78.914,243.755 v4(85.882,243.755)
DH1_1: T13.4 U37.23 | length 1.1
  L1 w0.5: T13.4@80.042,181.813 v1(81.129,181.813)
DH1_2: T17.4 U38.23 | length 13.5
  L1 w0.254: U38.23@65.953,207.714 67.479,207.714 v4(67.796,208.031) ; v4(80.18,217.889) T17.4@80.998,217.889
  L3 (Sign) w0.254: v4(67.796,208.031) 67.796,210.036 ; 74.923,213.696 74.923,216.666 75.567,217.31 79.083,217.31 79.662,217.889 v4(80.18,217.889)
DH2: T9.4 T10.4 U34.18 | length 17.5
  L1 w0.254: U34.18@67.322,234.139 67.324,234.137 68.428,234.137 v4(69.863,232.702) ; v4(82.067,227.505) T9.4@82.072,227.501
  L3 (Sign) w0.254: v4(69.863,232.702) 75.064,227.501 v4(75.078,227.501) 75.082,227.505 v4(82.067,227.505)
DH2_1: T15.4 U37.18 | length 1.1
  L1 w0.5: T15.4@79.789,167.011 v1(80.876,167.011)
DH2_2: T19.4 U38.18 | length 1.9
  L1 w0.254: U38.18@65.953,205.214 67.536,205.214 67.744,205.006
DL1: R275.2 T7.4 T8.4 U34.21 | length 19.6
  L1 w0.254: U34.21@67.322,235.639 70.805,235.639 v4(71.387,236.22) ; v4(85.869,236.489) T8.4@85.882,236.489
  L3 (Sign) w0.254: v4(71.387,236.22) 71.655,236.489 v4(78.867,236.489) 79.613,236.489 v4(80.488,237.364) 81.363,236.489 v4(85.869,236.489)
DL1_1: R292.2 T14.4 U37.21 | length 3.6
  L1 w0.254: U37.21@67.675,179.817 68.726,179.817 68.825,179.915 R292.2@70.161,179.915
  L1 w0.5: v1(73.127,184.15) T14.4@74.214,184.15
DL1_2: R629.2 T18.4 U38.21 | length 10.5
  L1 w0.254: U38.21@65.953,206.714 66.916,206.714 67.166,206.964 R629.2@68.206,206.964 ; v4(73.85,207.802) 73.855,207.797 T18.4@75.173,207.797
  L3 (Sign) w0.254: v4(67.43,206.951) 68.28,207.802 v4(73.85,207.802)
DL2: R280.2 T11.4 T12.4 U34.20 | length 15.8
  L1 w0.254: U34.20@67.322,235.139 69.941,235.139 v4(70.129,234.95)
  L3 (Sign) w0.254: v4(70.129,234.95) 70.316,234.764 v4(75.072,234.764) v4(82.072,234.764) ; v4(80.488,233.889) 80.488,234.764
DL2_1: R299.2 T16.4 U37.20 | length 3.7
  L1 w0.254: U37.20@67.675,179.317 69.396,179.317 69.646,179.067 R299.2@70.211,179.067
  L1 w0.5: v1(72.923,169.38) T16.4@74.01,169.38
DL2_2: R317.2 T20.4 U38.20 | length 2.3
  L1 w0.254: U38.20@65.953,206.214 66.991,206.214 67.166,206.039 68.212,206.039 R317.2@68.206,206.039
eMMC_clk: R112.2 U41.M6 | length 13.8
  L1 w0.098: v4(131.416,314.211) 133.103,314.211 R112.2@133.116,314.223
  L3 (Sign) w0.098: v18(121.938,318.591) 122.886,319.54 125.022,319.54 130.352,314.211 v4(131.416,314.211)
eMMC_cmd: R111.2 U41.M5 | length 13.3
  L1 w0.098: v4(131.407,315.214) R111.2@133.116,315.214
  L3 (Sign) w0.098: v18(121.938,319.091) 122.157,319.091 122.804,319.738 125.104,319.738 129.629,315.214 v4(131.407,315.214)
eMMC_data0: R105.2 U41.A3 | length 6.2
  L1 w0.098: v4(131.407,321.335) R105.2@133.116,321.335
  L3 (Sign) w0.098: v18(127.438,320.091) 128.682,321.335 v4(131.407,321.335)
eMMC_data1: R107.2 U41.A4 | length 5.8
  L1 w0.098: U41.A4@127.438,319.591 130.833,319.591 131.121,319.303 R107.2@133.116,319.303
eMMC_data2: R108.2 U41.A5 | length 6.4
  L1 w0.098: U41.A5@127.438,319.091 128.558,319.091 130.378,317.271 R108.2@133.116,317.271
eMMC_data3: R110.2 U41.B2 | length 7.3
  L1 w0.098: v32(131.416,323.367) R110.2@133.116,323.367
  L3 (Sign) w0.098: v18(126.938,320.591) 129.714,323.367 v32(131.416,323.367)
eMMC_data4: R101.2 U41.B3 | length 7.1
  L1 w0.098: v18(126.929,320.091) U41.B3@126.938,320.091 ; v4(131.407,322.351) R101.2@133.116,322.351
  L3 (Sign) w0.098: v18(126.929,320.091) 128.897,322.059 128.905,322.059 129.197,322.351 v4(131.407,322.351)
eMMC_data5: R102.2 U41.B4 | length 6.6
  L1 w0.098: v4(131.407,320.319) 131.466,320.319 131.665,320.518 132.917,320.518 R102.2@133.116,320.319
  L3 (Sign) w0.098: v18(126.938,319.591) 127.478,319.591 128.207,320.319 v4(131.407,320.319)
eMMC_data6: R103.2 U41.B5 | length 6.5
  L1 w0.098: v4(131.407,318.287) R103.2@133.116,318.287
  L3 (Sign) w0.098: v18(126.938,319.091) 130.427,319.091 131.231,318.287 v4(131.407,318.287)
eMMC_data7: R104.2 U41.B6 | length 7.1
  L1 w0.098: v4(131.416,316.255) R104.2@133.116,316.255
  L3 (Sign) w0.098: v18(126.938,318.591) 128.563,318.591 130.899,316.255 v4(131.416,316.255)
eMMC_PG1: R340.1 U35_I2C_Expander_11.26 U40.5 | length 5.7
  L1 w0.2: U40.5@109.512,331.771 111.571,331.771 112.037,332.237 R340.1@112.037,332.287 ; 193.626,246.96 194.644,246.96 195.844,245.76 U35_I2C_Expander_11.26@196.064,245.76
eMMC_PG2: R343.1 R345.2 U35_I2C_Expander_11.25 U42.5 | length 7.2
  L1 w0.2: R343.1@134.727,328.019 134.777,328.019 135.276,328.517 U42.5@135.276,329.46 136.554,329.46 R345.2@136.729,329.285 136.729,329.235 137.029,328.935 137.111,328.935 ; 193.176,247.718 194.536,247.718 195.844,246.41 U35_I2C_Expander_11.25@196.064,246.41
eMMC_rst: R99.1 R797.1 U41.K5 | length 10.4
  L1 w0.254: U41.K5@122.938,319.091 v18(122.949,319.091)
  L3 (Sign) w0.098: v18(122.949,319.091) 123.199,319.341 124.94,319.341 130.638,313.643 130.831,313.643
eMMC_Vcc: C517.2 C518.2 C523.2 C586.2 FB25.1 R339.2 R340.2 U40.8 U41.E6 U41.F5 U41.J10 U41.K9
eMMC_VccQ: C519.2 C520.2 C524.2 C587.2 FB25.2 R342.2 R343.2 U41.C6 U41.M4 U41.N4 U41.P3 U41.P5 U42.8
eMMC_Vddim: C521.2 C522.2 U41.C2
EN1: U35_I2C_Expander_PWR_CLK.26 U61.20
EN1_TPS: R277.2 R278.2 U34.14 U34.27 U70.20 | length 21.1
  L1 w0.254: R278.2@64.339,240.856 64.783,240.856 65.822,239.817 U34.27@65.822,237.639 ; v4(65.39,229.317) 65.295,229.412 65.295,231.213 65.815,231.733 65.815,232.984 65.82,232.989 65.82,233.137 U34.14@65.822,233.139
  L3 (Sign) w0.254: v4(65.39,229.317) 65.1,229.607 65.1,237.122 65.822,237.843 65.822,240.309 65.39,240.741 65.39,241.677
EN2: U35_I2C_Expander_PWR_CLK.27 U61.6
EN2_TPS: R745.1 U70.6 U70.17
EN_0.85V_REG1: S5.8 U34.1 U34.8
En_0V85@2A: R296.2 R435.2 U37.14 | length 1.9
  L1 w0.254: U37.14@66.175,177.317 66.177,177.315 66.177,176.889 66.836,176.23 66.841,176.23 67.204,175.867 R296.2@67.204,175.817
EN_1V0@1.5A: R634.1 U51.3 U68.4
EN_1V8@1.5A: R633.1 U50.3 U68.5
EN_2V5@1.5A: R632.1 U49.3 U68.6
EN_3V3V_REG0: S5.6 U37.1
EN_5V_REG0: S5.7 U38.8
EN_12@8A: S5.5 U38.1
EN_Detect: R655.2 U35_I2C_Expander_00.26
EN_PS_LTC6952_1: U35_I2C_Expander_PWR_CLK.18 U59_U_5V_to_3V33.3
EN_PS_LTC6952_2: U35_I2C_Expander_PWR_CLK.22 U59_U_5V_to_3V32.3
EN_PS_LTC6952_3: U35_I2C_Expander_PWR_CLK.24 U59_U_5V_to_3V31.3
En_PWRSwitch_PCIE0: U17.A2 U35_I2C_Expander_10.19
En_PWRSwitch_PCIE1: U20.A2 U35_I2C_Expander_10.2
En_PWRSwitch_PCIE2: U21.A2 U35_I2C_Expander_10.17
En_PWRSwitch_PCIE3: U22.A2 U35_I2C_Expander_10.20
En_PWRSwitch_PCIE4: U23.A2 U35_I2C_Expander_10.1 | length 2
  L1 w0.2: U23.A2@141.573,242.742 141.579,242.736 141.579,242.204 141.591,242.192 ; U35_I2C_Expander_10.1@206.48,366.065 206.48,364.914 206.701,364.693 v15(206.701,364.689)
EN_SEQ_LT3504: R646.2 U67.3 U69.5
EN_VSUP_1V2: C626.2 R309.1 U19.12
EN_VSUP_1V8: C625.2 R308.1 U19.15
EN_VSUP_3V3: C624.2 R305.1 U19.14
Enable_CLK: U12.40 U13.40 U35_I2C_Expander_Main_Rst.2
ETH_VDDIO: C491.2 C492.2 C493.2 C494.2 C495.2 C496.2 C497.2 C498.2 C531.1 C547.2 C612.2 C613.2 C614.2 C615.2 C742.1 C743.2 C790.2 L17.2 R83.2 R84.2 R85.2 R86.2 R97.2 R98.2 R99.2 R106.1 R123.2 R216.1 R319.2 R320.2 R322.2 R323.2 R333.1 R336.1 R337.1 R338.1 R346.1 R347.1 R348.1 R349.2 R350.2 R351.2 R352.2 R353.1 R354.2 R355.1 R356.1 R357.2 R367.2 R368.2 R369.2 R370.2 R371.2 R372.2 R381.2 R382.2 R709.1 R710.2 R715.2 R716.2 R717.2 R718.2 R719.2 R737.2 R911.1 U1.B22 U1.B27 U1.D18 U1.D23 U1.D28 U1.E21 U1.E26 U1.F19 U1.J18 U1.N20 U1.P18 U36_U_Translator_I2C2.2 U39.19 U39.30 U39.41 U43.1 U43.2 U43.7 U43.8 U43.15 U43.16 U44.1 U47.B3 U53.15 U56.15 U57.15 U68.3 U76.5
  other v5: 175.397,305.539 174.397,307.539
EXPANDER_RESET: J21.2 P13.2 R811.1 R1003.2 T1.1
FB1/FB2: R271.1 R273.2 U34.10 U34.31 | length 12.3
  L1 w0.254: R271.1@61.041,239.87 61.041,239.82 v26(61.441,239.42) ; v19(62.82,232.364) 63.543,232.364 63.82,232.64 63.82,233.137 U34.10@63.822,233.139 ; R273.2@62.939,239.52 62.822,239.403 v19(62.822,238.22) 62.831,238.229 63.571,238.229 63.82,237.981 63.82,237.641 U34.31@63.822,237.639
  L16 w0.254: v26(61.441,239.42) 62.674,239.42 62.774,239.52 v26(62.814,239.52) ; v19(62.82,232.364) 62.821,232.365 v19(62.822,238.22) v19(62.822,238.22)
FB1_1: R287.1 R290.2 U37.31
FB1_2: R626.1 R627.2 U38.31 | length 3.3
  L1 w0.254: R626.1@59.997,209.711 60.008,209.722 60.932,209.722 R627.2@60.944,209.733 61.102,209.575 62.252,209.575 62.453,209.374 U38.31@62.453,208.714
FB2_1: R297.1 R300.2 U37.10 | length 4.1
  L1 w0.254: R300.2@61.068,175.851 R297.1@62.14,175.851 62.14,176.257 62.455,176.572 63.749,176.572 64.175,176.997 U37.10@64.175,177.317
FB2_2: R315.1 R318.2 U38.10 | length 3.5
  L1 w0.254: R318.2@60.114,202.723 R315.1@61.041,202.723 61.041,203.148 61.384,203.491 62.28,203.491 62.453,203.664 U38.10@62.453,204.214
Flag_PWRSwitch_PCIE0: R618.2 U17.A3
Flag_PWRSwitch_PCIE1: R688.2 U20.A3
Flag_PWRSwitch_PCIE2: R744.2 U21.A3
Flag_PWRSwitch_PCIE3: R767.2 U22.A3
Flag_PWRSwitch_PCIE4: R819.2 U23.A3
FTD_DS_Dir1: R411.2 R412.2 U56.1
FTD_DS_Dir2: R413.2 R414.2 U56.2
FTD_DS_Dir3: R415.2 R416.2 U56.7
FTD_DS_Dir4: R418.2 R421.2 U56.8
FTD_JTAG_Dir1: R402.2 R403.2 U53.1
FTD_JTAG_Dir2: R404.2 R405.2 U53.2
FTD_JTAG_Dir3: R406.2 R407.2 U53.7
FTD_JTAG_Dir4: R408.2 R409.2 U53.8
FTD_U1_DIR1: R722.2 R723.2 U79.1
FTD_U1_DIR2: R724.2 R725.2 U79.2
FTD_U1_DIR3: R726.2 R727.2 U79.7
FTD_U1_DIR4: R728.2 R729.2 U79.8
FTD_U_DIR1: R636.2 R637.2 U57.1
FTD_U_DIR2: R638.2 R639.2 U57.2
FTD_U_DIR3: R640.2 R641.2 U57.7
FTD_U_DIR4: R642.2 R643.2 U57.8
FTDI_5V: C559.2 C560.2 C563_5V_to_3V3_for_FTDI.2 C564_5V_to_3V3_for_FTDI.2 FB31.1 U59_5V_to_3V3_for_FTDI.1 U59_5V_to_3V3_for_FTDI.2 U59_5V_to_3V3_for_FTDI.3
FTDI_DM: C558.2 D15.2 U55.7
FTDI_DP: C558.3 D15.1 U55.8
FTDI_EECLK: R417.2 U54.4 U55.62
FTDI_EECS: R420.2 U54.5 U55.63
FTDI_EED: R419.1 U54.3 U55.61
FTDI_GND: C559.1 C560.1 C563_5V_to_3V3_for_FTDI.1 C564_5V_to_3V3_for_FTDI.1 C565_5V_to_3V3_for_FTDI.1 C566_5V_to_3V3_for_FTDI.1 C567_5V_to_3V3_for_FTDI.1 C658.1 C659.1 C660.1 C661.1 C662.1 C663.1 C664.1 C665.1 C666.1 C667.1 C668.1 C669.1 C670.1 C671.1 C673.1 C791.1 FB32.1 R403.1 R405.1 R407.1 R409.1 R412.1 R414.1 R416.1 R421.1 R423.1 R432_5V_to_3V3_for_FTDI.1 R637.1 R639.1 R641.1 R643.1 R723.1 R725.1 R727.1 R729.1 S9.5 S9.6 S9.7 S9.8 U53.10 U54.2 U55.1 U55.5 U55.10 U55.11 U55.13 U55.15 U55.25 U55.35 U55.47 U55.51 U56.10 U57.10 U59_5V_to_3V3_for_FTDI.4 U59_5V_to_3V3_for_FTDI.9 U77.2 U79.10 X8.2 X8.4
  other v2: 119.68,88.921 120.68,88.921 119.68,89.921 120.68,89.921
FTDI_JTAG_ON: R1001.1 R1034.2
FTDI_JTAG_ON_1: R401.1 R1001.2 S8.1 S9.1 U35_I2C_Expander_01.17 U53.9
FTDI_JTAG_ON_2: R410.1 S8.2 S9.2 U35_I2C_Expander_01.18 U56.9
FTDI_JTAG_ON_3: R635.1 S8.3 S9.3 U35_I2C_Expander_01.19 U57.9
FTDI_JTAG_ON_4: R721.1 S8.4 S9.4 U35_I2C_Expander_01.20 U79.9
FTDI_LS_UART0_RXD: R1039.2 U79.4
FTDI_LS_UART0_TXD: R1038.2 U79.3
FTDI_LS_UART2_CTS_B: R1011.1 U55.41
FTDI_LS_UART2_RTS_B: R1010.1 U55.40
FTDI_LS_UART2_RXD: R1045.2 U57.6
FTDI_LS_UART2_TXD: R1044.2 U57.5
FTDI_LS_UART_RXD: R1047.2 U57.4
FTDI_LS_UART_TXD: R1046.2 U57.3
FTDI_PS_POR: R1036.2 U77.1
FTDI_PS_SRST+B: R1037.2 U77.3
FTDI_Sock_GND: C558.5 FB32.2
FTDI_TCK: P12.5 R732.1 R1030.2 U53.5 U56.5
FTDI_TDI: P12.9 R734.1 R1031.2 U53.3 U56.3
FTDI_TDO: P12.7 R733.1 R1032.2 U53.6 U56.6
FTDI_TMS: P12.3 R731.1 R1033.2 U53.4 U56.4
FTDI_VBUS: C558.1 FB31.2
FTDI_VCC1P8: C665.2 C666.2 C667.2 C673.2 U55.12 U55.37 U55.49 U55.64
FTDI_VccIO: C565_5V_to_3V3_for_FTDI.2 C566_5V_to_3V3_for_FTDI.2 C567_5V_to_3V3_for_FTDI.2 C658.2 C668.2 C669.2 C670.2 C671.2 C791.2 FB43.1 FB44.1 R401.2 R402.1 R404.1 R406.1 R408.1 R410.2 R411.1 R413.1 R415.1 R417.1 R418.1 R420.1 R422.2 R424.1 R430_5V_to_3V3_for_FTDI.2 R431_5V_to_3V3_for_FTDI.2 R635.2 R636.1 R638.1 R640.1 R642.1 R721.2 R722.1 R724.1 R726.1 R728.1 R1048.1 R1049.1 R1050.1 R1051.1 U53.16 U54.6 U55.20 U55.31 U55.42 U55.50 U55.56 U56.16 U57.16 U59_5V_to_3V3_for_FTDI.8 U77.5 U79.16
FTDI_X_IN: C663.2 U55.2 X8.1
FTDI_X_OUT: C664.2 U55.3 X8.3
GEM3_MDC: R815.1 U39.16
GEM3_MDIO: R333.2 R816.1 U39.17
GPIO_ETH_EXPANDER: R715.1 U35_I2C_Expander_11.27 U76.2
GPIO_Exp10_Adress0: R492.1 R493.1 U35_I2C_Expander_00.13 | length 6.5
  L1 w0.254: 28.866,754.573 29.85,754.573 31.1,755.823 31.958,755.823 32.35,755.431 32.35,754.947 34.201,754.947
GPIO_Exp10_Adress1: R494.1 R495.1 U35_I2C_Expander_00.12 | length 6.3
  L1 w0.254: 28.866,753.923 28.869,753.92 v2(30.185,753.92) ; 32.35,753.92 v2(33.331,753.92) 34.201,753.92
  L14 (Sign) w0.254: v2(30.185,753.92) v2(33.331,753.92)
GPIO_Exp10_Adress2: R496.1 R497.1 U35_I2C_Expander_00.11 | length 6.5
  L1 w0.254: 28.866,753.273 29.851,753.273 31.045,752.079 32.149,752.079 32.349,752.279 32.349,752.913 34.201,752.914
GPIO_Exp10_Int0: R871.2 U35_I2C_Expander_00.16
GPIO_Exp10_Int1: R872.2 U35_I2C_Expander_00.15
GPIO_Exp11_Adress0: R500.1 R501.1 U35_I2C_Expander_01.13 | length 7.3
  L1 w0.254: 46.225,734.318 46.966,734.318 47,734.284 48.609,735.893 49.467,735.893 49.948,735.412 49.948,734.884 50.059,734.774 52.054,734.774
GPIO_Exp11_Adress1: R502.1 R503.1 U35_I2C_Expander_01.12 | length 8
  L1 w0.254: 46.225,733.668 46.231,733.675 v2(47.851,733.675) ; v2@51.122,733.678 50.062,733.678 50.059,733.681 51.122,733.681 v2(51.124,733.679) ; v2@51.123,733.677 52.051,733.677 52.054,733.674
  L14 (Sign) w0.254: v2(47.851,733.675) 51.119,733.675 v2(51.124,733.679)
GPIO_Exp11_Adress2: R504.1 R505.1 U35_I2C_Expander_01.11 | length 7.2
  L1 w0.254: 46.225,733.018 47,733.018 48.406,731.612 49.806,731.612 50.059,731.865 50.059,732.575 50.062,732.578 51.301,732.578 51.304,732.581 52.054,732.581
GPIO_Exp11_Int0: R873.2 U35_I2C_Expander_01.16
GPIO_Exp11_Int1: R874.2 U35_I2C_Expander_01.15
GPIO_Exp12_Adress0: R508.1 R509.1 U35_I2C_Expander_02.13 | length 6.8
  L1 w0.254: 28.866,743.907 29.502,743.907 30.702,745.107 32.286,745.107 32.636,744.757 32.636,744.305 34.522,744.305 34.525,744.307
GPIO_Exp12_Adress1: R510.1 R511.1 U35_I2C_Expander_02.12 | length 6.6
  L1 w0.254: 28.866,743.257 v2(30.485,743.257) ; 32.636,743.257 32.669,743.224 v2(33.526,743.224) 33.544,743.242 34.507,743.242 34.525,743.26
  L14 (Sign) w0.254: v2(30.485,743.257) 30.518,743.224 v2(33.526,743.224)
GPIO_Exp12_Adress2: R512.1 R513.1 U35_I2C_Expander_02.11 | length 6.7
  L1 w0.254: 28.866,742.607 29.552,742.607 30.702,741.457 32.286,741.457 32.586,741.757 32.586,742.155 32.636,742.205 34.522,742.205 34.525,742.207
GPIO_Exp12_Int0: R875.2 U35_I2C_Expander_02.16
GPIO_Exp12_Int1: R876.2 U35_I2C_Expander_02.15
GPIO_Exp13_Adress0: R516.1 R517.1 U35_I2C_Expander_10.13 | length 7.2
  L1 w0.254: 46.512,743.907 47.563,743.907 48.763,745.107 50.142,745.107 50.501,744.748 50.501,744.257 52.592,744.257
GPIO_Exp13_Adress1: R518.1 R519.1 U35_I2C_Expander_10.12 | length 8.5
  L1 w0.254: 46.512,743.257 46.529,743.241 v2(48.3,743.241) ; 52.592,743.257 52.59,743.255 51.702,743.255 v2(51.7,743.253) ; v2(51.7,743.253) 50.512,743.253 50.5,743.241 50.508,743.249 51.696,743.249 v2(51.7,743.253)
  L14 (Sign) w0.254: v2(48.3,743.241) 48.312,743.253 v2(51.7,743.253)
GPIO_Exp13_Adress2: R520.1 R521.1 U35_I2C_Expander_10.11 | length 7.3
  L1 w0.254: 46.512,742.607 47.563,742.607 48.757,741.413 50.35,741.413 50.5,741.563 50.5,742.213 52.592,742.213
GPIO_Exp13_Int0: R877.2 U35_I2C_Expander_10.16
GPIO_Exp13_Int1: R878.2 U35_I2C_Expander_10.15
GPIO_Exp14_Adress0: R524.1 R525.1 U35_I2C_Expander_11.13 | length 6.3
  L1 w0.254: 44.163,764.504 44.747,764.504 46.118,765.874 47.178,765.874 47.527,765.526 47.527,765.119 47.598,765.048 49.317,765.048
GPIO_Exp14_Adress1: R526.1 R527.1 U35_I2C_Expander_11.12 | length 6
  L1 w0.254: 44.163,763.854 44.211,763.902 44.235,763.878 v2(45.665,763.878) ; 47.598,763.943 v2(48.377,763.943) 49.317,763.943
  L14 (Sign) w0.254: v2(45.665,763.878) 47.574,763.878 47.598,763.902 ; 47.582,763.943 v2(48.377,763.943)
GPIO_Exp14_Adress2: R528.1 R529.1 U35_I2C_Expander_11.11 | length 6.2
  L1 w0.254: 44.163,763.204 45.067,763.204 46.217,762.054 47.327,762.054 47.599,762.327 47.599,762.831 49.318,762.831
GPIO_Exp14_Int0: R879.2 U35_I2C_Expander_11.16
GPIO_Exp14_Int1: R880.2 U35_I2C_Expander_11.15
GPIO_Exp15_Adress0: R697.1 R698.1 U35_I2C_Expander_12.13
GPIO_Exp15_Adress1: R699.1 R700.1 U35_I2C_Expander_12.12
GPIO_Exp15_Adress2: R701.1 R702.1 U35_I2C_Expander_12.11
GPIO_Exp15_Int0: R881.2 U35_I2C_Expander_12.16
GPIO_Exp15_Int1: R882.2 U35_I2C_Expander_12.15
GPIO_Exp16_Adress0: R703.1 R704.1 U35_I2C_Expander_16.13
GPIO_Exp16_Adress1: R705.1 R706.1 U35_I2C_Expander_16.12
GPIO_Exp16_Adress2: R707.1 R708.1 U35_I2C_Expander_16.11
GPIO_Exp16_Int0: R961.2 U35_I2C_Expander_16.16
GPIO_Exp16_Int1: R962.2 U35_I2C_Expander_16.15
GPIO_Exp17_Adress0: R829.1 R830.1 U35_I2C_Expander_17.13
GPIO_Exp17_Adress1: R831.1 R832.1 U35_I2C_Expander_17.12
GPIO_Exp17_Adress2: R833.1 R834.1 U35_I2C_Expander_17.11
GPIO_Exp17_Int0: R963.2 U35_I2C_Expander_17.16
GPIO_Exp17_Int1: R964.2 U35_I2C_Expander_17.15
GPIO_Exp18_Adress0: R841.1 R842.1 U35_I2C_Expander_18.13
GPIO_Exp18_Adress1: R843.1 R844.1 U35_I2C_Expander_18.12
GPIO_Exp18_Adress2: R845.1 R846.1 U35_I2C_Expander_18.11
GPIO_Exp18_Int0: R965.2 U35_I2C_Expander_18.16
GPIO_Exp18_Int1: R966.2 U35_I2C_Expander_18.15
GPIO_Exp_Reset0: R746.1 U35_I2C_Expander_00.14 U35_I2C_Expander_01.14 U35_I2C_Expander_02.14 U35_I2C_Expander_Main_Rst.17
GPIO_Exp_Reset1: R747.1 U35_I2C_Expander_10.14 U35_I2C_Expander_11.14 U35_I2C_Expander_12.14 U35_I2C_Expander_Main_Rst.18
GPIO_Exp_Reset2: R748.1 U35_I2C_Expander_16.14 U35_I2C_Expander_17.14 U35_I2C_Expander_18.14 U35_I2C_Expander_Main_Rst.19
Ground: C63.2 C64.2 C67.2 C70.2 C75.2 C76.2 C77.2 C78.1 C79.1 C80.1 C81.2 C82.2 C83.2 C88.2 C89.2 C90.2 C91.2 C92.2 C93.2 C96.2 C99.1 C100.1 C101.1 C102.1 C103.1 C104.1 C105.1 C106.1 C107.1 C108.1 C109.1 C110.1 C124.1 C125.1 C126.1 C127.1 C141.1 C142.1 C143.1 C144.1 C145.1 C146.1 C147.1 C148.1 C162.1 C163.1 C164.1 C165.1 C179.1 C180.1 C572.1 C574.1 C575.1 C576.1 C578.1 C579.1 C590.1 C591.1 C592.1 FB36.2 R437.1 R439.1 R545.1 U16.44 U16.65 U61.3 U61.8 U61.13 U61.18 U61.21 X9.2
  other v2: 161.689,567.432 162.589,567.432 163.489,567.432 161.689,568.332 162.589,568.332 163.489,568.332 161.689,569.232 162.589,569.232 163.489,569.232 143.953,578.802 145.143,578.802 146.333,578.802 147.523,578.802 148.713,578.802 142.733,580.022 143.953,580.022 145.143,580.022 146.333,580.022 147.523,580.022 148.713,580.022 149.933,580.022 142.733,581.212 143.953,581.212 145.143,581.212 146.333,581.212 147.523,581.212 148.713,581.212 149.933,581.212 142.733,582.402 143.953,582.402 145.143,582.402 146.333,582.402 147.523,582.402 148.713,582.402 149.933,582.402 142.733,583.592 143.953,583.592 145.143,583.592 146.333,583.592 147.523,583.592 148.713,583.592 149.933,583.592 142.733,584.782 143.953,584.782 145.143,584.782 146.333,584.782 147.523,584.782 148.713,584.782 149.933,584.782 143.953,586.002 145.143,586.002 146.333,586.002 147.523,586.002 148.713,586.002
Ground_PWR_PoE: C702.1 C703.1 C704.1 D27.2 R159.1 R160.1 R667.1 R670.2 U65.3 U65.8 U65.21 | length 4.9
  L1 w0.254: v1(37.668,199.124) R670.2@37.668,199.938 ; v1(38.76,201.663) U65.3@38.76,202.478 ; v1(40.17,199.307) C702.1@40.17,200.121 ; U65.8@40.6,204.318 v1(41.478,204.318) ; v1(42.978,201.451) R667.1@42.978,202.265 ; R160.1@42.978,203.203 v1(43.793,203.203)
  other v2: 38.21,203.768 39.31,203.768 38.21,204.868 39.31,204.868
HW_Conf_05028: R128.1 R129.1 U16.64
I2C0Master_SCL: J12.1 R85.1 R774.1 U36_U_Translator_I2C3.3
I2C0Master_SDA: J12.2 R86.1 R775.1 U36_U_Translator_I2C3.4
I2C1Master_SCL: J13.1 R83.1 R772.1 U36_U_Translator_I2C2.3
I2C1Master_SDA: J13.2 R84.1 R773.1 U36_U_Translator_I2C2.4
I2C_05028_SCL: R130.2 R132.1 U16.36
I2C_05028_SDA: R131.2 R134.1 U16.35
I2C_SCL_SFP0: J32.5 R559_I2C_Bridge_SFP.1 U3_I2C_Bridge_SFP.2
I2C_SCL_SFP1: J33.5 R227_I2C_Bridge_SFP.1 U3_I2C_Bridge_SFP.4
I2C_SCL_SFP2: J34.5 R225_I2C_Bridge_SFP.1 U3_I2C_Bridge_SFP.6
I2C_SCL_SFP3: J35.5 R223_I2C_Bridge_SFP.1 U3_I2C_Bridge_SFP.8
I2C_SDA_SFP0: J32.4 R560_I2C_Bridge_SFP.1 U3_I2C_Bridge_SFP.1
I2C_SDA_SFP1: J33.4 R558_I2C_Bridge_SFP.1 U3_I2C_Bridge_SFP.3
I2C_SDA_SFP2: J34.4 R226_I2C_Bridge_SFP.1 U3_I2C_Bridge_SFP.5
I2C_SDA_SFP3: J35.4 R224_I2C_Bridge_SFP.1 U3_I2C_Bridge_SFP.7
I2CFPGA_Master_SCL: R363.2 U1.AG1 U36_U_Translator_I2C1.3 U36_U_Translator_I2C4.3
I2CFPGA_Master_SDA: R364.2 U1.AF3 U36_U_Translator_I2C1.4 U36_U_Translator_I2C4.4 | length 0.7
  L1 w0.116: v4(186.909,290.052) U1.AF3@187.397,290.539
ILIM1: C345.2 R610.1 U34.26 | length 3.2
  L1 w0.254: U34.26@66.321,237.64 C345.2@66.32,239.69 66.38,239.63 67.318,239.63 R610.1@67.378,239.57
ILIM1_1: C389.2 R619.1 U37.26 | length 2.5
  L1 w0.254: U37.26@66.675,181.817 66.675,182.331 67.04,182.696 67.474,182.696 C389.2@68.211,183.433
ILIM1_2: C430.2 R625.2 U38.26 | length 3
  L1 w0.254: U38.26@64.953,208.714 64.953,209.219 65.973,210.239 66.991,210.239 R625.2@67.001,210.229
ILIM2: C349.2 R611.1 U34.15 | length 3.5
  L1 w0.254: C349.2@66.055,231.087 66.075,231.067 R611.1@67.093,231.067 ; U34.15@66.322,233.139 66.322,232.29 66.315,232.283 66.94,231.658 66.94,231.22 R611.1@67.093,231.067 ; R611.1@67.113,231.047 R611.1@67.093,231.067
ILIM2_1: C393.2 R620.1 U37.15 | length 2.6
  L1 w0.254: U37.15@66.675,177.317 66.675,176.892 66.983,176.584 67.861,176.584 68.185,176.26 C393.2@68.185,175.817
ILIM2_2: C434.2 R302.2 U38.15 | length 2.6
  L1 w0.254: U38.15@64.953,204.214 64.955,204.212 64.955,203.839 65.578,203.216 C434.2@65.578,202.764 66.405,202.764 66.453,202.812 R302.2@66.453,202.813
IMU_INT1: R822.2 U58.4
IMU_INT2: R851.2 U58.9
InSel_05028_00: U16.20 U35_I2C_Expander_10.23
InSel_05028_01: U16.17 U35_I2C_Expander_10.24
InSel_05028_10: U16.28 U35_I2C_Expander_10.25
InSel_05028_11: U16.29 U35_I2C_Expander_10.26
INTA_EXP_MAIN: R972.2 U35_I2C_Expander_Main_Rst.16
INTB_EXP_MAIN: R973.2 U35_I2C_Expander_Main_Rst.15
Interrupt0: R515.2 R530.1 U1.AC12 | length 64.3
  L1 w0.116: v4(183.909,299.052) U1.AC12@184.397,299.539
  L1 w0.12: R515.2@242.686,299.747 v4(242.686,300.816) R530.1@242.686,301.885
  L3 (Sign) w0.12: v4(183.909,299.052) 184.231,299.052 184.566,299.387 185.092,299.387 185.665,298.814 190.286,298.814 190.571,299.099 190.574,299.099 190.574,299.191 190.771,299.387 191.048,299.387 191.063,299.372 219.918,299.372 221.576,297.714 239.584,297.714 v4(242.686,300.816)
Interrupt1: R522.2 R547.1 U1.AD12 | length 65.8
  L1 w0.116: v4(184.909,299.052) U1.AD12@185.397,299.539
  L1 w0.12: R522.2@245.413,299.747 v4(245.413,300.816) R547.1@245.413,301.885
  L3 (Sign) w0.12: v4(184.909,299.052) 184.962,299.052 185.187,298.827 185.304,298.827 185.537,298.594 191.055,298.594 191.057,298.597 192.397,298.597 220.071,298.597 221.739,296.929 241.526,296.929 v4(245.413,300.816)
Interrupt2: R531.2 R550.1 U1.AA12 | length 63.5
  L1 w0.116: v4(181.909,299.052) U1.AA12@182.397,299.539
  L1 w0.12: R531.2@239.96,299.747 v4(239.96,300.816) R550.1@239.96,301.885
  L3 (Sign) w0.12: v4(181.909,299.052) 183.125,299.052 183.9,299.827 185.275,299.827 185.278,299.823 185.291,299.823 185.86,299.255 189.976,299.255 190.26,299.539 190.3,299.539 190.588,299.827 191.23,299.827 191.246,299.812 220.1,299.812 221.759,298.154 237.298,298.154 v4(239.96,300.816)
Interrupt3: R548.2 R553.1 U1.AA11 | length 65.3
  L1 w0.116: v4(181.909,298.052) U1.AA11@182.397,298.539
  L1 w0.12: R548.2@241.323,299.747 v4(241.323,300.816) R553.1@241.323,301.885
  L3 (Sign) w0.12: v4(181.909,298.052) 182.436,298.052 183.991,299.607 185.183,299.607 185.187,299.603 185.2,299.603 185.769,299.034 190.195,299.034 190.354,299.193 190.354,299.282 190.68,299.607 191.139,299.607 191.155,299.592 220.009,299.592 221.667,297.934 238.441,297.934 v4(241.323,300.816)
Interrupt4: R551.2 R556.1 U1.AB11 | length 69.4
  L1 w0.116: v4(182.909,298.052) U1.AB11@183.397,298.539
  L1 w0.12: R551.2@246.776,299.747 v4(246.776,300.816) R556.1@246.776,301.885
  L3 (Sign) w0.12: v4(182.909,298.052) 183.464,298.607 185.213,298.607 185.446,298.374 191.146,298.374 191.149,298.377 192.397,298.377 219.98,298.377 221.648,296.709 242.669,296.709 v4(246.776,300.816)
Interrupt5: R554.2 R618.1 U1.AC11 | length 69.8
  L1 w0.116: v4(183.909,298.052) U1.AC11@184.397,298.539
  L1 w0.12: R554.2@248.14,299.747 v4(248.14,300.816) R618.1@248.14,301.885
  L3 (Sign) w0.12: v4(183.909,298.052) 184.244,298.387 185.122,298.387 185.355,298.154 191.237,298.154 191.24,298.157 192.397,298.157 219.889,298.157 221.557,296.489 243.813,296.489 v4(248.14,300.816)
Interrupt6: R557.2 R688.1 U1.AD11 | length 70
  L1 w0.116: v4(184.909,298.052) U1.AD11@185.397,298.539
  L1 w0.12: R557.2@249.503,299.747 v4(249.503,300.816) R688.1@249.503,301.885
  L3 (Sign) w0.12: v4(184.909,298.052) 184.953,298.008 185.19,298.008 185.263,297.934 191.328,297.934 191.331,297.937 192.397,297.937 219.798,297.937 221.465,296.269 244.956,296.269 v4(249.503,300.816)
Interrupt7: R659.2 R744.1 U1.AD10 | length 74.5
  L1 w0.116: v4(184.909,297.052) U1.AD10@185.397,297.539
  L1 w0.12: R659.2@253.593,299.747 v4(253.593,300.816) R744.1@253.593,301.885
  L3 (Sign) w0.12: v4(184.909,297.052) 187.895,297.052 188.11,297.267 191.594,297.267 191.604,297.277 192.397,297.277 219.524,297.277 221.192,295.609 248.386,295.609 v4(253.593,300.816)
Interrupt8: R661.2 R767.1 U1.AB10 | length 75.1
  L1 w0.116: v4(182.909,297.052) U1.AB10@183.397,297.539
  L1 w0.12: R661.2@252.23,299.747 v4(252.23,300.816) R767.1@252.23,301.885
  L3 (Sign) w0.12: v4(182.909,297.052) 184.2,297.052 184.556,297.409 187.808,297.409 187.886,297.487 191.503,297.487 191.513,297.497 192.397,297.497 219.615,297.497 221.283,295.829 247.243,295.829 v4(252.23,300.816)
Interrupt9: R663.2 R819.1 U1.AB9 | length 71.3
  L1 w0.116: U1.AB9@183.397,296.539 v4(183.884,296.052)
  L3 (Sign) w0.12: v4(183.884,296.052) 184.397,295.539 185.885,295.539 186.023,295.402 187.642,295.402 188.443,296.202 188.586,296.202 188.771,296.387 219.17,296.387 220.828,294.729 253.162,294.729
Interrupt10: R735.2 R822.1 U1.Y10 | length 80.7
  L1 w0.116: v4(180.909,297.052) U1.Y10@181.397,297.539
  L1 w0.12: R735.2@254.956,299.747 v4(254.956,300.816) R822.1@254.956,301.885
  L3 (Sign) w0.12: v4(180.909,297.052) 180.909,296.915 181.775,296.05 182.588,296.05 183.197,296.659 187.814,296.659 188.202,297.047 191.686,297.047 191.695,297.057 219.433,297.057 221.101,295.389 249.529,295.389 v4(254.956,300.816)
Interrupt11: R765.2 R851.1 U1.AA10 | length 74.7
  L1 w0.116: v4(181.909,297.052) U1.AA10@182.397,297.539
  L1 w0.12: R765.2@250.866,299.747 v4(250.866,300.816) R851.1@250.866,301.885
  L3 (Sign) w0.12: v4(181.909,297.052) 182.279,297.421 184.197,297.421 184.426,297.65 187.738,297.65 187.802,297.714 191.419,297.714 191.422,297.717 192.397,297.717 219.707,297.717 221.374,296.049 246.099,296.049 v4(250.866,300.816)
Interrupt12: R817.2 R854.1 U1.AC9 | length 77.6
  L1 w0.116: U1.AC9@184.397,296.539 v4(184.884,296.052)
  L1 w0.12: R817.2@256.32,299.747 v4(256.32,300.816) R854.1@256.32,301.885
  L3 (Sign) w0.12: v4(184.884,296.052) 185.145,296.052 185.481,296.389 187.854,296.389 188.293,296.827 191.777,296.827 191.786,296.837 219.342,296.837 221.01,295.169 250.673,295.169 v4(256.32,300.816)
Interrupt13: R820.2 R857.1 U1.AD9 | length 78.3
  L1 w0.116: U1.AD9@185.397,296.539 v4(185.884,296.052)
  L1 w0.12: R820.2@257.683,299.747 v4(257.683,300.816) R857.1@257.683,301.885
  L3 (Sign) w0.12: v4(185.884,296.052) 186.167,296.052 186.538,295.681 187.584,295.681 188.509,296.607 191.868,296.607 191.878,296.617 219.251,296.617 220.919,294.949 251.816,294.949 v4(257.683,300.816)
Interrupt14: R823.2 R860.1 U1.AC6 | length 54.7
  L1 w0.116: v4(183.909,293.052) U1.AC6@184.397,293.539
  L1 w0.12: R823.2@228.908,287.208 v4(228.908,288.874) R860.1@228.908,290.21
  L3 (Sign) w0.12: v4(183.909,293.052) 185.865,293.052 186.855,292.062 188.138,292.062 189.281,290.919 189.281,287.515 190.348,286.448 190.468,286.448 190.625,286.292 226.596,286.292 227.779,287.475 227.779,287.745 v4(228.908,288.874)
Interrupt15: R847.2 R862.1 U1.AD6 | length 80
  L1 w0.116: U1.AD6@185.397,293.539 v4(185.884,294.027)
  L3 (Sign) w0.12: v4(185.884,294.027) 186.354,294.497 189.748,294.497 190.666,295.415 192.176,295.415 192.684,295.923 219.012,295.923 220.645,294.289 256.227,294.289 261.537,299.599
Interrupt16: R849.2 R863.1 U1.W8 | length 58.6
  L1 w0.116: v4(179.909,295.052) U1.W8@180.397,295.539
  L1 w0.12: R849.2@227.559,287.208 v4(227.559,288.874) R863.1@227.559,290.21
  L3 (Sign) w0.12: v4(179.909,295.052) 180.436,295.052 180.873,294.615 182.423,294.615 183.515,293.522 185.814,293.522 186.931,292.405 188.227,292.405 189.509,291.122 189.509,287.719 190.716,286.512 226.504,286.512 227.559,287.566 v4(227.559,288.874)
Interrupt17: R852.2 R864.1 U1.Y8 | length 86.2
  L1 w0.116: v4(180.909,295.052) U1.Y8@181.397,295.539
  L1 w0.12: R852.2@260.604,299.693 v4(260.604,300.762) ; 262.602,300.686 262.602,301.756
  L3 (Sign) w0.12: v4(180.909,295.052) 185.123,295.052 185.464,294.711 186.257,294.711 186.263,294.717 189.657,294.717 190.575,295.635 192.084,295.635 192.614,296.164 219.081,296.164 220.736,294.509 254.72,294.509 259.046,298.835 ; 262.602,298.706 262.602,300.686
Interrupt18: R855.2 R865.1 U1.Y7 | length 60.7
  L1 w0.116: v4(180.909,294.052) U1.Y7@181.397,294.539
  L1 w0.12: R855.2@230.258,287.208 v4(230.258,288.874) R865.1@230.258,290.21
  L3 (Sign) w0.12: v4(180.909,294.052) 181.39,294.052 181.733,294.395 182.224,294.395 182.956,293.662 182.956,293.04 183.286,292.71 185.851,292.71 186.727,291.833 187.96,291.833 188.506,291.287 188.506,289.103 188.574,289.034 188.574,286.939 189.442,286.072 227.455,286.072 v4(230.258,288.874)
Interrupt19: R858.2 R866.1 U1.AA7 | length 62.2
  L1 w0.116: v4(181.909,294.052) U1.AA7@182.397,294.539
  L1 w0.12: R858.2@232.957,287.208 v4(232.957,288.874) R866.1@232.957,290.21
  L3 (Sign) w0.12: v4(181.909,294.052) 182.587,293.374 182.587,293.098 183.221,292.464 184.997,292.464 186.504,290.957 186.875,290.957 187.541,290.291 187.541,289.712 187.579,289.674 187.579,286.169 188.201,285.547 229.629,285.547 v4(232.957,288.874)
Interrupt20: R861.1 R867.1 U1.AD5 | length 61.4
  L1 w0.116: v4(184.909,292.052) U1.AD5@185.397,292.539
  L1 w0.12: R861.1@235.656,287.208 v4(235.656,288.874) R867.1@235.656,290.21
  L3 (Sign) w0.12: v4(184.909,292.052) 184.909,291.722 185.28,291.351 185.28,290.589 185.822,290.047 186.322,290.047 187.139,289.23 187.139,285.987 188.032,285.094 231.875,285.094 v4(235.656,288.874)
Interrupt21: R523.1 R868.1 U1.AE5 | length 56
  L1 w0.116: v4(185.909,292.052) U1.AE5@186.397,292.539
  L1 w0.12: R523.1@231.607,287.208 v4(231.607,288.874) R868.1@231.607,290.21
  L3 (Sign) w0.12: v4(185.909,292.052) 185.976,292.052 186.715,291.313 186.995,291.313 187.198,291.516 187.966,291.516 188.286,291.196 188.286,286.694 189.15,285.83 228.563,285.83 v4(231.607,288.874)
Interrupt22: R546.1 R869.1 U1.AD4 | length 62.1
  L1 w0.116: v4(184.909,291.052) U1.AD4@185.397,291.539
  L1 w0.12: R546.1@237.005,287.208 v4(237.005,288.874) R869.1@237.005,290.21
  L3 (Sign) w0.12: v4(184.909,291.052) 184.909,290.648 185.731,289.827 186.23,289.827 186.919,289.138 186.919,285.896 187.941,284.874 233.005,284.874 v4(237.005,288.874)
Interrupt23: R549.1 R870.1 U1.AE4 | length 58.3
  L1 w0.116: v4(185.909,291.052) U1.AE4@186.397,291.539
  L1 w0.12: R549.1@234.306,287.208 v4(234.306,288.874) R870.1@234.306,290.21
  L3 (Sign) w0.12: v4(185.909,291.052) 186.462,290.5 186.949,290.5 187.287,290.162 187.287,289.471 187.359,289.399 187.359,286.078 188.123,285.314 230.746,285.314 v4(234.306,288.874)
Interrupt24: R552.1 R871.1 U1.AB4 | length 81.5
  L1 w0.116: v4(182.909,291.052) U1.AB4@183.397,291.539
  L1 w0.12: R552.1@251.85,287.158 v4(251.85,288.824) R871.1@251.85,290.16
  L3 (Sign) w0.12: v4(182.909,291.052) 182.909,290.674 183.515,290.068 183.515,285.877 186.952,282.441 245.466,282.441 v4(251.85,288.824)
Interrupt25: R555.1 R872.1 U1.AC4 | length 70.8
  L1 w0.116: v4(183.909,291.052) U1.AC4@184.397,291.539
  L1 w0.12: R555.1@243.753,287.208 v4(243.753,288.874) R872.1@243.753,290.21
  L3 (Sign) w0.12: v4(183.909,291.052) 183.928,291.034 183.928,290.697 185.574,289.05 185.574,285.684 187.49,283.769 238.647,283.769 v4(243.753,288.874)
Interrupt26: R607.1 R873.1 U1.AA6 | length 66.2
  L1 w0.116: v4(181.909,293.052) U1.AA6@182.397,293.539
  L1 w0.12: R607.1@238.355,287.258 v4(238.355,288.924)
  L3 (Sign) w0.12: v4(181.909,293.052) 183.331,291.63 184.116,291.63 184.574,291.172 184.574,290.672 185.64,289.607 186.139,289.607 186.699,289.047 186.699,285.804 187.855,284.649 234.079,284.649 v4(238.355,288.924)
Interrupt27: R660.1 R874.1 U1.AA5 | length 67.3
  L1 w0.116: v4(181.909,292.052) U1.AA5@182.397,292.539
  L1 w0.12: R660.1@239.704,287.208 v4(239.704,288.874)
  L3 (Sign) w0.12: v4(181.909,292.052) 182.598,292.052 183.24,291.41 184.025,291.41 184.354,291.081 184.354,290.581 185.549,289.387 186.048,289.387 186.479,288.956 186.479,285.713 187.764,284.429 235.259,284.429 v4(239.704,288.874)
Interrupt28: R662.1 R875.1 U1.AD2 | length 70.1
  L1 w0.116: v4(184.909,289.052) U1.AD2@185.397,289.539
  L1 w0.12: R662.1@245.102,287.208 v4(245.102,288.874) R875.1@245.102,290.21
  L3 (Sign) w0.12: v4(184.909,289.052) 185.293,288.668 185.293,285.655 187.399,283.549 239.777,283.549 v4(245.102,288.874)
Interrupt29: R664.1 R876.1 U1.AE2 | length 64.6
  L1 w0.116: v4(185.909,289.052) U1.AE2@186.397,289.539
  L1 w0.12: R664.1@241.054,287.208 v4(241.054,288.874) R876.1@241.054,290.21
  L3 (Sign) w0.12: v4(185.909,289.052) 186.244,288.717 186.244,285.637 187.672,284.209 236.388,284.209 v4(241.054,288.874)
Interrupt30: R736.1 R877.1 U1.AD1 | length 70.8
  L1 w0.116: v4(184.909,288.052) U1.AD1@185.397,288.539
  L1 w0.12: R736.1@246.452,287.208 v4(246.452,288.874) R877.1@246.452,290.21
  L3 (Sign) w0.12: v4(184.909,288.052) 184.909,285.727 187.308,283.329 240.906,283.329 v4(246.452,288.874)
Interrupt31: R766.1 R878.1 U1.AE1 | length 65.3
  L1 w0.116: v4(185.909,288.052) U1.AE1@186.397,288.539
  L1 w0.12: R766.1@242.403,287.208 v4(242.403,288.874) R878.1@242.403,290.21
  L3 (Sign) w0.12: v4(185.909,288.052) 185.909,285.661 187.581,283.989 237.518,283.989 v4(242.403,288.874)
Interrupt32: R818.1 R879.1 U1.AC3 | length 75
  L1 w0.116: v4(183.909,290.052) U1.AC3@184.397,290.539
  L1 w0.12: R818.1@247.801,287.208 v4(247.801,288.874) R879.1@247.801,290.21
  L3 (Sign) w0.12: v4(183.909,290.052) 184.389,289.573 184.389,288.851 184.569,288.671 184.569,285.756 187.217,283.109 242.036,283.109 v4(247.801,288.874)
Interrupt33: R821.1 R880.1 U1.AC2 | length 75.7
  L1 w0.116: v4(183.909,289.052) U1.AC2@184.397,289.539
  L1 w0.12: R821.1@249.151,287.158 R821.1@249.151,287.208 v4(249.151,288.824) R880.1@249.151,290.16
  L3 (Sign) w0.12: v4(183.909,289.052) 183.909,288.785 184.266,288.428 184.266,285.749 187.126,282.889 243.215,282.889 v4(249.151,288.824)
Interrupt34: R824.1 R881.1 U1.AA3 | length 86.1
  L1 w0.116: v4(181.909,290.052) U1.AA3@182.397,290.539
  L1 w0.12: R824.1@255.898,287.208 v4(255.898,288.874) R881.1@255.898,290.21
  L3 (Sign) w0.12: v4(181.909,290.052) 181.909,289.692 182.55,289.052 182.55,285.909 186.678,281.781 248.805,281.781 v4(255.898,288.874)
Interrupt35: R848.1 R882.1 U1.AB3 | length 82.3
  L1 w0.116: v4(182.909,290.052) U1.AB3@183.397,290.539
  L1 w0.12: R848.1@253.199,287.208 v4(253.199,288.874) R882.1@253.199,290.21
  L3 (Sign) w0.12: v4(182.909,290.052) 182.909,289.797 183.248,289.458 183.248,285.833 186.86,282.221 246.546,282.221 v4(253.199,288.874)
Interrupt36: R850.1 R883.1 U1.AB1 | length 82
  L1 w0.116: v4(182.909,288.052) U1.AB1@183.397,288.539
  L1 w0.12: R850.1@254.549,287.208 v4(254.549,288.874) R883.1@254.549,290.21
  L3 (Sign) w0.12: v4(182.909,288.052) 182.909,285.86 186.769,282.001 247.675,282.001 v4(254.549,288.874)
Interrupt37: R853.1 R884.1 U1.AC1 | length 76.4
  L1 w0.116: v4(183.909,288.052) U1.AC1@184.397,288.539
  L1 w0.12: R853.1@250.5,287.158 R853.1@250.5,287.208 v4(250.5,288.824) R884.1@250.5,290.16
  L3 (Sign) w0.12: v4(183.909,288.052) 183.909,285.794 187.035,282.669 244.345,282.669 v4(250.5,288.824)
Interrupt38: R856.1 R885.1 U1.AA2 | length 86.8
  L1 w0.116: v4(181.909,289.052) U1.AA2@182.397,289.539
  L1 w0.12: R856.1@257.248,287.208 v4(257.248,288.874) R885.1@257.248,290.21
  L3 (Sign) w0.12: v4(181.909,289.052) 181.909,288.816 182.244,288.481 182.244,285.903 186.587,281.561 249.934,281.561 v4(257.248,288.874)
Interrupt39: R859.1 R886.1 U1.AA1 | length 87.5
  L1 w0.116: v4(181.909,288.052) U1.AA1@182.397,288.539
  L1 w0.12: R859.1@258.597,287.208 v4(258.597,288.874) R886.1@258.597,290.21
  L3 (Sign) w0.12: v4(181.909,288.052) 181.909,285.927 186.496,281.341 251.064,281.341 v4(258.597,288.874)
Interrupt40: R921.2 R961.1 U1.AA13 | length 51.7
  L1 w0.116: v4(181.909,300.052) U1.AA13@182.397,300.539
  L1 w0.12: R921.2@229.053,299.747 v4(229.053,300.816) R961.1@229.053,301.885
  L3 (Sign) w0.12: v4(181.909,300.052) 182.285,300.052 182.639,300.406 188.26,300.406 189.682,301.828 220.573,301.828 222.231,300.17 228.407,300.17 v4(229.053,300.816)
Interrupt41: R923.2 R962.1 U1.AB13 | length 60.7
  L1 w0.116: v4(182.909,300.052) U1.AB13@183.397,300.539
  L1 w0.12: R923.2@238.596,299.747 v4(238.596,300.816) R962.1@238.596,301.885
  L3 (Sign) w0.12: v4(182.909,300.052) 185.384,300.052 185.961,299.475 189.862,299.475 190.146,299.759 190.209,299.759 190.497,300.047 191.322,300.047 191.337,300.032 220.192,300.032 221.85,298.374 236.154,298.374 v4(238.596,300.816)
Interrupt42: R925.2 R963.1 U1.AE14 | length 83.7
  L1 w0.116: v5@185.909,301.052 U1.AE14@186.397,301.539
  L1 w0.12: R925.2@263.613,308.751 v1(263.613,309.607) R963.1@263.613,310.463
  L5 (Sign) w0.12: v5(185.904,301.057) 217.843,301.057 218.172,301.387 219.059,301.387 224.317,306.644 260.65,306.644 v1(263.613,309.607)
Interrupt43: R927.2 R964.1 U1.AE13 | length 56.2
  L1 w0.116: v4(185.909,300.052) U1.AE13@186.397,300.539
  L1 w0.12: R927.2@237.233,299.747 v4(237.233,300.816) R964.1@237.233,301.885
  L3 (Sign) w0.12: v4(185.909,300.052) 186.267,299.695 189.509,299.695 189.793,299.979 190.118,299.979 190.406,300.267 191.413,300.267 191.428,300.252 220.283,300.252 221.941,298.594 235.011,298.594 v4(237.233,300.816)
Interrupt44: R929.2 R965.1 U1.AC14 | length 89.3
  L1 w0.116: v5@183.909,301.052 U1.AC14@184.397,301.539
  L1 w0.12: R929.2@266.607,308.751 v1(266.607,309.607) R965.1@266.607,310.463
  L5 (Sign) w0.12: v5(183.904,301.057) 184.26,301.057 185.014,300.304 218.155,300.304 218.797,300.947 219.241,300.947 224.499,306.204 263.204,306.204 v1(266.607,309.607)
Interrupt45: R931.2 R966.1 U1.AD14 | length 86.5
  L1 w0.116: v5@184.909,301.052 U1.AD14@185.397,301.539
  L1 w0.12: R931.2@265.11,308.751 v1(265.11,309.607) R966.1@265.11,310.463
  L5 (Sign) w0.12: v5(184.904,301.057) 185.213,301.057 185.649,300.622 218.023,300.622 218.568,301.167 219.15,301.167 224.408,306.424 261.927,306.424 v1(265.11,309.607)
Interrupt46: R933.2 R967.1 U1.AA14 | length 96.5
  L1 w0.116: v5@181.909,301.052 U1.AA14@182.397,301.539
  L1 w0.12: R933.2@271.098,308.751 v1(271.098,309.607) R967.1@271.098,310.463
  L5 (Sign) w0.12: v5(181.904,301.057) 183.508,299.453 218.507,299.453 219.341,300.287 219.514,300.287 224.772,305.544 267.035,305.544 v1(271.098,309.607)
Interrupt47: R935.2 R968.1 U1.AB14 | length 92
  L1 w0.116: v5@182.909,301.052 U1.AB14@183.397,301.539
  L1 w0.12: R935.2@268.104,308.751 v1(268.104,309.607) R968.1@268.104,310.463
  L5 (Sign) w0.12: v5(182.904,301.057) 183.143,301.057 184.137,300.063 218.255,300.063 218.918,300.727 219.332,300.727 224.59,305.984 264.481,305.984 v1(268.104,309.607)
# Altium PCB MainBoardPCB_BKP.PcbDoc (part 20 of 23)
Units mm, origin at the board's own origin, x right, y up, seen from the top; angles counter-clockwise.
Board outline 258.95 x 308.86 mm, 16 copper layers (L1, L2 (GND), L3 (Sign), L4 (GND), L5 (Sign), L6 (PWR/GND), L7(PWR/GND), L8 (Plane_GND), L9 (PWR/GND), L10 (PWR/GND), L11 (PWR/GND), L12 (Sign), L13 (GND), L14 (Sign), L15 (GND), L16), stack 2.502 mm thick; 2361 components, 1770 nets, 8410 pads, 3259 vias.
Unrouted connection lines stored in the file: 4700.

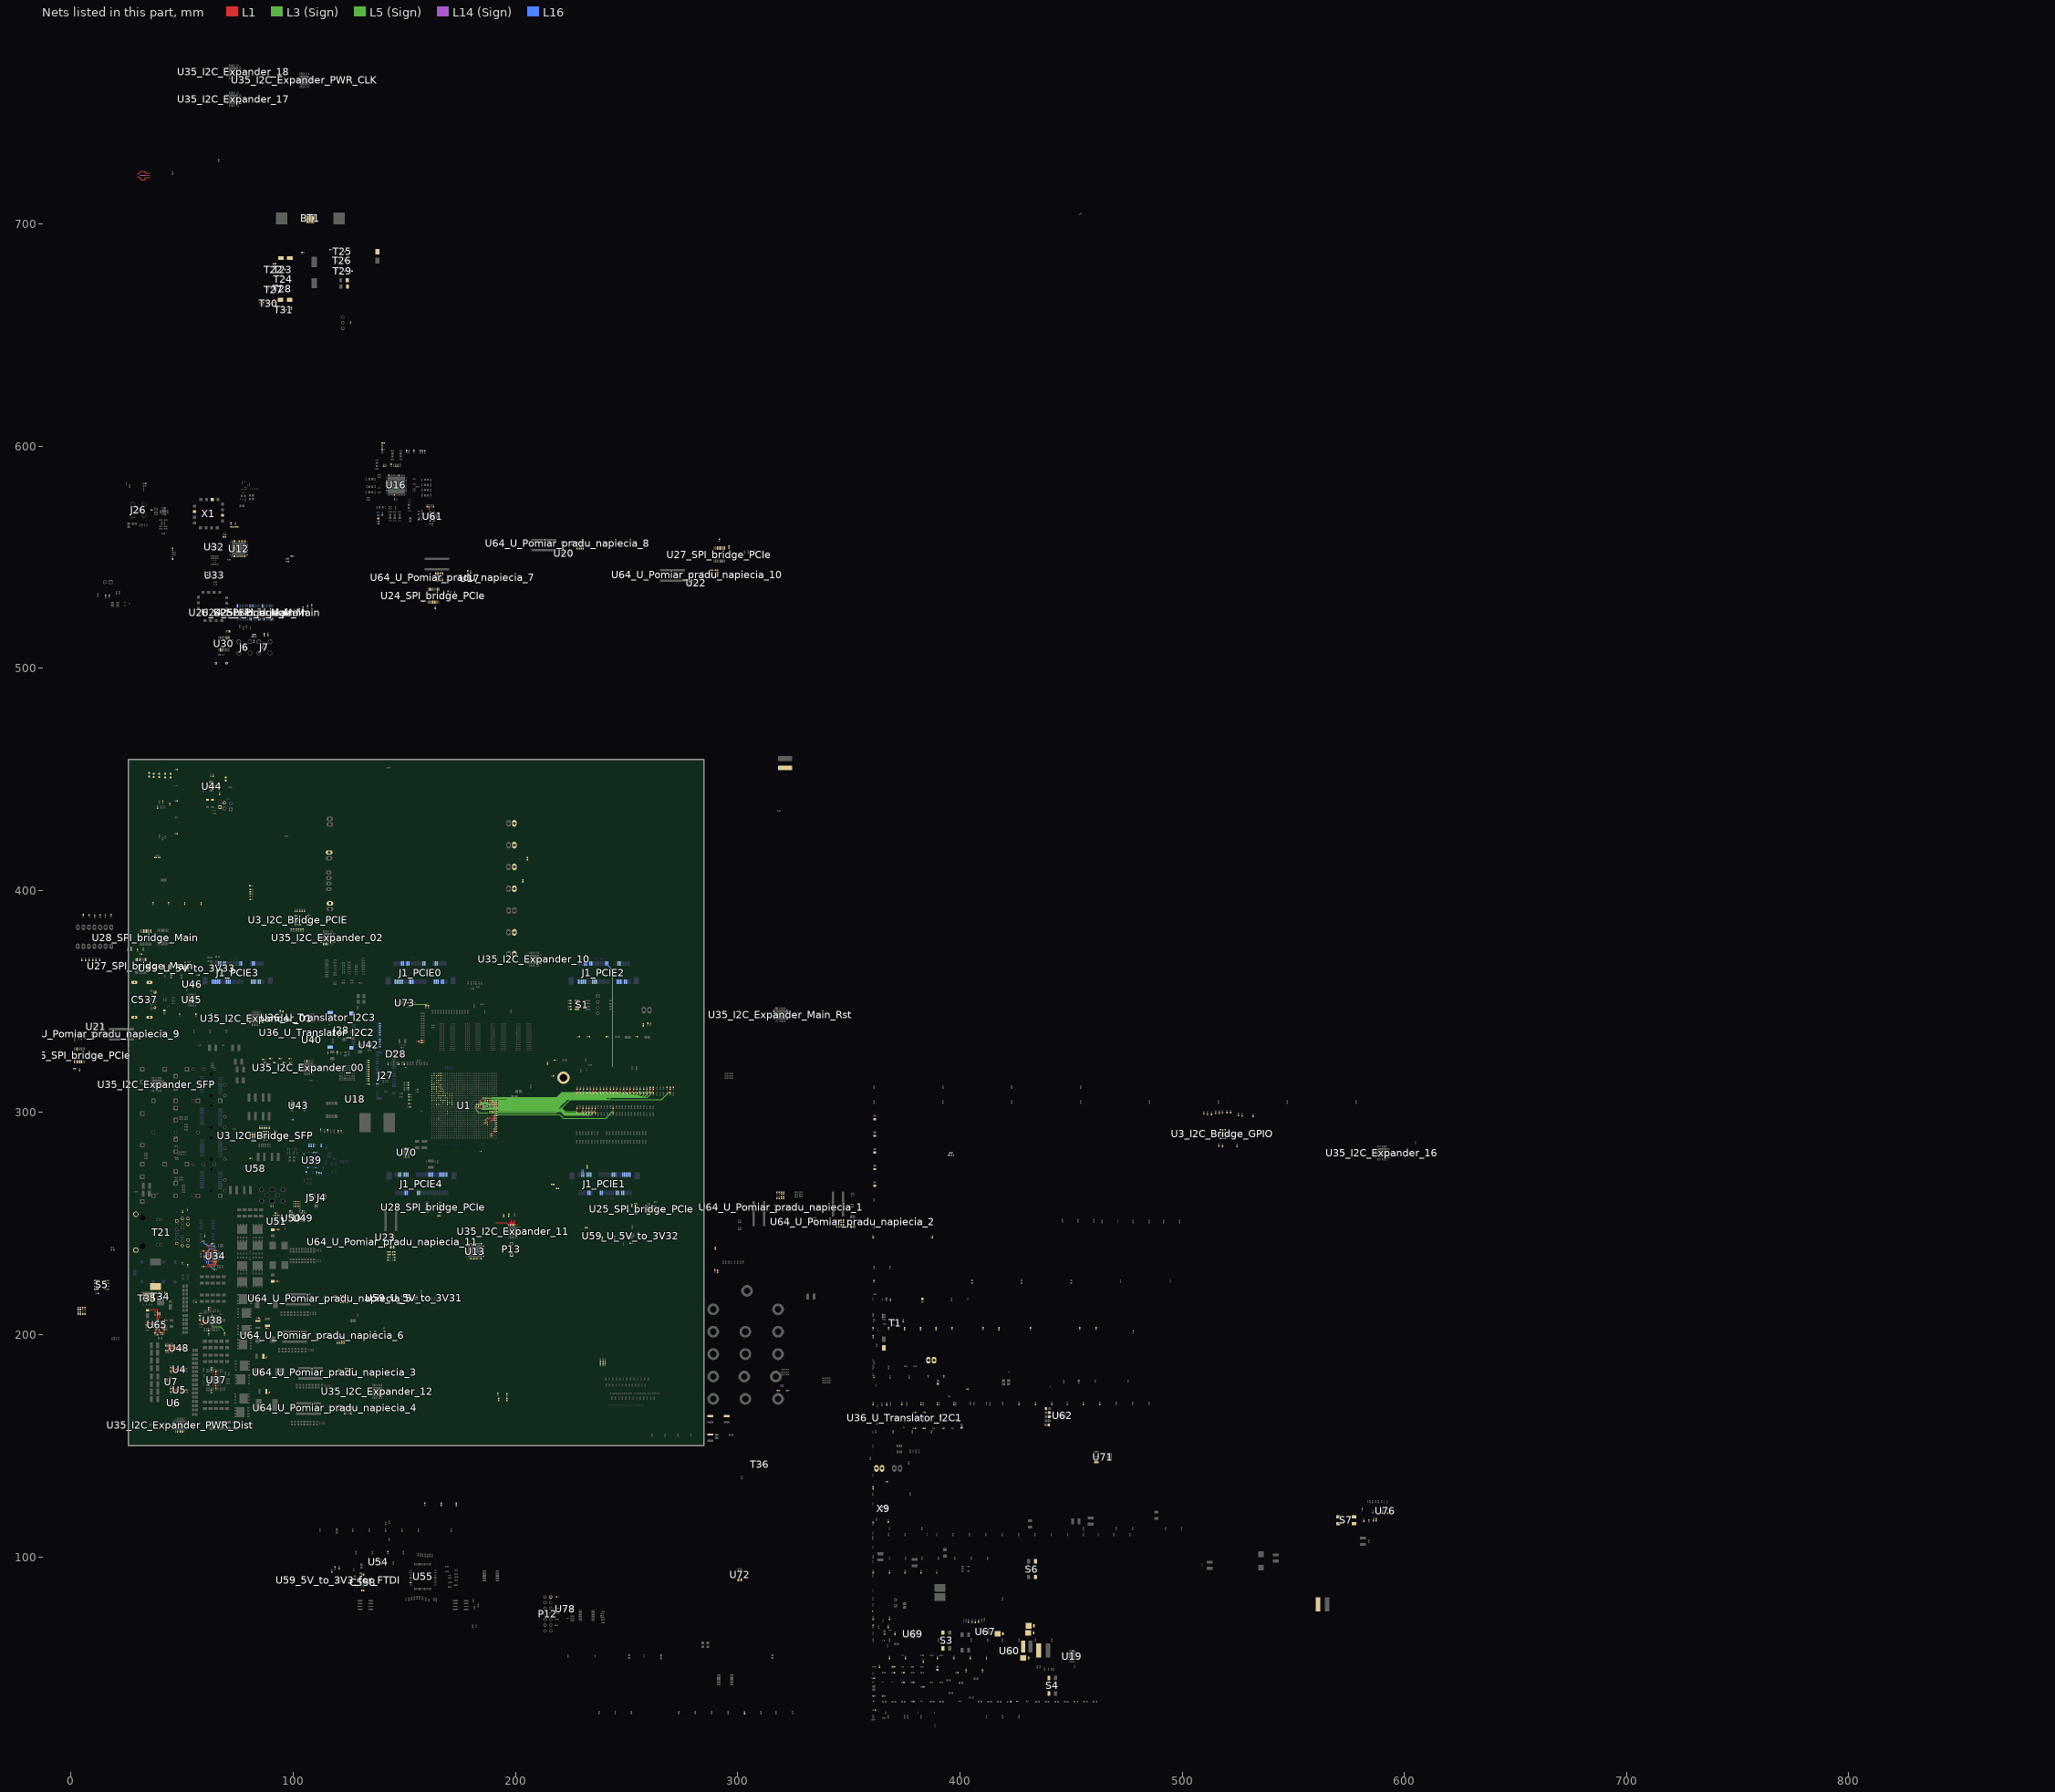
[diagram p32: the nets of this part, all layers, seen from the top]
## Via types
v1: diameter 0.5, hole 0.2, L1 to L16, tented both sides, 1212 vias
v2: diameter 0.5, hole 0.2, L1 to L16, 476 vias
v3: diameter 0.5/0.35/0.35/0.35/0.35/0.35/0.35/0.35/0.35/0.35/0.35/0.35/0.35/0.35/0.35/0.5 (per signal layer), hole 0.15, L1 to L16, tented both sides, 463 vias
v4: diameter 0.35/0/0.35 (per signal layer), hole 0.127, L1 to L3 (Sign), tented both sides, 282 vias
v5: diameter 0.5/0.35/0.35/0.35/0.35/0.35/0.35/0.35/0.35/0.35/0.35/0.35/0.35/0.35/0.35/0.5 (per signal layer), hole 0.2, L1 to L16, tented both sides, 222 vias
v6: diameter 0.8, hole 0.4, L1 to L16, tented both sides, 168 vias
v7: diameter 2.54, hole 1.02, L1 to L16, 113 vias
v8: diameter 1.4, hole 0.5, L1 to L16, tented both sides, 80 vias
v9: diameter 0.5/0/0.5 (per signal layer), hole 0.2, L14 (Sign) to L16, tented both sides, 52 vias
v10: diameter 0.35, hole 0.127, L1 to L2 (GND), tented both sides, 36 vias
v11: diameter 0.35, hole 0.127, L1 to L16, tented both sides, 16 vias
v12: diameter 0.4, hole 0.2, L1 to L16, 16 vias
v13: diameter 0.25, hole 0.2, L1 to L16, 16 vias
v14: diameter 0.3, hole 0.2, L1 to L16, 15 vias
v15: diameter 0.35/0/0.35 (per signal layer), hole 0.127, L1 to L3 (Sign), 12 vias
v16: diameter 0.45, hole 0.15, L1 to L16, 12 vias
v17: diameter 0.5/0.35/0.35/0.35/0.35/0.35/0.35/0.35/0.35/0.35/0.35/0.35/0.35/0.35/0.35/0.45 (per signal layer), hole 0.15, L1 to L16, tented both sides, 10 vias
v18: diameter 0.2/0/0.2 (per signal layer), hole 0.1, L1 to L3 (Sign), tented both sides, 9 vias
v19: diameter 0.4, hole 0.1, L1 to L16, 7 vias
v20: diameter 1.15, hole 1.15, L1 to L16, 6 vias
v21: diameter 1.65, hole 1.65, L1 to L16, 6 vias
v22: diameter 0.5, hole 0.2, L3 (Sign) to L6 (PWR/GND), tented both sides, 6 vias
v23: diameter 0.35/0/0.35 (per signal layer), hole 0.127, L14 (Sign) to L16, tented both sides, 5 vias
v24: diameter 0.2, hole 0.1, L1 to L16, 4 vias
v25: diameter 0.4, hole 0.2, L1 to L16, tented both sides, 2 vias
v26: diameter 0.4, hole 0.15, L1 to L16, 2 vias
v27: diameter 0.5/0.35/0.35/0.35/0.35/0.35/0.35/0.35/0.35/0.35/0.35/0.35/0.35/0.35/0.35/0.5 (per signal layer), hole 0.15, L1 to L16, 2 vias
v28: diameter 0.35, hole 0.127, L3 (Sign) to L6 (PWR/GND), tented both sides, 2 vias
v29: diameter 5.5, hole 3.5, L1 to L16, 1 vias
v30: diameter 0.5/0.35/0.35/0.35/0.35/0.35/0.35/0.35/0.35/0.35/0.35/0.35/0.35/0.35/0.35/0.5 (per signal layer), hole 0.2, L1 to L16, 1 vias
v31: diameter 0.35/0.35/0.35 (per signal layer), hole 0.127, L1 to L3 (Sign), tented both sides, 1 vias
v32: diameter 0.45/0/0.45 (per signal layer), hole 0.15, L1 to L3 (Sign), tented both sides, 1 vias
v33: diameter 0.45/0/0.45 (per signal layer), hole 0.2, L14 (Sign) to L16, tented both sides, 1 vias
v34: diameter 0.35, hole 0.127, L2 (GND) to L3 (Sign), 1 vias
v35: diameter 0.35, hole 0.127, L1 to L2 (GND), 1 vias

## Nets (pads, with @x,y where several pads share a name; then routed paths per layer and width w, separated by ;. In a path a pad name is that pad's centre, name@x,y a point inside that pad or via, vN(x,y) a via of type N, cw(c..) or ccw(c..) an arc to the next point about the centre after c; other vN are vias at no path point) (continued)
Interrupt48: R937.2 R969.1 U1.AA15 | length 95.5
  L1 w0.116: v5@181.909,302.052 U1.AA15@182.397,302.539
  L1 w0.12: R937.2@269.601,308.751 v1(269.601,309.607) R969.1@269.601,310.463
  L5 (Sign) w0.12: v5(181.904,302.057) 182.296,301.666 182.296,300.977 183.489,299.784 218.37,299.784 219.094,300.507 219.423,300.507 224.681,305.764 265.758,305.764 v1(269.601,309.607)
Interrupt49: R939.2 R970.1 U1.AB15 | length 85.3
  L1 w0.116: v5@182.909,302.052 U1.AB15@183.397,302.539
  L1 w0.12: R939.2@262.116,308.751 v1(262.116,309.607) R970.1@262.116,310.463
  L5 (Sign) w0.12: v5(182.904,302.057) 184.124,302.057 184.76,301.422 217.692,301.422 217.877,301.607 218.968,301.607 224.225,306.864 259.373,306.864 v1(262.116,309.607)
Interrupt50: R941.2 R971.1 U1.AD15 | length 81.5
  L1 w0.116: v5@184.909,302.052 U1.AD15@185.397,302.539
  L1 w0.12: R941.2@260.619,308.751 v1(260.619,309.607) R971.1@260.619,310.463
  L5 (Sign) w0.12: v5(184.904,302.057) 185.267,302.057 185.623,301.701 217.576,301.701 217.702,301.827 218.877,301.827 224.134,307.084 258.096,307.084 v1(260.619,309.607)
Interrupt51: R943.2 R972.1 U1.AE15 | length 78.7
  L1 w0.116: v5(185.909,302.052) U1.AE15@186.397,302.539
  L1 w0.12: R943.2@259.122,308.751 v1(259.122,309.607) R972.1@259.122,310.463
  L5 (Sign) w0.12: v5(185.909,302.052) 185.915,302.047 218.785,302.047 224.043,307.304 256.819,307.304 v1(259.122,309.607)
Interrupt52: R945.2 R973.1 U1.AG13 | length 51.1
  L1 w0.116: v4(187.909,300.052) U1.AG13@188.397,300.539
  L1 w0.12: R945.2@234.506,299.747 v4(234.506,300.816) R973.1@234.506,301.885
  L3 (Sign) w0.12: v4(187.909,300.052) 188.265,300.052 188.631,300.418 189.935,300.418 190.224,300.707 191.595,300.707 191.61,300.692 220.465,300.692 222.123,299.034 232.724,299.034 v4(234.506,300.816)
Interrupt53: R947.2 R974.1 U1.AH13 | length 51.5
  L1 w0.116: v4(188.909,300.052) U1.AH13@189.397,300.539
  L1 w0.12: R947.2@235.87,299.747 v4(235.87,300.816) R974.1@235.87,301.885
  L3 (Sign) w0.12: v4(188.909,300.052) 189.556,300.052 189.702,300.199 190.027,300.199 190.315,300.487 191.504,300.487 191.519,300.472 220.374,300.472 222.032,298.814 233.868,298.814 v4(235.87,300.816)
Interrupt54: R949.2 R975.1 U1.AK13 | length 45.4
  L1 w0.116: U1.AK13@191.397,300.539 v4@191.884,301.027
  L1 w0.12: R949.2@233.143,299.747 v4(233.143,300.816) R975.1@233.143,301.885
  L3 (Sign) w0.12: v4(191.878,301.027) 220.441,301.027 222.099,299.369 231.696,299.369 v4(233.143,300.816)
Interrupt55: R951.2 R976.1 U1.AK12 | length 58.1
  L1 w0.116: v4(190.909,299.052) U1.AK12@191.397,299.539
  L1 w0.12: R951.2@244.05,299.747 v4(244.05,300.816) R976.1@244.05,301.885
  L3 (Sign) w0.12: v4(190.909,299.052) 219.927,299.052 221.585,297.394 240.628,297.394 v4(244.05,300.816)
Interrupt56: R953.2 R977.1 U1.AJ14 | length 44.6
  L1 w0.116: v4(189.909,301.052) U1.AJ14@190.397,301.539
  L1 w0.12: R953.2@230.416,299.747 v4(230.416,300.816) R977.1@230.416,301.885
  L3 (Sign) w0.12: v4(189.909,301.052) 190.444,301.587 220.503,301.587 222.161,299.929 229.529,299.929 v4(230.416,300.816)
Interrupt57: R955.2 R978.1 U1.AK14 | length 45
  L1 w0.116: v4(190.909,301.052) U1.AK14@191.397,301.539
  L1 w0.12: R955.2@231.78,299.747 v4(231.78,300.816) R978.1@231.78,301.885
  L3 (Sign) w0.12: v4(190.909,301.052) 191.224,301.367 220.412,301.367 222.07,299.709 230.673,299.709 v4(231.78,300.816)
Interrupt58: R957.2 R979.1 U1.AJ15 | length 58.7
  L1 w0.116: U1.AJ15@190.397,302.539 v4(190.884,303.027)
  L1 w0.12: R957.2@244.153,308.751 v4(244.152,309.607) R979.1@244.152,310.463
  L3 (Sign) w0.12: v4(190.884,303.027) 191.092,303.027 191.465,302.654 218.844,302.654 220.526,304.336 221.093,304.336 223.107,306.35 240.895,306.35 v4(244.152,309.607)
Interrupt59: R959.2 R980.1 U1.AK15 | length 55.9
  L1 w0.116: U1.AK15@191.397,302.539 v4@191.884,303.027
  L1 w0.12: R959.2@242.656,308.751 v4(242.655,309.607) R980.1@242.655,310.463
  L3 (Sign) w0.12: v4(191.878,303.027) 218.689,303.027 220.218,304.556 221.002,304.556 223.025,306.578 239.626,306.578 v4(242.655,309.607)
Interrupt60: R922.1 R981.1 U1.AC16 | length 77.6
  L1 w0.116: v5@183.909,303.052 U1.AC16@184.397,303.539
  L1 w0.12: R922.1@256.128,308.751 v1(256.128,309.607) R981.1@256.128,310.463
  L5 (Sign) w0.12: v5(183.904,303.057) 184.43,303.057 184.765,303.392 185.342,303.392 185.611,303.124 195.529,303.124 196.022,303.617 196.08,303.617 197.971,305.509 219.309,305.509 221.614,307.814 254.335,307.814 v1(256.128,309.607)
Interrupt61: R924.1 R982.1 U1.AD16 | length 78
  L1 w0.116: v5@184.909,303.052 U1.AD16@185.397,303.539
  L1 w0.12: R924.1@257.625,308.751 v1(257.625,309.607) R982.1@257.625,310.463
  L5 (Sign) w0.12: v5(184.904,303.057) 185.058,302.904 195.62,302.904 196.114,303.397 196.171,303.397 198.062,305.289 219.4,305.289 221.705,307.594 255.612,307.594 v1(257.625,309.607)
Interrupt62: R926.1 R983.1 U1.AA16 | length 76.7
  L1 w0.116: v5@181.909,303.052 U1.AA16@182.397,303.539
  L1 w0.12: R926.1@253.134,308.751 v1(253.134,309.607) R983.1@253.134,310.463
  L5 (Sign) w0.12: v5(181.904,303.057) 182.141,303.057 182.791,303.708 184.277,303.708 184.65,304.081 184.72,304.081 184.733,304.094 186.856,304.094 187.331,303.619 195.33,303.619 195.347,303.636 195.419,303.636 195.84,304.057 195.897,304.057 197.793,305.953 219.125,305.953 221.43,308.258 249.079,308.258 ; 249.079,308.254 251.781,308.254 v1(253.134,309.607)
Interrupt63: R928.1 R984.1 U1.AB16 | length 77.3
  L1 w0.116: v5@182.909,303.052 U1.AB16@183.397,303.539
  L1 w0.12: R928.1@254.631,308.751 v1(254.631,309.607) R984.1@254.631,310.463
  L5 (Sign) w0.12: v5(182.904,303.057) 183.345,303.057 183.68,303.392 184.343,303.392 184.825,303.874 186.765,303.874 187.296,303.344 195.366,303.344 195.438,303.416 195.51,303.416 195.931,303.837 195.988,303.837 197.88,305.729 219.218,305.729 221.523,308.034 253.058,308.034 v1(254.631,309.607)
Interrupt64: R930.1 R985.1 U1.AC17 | length 72.8
  L1 w0.116: v5@183.909,304.052 U1.AC17@184.397,304.539
  L1 w0.12: R930.1@251.637,308.751 v1(251.637,309.607) R985.1@251.637,310.463
  L5 (Sign) w0.12: v5(183.904,304.057) 183.92,304.057 184.163,304.301 184.629,304.301 184.642,304.314 186.947,304.314 187.414,303.847 195.248,303.847 195.256,303.856 195.328,303.856 195.749,304.277 195.806,304.277 197.714,306.184 219.029,306.184 221.334,308.49 250.508,308.49 ; 250.508,308.478 v1(251.637,309.607)
Interrupt65: R932.1 R986.1 U1.AC18 | length 71.3
  L1 w0.116: v5@183.909,305.052 U1.AC18@184.397,305.539
  L1 w0.12: R932.1@250.14,308.751 v1(250.14,309.607) R986.1@250.14,310.463
  L5 (Sign) w0.12: v5(183.904,305.057) 184.441,304.521 184.537,304.521 184.551,304.534 187.038,304.534 187.496,304.076 195.237,304.076 195.658,304.497 195.715,304.497 197.631,306.413 218.934,306.413 221.239,308.718 249.251,308.718 v1(250.14,309.607)
Interrupt66: R934.1 R987.1 U1.AD19 | length 46.7
  L1 w0.116: v4(184.909,306.052) U1.AD19@185.397,306.539
  L1 w0.12: R934.1@227.686,308.751 v4(227.686,309.607) R987.1@227.686,310.463
  L3 (Sign) w0.12: v4(184.909,306.052) 184.983,306.052 185.522,306.591 186.563,306.591 186.639,306.667 189.586,306.667 189.674,306.756 220.091,306.756 222.141,308.805 226.884,308.805 v4(227.686,309.607)
Interrupt67: R936.1 R988.1 U1.AE19 | length 47.1
  L1 w0.116: v4(185.909,306.052) U1.AE19@186.397,306.539
  L1 w0.12: R936.1@229.183,308.751 v4(229.183,309.607) R988.1@229.183,310.463
  L3 (Sign) w0.12: v4(185.909,306.052) 186.156,306.299 186.682,306.299 186.771,306.387 187.048,306.387 190.578,306.387 190.662,306.471 217.263,306.471 217.328,306.536 220.182,306.536 222.232,308.585 228.161,308.585 v4(229.183,309.607)
Interrupt68: R938.1 R989.1 U1.AG16 | length 43.8
  L1 w0.116: v4(187.909,303.052) U1.AG16@188.397,303.539
  L1 w0.12: R938.1@227.69,299.747 v4(227.69,300.816) R989.1@227.69,301.885
  L3 (Sign) w0.12: v4(187.909,303.052) 188.854,302.108 192.397,302.108 220.605,302.108 222.263,300.45 227.323,300.45 v4(227.69,300.816)
Interrupt69: R940.1 R990.1 U1.AH16 | length 57.4
  L1 w0.116: v4(188.909,303.052) U1.AH16@189.397,303.539
  L1 w0.12: R940.1@241.159,308.751 v4(241.158,309.607) R990.1@241.158,310.463
  L3 (Sign) w0.12: v4(188.909,303.052) 189.319,303.052 189.695,303.428 218.523,303.428 219.87,304.776 220.911,304.776 222.955,306.82 238.371,306.82 v4(241.158,309.607)
Interrupt70: R942.1 R991.1 U1.AJ16 | length 61.4
  L1 w0.116: v4(189.909,303.052) U1.AJ16@190.397,303.539
  L1 w0.12: R942.1@245.649,308.751 v4(245.649,309.607) R991.1@245.649,310.463
  L3 (Sign) w0.12: v4(189.909,303.052) 190.562,302.4 218.949,302.4 220.665,304.116 221.185,304.116 223.164,306.096 242.138,306.096 v4(245.649,309.607)
Interrupt71: R944.1 R992.1 U1.AK16 | length 51
  L1 w0.116: U1.AK16@191.397,303.539 v4@191.884,304.027
  L1 w0.12: R944.1@238.165,308.751 v4(238.164,309.607) R992.1@238.164,310.463
  L3 (Sign) w0.12: v4(191.878,304.027) 218.275,304.027 219.464,305.216 220.729,305.216 222.778,307.265 235.822,307.265 v4(238.164,309.607)
Interrupt72: R946.1 R993.1 U1.AH17 | length 51
  L1 w0.116: v4(188.909,304.052) U1.AH17@189.397,304.539
  L1 w0.12: R946.1@235.171,308.751 v4(235.17,309.607) R993.1@235.17,310.463
  L3 (Sign) w0.12: v4(188.909,304.052) 189.276,304.419 190.06,304.419 190.263,304.622 218.028,304.622 219.062,305.656 220.547,305.656 222.596,307.705 233.268,307.705 v4(235.17,309.607)
Interrupt73: R948.1 R994.1 U1.AJ17 | length 51.5
  L1 w0.116: v4(189.909,304.052) U1.AJ17@190.397,304.539
  L1 w0.12: R948.1@236.668,308.751 v4(236.667,309.607) R994.1@236.667,310.463
  L3 (Sign) w0.12: v4(189.909,304.052) 190.235,304.052 190.564,304.381 190.765,304.381 190.771,304.387 218.126,304.387 219.175,305.436 220.638,305.436 222.687,307.485 234.545,307.485 v4(236.667,309.607)
Interrupt74: R950.1 R995.1 U1.AK17 | length 53.8
  L1 w0.116: v4(190.909,304.052) U1.AK17@191.397,304.539
  L1 w0.12: R950.1@239.662,308.751 v4(239.661,309.607) R995.1@239.661,310.463
  L3 (Sign) w0.12: v4(190.909,304.052) 191.209,304.052 191.604,303.657 218.428,303.657 219.767,304.996 220.82,304.996 222.87,307.045 237.099,307.045 v4(239.661,309.607)
Interrupt75: R952.1 R996.1 U1.AK18 | length 46.1
  L1 w0.116: U1.AK18@191.397,305.539 v4(191.884,305.052)
  L1 w0.12: R952.1@233.674,308.751 v4(233.674,309.607) R996.1@233.674,310.463
  L3 (Sign) w0.12: v4(191.884,305.052) 217.85,305.052 218.674,305.876 220.456,305.876 222.505,307.925 231.991,307.925 v4(233.674,309.607)
Interrupt76: R954.1 R997.1 U1.AG18 | length 47.1
  L1 w0.116: v4(187.909,305.052) U1.AG18@188.397,305.539
  L1 w0.12: R954.1@230.68,308.751 v4(230.68,309.607) R997.1@230.68,310.463
  L3 (Sign) w0.12: v4(187.909,305.052) 188.292,305.435 189.126,305.435 189.393,305.702 217.581,305.702 218.195,306.316 220.273,306.316 222.323,308.365 229.438,308.365 v4(230.68,309.607)
Interrupt77: R956.1 R998.1 U1.AH18 | length 47.6
  L1 w0.116: v4(188.909,305.052) U1.AH18@189.397,305.539
  L1 w0.12: R956.1@232.177,308.751 v4(232.177,309.607) R998.1@232.177,310.463
  L3 (Sign) w0.12: v4(188.909,305.052) 189.177,305.052 189.535,305.41 217.702,305.41 218.388,306.096 220.364,306.096 222.414,308.145 230.714,308.145 v4(232.177,309.607)
Interrupt78: R958.1 R999.1 U1.AE18 | length 65.5
  L1 w0.116: v5@185.909,305.052 U1.AE18@186.397,305.539
  L1 w0.12: R958.1@247.146,308.751 v1(247.146,309.607) R999.1@247.146,310.463
  L5 (Sign) w0.12: v5(185.904,305.057) 186.274,305.057 186.652,305.435 196.024,305.435 197.46,306.87 218.745,306.87 221.05,309.175 246.714,309.175 v1(247.146,309.607)
Interrupt79: R960.1 R1000.1 U1.AF18 | length 66.3
  L1 w0.116: v5@186.909,305.052 U1.AF18@187.397,305.539
  L1 w0.12: R960.1@248.643,308.751 v1(248.643,309.607) R1000.1@248.643,310.463
  L5 (Sign) w0.12: v5(186.906,305.092) 186.941,305.057 188.776,305.057 189.117,304.717 195.624,304.717 197.548,306.642 218.839,306.642 221.145,308.947 247.983,308.947 v1(248.643,309.607)
JTAG_CLK: R1042.2 U39.20
JTAG_TDI: R336.2 R1040.2 U39.23
JTAG_TDO: R337.2 R1043.2 U39.21
JTAG_TMS: R338.2 R1041.2 U39.22
LED_0: R329.1 U39.47
LED_0_RJ: R329.2 T21.17
LED_1: R330.1 U39.46
LED_1_RJ: R330.2 T21.18
LED_2: R331.1 U39.45
LED_2_RJ: R331.2 T21.19
LED_3: R332.2 U39.39
LED_3_RJ: R332.1 T21.20
LTC6952_0_Out0_N: U1.AH2 U12.33 | length 0.7
  L1 w0.116: v4(188.909,289.052) U1.AH2@189.397,289.539
LTC6952_0_Out0_P: U1.AH3 U12.34 | length 0.7
  L1 w0.116: v4(188.909,290.052) U1.AH3@189.397,290.539
LTC6952_0_Out1_N: C528.1 U12.30
LTC6952_0_Out1_P: C527.1 U12.31
LTC6952_0_Out2_N: C526.1 U12.27
LTC6952_0_Out2_P: C525.1 U12.28
LTC6952_0_Out3_N: U1.D9 U12.24
  other v3: 165.397,296.539
LTC6952_0_Out3_P: U1.D10 U12.25
  other v3: 165.397,297.539
LTC6952_0_Out4_N: U12.21
LTC6952_0_Out4_P: U12.22
LTC6952_0_Out5_N: U12.18
LTC6952_0_Out5_P: U12.19
LTC6952_0_Out6_N: C530.1 U12.15
LTC6952_0_Out6_P: C529.1 U12.16
LTC6952_0_Out7_N: U12.12
LTC6952_0_Out7_P: U12.13
LTC6952_0_Out8_N: R534.1 U12.9 U13.38
LTC6952_0_Out8_P: R534.2 U12.10 U13.37
LTC6952_0_Out9_N: R535.1 U12.6 U13.48
LTC6952_0_Out9_P: R535.2 U12.7 U13.47
LTC6952_0_Out10_N: C48.1 R82.1 U12.3
LTC6952_0_Out10_P: C47.1 R82.2 U12.4
LTC6952_0_REF_N: C43.1 R78.2 U12.45
LTC6952_0_REF_P: C44.1 R78.1 U12.46
LTC6952_1_C_N: C50.1 J5.2 R270.1
LTC6952_1_C_Out10_N: C52.2 J6.1
LTC6952_1_C_Out10_P: C51.2 J7.1
LTC6952_1_C_P: C49.1 J4.2 R270.2
LTC6952_1_CP_Out: C46.2 R77.2 U12.43 X1.2
LTC6952_1_Out0_N: U13.33
LTC6952_1_Out0_P: U13.34
LTC6952_1_Out1_N: J1_PCIE0.7 U13.30
LTC6952_1_Out1_P: J1_PCIE0.5 U13.31
LTC6952_1_Out2_N: J1_PCIE4.7 U13.27
LTC6952_1_Out2_P: J1_PCIE4.5 U13.28
LTC6952_1_Out3_N: J1_PCIE1.7 U13.24 | length 2.2
  L16 w0.081: 230.582,274.117 230.582,273.034 cw(c230.582,272.927) 230.69,272.927 J1_PCIE1.7@230.69,271.994
LTC6952_1_Out3_P: J1_PCIE1.5 U13.25 | length 2.2
  L16 w0.081: J1_PCIE1.5@229.89,271.994 229.89,272.927 cw(c229.997,272.927) 229.997,273.034 229.997,274.117
LTC6952_1_Out4_N: J1_PCIE3.7 U13.21
LTC6952_1_Out4_P: J1_PCIE3.5 U13.22
LTC6952_1_Out5_N: J1_PCIE2.7 U13.18
LTC6952_1_Out5_P: J1_PCIE2.5 U13.19
LTC6952_1_Out6_N: C42.2 U13.15
LTC6952_1_Out6_P: C41.2 U13.16
LTC6952_1_Out7_N: J27.53 U13.12
LTC6952_1_Out7_P: J27.55 U13.13
LTC6952_1_Out8_N: U13.9
LTC6952_1_Out8_P: U13.10
LTC6952_1_Out9_N: U13.6
LTC6952_1_Out9_P: U13.7
LTC6952_1_Out10_N: C52.1 R536.1 U13.3
LTC6952_1_Out10_P: C51.1 R536.2 U13.4
LTC6952_1_REF_N: C50.2 U13.46
LTC6952_1_REF_P: C49.2 U13.45
LTC6952_1_Temp: R395.2 U12.49
LTC6952_1_VCO_N: C334.2 R80.1 R532.2 U12.38
LTC6952_1_VCO_P: R80.2 R533.1 U12.37
LTC6952_2_Temp: R398.2 U13.49
LTC6952_3_Temp: R506.2
MainExpReset: R1002.1 T1.3 U35_I2C_Expander_Main_Rst.14
MIO_0: R768.2 U1.H17
MIO_1: R769.2 U1.A20
MIO_2: R770.2 U1.B19
MIO_3: R771.2 U1.D19
MIO_4: R772.2 U1.J17
MIO_5: R773.2 U1.C19
MIO_6: R774.2 U1.D20
MIO_7: R775.2 U1.E19
MIO_8: R776.2 U1.E20
MIO_9: R777.2 U1.F20
MIO_10: R778.2 U1.F18
MIO_11: R779.2 U1.G18
MIO_12: R780.2 U1.H18
MIO_13: R87.1 U1.G19
MIO_14: R88.1 U1.E18
MIO_15: R89.1 U1.J19
MIO_16: R90.1 U1.K17
MIO_17: R91.1 U1.C18
MIO_18: R92.1 U1.K18
MIO_19: R93.1 U1.K16
MIO_20: R94.1 U1.A19
MIO_21: R95.1 U1.H19
MIO_22: R96.1 U1.F17
MIO_23: R781.2 U1.K19
MIO_24: R782.2 U1.A18
MIO_25: R783.2 U1.B18
MIO_26: R784.2 U1.B20
MIO_27: R785.2 U1.B21
MIO_28: R786.2 U1.A21
MIO_29: R787.2 U1.D21
MIO_30: R788.2 U1.C21
MIO_31: R789.2 U1.A22
MIO_32: R790.2 U1.G20
MIO_33: R791.2 U1.C22
MIO_34: R792.2 U1.B24
MIO_35: R793.2 U1.B23
MIO_36: R794.2 U1.D22
MIO_37: R795.2 U1.F21
MIO_38: R796.2 U1.C23
MIO_39: R101.1 U1.E22
MIO_40: R102.1 U1.C24
MIO_41: R103.1 U1.D24
MIO_42: R104.1 U1.E23
MIO_43: R797.2 U1.F22
MIO_44: R798.2 U1.E24
MIO_45: R799.2 U1.F23
MIO_46: R105.1 U1.K20
MIO_47: R107.1 U1.K21
MIO_48: R108.1 U1.J21
MIO_49: R110.1 U1.G21
MIO_50: R111.1 U1.J20
MIO_51: R112.1 U1.H21
MIO_52: R362.1 U1.A24
MIO_53: R800.2 U1.B25
MIO_54: R115.1 U1.A23
MIO_55: R801.2 U1.B26
MIO_56: R116.1 U1.A25
MIO_57: R117.1 U1.A26
MIO_58: R118.1 U1.A28
MIO_59: R119.1 U1.A27
MIO_60: R120.1 U1.C26
MIO_61: R121.1 U1.B29
MIO_62: R122.1 U1.B28
MIO_63: R802.2 U1.A29
MIO_64: R803.2 U1.B30
MIO_65: R804.2 U1.D25
MIO_66: R805.2 U1.C27
MIO_67: R806.2 U1.C28
MIO_68: R807.2 U1.C29
MIO_69: R808.2 U1.D27
MIO_70: R809.2 U1.D26
MIO_71: R810.2 U1.D30
MIO_72: R811.2 U1.E27
MIO_73: R812.2 U1.E30
MIO_74: R813.2 U1.E29
MIO_75: R814.2 U1.D29
MIO_76: R815.2 U1.E28
MIO_77: R816.2 U1.E25
MIO_GPIO_0_12: J15.2 R780.1
MIO_GPIO_0_23: J16.2 R98.1 R781.1
MIO_GPIO_1_38: J17.2 R796.1
MIO_GPIO_2_66: J19.2 R805.1
MIO_GPIO_2_70: J20.2 R809.1
MIO_GPIO_2_73: J22.2 R812.1
MIO_GPIO_2_74: J23.2 R813.1 U36_U_Translator_I2C2.8
MIO_GPIO_2_75: J24.2 R814.1 U36_U_Translator_I2C3.8
MODE: R669.2 R670.1 U65.2 | length 3.6
  L1 w0.254: R670.1@37.668,200.838 38.26,200.838 ; U65.2@38.26,202.478 38.26,200.838 ; R669.2@38.887,199.931 38.537,199.931 38.26,200.208 38.26,200.838
NetBT1_2: BT1.2 R650.1 T22.2
NetC36_1: C36.1 R52.2 R54.2 | length 3.4
  L1 w0.5: R52.2@157.837,331.433 156.878,331.433 C36.1@156.346,331.965 156.903,332.522 R54.2@157.837,332.522
NetC45_2: C45.2 R77.1
NetC78_2: C78.2 U16.7
NetC79_2: C79.2 U16.38
NetC80_2: C80.2 U16.48
NetC91_1: C91.1 U16.39
NetC96_1: C96.1 U16.47
NetC312_2: C312.2 U4.11
NetC313_2: C313.2 U5.11
NetC314_1: C314.1 U48.11
NetC320_1: C320.1 U30.9
NetC321_1: C321.1 U30.10
NetC322_2: C322.2 U30.3 X3.1
NetC323_2: C323.2 U30.2 X3.2
NetC334_1: C334.1 X1.10
NetC335_2: C335.2 R532.1 R533.2
NetC341_1: C341.1 J26.1
NetC351_2: C351.2 R268.2 U34.3 | length 4.2
  L1 w0.254: R268.2@59.692,237.714 60.97,237.714 61.118,237.565 61.118,236.791 C351.2@61.146,236.764 61.151,236.764 61.776,236.139 U34.3@62.822,236.139
NetC356_2: C356.2 R272.2 R277.1 R278.1 U34.2 U34.4 U34.7 U34.9 U34.32 | length 23.6
  L1 w0.254: U34.4@62.822,235.639 61.694,235.639 61.667,235.666 60.285,235.666 60.109,235.49 60.109,235.185 R272.2@60.156,235.139 60.206,235.139 60.479,234.866 60.479,234.745 60.783,234.441 60.783,233.982 60.926,233.839 C356.2@60.931,233.839 61.589,233.839 61.99,233.437 v19(62.009,233.437) 62.049,233.437 62.347,233.139 U34.9@63.322,233.139 ; U34.2@62.822,236.639 62.481,236.639 62.057,237.063 62.057,237.421 v19@62.125,237.489 ; U34.32@63.322,237.639 63.322,237.703 63.32,237.705 62.341,237.705 v19@62.125,237.489 ; R278.1@63.439,240.856 63.077,240.856 62.085,239.863 62.085,237.528 v19@62.125,237.489
  L16 w0.254: v19(62.085,237.489) 62.085,237.449 62.009,237.373 v19(62.009,233.437) 62.009,231.673 v24(64.365,229.317)
NetC357_2: C357.2 U34.13 U34.28 | length 10.4
  L1 w0.254: v24(64.511,231.163) 64.583,231.235 64.816,231.235 65.315,231.734 65.315,232.984 65.32,232.989 65.32,233.137 U34.13@65.322,233.139 ; U34.28@65.322,237.639 v19(65.322,238.22)
  L16 w0.254: v24(64.511,231.163) 64.949,231.601 64.949,237.847 v19(65.322,238.22)
NetC471_2: C471.2 T21.12
NetC472_2: C472.2 T21.6
NetC473_2: C473.2 T21.1
NetC474_2: C474.2 T21.7
NetC475_2: C475.2 T21.S1
NetC476_2: C476.2 T21.S2
NetC532_1: C532.1 U44.14
NetC533_1: C533.1 U44.15
NetC534_1: C534.1 U44.16
NetC537_1: C537.1 FB26.2
NetC537_4: C537.4 FB27.2
NetC537_Z1: C537.Z1 FB28.1
NetC549_2: C549.2 R687.1 | length 1.1
  L1 w0.254: C549.2@61.948,212.229 61.951,212.227 61.951,211.171 R687.1@61.953,211.169
NetC558_Z1: C558.Z1 C558.Z2 C672.2
NetC568_2: C568.2 FB33.1 R433.2 U60.10 U60.11 U60.12 U60.13 U60.14
NetC571_1: C571.1 U60.7
NetC573_1: C573.1 R436.1 R437.2 U61.16
NetC577_1: C577.1 R438.1 R439.2 U61.10
NetC578_2: C578.2 U61.7
NetC579_2: C579.2 U61.19
NetC581_2: C581.2 C582.2 C583.2 FB34.2 R442.2 U62.1 U62.2 U62.3
NetC584_2: C584.2 R445.2 U62.7
NetC588_1: C588.1 R543.2
NetC588_2: C588.2 C589.1 R545.2
NetC591_2: C591.2 C592.2 FB37.2 X9.4
NetC597_2: C597.2 R140.1 U65.17 | length 3.4
  L1 w0.254: C597.2@34.722,206.35 34.722,205.41 R140.1@34.747,205.384 35.433,205.384 36,204.818 U65.17@36.92,204.818
NetC603_1: C603.1 R113.1 R114.2 U19.20
NetC604_1: C604.1 U19.25
NetC605_1: C605.1 R212.1 R214.2 U19.21
NetC612_1: C612.1 R216.2 R218.2 U19.22
NetC616_1: C616.1 R220.1 R274.2 U19.19
NetC633_2: C633.2 R613.1 | length 2.3
  L1 w0.254: R613.1@90.765,247.284 C633.2@93.052,247.284
NetC634_2: C634.2 R615.2 U34.11 U34.30 | length 14.8
  L1 w0.254: v19(61.056,231.693) 63.519,231.693 64.315,232.489 64.315,232.984 64.32,232.989 64.32,233.137 U34.11@64.322,233.139 ; v19(64.297,238.715) 64.32,238.692 U34.30@64.322,237.639 U34.30@64.322,237.639
  L16 w0.254: v19(61.056,231.693) R615.2@61.056,234.739 61.042,234.753 61.042,235.71 C634.2@61.028,235.724 61.028,235.729 61.301,236.002 61.392,236.002 61.525,236.135 61.525,237.705 62.535,238.715 v19(64.297,238.715)
NetC635_2: C635.2 R615.1 | length 1
  L16 w0.254: C635.2@60.062,235.724 60.109,235.677 60.109,234.785 R615.1@60.156,234.739
NetC636_2: C636.2 R616.1 | length 2.2
  L1 w0.254: R616.1@90.717,224.031 C636.2@92.942,224.031
NetC637_2: C637.2 R288.1 | length 1
  L1 w0.254: 87.033,189.468 87.568,189.468 C637.2@87.909,189.81
NetC638_2: C638.2 R298.1 | length 1.1
  L1 w0.254: 88.405,173.59 88.411,173.596 88.938,173.596 C638.2@89.332,173.99
NetC643_2: C643.2 R623.1 | length 1.1
  L1 w0.254: C643.2@63.12,173.949 R623.1@63.12,175.007
NetC644_2: C644.2 R624.1 | length 1
  L1 w0.254: R624.1@63.175,184.21 C644.2@63.175,185.176
NetC645_2: C645.2 R306.1 | length 0.9
  L1 w0.254: 87.566,203.543 87.564,203.54 87.564,203.257 C645.2@87.964,202.857
NetC646_2: C646.2 R316.1 | length 1.1
  L1 w0.254: C646.2@84.502,207.488 85.052,206.938 85.052,206.654
NetC652_2: C652.2 R631.1
NetC655_1: C655.1 U49.6
NetC656_1: C656.1 U50.6
NetC657_1: C657.1 U51.6
NetC674_2: C674.2 FB45.1 R644.2 U69.10 U69.11 U69.12 U69.13 U69.14
NetC678_2: C678.2 R652.2 R654.2 T25.1 T29.3
NetC679_2: C679.2 D23.1 D24.1 J36.1
NetC680_2: C680.2 R656.1 R657.1 T30.1
NetC693_1: C693.1 L22.1 T34.1 T34.2 T34.3 T35.5 U65.12 | length 3.2
  L1 w0.254: U65.12@39.26,206.158 39.26,207.104 39.98,207.823 C693.1@39.98,209.037
NetC693_2: C693.2 D26.1 R665.1 | length 6.9
  L1 w0.254: R665.1@39.014,209.828 39.025,209.817 C693.2@39.98,209.817
  L1 w0.5: D26.1@34.353,210.921 35.856,210.921 36.25,211.315 38.427,211.315 39.014,210.728 R665.1@39.014,209.828
NetC701_1: C701.1 R667.2 | length 2.9
  L1 w0.254: C701.1@41.097,200.121 41.676,200.121 42.078,200.524 R667.2@42.078,202.265
NetC701_2: C701.2 C702.2 U65.5 | length 2.7
  L1 w0.254: U65.5@39.76,202.478 39.76,201.311 C702.2@40.17,200.901 C701.2@41.097,200.901
NetC703_2: C703.2 U65.7 | length 1.7
  L1 w0.254: U65.7@40.6,203.818 41.292,203.818 41.38,203.73 41.759,203.73 C703.2@42.127,204.097
NetC706_1: C706.1 R671.1 R672.2 U70.16
NetC710_1: C710.1 R673.1 R674.2 U70.10
NetC711_2: C711.2 U70.7
NetC712_2: C712.2 U70.19
NetC713_2: C713.2 U71.3 X1.14
NetC719_2: C719.2 U69.7
NetC724_1: C724.1 R384.1
NetC725_1: C725.1 R385.1
NetC726_1: C726.1 R484.1
  other v29: 221.669,315.724
NetC727_1: C727.1 R485.1
NetC790_1: C790.1 U76.3
NetD5_1: D5.1 R716.1
NetD5_2: D5.2 U43.14
NetD6_1: D6.1 R717.1
NetD6_2: D6.2 U43.13
NetD7_1: D7.1 R718.1
NetD7_2: D7.2 D9.2 U43.12
NetD8_1: D8.1 R719.1
NetD8_2: D8.2 U43.11
NetD9_1: D9.1 R720.1
NetD10_1: D10.1 R368.1
NetD10_2: D10.2 U44.12
NetD11_2: D11.2 R370.1 S4.1 S4.2 U44.7
NetD12_2: D12.2 R369.1 S3.1 S3.2 U44.6
NetD16_1: D16.1 L13.1 U19.5
NetD16_2: D16.2 U19.6
NetD17_1: D17.1 L16.1 U19.4
NetD17_2: D17.2 U19.3
NetD18_1: D18.1 L17.1 U19.2
NetD18_2: D18.2 U19.1
NetD19_1: D19.1 L18.1 U19.7
NetD19_2: D19.2 U19.8
NetD20_1: D20.1 D21.1 R647.1
NetD20_2: D20.2 T23.3
NetD21_2: D21.2 T27.3
NetD28_2: D28.2 R276.2
NetF1_PCIE0_1: F1_PCIE0.1 J1_PCIE0.20
NetF1_PCIE1_1: F1_PCIE1.1 J1_PCIE1.20
NetF1_PCIE2_1: F1_PCIE2.1 J1_PCIE2.20
NetF1_PCIE3_1: F1_PCIE3.1 J1_PCIE3.20
NetF1_PCIE4_1: F1_PCIE4.1 J1_PCIE4.20
NetFB29_2: FB29.2 J28.10 J28.11 J28.12 J28.13
NetJ1_PCIE0_11: J1_PCIE0.11 R507.2
NetJ1_PCIE0_12: J1_PCIE0.12 U1.AK10 | length 0.7
  L1 w0.116: 190.909,297.052 U1.AK10@191.397,297.539
NetJ1_PCIE0_13: J1_PCIE0.13 R558_I2C_Bridge_PCIE.1 U3_I2C_Bridge_PCIE.3
NetJ1_PCIE0_14: J1_PCIE0.14 U1.AJ10 | length 0.7
  L1 w0.116: 189.909,297.052 U1.AJ10@190.397,297.539
NetJ1_PCIE0_15: J1_PCIE0.15 R227_I2C_Bridge_PCIE.1 U3_I2C_Bridge_PCIE.4
NetJ1_PCIE0_18: J1_PCIE0.18 U35_I2C_Expander_11.19 | length 2.3
  L1 w0.2: U35_I2C_Expander_11.19@198.289,249.285 198.289,251.548
NetJ1_PCIE0_31: J1_PCIE0.31 U1.AJ11 | length 0.7
  L1 w0.116: 189.909,298.052 U1.AJ11@190.397,298.539
NetJ1_PCIE0_33: J1_PCIE0.33 U1.AK11 | length 0.7
  L1 w0.116: 190.909,298.052 U1.AK11@191.397,298.539
NetJ1_PCIE0_36: J1_PCIE0.36
NetJ1_PCIE0_38: J1_PCIE0.38
NetJ1_PCIE0_42: J1_PCIE0.42
NetJ1_PCIE0_43: J1_PCIE0.43 R967.2
NetJ1_PCIE0_44: J1_PCIE0.44
NetJ1_PCIE0_45: J1_PCIE0.45 U24_SPI_bridge_PCIe.14
NetJ1_PCIE0_47: J1_PCIE0.47 U24_SPI_bridge_PCIe.12
NetJ1_PCIE0_49: J1_PCIE0.49 U24_SPI_bridge_PCIe.13
NetJ1_PCIE0_51: J1_PCIE0.51 R231_SPI_bridge_PCIe.1 U24_SPI_bridge_PCIe.11
NetJ1_PCIE1_11: J1_PCIE1.11 R514.2
NetJ1_PCIE1_12: J1_PCIE1.12 U1.AK8 | length 0.7
  L1 w0.116: v4(190.909,295.052) U1.AK8@191.397,295.539
NetJ1_PCIE1_13: J1_PCIE1.13 R226_I2C_Bridge_PCIE.1 U3_I2C_Bridge_PCIE.5 | length 0.7
  L1 w0.116: 453.833,704.145 v5(454.32,704.633)
NetJ1_PCIE1_14: J1_PCIE1.14 U1.AK9 | length 0.7
  L1 w0.116: v4(190.909,296.052) U1.AK9@191.397,296.539
NetJ1_PCIE1_15: J1_PCIE1.15 R225_I2C_Bridge_PCIE.1 U3_I2C_Bridge_PCIE.6
NetJ1_PCIE1_18: J1_PCIE1.18 U35_I2C_Expander_11.17 | length 2.1
  L1 w0.2: U35_I2C_Expander_11.17@199.589,249.421 199.589,251.548
NetJ1_PCIE1_31: J1_PCIE1.31 U1.AF10 | length 0.7
  L1 w0.116: 186.909,297.052 U1.AF10@187.397,297.539
NetJ1_PCIE1_33: J1_PCIE1.33 U1.AG10 | length 0.7
  L1 w0.116: 187.909,297.052 U1.AG10@188.397,297.539
NetJ1_PCIE1_36: J1_PCIE1.36
NetJ1_PCIE1_38: J1_PCIE1.38
NetJ1_PCIE1_42: J1_PCIE1.42
NetJ1_PCIE1_43: J1_PCIE1.43 R968.2
NetJ1_PCIE1_44: J1_PCIE1.44
NetJ1_PCIE1_45: J1_PCIE1.45 U25_SPI_bridge_PCIe.14
NetJ1_PCIE1_47: J1_PCIE1.47 U25_SPI_bridge_PCIe.12
NetJ1_PCIE1_49: J1_PCIE1.49 U25_SPI_bridge_PCIe.13
NetJ1_PCIE1_51: J1_PCIE1.51 R233_SPI_bridge_PCIe.1 U25_SPI_bridge_PCIe.11
NetJ1_PCIE2_11: J1_PCIE2.11 R901.2
NetJ1_PCIE2_12: J1_PCIE2.12 U1.AF7
NetJ1_PCIE2_13: J1_PCIE2.13 R224_I2C_Bridge_PCIE.1 U3_I2C_Bridge_PCIE.7
NetJ1_PCIE2_14: J1_PCIE2.14 U1.AF8 | length 0.7
  L1 w0.116: v4(186.909,295.052) U1.AF8@187.397,295.539
NetJ1_PCIE2_15: J1_PCIE2.15 R223_I2C_Bridge_PCIE.1 U3_I2C_Bridge_PCIE.8
NetJ1_PCIE2_18: J1_PCIE2.18 U35_I2C_Expander_11.18 | length 48.9
  L1 w0.2: U35_I2C_Expander_11.18@198.939,249.285 198.939,250.761
  L16 w0.2: J1_PCIE2.18@241.49,366.992 241.49,366.292 243.827,363.954 243.827,320.505
NetJ1_PCIE2_31: J1_PCIE2.31 U1.AH9 | length 0.7
  L1 w0.116: v4(188.909,296.052) U1.AH9@189.397,296.539
NetJ1_PCIE2_33: J1_PCIE2.33 U1.AJ9 | length 0.7
  L1 w0.116: v4(189.909,296.052) U1.AJ9@190.397,296.539
NetJ1_PCIE2_36: J1_PCIE2.36
NetJ1_PCIE2_38: J1_PCIE2.38
NetJ1_PCIE2_42: J1_PCIE2.42
NetJ1_PCIE2_43: J1_PCIE2.43 R969.2
NetJ1_PCIE2_44: J1_PCIE2.44
NetJ1_PCIE2_45: J1_PCIE2.45 U26_SPI_bridge_PCIe.14
NetJ1_PCIE2_47: J1_PCIE2.47 U26_SPI_bridge_PCIe.12
NetJ1_PCIE2_49: J1_PCIE2.49 U26_SPI_bridge_PCIe.13
NetJ1_PCIE2_51: J1_PCIE2.51 R236_SPI_bridge_PCIe.1 U26_SPI_bridge_PCIe.11
NetJ1_PCIE3_11: J1_PCIE3.11 R902.2
NetJ1_PCIE3_12: J1_PCIE3.12 U1.AK6 | length 0.7
  L1 w0.116: v4(190.909,293.052) U1.AK6@191.397,293.539
NetJ1_PCIE3_13: J1_PCIE3.13 R10_I2C_Bridge_PCIE.1 U3_I2C_Bridge_PCIE.10
NetJ1_PCIE3_14: J1_PCIE3.14 U1.AK7 | length 0.7
  L1 w0.116: v4(190.909,294.052) U1.AK7@191.397,294.539
NetJ1_PCIE3_15: J1_PCIE3.15 R9_I2C_Bridge_PCIE.1 U3_I2C_Bridge_PCIE.11
NetJ1_PCIE3_18: J1_PCIE3.18 U35_I2C_Expander_11.20 | length 1.5
  L1 w0.2: U35_I2C_Expander_11.20@197.639,249.285 197.639,250.761
NetJ1_PCIE3_31: J1_PCIE3.31 U1.AE9 | length 0.7
  L1 w0.116: U1.AE9@186.397,296.539 v4(186.884,296.052)
NetJ1_PCIE3_33: J1_PCIE3.33 U1.AE8 | length 0.7
  L1 w0.116: v4(185.909,295.052) U1.AE8@186.397,295.539
NetJ1_PCIE3_36: J1_PCIE3.36
NetJ1_PCIE3_38: J1_PCIE3.38
NetJ1_PCIE3_42: J1_PCIE3.42
NetJ1_PCIE3_43: J1_PCIE3.43 R970.2
NetJ1_PCIE3_44: J1_PCIE3.44
NetJ1_PCIE3_45: J1_PCIE3.45 U27_SPI_bridge_PCIe.14
NetJ1_PCIE3_47: J1_PCIE3.47 U27_SPI_bridge_PCIe.12
NetJ1_PCIE3_49: J1_PCIE3.49 U27_SPI_bridge_PCIe.13
NetJ1_PCIE3_51: J1_PCIE3.51 R238_SPI_bridge_PCIe.1 U27_SPI_bridge_PCIe.11
NetJ1_PCIE4_11: J1_PCIE4.11 R903.2
NetJ1_PCIE4_12: J1_PCIE4.12 U1.AK4 | length 0.7
  L1 w0.116: 190.909,291.052 U1.AK4@191.397,291.539
NetJ1_PCIE4_13: J1_PCIE4.13 R8_I2C_Bridge_PCIE.1 U3_I2C_Bridge_PCIE.12
NetJ1_PCIE4_14: J1_PCIE4.14 U1.AJ4 | length 0.7
  L1 w0.116: v4(189.909,291.052) U1.AJ4@190.397,291.539
NetJ1_PCIE4_15: J1_PCIE4.15 R7_I2C_Bridge_PCIE.1 U3_I2C_Bridge_PCIE.13
NetJ1_PCIE4_18: J1_PCIE4.18 U35_I2C_Expander_11.21 | length 6.2
  L1 w0.2: 191.197,250.317 195.957,250.317 U35_I2C_Expander_11.21@196.989,249.285
NetJ1_PCIE4_31: J1_PCIE4.31 U1.AJ5 | length 0.7
  L1 w0.116: v4(189.909,292.052) U1.AJ5@190.397,292.539
NetJ1_PCIE4_33: J1_PCIE4.33 U1.AK5 | length 0.7
  L1 w0.116: v4(190.909,292.052) U1.AK5@191.397,292.539
NetJ1_PCIE4_43: J1_PCIE4.43 R971.2
NetJ1_PCIE4_45: J1_PCIE4.45 U28_SPI_bridge_PCIe.14
NetJ1_PCIE4_47: J1_PCIE4.47 U28_SPI_bridge_PCIe.12
NetJ1_PCIE4_49: J1_PCIE4.49 U28_SPI_bridge_PCIe.13
NetJ1_PCIE4_51: J1_PCIE4.51 R240_SPI_bridge_PCIe.1 U28_SPI_bridge_PCIe.11
NetJ30_1: J30.1 R283.2
NetJ30_2: J30.2 R286.2
NetJ36_2: J36.2 R654.1
NetL15_2: L15.2 U19.24
NetP3_1: P3.1 U44.11
NetP4_2: P4.2 U44.10
NetP12_13: P12.13 R730.1 U78.1
NetP13_1: P13.1 R675.2
NetP13_3: P13.3 R737.1
NetR3_I2C_Bridge_GPIO_1: R3_I2C_Bridge_GPIO.1 U3_I2C_Bridge_GPIO.17 U35_I2C_Expander_16.8 U35_I2C_Expander_17.8 U35_I2C_Expander_18.8
NetR3_I2C_Bridge_PCIE_1: R3_I2C_Bridge_PCIE.1 U3_I2C_Bridge_PCIE.17
NetR3_I2C_Bridge_SFP_1: R3_I2C_Bridge_SFP.1 R130.1 U3_I2C_Bridge_SFP.17 U58.13
NetR4_I2C_Bridge_GPIO_1: R4_I2C_Bridge_GPIO.1 U3_I2C_Bridge_GPIO.16 U35_I2C_Expander_16.9 U35_I2C_Expander_17.9 U35_I2C_Expander_18.9
NetR4_I2C_Bridge_PCIE_1: R4_I2C_Bridge_PCIE.1 U3_I2C_Bridge_PCIE.16
NetR4_I2C_Bridge_SFP_1: R4_I2C_Bridge_SFP.1 R131.1 U3_I2C_Bridge_SFP.16 U58.14
NetR5_I2C_Bridge_GPIO_1: R5_I2C_Bridge_GPIO.1 U3_I2C_Bridge_GPIO.15
NetR5_I2C_Bridge_PCIE_1: R5_I2C_Bridge_PCIE.1 U3_I2C_Bridge_PCIE.15
NetR5_I2C_Bridge_SFP_1: R5_I2C_Bridge_SFP.1 U3_I2C_Bridge_SFP.15 U35_I2C_Expander_SFP.8
NetR6_I2C_Bridge_GPIO_1: R6_I2C_Bridge_GPIO.1 U3_I2C_Bridge_GPIO.14
NetR6_I2C_Bridge_PCIE_1: R6_I2C_Bridge_PCIE.1 U3_I2C_Bridge_PCIE.14
NetR6_I2C_Bridge_SFP_1: R6_I2C_Bridge_SFP.1 U3_I2C_Bridge_SFP.14 U35_I2C_Expander_SFP.9
NetR7_I2C_Bridge_GPIO_1: R7_I2C_Bridge_GPIO.1 U3_I2C_Bridge_GPIO.13
NetR7_I2C_Bridge_SFP_1: R7_I2C_Bridge_SFP.1 U3_I2C_Bridge_PCIE.19 U3_I2C_Bridge_SFP.13
NetR8_I2C_Bridge_GPIO_1: R8_I2C_Bridge_GPIO.1 U3_I2C_Bridge_GPIO.12
NetR8_I2C_Bridge_SFP_1: R8_I2C_Bridge_SFP.1 U3_I2C_Bridge_PCIE.20 U3_I2C_Bridge_SFP.12
NetR9_I2C_Bridge_GPIO_1: R9_I2C_Bridge_GPIO.1 U3_I2C_Bridge_GPIO.11 U35_I2C_Expander_10.8 U35_I2C_Expander_11.8 U35_I2C_Expander_12.8
NetR9_I2C_Bridge_SFP_1: R9_I2C_Bridge_SFP.1 R22.1 R389.1 R457.1 R465.1 R563.1 R567.1 R571.1 R575.1 R579.1 R583.1 R587.1 R591.1 R593.1 R597.1 U3_I2C_Bridge_SFP.11 U35_I2C_Expander_PWR_CLK.8 U35_I2C_Expander_PWR_Dist.8 U64_U_Pomiar_pradu_napiecia_1.5 U64_U_Pomiar_pradu_napiecia_2.5 U64_U_Pomiar_pradu_napiecia_3.5 U64_U_Pomiar_pradu_napiecia_4.5 U64_U_Pomiar_pradu_napiecia_5.5 U64_U_Pomiar_pradu_napiecia_6.5 U72.5
NetR10_I2C_Bridge_GPIO_1: R10_I2C_Bridge_GPIO.1 U3_I2C_Bridge_GPIO.10 U35_I2C_Expander_10.9 U35_I2C_Expander_11.9 U35_I2C_Expander_12.9
NetR10_I2C_Bridge_SFP_1: R10_I2C_Bridge_SFP.1 R24.1 R390.1 R459.1 R466.1 R564.1 R568.1 R572.1 R576.1 R580.1 R584.1 R588.1 R592.1 R594.1 R598.1 U3_I2C_Bridge_SFP.10 U35_I2C_Expander_PWR_CLK.9 U35_I2C_Expander_PWR_Dist.9 U64_U_Pomiar_pradu_napiecia_1.4 U64_U_Pomiar_pradu_napiecia_2.4 U64_U_Pomiar_pradu_napiecia_3.4 U64_U_Pomiar_pradu_napiecia_4.4 U64_U_Pomiar_pradu_napiecia_5.4 U64_U_Pomiar_pradu_napiecia_6.4 U72.4
NetR12_1: R12.1 R19.2 U5.5 | length 4.2
  L1 w0.2: R19.2@44.801,174.289 R12.1@45.844,174.289 45.844,174.314 46.28,174.75 U5.5@47.56,174.75 46.345,174.75
NetR14_2: R14.2 R16.2 R22.2 R24.2 U72.2
NetR15_1: R15.1 R23.2 U4.5 | length 2.9
  L1 w0.2: R23.2@44.92,183.563 R15.1@45.94,183.563 45.94,183.667 46.345,184.071 U4.5@47.56,184.071
NetR17_1: R17.1 R25.2 U4.4 | length 2.9
  L1 w0.2: R25.2@44.92,185.074 R17.1@45.94,185.074 45.94,184.98 46.349,184.571 U4.4@47.56,184.571
NetR18_2: R18.2 U4.10 | length 1.4
  L1 w0.2: U4.10@49.86,184.071 50.307,184.071 50.707,184.471 R18.2@51.11,184.471
NetR20_1: R20.1 R26.2 U5.4 | length 4.2
  L1 w0.2: R26.2@44.801,175.686 R20.1@45.822,175.686 46.258,175.25 U5.4@47.56,175.25 46.349,175.25
NetR21_2: R21.2 U5.10 | length 1.9
  L1 w0.2: U5.10@49.86,174.75 50.762,174.75 51.138,175.125 R21.2@51.6,175.125
NetR27_2: R27.2 U6.C1 | length 1.5
  L1 w0.2: U6.C1@46.01,168.789 46.01,168.781 46.095,168.696 46.095,168.659 46.66,168.094 46.66,167.884 46.86,167.684 R27.2@46.91,167.684
NetR28_1: R28.1 U7.C1
NetR75_1: R75.1 U1.H16
NetR81_1: R81.1 U1.C16 U12.48
NetR81_2: R81.2 U1.D16 U12.47
NetR132_2: R132.2 U28_SPI_bridge_Main.14
NetR133_2: R133.2 U28_SPI_bridge_Main.13
NetR134_2: R134.2 U28_SPI_bridge_Main.12
NetR149_1: R149.1 R159.2 U65.20 | length 3.9
  L1 w0.2: R149.1@33.873,204.343 33.947,204.269 33.947,204.06 34.27,203.737 34.548,203.737 34.773,203.513 R159.2@34.773,203.149
  L1 w0.254: R159.2@34.773,203.149 35.891,203.149 36.059,203.318 U65.20@36.92,203.318
NetR150_1: R150.1 R160.2 U65.6 | length 8.3
  L1 w0.254: U65.6@40.6,203.318 41.282,203.318 ; v4(41.123,202.654) 41.282,202.814 41.282,203.318 ; R160.2@42.078,203.203 41.397,203.203 41.282,203.318 ; R150.1@42.202,206.468 v4(42.202,207.35)
  L3 (Sign) w0.254: v4(41.123,202.654) 42.202,203.733 v4(42.202,207.35)
NetR174_2: R174.2 R175.2 R176.2 R177.2 U64_U_Pomiar_pradu_napiecia_7.2
NetR176_1: R176.1 R180.1 R185.1 R189.1 R194.1 R198.1 R203.1 R207.1 R213.1 R221.1 R538.1 R559_I2C_Bridge_PCIE.1 U3_I2C_Bridge_PCIE.2 U64_U_Pomiar_pradu_napiecia_7.5 U64_U_Pomiar_pradu_napiecia_8.5 U64_U_Pomiar_pradu_napiecia_9.5 U64_U_Pomiar_pradu_napiecia_10.5 U64_U_Pomiar_pradu_napiecia_11.5
NetR177_1: R177.1 R181.1 R186.1 R190.1 R195.1 R199.1 R204.1 R208.1 R215.1 R222.1 R427.1 R560_I2C_Bridge_PCIE.1 U3_I2C_Bridge_PCIE.1 U64_U_Pomiar_pradu_napiecia_7.4 U64_U_Pomiar_pradu_napiecia_8.4 U64_U_Pomiar_pradu_napiecia_9.4 U64_U_Pomiar_pradu_napiecia_10.4 U64_U_Pomiar_pradu_napiecia_11.4
NetR178_2: R178.2 R179.2 R180.2 R181.2 U64_U_Pomiar_pradu_napiecia_7.1
NetR182_2: R182.2 U17.C1
NetR183_2: R183.2 R184.2 R185.2 R186.2 U64_U_Pomiar_pradu_napiecia_8.2
NetR187_2: R187.2 R188.2 R189.2 R190.2 U64_U_Pomiar_pradu_napiecia_8.1
NetR191_2: R191.2 U20.C1
NetR192_2: R192.2 R193.2 R194.2 R195.2 U64_U_Pomiar_pradu_napiecia_9.2
NetR196_2: R196.2 R197.2 R198.2 R199.2 U64_U_Pomiar_pradu_napiecia_9.1
NetR200_2: R200.2 U21.C1
NetR201_2: R201.2 R202.2 R203.2 R204.2 U64_U_Pomiar_pradu_napiecia_10.2
NetR205_2: R205.2 R206.2 R207.2 R208.2 U64_U_Pomiar_pradu_napiecia_10.1
NetR209_2: R209.2 U22.C1
NetR210_2: R210.2 R211.2 R213.2 R215.2 U64_U_Pomiar_pradu_napiecia_11.2
NetR217_2: R217.2 R219.2 R221.2 R222.2 U64_U_Pomiar_pradu_napiecia_11.1
NetR223_I2C_Bridge_GPIO_1: R223_I2C_Bridge_GPIO.1 U3_I2C_Bridge_GPIO.8
NetR224_I2C_Bridge_GPIO_1: R224_I2C_Bridge_GPIO.1 U3_I2C_Bridge_GPIO.7
NetR225_I2C_Bridge_GPIO_1: R225_I2C_Bridge_GPIO.1 U3_I2C_Bridge_GPIO.6
NetR226_I2C_Bridge_GPIO_1: R226_I2C_Bridge_GPIO.1 U3_I2C_Bridge_GPIO.5
NetR227_I2C_Bridge_GPIO_1: R227_I2C_Bridge_GPIO.1 U3_I2C_Bridge_GPIO.4
NetR228_2: R228.2 U23.C1
NetR229_2: R229.2 R230.2 R457.2 R459.2 U64_U_Pomiar_pradu_napiecia_1.2
NetR231_SPI_bridge_Main_1: R231_SPI_bridge_Main.1 U24_SPI_bridge_Main.11 U24_SPI_bridge_PCIe.6 U25_SPI_bridge_PCIe.6 U26_SPI_bridge_PCIe.6 U27_SPI_bridge_PCIe.6 U28_SPI_bridge_PCIe.6
NetR232_SPI_bridge_Main_1: R232_SPI_bridge_Main.1 U35_I2C_Expander_01.25
NetR232_SPI_bridge_Main_2: R232_SPI_bridge_Main.2 U24_SPI_bridge_Main.9
NetR232_SPI_bridge_PCIe_1: R232_SPI_bridge_PCIe.1 U35_I2C_Expander_02.2
NetR232_SPI_bridge_PCIe_2: R232_SPI_bridge_PCIe.2 U24_SPI_bridge_PCIe.9
NetR234_SPI_bridge_Main_1: R234_SPI_bridge_Main.1 U35_I2C_Expander_01.26
NetR234_SPI_bridge_Main_2: R234_SPI_bridge_Main.2 U25_SPI_bridge_Main.9
NetR234_SPI_bridge_PCIe_1: R234_SPI_bridge_PCIe.1 U35_I2C_Expander_02.3
NetR234_SPI_bridge_PCIe_2: R234_SPI_bridge_PCIe.2 U25_SPI_bridge_PCIe.9
NetR235_SPI_bridge_Main_1: R235_SPI_bridge_Main.1 U26_SPI_bridge_Main.9
NetR235_SPI_bridge_Main_2: R235_SPI_bridge_Main.2 U35_I2C_Expander_01.27
NetR235_SPI_bridge_PCIe_1: R235_SPI_bridge_PCIe.1 U26_SPI_bridge_PCIe.9
NetR235_SPI_bridge_PCIe_2: R235_SPI_bridge_PCIe.2 U35_I2C_Expander_02.4
NetR237_SPI_bridge_Main_1: R237_SPI_bridge_Main.1 U27_SPI_bridge_Main.9
NetR237_SPI_bridge_Main_2: R237_SPI_bridge_Main.2 U35_I2C_Expander_01.28
NetR237_SPI_bridge_PCIe_1: R237_SPI_bridge_PCIe.1 U27_SPI_bridge_PCIe.9
NetR237_SPI_bridge_PCIe_2: R237_SPI_bridge_PCIe.2 U35_I2C_Expander_02.28
NetR238_SPI_bridge_Main_2: R238_SPI_bridge_Main.2 U27_SPI_bridge_Main.15
NetR239_SPI_bridge_Main_1: R239_SPI_bridge_Main.1 U35_I2C_Expander_01.1
NetR239_SPI_bridge_Main_2: R239_SPI_bridge_Main.2 U28_SPI_bridge_Main.9
NetR239_SPI_bridge_PCIe_1: R239_SPI_bridge_PCIe.1 U35_I2C_Expander_02.1
NetR239_SPI_bridge_PCIe_2: R239_SPI_bridge_PCIe.2 U28_SPI_bridge_PCIe.9
NetR240_SPI_bridge_Main_1: R240_SPI_bridge_Main.1 R912.2 U28_SPI_bridge_Main.11
NetR241_1: R241.1 R242.1 U3_I2C_Bridge_GPIO.22
NetR243_1: R243.1 R244.1 U3_I2C_Bridge_GPIO.23
NetR263_2: R263.2 U33.16
NetR264_2: R264.2 U33.13
NetR265_2: R265.2 U33.15
NetR266_1: R266.1 R267.2 S5.1 S5.2 S5.3 S5.4
NetR269_2: R269.2 U18.C1
NetR272_1: R272.1 U34.5 | length 1.8
  L1 w0.254: R272.1@61.056,235.139 U34.5@62.822,235.139
NetR281_1: R281.1 R400.1 U3_I2C_Bridge_GPIO.18
NetR284_2: R284.2 U19.17
NetR289_1: R289.1 U37.5 | length 1.4
  L1 w0.254: R289.1@61.781,179.317 U37.5@63.175,179.317
NetR293_2: R293.2 R294.2 U37.7 | length 2.4
  L1 w0.254: R294.2@61.781,177.317 R293.2@61.781,178.317 U37.7@63.175,178.317
NetR304_2: R304.2 R388.2 R389.2 R390.2 U72.1
NetR305_2: R305.2 U67.6
NetR307_1: R307.1 U38.5 | length 4.1
  L1 w0.254: R307.1@57.945,206.596 57.945,206.233 58.189,205.989 59.673,205.989 59.898,206.214 U38.5@61.453,206.214
NetR308_2: R308.2 U67.5
NetR309_2: R309.2 U67.4
NetR310_2: R310.2 R312.2 U38.7 | length 2.8
  L1 w0.254: R312.2@58.826,204.716 59.784,204.716 60.282,205.214 U38.7@61.453,205.214
NetR334_1: R334.1 U39.12
NetR339_1: R339.1 R341.2 U40.7
NetR342_1: R342.1 R344.2 U42.7
NetR358_1: R358.1 S1.8
NetR359_1: R359.1 S1.7
NetR360_1: R360.1 S1.6
NetR361_1: R361.1 S1.5
NetR366_2: R366.2 R498.1 R499.2 R692.2
NetR372_1: R372.1 R373.2 U44.2 U44.3
NetR379_2: R379.2 U45.24
NetR380_2: R380.2 U46.C1
NetR391_1: R391.1 R393.2 U49.7
NetR394_1: R394.1 R396.2 U50.7
NetR397_1: R397.1 R399.2 U51.7
NetR419_2: R419.2 R422.1 U54.1
NetR423_2: R423.2 U55.6
NetR424_2: R424.2 U55.14
NetR425_SPI_bridge_Main_1: R425_SPI_bridge_Main.1 U24_SPI_bridge_Main.1
NetR425_SPI_bridge_PCIe_1: R425_SPI_bridge_PCIe.1 U24_SPI_bridge_PCIe.1
NetR426_SPI_bridge_Main_2: R426_SPI_bridge_Main.2 U24_SPI_bridge_Main.7
NetR426_SPI_bridge_PCIe_2: R426_SPI_bridge_PCIe.2 U24_SPI_bridge_PCIe.7
NetR428_1: R428.1 U3_I2C_Bridge_GPIO.20 U35_I2C_Expander_Main_Rst.9 U36_U_Translator_I2C1.5 U36_U_Translator_I2C2.5
NetR429_1: R429.1 U58.12
NetR430_5V_to_3V3_for_FTDI_1: R430_5V_to_3V3_for_FTDI.1 R432_5V_to_3V3_for_FTDI.2 U59_5V_to_3V3_for_FTDI.7
NetR430_U_5V_to_3V31_1: R430_U_5V_to_3V31.1 R432_U_5V_to_3V31.2 U59_U_5V_to_3V31.7
NetR430_U_5V_to_3V32_1: R430_U_5V_to_3V32.1 R432_U_5V_to_3V32.2 U59_U_5V_to_3V32.7
NetR430_U_5V_to_3V33_1: R430_U_5V_to_3V33.1 R432_U_5V_to_3V33.2 U59_U_5V_to_3V33.7
NetR431_5V_to_3V3_for_FTDI_1: R431_5V_to_3V3_for_FTDI.1 U59_5V_to_3V3_for_FTDI.5
NetR433_1: R433.1 R434.2 U60.9
NetR435_1: R435.1 R668.2 U69.4
NetR443_1: R443.1 R444.2 U62.6
NetR449_1: R449.1 R450.1 U3_I2C_Bridge_PCIE.22
NetR451_1: R451.1 R452.1 U3_I2C_Bridge_PCIE.23
NetR453_1: R453.1 R454.1 U3_I2C_Bridge_PCIE.18
NetR455_1: R455.1 R456.1 U35_I2C_Expander_PWR_Dist.13
NetR458_1: R458.1 R460.1 U35_I2C_Expander_PWR_Dist.12
NetR461_2: R461.2 R463.2 R465.2 R466.2 U64_U_Pomiar_pradu_napiecia_1.1
NetR462_1: R462.1 R464.1 U35_I2C_Expander_PWR_Dist.11
NetR467_2: R467.2 R468.2 R593.2 R594.2 U64_U_Pomiar_pradu_napiecia_2.2
NetR469_1: R469.1 R470.1 U3_I2C_Bridge_SFP.22
NetR471_1: R471.1 R472.1 U3_I2C_Bridge_SFP.23
NetR473_1: R473.1 R474.1 U3_I2C_Bridge_SFP.18
NetR475_1: R475.1 R476.1 U35_I2C_Expander_SFP.13
NetR477_1: R477.1 R478.1 U35_I2C_Expander_SFP.12
NetR479_1: R479.1 R480.1 U35_I2C_Expander_SFP.11
NetR481_2: R481.2 U27_SPI_bridge_Main.13
NetR488_1: R488.1 T36.3 U32.2
NetR499_1: R499.1 U35_I2C_Expander_00.24
NetR507_1: R507.1 U1.H13
NetR514_1: R514.1 U1.H12
NetR540_1: R540.1 U35_I2C_Expander_00.19
NetR543_1: R543.1 X9.3
NetR544_1: R544.1 X9.1
NetR558_I2C_Bridge_GPIO_1: R558_I2C_Bridge_GPIO.1 U3_I2C_Bridge_GPIO.3
NetR559_I2C_Bridge_GPIO_1: R559_I2C_Bridge_GPIO.1 U3_I2C_Bridge_GPIO.2 U35_I2C_Expander_00.8 U35_I2C_Expander_01.8 U35_I2C_Expander_02.8
NetR560_I2C_Bridge_GPIO_1: R560_I2C_Bridge_GPIO.1 U3_I2C_Bridge_GPIO.1 U35_I2C_Expander_00.9 U35_I2C_Expander_01.9 U35_I2C_Expander_02.9
NetR561_2: R561.2 R562.2 R563.2 R564.2 U64_U_Pomiar_pradu_napiecia_3.2
NetR565_2: R565.2 R566.2 R567.2 R568.2 U64_U_Pomiar_pradu_napiecia_3.1
NetR569_2: R569.2 R570.2 R571.2 R572.2 U64_U_Pomiar_pradu_napiecia_4.2
NetR573_2: R573.2 R574.2 R575.2 R576.2 U64_U_Pomiar_pradu_napiecia_4.1
NetR577_2: R577.2 R578.2 R579.2 R580.2 U64_U_Pomiar_pradu_napiecia_5.2
NetR581_2: R581.2 R582.2 R583.2 R584.2 U64_U_Pomiar_pradu_napiecia_5.1
NetR585_2: R585.2 R586.2 R587.2 R588.2 U64_U_Pomiar_pradu_napiecia_6.2
NetR589_2: R589.2 R590.2 R591.2 R592.2 U64_U_Pomiar_pradu_napiecia_6.1
NetR595_2: R595.2 R596.2 R597.2 R598.2 U64_U_Pomiar_pradu_napiecia_2.1
NetR599_1: R599.1 U3_I2C_Bridge_GPIO.19 U35_I2C_Expander_Main_Rst.8 U36_U_Translator_I2C1.6 U36_U_Translator_I2C2.6
NetR600_1: R600.1 R601.2 U58.1
NetR602_SPI_bridge_Main_1: R602_SPI_bridge_Main.1 U24_SPI_bridge_Main.2
NetR602_SPI_bridge_PCIe_1: R602_SPI_bridge_PCIe.1 U24_SPI_bridge_PCIe.2
NetR603_SPI_bridge_Main_2: R603_SPI_bridge_Main.2 U24_SPI_bridge_Main.8
NetR603_SPI_bridge_PCIe_2: R603_SPI_bridge_PCIe.2 U24_SPI_bridge_PCIe.8
NetR604_SPI_bridge_Main_1: R604_SPI_bridge_Main.1 U25_SPI_bridge_Main.1
NetR604_SPI_bridge_PCIe_1: R604_SPI_bridge_PCIe.1 U25_SPI_bridge_PCIe.1
NetR605_SPI_bridge_Main_2: R605_SPI_bridge_Main.2 U25_SPI_bridge_Main.7
NetR605_SPI_bridge_PCIe_2: R605_SPI_bridge_PCIe.2 U25_SPI_bridge_PCIe.7
NetR606_SPI_bridge_Main_1: R606_SPI_bridge_Main.1 U25_SPI_bridge_Main.2
NetR606_SPI_bridge_PCIe_1: R606_SPI_bridge_PCIe.1 U25_SPI_bridge_PCIe.2
NetR612_1: R612.1 U34.29 | length 8.5
  L1 w0.254: U34.29@64.822,237.639 64.822,237.71 64.831,237.72 v24(64.831,239.097)
  L16 w0.254: v24(59.917,241.89) 59.917,241.114 60.285,240.746 60.915,240.746 61.483,240.178 64.683,240.178 64.831,240.029 v24(64.831,239.097)
NetR614_1: R614.1 U34.12 | length 6.9
  L1 w0.254: R614.1@59.692,230.712 63.088,230.712 64.11,231.734 64.666,231.734 64.815,231.882 64.815,232.984 64.82,232.989 64.82,233.137 U34.12@64.822,233.139
NetR621_1: R621.1 U37.29 | length 1.6
  L1 w0.254: R621.1@65.137,183.369 65.116,183.348 65.116,182.714 65.175,182.655 U37.29@65.175,181.817
NetR622_1: R622.1 U37.12 | length 1.4
  L1 w0.254: R622.1@65.175,175.893 U37.12@65.175,177.317
NetR628_1: R628.1 U38.12 | length 8.1
  L1 w0.254: v4(63.453,203.556) U38.12@63.453,204.214 ; R628.1@69.132,200.683 v4(69.132,201.631)
  L3 (Sign) w0.254: v4(63.453,203.556) 67.207,203.556 v4@69.138,201.625
NetR644_1: R644.1 R645.2 U69.9
NetR648_1: R648.1 T25.3
NetR649_2: R649.2 T26.3
NetR650_2: R650.2 T23.1 T24.3
NetR651_1: R651.1 T27.1 T28.3
NetR653_2: R653.2 T30.3
NetR655_1: R655.1 T29.1
NetR657_2: R657.2 T31.3
NetR658_1: R658.1 T31.1
NetR665_2: R665.2 U65.13 | length 2.9
  L1 w0.254: U65.13@38.76,206.158 38.76,207.602 39.014,207.856 R665.2@39.014,208.928
NetR677_1: R677.1 R682.2 U48.6 | length 2.9
  L1 w0.2: R677.1@44.716,192.933 R682.2@45.775,192.933 45.914,192.933 46.214,193.233 U48.6@47.527,193.233
NetR678_1: R678.1 R683.2 U48.5 | length 5.6
  L1 w0.2: R683.2@42.6,192.933 R678.1@43.658,192.933 43.658,193.501 43.89,193.733 U48.5@47.527,193.733
NetR679_1: R679.1 R684.2 U48.3 | length 2.9
  L1 w0.2: R684.2@44.716,195.033 R679.1@45.775,195.033 46.075,194.733 U48.3@47.527,194.733
NetR680_1: R680.1 R685.2 U48.4 | length 5.6
  L1 w0.2: R685.2@42.6,195.033 R680.1@43.658,195.033 43.658,194.466 43.89,194.233 U48.4@47.527,194.233
NetR681_2: R681.2 U48.10 | length 1.4
  L1 w0.2: U48.10@49.827,193.733 50.729,193.733 R681.2@51.105,194.109
NetR686_1: R686.1 U38.29 | length 0.6
  L1 w0.254: U38.29@63.453,208.714 v4@63.453,209.276
  other v4: 63.449,209.276
NetR689_2: R689.2 R690.2 U73.7 | length 10.7
  L1 w0.2: U73.7@151.644,349.484 153.033,349.484 v4(153.035,349.482)
  L1 w0.3: R690.2@159.652,348.062 160.213,348.062 ; v4(160.213,348.729) 160.213,348.062 ; R689.2@160.795,348.062 160.213,348.062
  L3 (Sign) w0.2: v4(153.035,349.482) v4@153.035,349.491
  L3 (Sign) w0.3: v4@153.035,349.491 153.797,348.729 v4(160.213,348.729)
NetR692_1: R692.1 S6.3 S6.4
NetR710_1: R710.1 R711.1 R712.2
NetR711_2: R711.2 U76.4
NetR713_1: R713.1 S7.1 S7.2
NetR714_2: R714.2 S7.3 S7.4
NetR738_1: R738.1 R739.1 U35_I2C_Expander_PWR_CLK.13
NetR740_1: R740.1 R741.1 U35_I2C_Expander_PWR_CLK.12
NetR742_1: R742.1 R743.1 U35_I2C_Expander_PWR_CLK.11
NetR749_1: R749.1 U35_I2C_Expander_Main_Rst.20
NetR750_1: R750.1 U35_I2C_Expander_Main_Rst.21
NetR751_1: R751.1 U35_I2C_Expander_Main_Rst.22
NetR752_1: R752.1 U35_I2C_Expander_Main_Rst.23
NetR753_1: R753.1 U3_I2C_Bridge_PCIE.24 U35_I2C_Expander_Main_Rst.25
NetR754_1: R754.1 U35_I2C_Expander_Main_Rst.26 U35_I2C_Expander_PWR_CLK.14
NetR758_1: R758.1 R759.1 U35_I2C_Expander_Main_Rst.13 | length 7
  L1 w0.254: 29.641,722.404 30.371,722.404 31.571,723.604 33.229,723.604 33.435,723.398 33.435,722.754 34.625,722.754 34.634,722.744 35.425,722.744
NetR760_1: R760.1 R761.1 U35_I2C_Expander_Main_Rst.12 | length 5.3
  L1 w0.254: 33.435,721.763 v2(34.512,721.763) 34.517,721.758 35.42,721.758 35.425,721.754
  L14 (Sign) w0.254: 31.168,721.763 v2(34.512,721.763)
NetR762_1: R762.1 R763.1 U35_I2C_Expander_Main_Rst.11 | length 7.2
  L1 w0.254: 29.641,721.104 30.416,721.104 31.716,719.804 33.229,719.804 33.434,720.008 33.434,720.756 34.625,720.756 34.634,720.747 35.425,720.747
NetR768_1: R768.1
NetR769_1: R769.1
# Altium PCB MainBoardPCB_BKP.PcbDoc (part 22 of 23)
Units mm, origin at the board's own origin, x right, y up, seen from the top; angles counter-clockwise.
Board outline 258.95 x 308.86 mm, 16 copper layers (L1, L2 (GND), L3 (Sign), L4 (GND), L5 (Sign), L6 (PWR/GND), L7(PWR/GND), L8 (Plane_GND), L9 (PWR/GND), L10 (PWR/GND), L11 (PWR/GND), L12 (Sign), L13 (GND), L14 (Sign), L15 (GND), L16), stack 2.502 mm thick; 2361 components, 1770 nets, 8410 pads, 3259 vias.
Unrouted connection lines stored in the file: 4700.

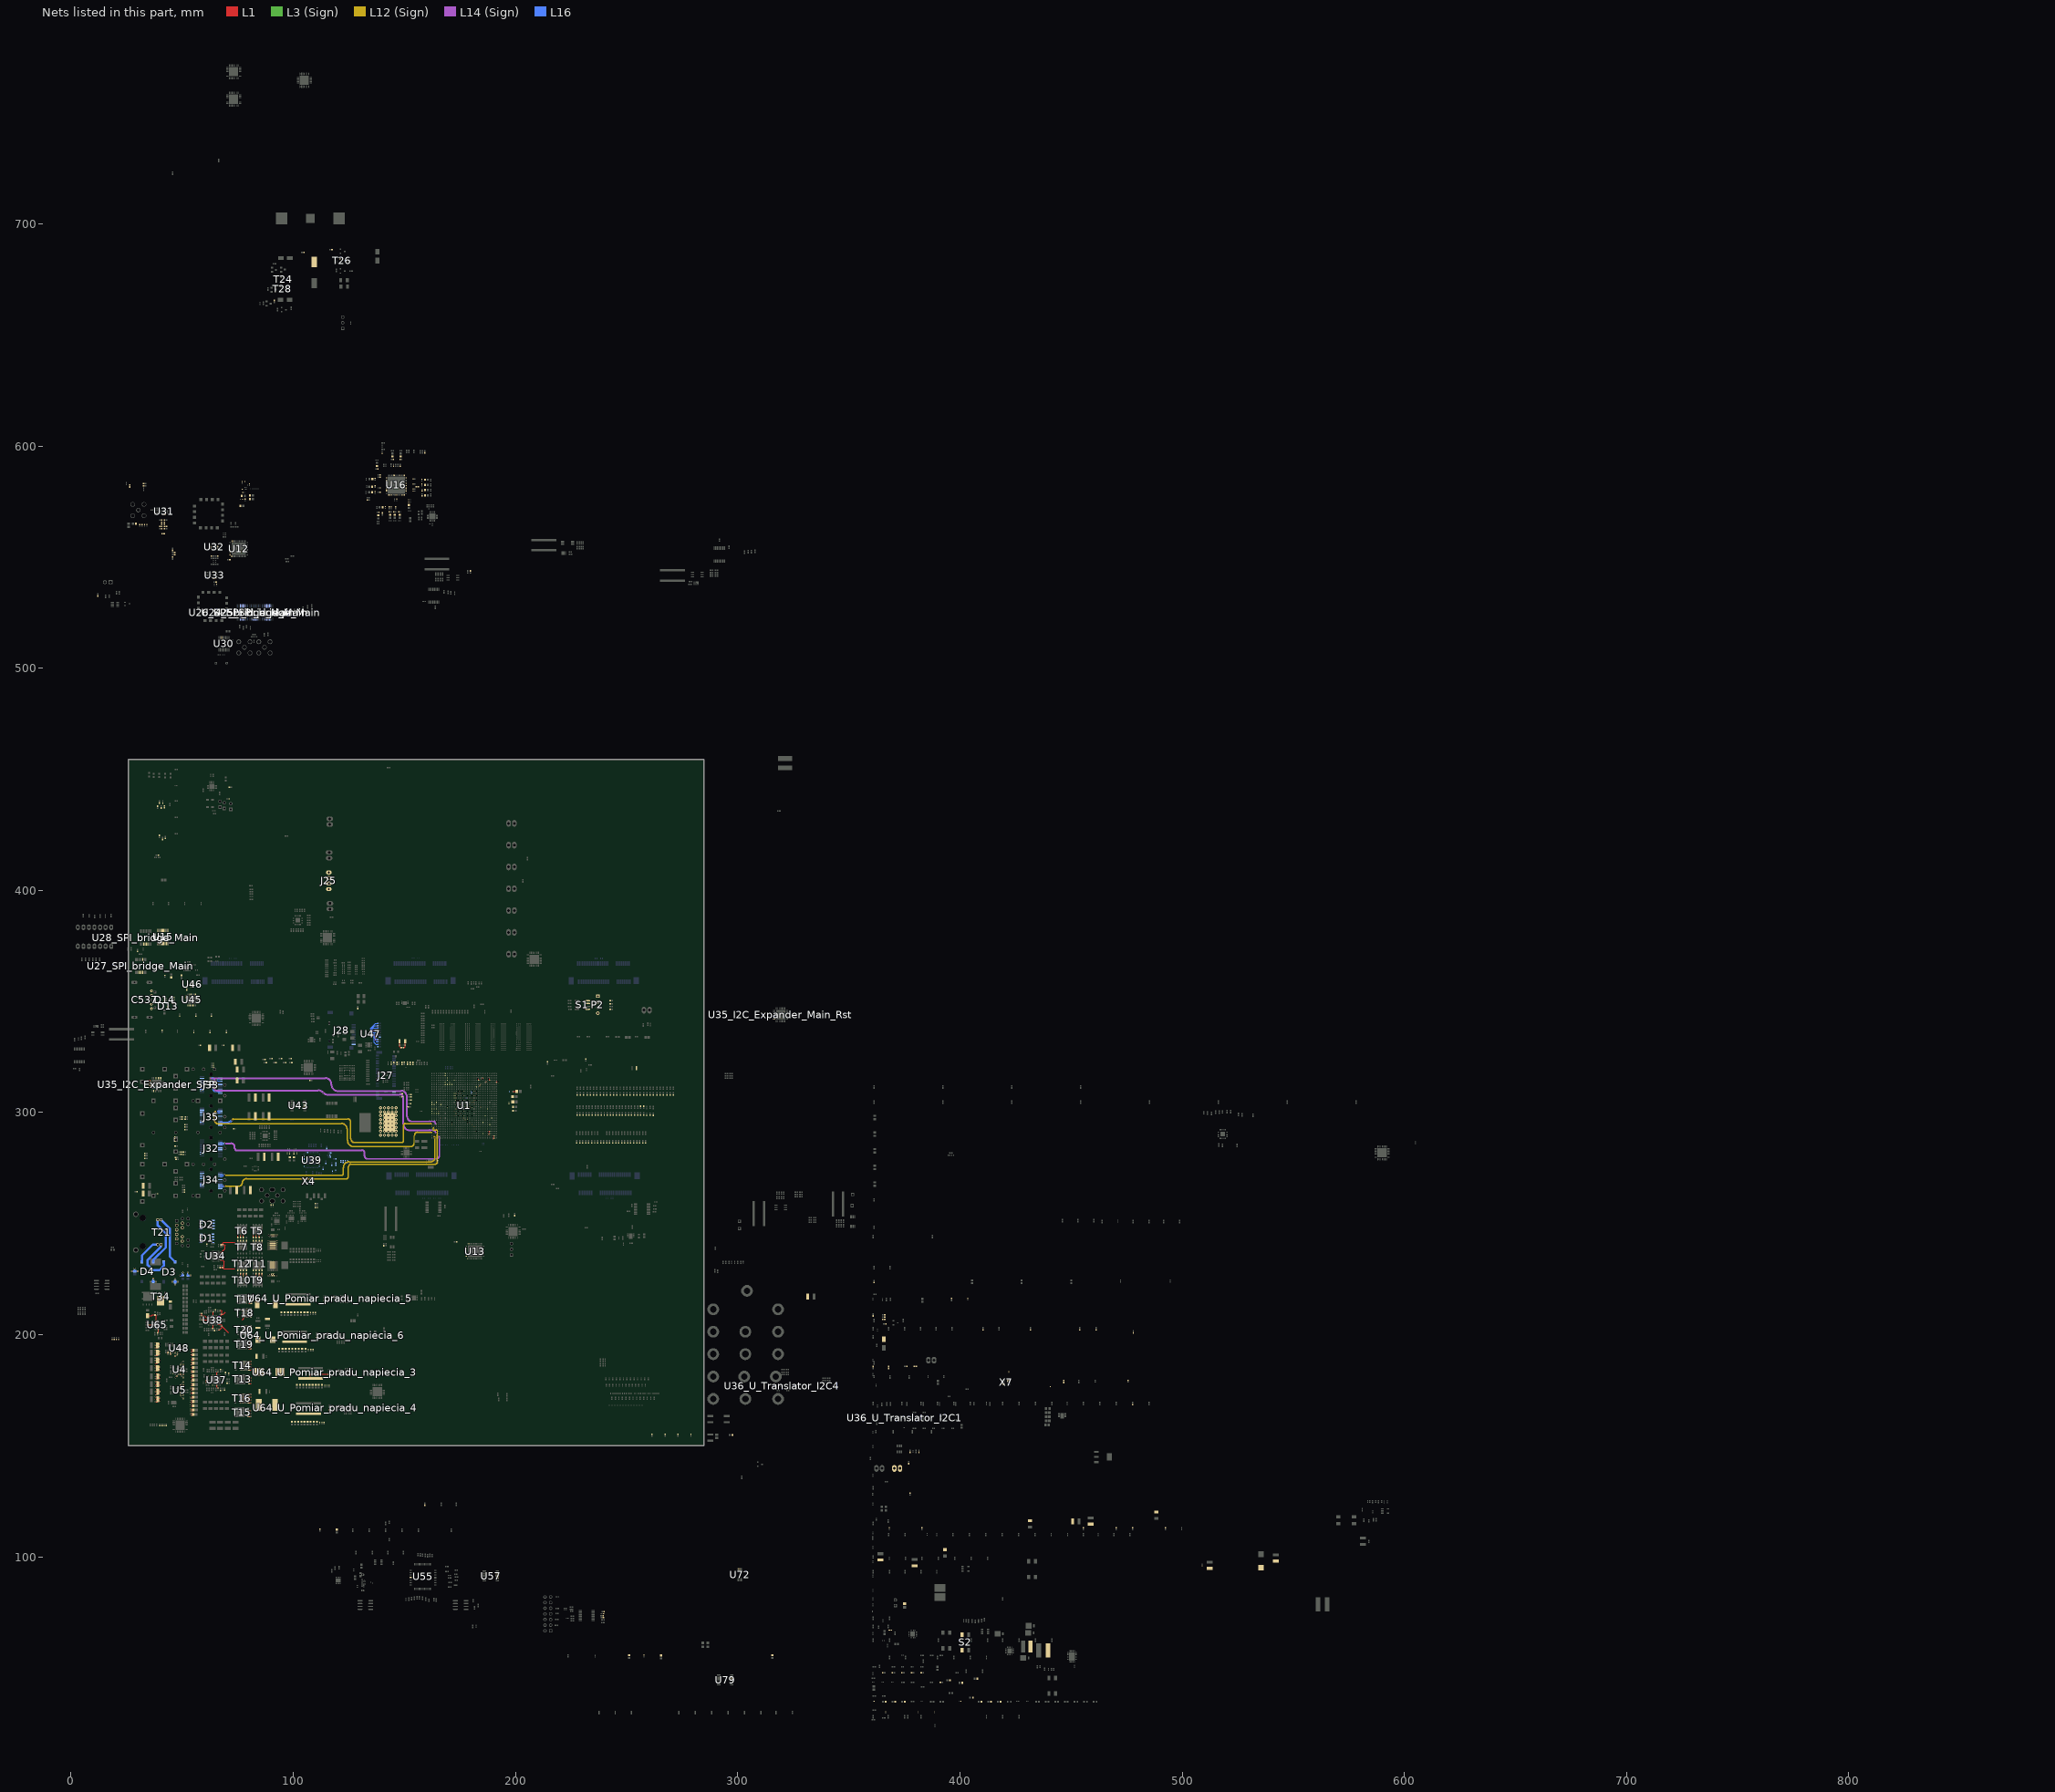
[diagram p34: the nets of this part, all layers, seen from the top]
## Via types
v1: diameter 0.5, hole 0.2, L1 to L16, tented both sides, 1212 vias
v2: diameter 0.5, hole 0.2, L1 to L16, 476 vias
v3: diameter 0.5/0.35/0.35/0.35/0.35/0.35/0.35/0.35/0.35/0.35/0.35/0.35/0.35/0.35/0.35/0.5 (per signal layer), hole 0.15, L1 to L16, tented both sides, 463 vias
v4: diameter 0.35/0/0.35 (per signal layer), hole 0.127, L1 to L3 (Sign), tented both sides, 282 vias
v5: diameter 0.5/0.35/0.35/0.35/0.35/0.35/0.35/0.35/0.35/0.35/0.35/0.35/0.35/0.35/0.35/0.5 (per signal layer), hole 0.2, L1 to L16, tented both sides, 222 vias
v6: diameter 0.8, hole 0.4, L1 to L16, tented both sides, 168 vias
v7: diameter 2.54, hole 1.02, L1 to L16, 113 vias
v8: diameter 1.4, hole 0.5, L1 to L16, tented both sides, 80 vias
v9: diameter 0.5/0/0.5 (per signal layer), hole 0.2, L14 (Sign) to L16, tented both sides, 52 vias
v10: diameter 0.35, hole 0.127, L1 to L2 (GND), tented both sides, 36 vias
v11: diameter 0.35, hole 0.127, L1 to L16, tented both sides, 16 vias
v12: diameter 0.4, hole 0.2, L1 to L16, 16 vias
v13: diameter 0.25, hole 0.2, L1 to L16, 16 vias
v14: diameter 0.3, hole 0.2, L1 to L16, 15 vias
v15: diameter 0.35/0/0.35 (per signal layer), hole 0.127, L1 to L3 (Sign), 12 vias
v16: diameter 0.45, hole 0.15, L1 to L16, 12 vias
v17: diameter 0.5/0.35/0.35/0.35/0.35/0.35/0.35/0.35/0.35/0.35/0.35/0.35/0.35/0.35/0.35/0.45 (per signal layer), hole 0.15, L1 to L16, tented both sides, 10 vias
v18: diameter 0.2/0/0.2 (per signal layer), hole 0.1, L1 to L3 (Sign), tented both sides, 9 vias
v19: diameter 0.4, hole 0.1, L1 to L16, 7 vias
v20: diameter 1.15, hole 1.15, L1 to L16, 6 vias
v21: diameter 1.65, hole 1.65, L1 to L16, 6 vias
v22: diameter 0.5, hole 0.2, L3 (Sign) to L6 (PWR/GND), tented both sides, 6 vias
v23: diameter 0.35/0/0.35 (per signal layer), hole 0.127, L14 (Sign) to L16, tented both sides, 5 vias
v24: diameter 0.2, hole 0.1, L1 to L16, 4 vias
v25: diameter 0.4, hole 0.2, L1 to L16, tented both sides, 2 vias
v26: diameter 0.4, hole 0.15, L1 to L16, 2 vias
v27: diameter 0.5/0.35/0.35/0.35/0.35/0.35/0.35/0.35/0.35/0.35/0.35/0.35/0.35/0.35/0.35/0.5 (per signal layer), hole 0.15, L1 to L16, 2 vias
v28: diameter 0.35, hole 0.127, L3 (Sign) to L6 (PWR/GND), tented both sides, 2 vias
v29: diameter 5.5, hole 3.5, L1 to L16, 1 vias
v30: diameter 0.5/0.35/0.35/0.35/0.35/0.35/0.35/0.35/0.35/0.35/0.35/0.35/0.35/0.35/0.35/0.5 (per signal layer), hole 0.2, L1 to L16, 1 vias
v31: diameter 0.35/0.35/0.35 (per signal layer), hole 0.127, L1 to L3 (Sign), tented both sides, 1 vias
v32: diameter 0.45/0/0.45 (per signal layer), hole 0.15, L1 to L3 (Sign), tented both sides, 1 vias
v33: diameter 0.45/0/0.45 (per signal layer), hole 0.2, L14 (Sign) to L16, tented both sides, 1 vias
v34: diameter 0.35, hole 0.127, L2 (GND) to L3 (Sign), 1 vias
v35: diameter 0.35, hole 0.127, L1 to L2 (GND), 1 vias

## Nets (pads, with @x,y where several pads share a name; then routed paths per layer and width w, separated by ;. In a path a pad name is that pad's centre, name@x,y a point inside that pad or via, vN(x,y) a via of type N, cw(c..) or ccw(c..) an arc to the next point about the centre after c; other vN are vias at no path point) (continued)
SFP0_Tx_N: J32.12 U1.D1 | length 113
  L14 (Sign) w0.076: v3(165.397,288.539) 165.397,288.754 cw(c165.544,288.754) 165.544,288.902 165.568,288.902 cw(c165.568,288.722) 165.748,288.722 165.748,287.539 ccw(c165.748,287.487) 165.696,287.487
  L14 (Sign) w0.08: v9(69.139,286.347) ccw(c69.249,286.347) 69.249,286.237 72.056,286.237 cw(c72.056,284.404) 73.889,284.404 73.889,283.844 ccw(c74.562,283.844) 74.562,283.171 130.962,283.171 cw(c130.962,281.825) 132.309,281.825 132.309,280.365 ccw(c133.274,280.365) 133.274,279.4 164.313,279.4 ccw(c164.313,280.783) 165.696,280.783 165.696,287.487
  L16 w0.081: J32.12@67.104,286.447 68.038,286.447 cw(c68.038,286.339) 68.145,286.339 69.139,286.339 v9(69.139,286.347)
SFP0_Tx_P: J32.13 U1.D2 | length 114
  L14 (Sign) w0.076: v3(165.397,289.539) 165.397,289.325 ccw(c165.544,289.325) 165.544,289.177 165.568,289.177 cw(c165.568,288.722) 166.023,288.722 166.023,287.539 cw(c166.023,287.487) 166.075,287.487
  L14 (Sign) w0.08: v9(69.139,285.747) cw(c69.249,285.747) 69.249,285.857 72.056,285.857 cw(c72.056,284.404) 73.509,284.404 73.509,283.844 ccw(c74.562,283.844) 74.562,282.791 130.962,282.791 cw(c130.962,281.825) 131.929,281.825 131.929,280.365 ccw(c133.274,280.365) 133.274,279.02 164.313,279.02 ccw(c164.313,280.783) 166.075,280.783 166.075,287.487
  L16 w0.081: J32.13@67.104,285.647 68.038,285.647 ccw(c68.038,285.754) 68.145,285.754 69.139,285.754 v9(69.139,285.747)
SFP0_TxDis: J32.3 R68.1 U35_I2C_Expander_SFP.3
SFP0_TxF: J32.2 R67.1 U35_I2C_Expander_SFP.2
SFP0_VccR: C37.2 C38.1 J32.15 L1.2
SFP0_VccT: C39.2 C40.1 J32.16 L2.2
SFP1_ABS: J33.6 R135.1
SFP1_LOS: J33.8 R136.1 U35_I2C_Expander_SFP.24
SFP1_RS0: J33.7 R142.1 R144.2
SFP1_RS1: J33.9 R141.1 R143.2
SFP1_Rx_N: J33.19 U1.C7 | length 127.7
  L14 (Sign) w0.076: 161.345,295.858 ccw(c161.345,295.91) 161.397,295.91 163.512,295.91 cw(c163.512,295.678) 163.745,295.678 163.745,295.266 ccw(c164.109,295.266) 164.109,294.902 cw(c164.109,294.614) 164.397,294.614 v3(164.397,294.539)
  L14 (Sign) w0.08: v9(62.509,315.141) cw(c62.619,315.141) 62.619,315.251 114.452,315.251 cw(c114.452,312.711) 116.992,312.711 116.992,312.477 ccw(c119.912,312.477) 119.912,309.557 148.438,309.557 cw(c148.438,307.017) 150.978,307.017 150.978,298.26 ccw(c153.379,298.26) 153.379,295.858 161.345,295.858
  L16 w0.081: v9(62.509,315.141) 62.509,315.15 63.335,315.15 cw(c63.335,314.639) 63.846,314.639 63.846,310.325 ccw(c64.714,310.325) 64.714,309.456 66.064,309.456 ccw(c66.173,309.456) 66.173,309.347 J33.19@67.104,309.347
SFP1_Rx_P: J33.18 U1.C8 | length 127.7
  L14 (Sign) w0.076: 161.345,296.238 cw(c161.345,296.186) 161.397,296.186 163.512,296.186 cw(c163.512,295.678) 164.02,295.678 164.02,295.266 ccw(c164.109,295.266) 164.109,295.177 ccw(c164.109,295.465) 164.397,295.465 v3(164.397,295.539)
  L14 (Sign) w0.08: v9(62.509,315.741) ccw(c62.619,315.741) 62.619,315.631 114.452,315.631 cw(c114.452,312.711) 117.372,312.711 117.372,312.477 ccw(c119.912,312.477) 119.912,309.937 148.438,309.937 cw(c148.438,307.017) 151.357,307.017 151.357,298.26 ccw(c153.379,298.26) 153.379,296.238 161.345,296.238
  L16 w0.081: v9(62.509,315.741) 62.509,315.732 63.335,315.732 cw(c63.335,314.639) 64.427,314.639 64.427,310.325 ccw(c64.714,310.325) 64.714,310.037 66.064,310.037 cw(c66.173,310.037) 66.173,310.147 J33.18@67.104,310.147
SFP1_Tx_N: J33.12 U1.C3 | length 123.1
  L14 (Sign) w0.076: 161.345,291.845 ccw(c161.345,291.897) 161.397,291.897 163.402,291.897 cw(c163.402,291.554) 163.745,291.554 163.745,291.431 ccw(c164.274,291.431) 164.274,290.902 cw(c164.274,290.779) 164.397,290.779 v3(164.397,290.539)
  L14 (Sign) w0.08: v9(65.354,314.847) cw(c65.244,314.847) 65.244,314.737 64.859,314.737 ccw(c64.859,314.026) 64.149,314.026 64.149,311.074 ccw(c65.481,311.074) 65.481,309.741 111.278,309.741 cw(c111.278,307.201) 113.074,308.998 113.312,308.76 ccw(c115.329,310.777) 115.329,307.924 147.968,307.924 cw(c147.968,306.475) 149.417,306.475 149.417,294.765 ccw(c152.337,294.765) 152.337,291.845 161.345,291.845
  L16 w0.081: v9(65.354,314.847) 65.354,314.837 66.064,314.837 cw(c66.173,314.837) 66.173,314.947 J33.12@67.104,314.947
SFP1_Tx_P: J33.13 U1.C4 | length 121.9
  L14 (Sign) w0.076: 161.345,292.225 cw(c161.345,292.172) 161.397,292.172 163.402,292.172 cw(c163.402,291.554) 164.02,291.554 164.02,291.431 ccw(c164.274,291.431) 164.274,291.177 ccw(c164.274,291.3) 164.397,291.3 v3(164.397,291.539)
  L14 (Sign) w0.08: v9(65.354,314.247) ccw(c65.244,314.247) 65.244,314.357 64.859,314.357 ccw(c64.859,314.026) 64.529,314.026 64.529,311.074 ccw(c65.481,311.074) 65.481,310.121 111.279,310.121 cw(c111.279,307.203) 113.342,309.267 113.578,309.031 ccw(c115.333,310.786) 115.333,308.304 147.968,308.304 cw(c147.968,306.475) 149.796,306.475 149.796,294.765 ccw(c152.337,294.765) 152.337,292.225 161.345,292.225
  L16 w0.081: v9(65.354,314.247) 65.354,314.256 66.064,314.256 ccw(c66.173,314.256) 66.173,314.147 J33.13@67.104,314.147
SFP1_TxDis: J33.3 R138.1 U35_I2C_Expander_SFP.23
SFP1_TxF: J33.2 R137.1 U35_I2C_Expander_SFP.22 | length 1.2
  L1 w0.2: 34.506,314.579 34.525,314.599 U35_I2C_Expander_SFP.22@35.669,314.599
SFP1_VccR: C207.2 C208.1 J33.15 L3.2
SFP1_VccT: C209.2 C210.1 J33.20 L4.2
SFP2_ABS: J34.6 R145.1
SFP2_LOS: J34.8 R146.1 U35_I2C_Expander_SFP.27
SFP2_RS0: J34.7 R152.1 R154.2
SFP2_RS1: J34.9 R151.1 R153.2
SFP2_Rx_N: J34.19 U1.B5 | length 123.6
  L12 (Sign) w0.073: v1(69.113,266.697) cw(c69.314,266.697) 69.314,266.897 75.876,266.897 ccw(c75.876,268.097) 77.076,268.097 cw(c79.048,268.097) 79.048,270.069 123.698,270.069 ccw(c123.698,271.39) 125.019,271.39 125.019,275.73 cw(c125.924,275.73) 125.924,276.635 163.855,276.635 ccw(c163.855,277.787) 165.008,277.787 165.008,287.539 165.008,291.579 ccw(c164.424,291.579) 164.424,292.163 163.258,292.163 cw(c163.258,292.417) 163.005,292.417 163.005,292.647 cw(c163.297,292.647) 163.297,292.939 cw(c163.297,292.839) 163.397,292.839 v3(163.397,292.539)
  L16 w0.081: J34.19@67.104,266.597 68.045,266.597 ccw(c68.045,266.697) 68.145,266.697 v1(69.113,266.697)
SFP2_Rx_P: J34.18 U1.B6 | length 123.6
  L12 (Sign) w0.073: v1(69.113,267.297) ccw(c69.314,267.297) 69.314,267.096 75.876,267.096 ccw(c75.876,268.097) 76.877,268.097 cw(c79.048,268.097) 79.048,270.269 123.698,270.269 ccw(c123.698,271.39) 124.819,271.39 124.819,275.73 cw(c125.924,275.73) 125.924,276.835 163.855,276.835 ccw(c163.855,277.787) 164.808,277.787 164.808,287.539 164.808,291.579 ccw(c164.424,291.579) 164.424,291.964 163.258,291.964 cw(c163.258,292.417) 162.805,292.417 162.805,292.647 cw(c163.297,292.647) 163.297,293.139 ccw(c163.297,293.24) 163.397,293.24 v3(163.397,293.539)
  L16 w0.081: J34.18@67.104,267.397 68.045,267.397 cw(c68.045,267.297) 68.145,267.297 v1(69.113,267.297)
SFP2_Tx_N: J34.12 U1.B1 | length 112.3
  L12 (Sign) w0.073: v1(69.101,272.097) ccw(c69.301,272.097) 69.301,271.896 121.907,271.896 ccw(c121.907,272.395) 122.406,272.395 122.406,275.162 cw(c125.146,275.162) 125.146,277.901 161.684,277.901 ccw(c161.684,280.01) 163.792,280.01 163.792,287.539 163.792,288.724 ccw(c163.576,288.724) 163.576,288.939 163.51,288.939 ccw(c163.51,288.826) 163.397,288.826 v3(163.397,288.539)
  L16 w0.081: J34.12@67.104,272.197 68.038,272.197 cw(c68.038,272.089) 68.145,272.089 69.101,272.089 v1(69.101,272.097)
SFP2_Tx_P: J34.13 U1.B2 | length 112.9
  L12 (Sign) w0.073: v1(69.101,271.497) cw(c69.301,271.497) 69.301,271.697 121.907,271.697 ccw(c121.907,272.395) 122.606,272.395 122.606,275.162 cw(c125.146,275.162) 125.146,277.702 161.684,277.702 ccw(c161.684,280.01) 163.992,280.01 163.992,287.539 163.992,288.724 ccw(c163.576,288.724) 163.576,289.139 163.51,289.139 cw(c163.51,289.252) 163.397,289.252 v3(163.397,289.539)
  L16 w0.081: J34.13@67.104,271.397 68.038,271.397 ccw(c68.038,271.504) 68.145,271.504 69.101,271.504 v1(69.101,271.497)
SFP2_TxDis: J34.3 R148.1 U35_I2C_Expander_SFP.26
SFP2_TxF: J34.2 R147.1 U35_I2C_Expander_SFP.25
SFP2_VccR: C211.2 C212.1 J34.15 L5.2
SFP2_VccT: C213.2 C214.1 J34.20 L6.2
SFP3_ABS: J35.6 R155.1
SFP3_LOS: J35.8 R156.1 U35_I2C_Expander_SFP.19
SFP3_RS0: J35.7 R162.1 R164.2
SFP3_RS1: J35.9 R161.1 R163.2
SFP3_Rx_N: J35.19 U1.A7 | length 113.4
  L12 (Sign) w0.073: v1(72.612,296.361) cw(c73.296,296.361) 72.812,296.844 cw(c73.015,296.642) 73.015,296.928 74.282,296.928 124.496,296.928 cw(c124.496,295.631) 125.793,295.631 125.793,288.154 ccw(c127.495,288.154) 127.495,286.452 148.831,286.452 ccw(c148.831,287.388) 149.767,287.388 149.767,294.373 cw(c150.326,294.373) 150.326,294.932 161.397,294.932 ccw(c161.435,294.932) 161.435,294.894
  L12 (Sign) w0.076: 161.435,294.894 162.255,294.894 cw(c162.255,294.752) 162.397,294.752 v3(162.397,294.539)
  L16 w0.081: J35.19@67.104,295.097 68.037,295.097 ccw(c68.037,295.204) 68.145,295.204 70.152,295.204 ccw(c70.152,298.326) 72.359,296.118 72.602,296.361 v1(72.612,296.361)
SFP3_Rx_P: J35.18 U1.A8 | length 113.1
  L12 (Sign) w0.073: v1(72.188,296.785) ccw(c72.188,297.469) 72.671,296.985 72.673,296.987 cw(c73.013,296.646) 73.013,297.127 74.282,297.127 124.496,297.127 cw(c124.496,295.631) 125.993,295.631 125.993,288.154 ccw(c127.495,288.154) 127.495,286.652 148.831,286.652 ccw(c148.831,287.388) 149.568,287.388 149.568,294.373 cw(c150.326,294.373) 150.326,295.132 161.397,295.132 cw(c161.435,295.132) 161.435,295.17
  L12 (Sign) w0.076: 161.435,295.17 162.255,295.17 ccw(c162.255,295.311) 162.397,295.311 v3(162.397,295.539)
  L16 w0.081: J35.18@67.104,295.897 68.037,295.897 cw(c68.037,295.789) 68.145,295.789 70.15,295.789 ccw(c70.15,298.329) 71.946,296.533 72.188,296.775 v1(72.188,296.785)
SFP3_Tx_N: J35.12 U1.A3 | length 118.7
  L12 (Sign) w0.073: v1(65.443,300.597) cw(c65.243,300.597) 65.243,300.396 64.986,300.396 ccw(c64.986,299.702) 64.291,299.702 64.291,296.777 ccw(c66.171,296.777) 66.171,294.897 121.679,294.897 cw(c121.679,292.357) 124.219,292.357 124.219,287.439 ccw(c126.958,287.439) 126.958,284.7 152.984,284.7 ccw(c152.984,286.296) 154.581,286.296 154.581,289.633 cw(c155.892,289.633) 155.892,290.944 161.397,290.944 162.204,290.944 cw(c162.204,290.752) 162.397,290.752 v3(162.397,290.539)
  L16 w0.081: v1(65.443,300.597) 65.443,300.589 66.064,300.589 cw(c66.171,300.589) 66.171,300.697 J35.12@67.104,300.697
SFP3_Tx_P: J35.13 U1.A4 | length 118.1
  L12 (Sign) w0.073: v1(65.443,299.997) ccw(c65.243,299.997) 65.243,300.197 64.986,300.197 ccw(c64.986,299.702) 64.491,299.702 64.491,296.777 ccw(c66.171,296.777) 66.171,295.097 121.679,295.097 cw(c121.679,292.357) 124.418,292.357 124.418,287.439 ccw(c126.958,287.439) 126.958,284.899 152.984,284.899 ccw(c152.984,286.296) 154.381,286.296 154.381,289.633 cw(c155.892,289.633) 155.892,291.144 161.397,291.144 162.204,291.144 ccw(c162.204,291.337) 162.397,291.337 v3(162.397,291.539)
  L16 w0.081: v1(65.443,299.997) 65.443,300.004 66.064,300.004 ccw(c66.171,300.004) 66.171,299.897 J35.13@67.104,299.897
SFP3_TxDis: J35.3 R158.1 U35_I2C_Expander_SFP.18
SFP3_TxF: J35.2 R157.1 U35_I2C_Expander_SFP.17
SFP3_VccR: C215.2 C216.1 J35.15 L7.2
SFP3_VccT: C217.2 C218.1 J35.20 L8.2
SFP_INT0: R854.2 U35_I2C_Expander_SFP.16
SFP_INT1: R857.2 U35_I2C_Expander_SFP.15
SFP_IO_nReset: R756.1 U35_I2C_Expander_Main_Rst.28 U35_I2C_Expander_SFP.14
SGMI_C_Rx_N: C484.1 U1.G26
SGMI_C_Rx_P: C483.1 U1.G25
SGMI_C_Tx_N: C482.1 U1.G30
SGMI_C_Tx_P: C479.1 U1.G29
SGMI_CLK_Out_N: R320.1 R321.1 R326.2 U39.34
SGMI_CLK_Out_P: R319.1 R321.2 R325.2 U39.33
SGMI_Rx_N: C484.2 U39.28
SGMI_Rx_P: C483.2 U39.27
SGMI_Tx_N: C482.2 R323.1 R328.2 U39.36
SGMI_Tx_P: C479.2 R322.1 R327.2 U39.35
Si53323_1_Q1_N: C330.1 R249.1 U31.9
Si53323_1_Q1_P: C325.1 R246.2 U31.10
Si53323_1_Q2_LVDS_N: C725.2 R386.2 R387.2 U1.AG3 | length 0.7
  L1 w0.116: v4(187.909,290.052) U1.AG3@188.397,290.539
Si53323_1_Q2_LVDS_P: C724.2 U1.AG4 | length 0.7
  L1 w0.116: v4(187.909,291.052) U1.AG4@188.397,291.539
Si53323_1_Q2_N: R301.1 R385.2 U31.12
Si53323_1_Q2_P: R291.1 R384.2 U31.11
Si53323_2_CLK1_N: C330.2 R245.2 R248.2 R251.2 U32.4
Si53323_2_CLK1_P: C325.2 R245.1 R247.2 R250.2 U32.3
Si53323_2_Q1_N: C44.2 R79.2 U32.10
Si53323_2_Q1_P: C43.2 R76.1 U32.9
Si53323_2_Q2_LVDS_N: C727.2 R486.2 R487.2 U1.A16
Si53323_2_Q2_LVDS_P: C726.2 U1.A17
Si53323_2_Q2_N: R483.1 R485.2 U32.12
Si53323_2_Q2_P: R482.1 R484.2 U32.11
SPI1_CLK: J25.1 R803.1 U15.14 U24_SPI_bridge_Main.3 U25_SPI_bridge_Main.3 U26_SPI_bridge_Main.3 U27_SPI_bridge_Main.3 U28_SPI_bridge_Main.3
SPI1_CS: J25.4 R123.1 R124.1 R806.1 U15.11 U24_SPI_bridge_Main.6 U25_SPI_bridge_Main.6 U26_SPI_bridge_Main.6 U27_SPI_bridge_Main.6 U28_SPI_bridge_Main.6
SPI1_MISO: J25.3 R807.1 U15.13 U24_SPI_bridge_Main.4 U25_SPI_bridge_Main.4 U26_SPI_bridge_Main.4 U27_SPI_bridge_Main.4 U28_SPI_bridge_Main.4
SPI1_MOSI: J25.2 R808.1 U15.12 U24_SPI_bridge_Main.5 U25_SPI_bridge_Main.5 U26_SPI_bridge_Main.5 U27_SPI_bridge_Main.5 U28_SPI_bridge_Main.5
SPI_05028_CS: R125.2 R127.1 R139.2 R912.1 U16.24
SPI_05028_MISO: R1.1 R2.2 R133.1 U16.60
SPI_6952_0_CLK: U12.50 U26_SPI_bridge_Main.14
SPI_6952_0_CS: R236_SPI_bridge_Main.1 U12.1 U26_SPI_bridge_Main.11
SPI_6952_0_MISO: U12.51 U26_SPI_bridge_Main.13
SPI_6952_0_MOSI: U12.52 U26_SPI_bridge_Main.12
SPI_6952_1_CLK: U13.50 U25_SPI_bridge_Main.14
SPI_6952_1_CS: R233_SPI_bridge_Main.1 U13.1 U25_SPI_bridge_Main.11
SPI_6952_1_MISO: U13.51 U25_SPI_bridge_Main.13
SPI_6952_1_MOSI: U13.52 U25_SPI_bridge_Main.12
SPI_DAC_CS: R238_SPI_bridge_Main.1 U27_SPI_bridge_Main.11 U30.14
SPI_FPGA_CLK: R905.2 U15.3
SPI_FPGA_CLK_R: R905.1 U1.C14
SPI_FPGA_CS: R365.2 R908.2 U15.6
SPI_FPGA_CS_R: R908.1 U1.A13
SPI_FPGA_MISO: R906.2 U15.4
SPI_FPGA_MISO_R: R906.1 U1.B14
SPI_FPGA_MOSI: R907.2 U15.5
SPI_FPGA_MOSI_R: R907.1 U1.A14
SPI_FPGA_nOE: R75.2 U15.9
SPI_FPGA_OE_R: R903.1 U1.D12
SS1_1: C639.2 U37.28 | length 1.7
  L1 w0.254: U37.28@65.675,181.817 65.675,182.903 C639.2@66.141,183.369
SS1_2: C647.2 U38.28 | length 1.6
  L1 w0.254: U38.28@63.953,208.714 C647.2@63.953,210.264
SS2_1: C640.2 U37.13 | length 1.6
  L1 w0.254: U37.13@65.675,177.317 65.675,176.584 66.161,176.097 C640.2@66.161,175.893
SS2_2: C648.2 U38.13 | length 1.5
  L1 w0.254: C648.2@63.741,202.763 63.741,203.154 63.953,203.366 U38.13@63.953,204.214
SUSCLK: J27.60
SW1: C346.2 L9.1 R610.2 R613.2 T5.1 T5.2 T5.3 T6.1 T6.2 T6.3 T7.5 T7.6 T7.7 T7.8 T8.5 T8.6 T8.7 T8.8 U34.24 | length 18.8
  L1 w0.254: U34.24@67.322,237.139 67.657,237.139 69.236,238.718 69.236,240.156 68.922,240.47 C346.2@68.336,240.47 ; R610.2@67.378,240.47 C346.2@68.336,240.47 ; 73.8,241.529 68.669,241.529 68.336,241.196 C346.2@68.336,240.47
  L1 w0.5: T6.1@75.072,243.723 v1(75.072,244.81) ; T6.2@76.342,243.723 v1(76.342,244.81) ; T6.3@77.612,243.723 v1(77.612,244.81) ; T5.1@82.072,243.723 v1(82.072,244.81) ; T5.2@83.342,243.723 v1(83.342,244.81) ; T5.3@84.612,243.723 v1(84.612,244.81)
  other v1: 88.711,238.28 89.517,238.28 90.322,238.28 91.128,238.28 91.934,238.28 92.74,238.28 75.09,238.992 76.342,238.992 77.593,238.992 78.845,238.992 82.09,238.992 83.342,238.992 84.593,238.992 85.845,238.992 88.711,239.086 89.517,239.086 90.322,239.086 91.128,239.086 91.934,239.086 92.74,239.086 88.711,239.892 89.517,239.892 90.322,239.892 91.128,239.892 91.934,239.892 92.74,239.892 75.09,240.244 76.342,240.244 77.593,240.244 78.845,240.244 82.09,240.244 83.342,240.244 84.593,240.244 85.845,240.244 88.711,240.697 89.517,240.697 90.322,240.697 91.128,240.697 91.934,240.697 92.74,240.697 75.09,241.496 76.342,241.496 77.593,241.496 78.845,241.496 82.09,241.496 83.342,241.496 84.593,241.496 85.845,241.496 88.711,241.503 89.517,241.503 90.322,241.503 91.128,241.503 91.934,241.503 92.74,241.503 88.711,242.309 89.517,242.309 90.322,242.309 91.128,242.309 91.934,242.309 92.74,242.309 89.212,244.228 90.018,244.228 90.823,244.228 91.629,244.228 92.435,244.228 88.788,244.811 89.594,244.811 90.4,244.811 91.206,244.811 92.011,244.811 92.817,244.811
SW1_1: C390.2 L11.1 R288.2 R619.2 T13.1 T13.2 T13.3 T14.5 T14.6 T14.7 T14.8 U37.24 | length 7.6
  L1 w0.5: T14.5@80.039,184.15 v1(81.126,184.15) ; T14.6@80.039,185.42 v1(81.126,185.42) ; T14.7@80.039,186.69 v1(81.126,186.69) ; T14.8@80.039,187.96 v1(81.126,187.96) ; T13.1@80.042,178.003 v1(81.129,178.003) ; T13.2@80.042,179.273 v1(81.129,179.273) ; T13.3@80.042,180.543 v1(81.129,180.543)
  other v1: 76.718,184.187 77.97,184.187 79.221,184.187 76.718,185.438 77.97,185.438 79.221,185.438 76.718,186.69 77.97,186.69 79.221,186.69 76.718,187.942 77.97,187.942 79.221,187.942
SW1_2: C431.2 L19.1 R306.2 R625.1 T17.1 T17.2 T17.3 T18.5 T18.6 T18.7 T18.8 U38.24 | length 11.2
  L1 w0.254: U38.24@65.953,208.214 67.293,208.214 67.758,208.68 C431.2@67.758,209.091 ; R625.1@67.001,210.879 67.377,210.879 67.781,210.475 C431.2@67.781,209.114 68.392,209.114 69.532,210.254 ; 77.166,206.68 77.677,207.192 77.677,207.477
  L1 w0.5: v1(79.911,214.079) T17.1@80.998,214.079 ; v1(79.911,215.349) T17.2@80.998,215.349 ; v1(79.911,216.619) T17.3@80.998,216.619
  other v1: 77.677,207.834 78.929,207.834 80.18,207.834 77.677,209.086 78.929,209.086 80.18,209.086 77.677,210.337 78.929,210.337 80.18,210.337 77.677,211.589 78.929,211.589 80.18,211.589
SW2: C350.2 L10.1 R611.2 R616.2 T9.1 T9.2 T9.3 T10.1 T10.2 T10.3 T11.5 T11.6 T11.7 T11.8 T12.5 T12.6 T12.7 T12.8 U34.17 | length 18.5
  L1 w0.254: R611.2@67.113,230.147 67.513,230.147 67.688,230.322 C350.2@68.072,230.322 ; U34.17@67.322,233.639 68.085,233.639 68.854,232.87 68.854,230.471 68.705,230.322 C350.2@68.072,230.322 ; C350.2@68.072,230.317 C350.2@68.072,230.322 ; 73.69,229.73 68.663,229.73 C350.2@68.072,230.322
  L1 w0.5: v1(76.348,226.414) T10.3@76.348,227.501 ; v1(77.618,226.414) T10.2@77.618,227.501 ; v1(78.888,226.414) T10.1@78.888,227.501 ; v1(83.342,226.414) T9.3@83.342,227.501 ; v1(84.612,226.414) T9.2@84.612,227.501 ; v1(85.882,226.414) T9.1@85.882,227.501
  other v1: 88.597,226.45 89.402,226.45 90.208,226.45 91.014,226.45 91.82,226.45 92.625,226.45 88.979,227.033 89.785,227.033 90.59,227.033 91.396,227.033 92.202,227.033 88.674,228.952 89.48,228.952 90.286,228.952 91.091,228.952 91.897,228.952 92.703,228.952 75.108,229.757 76.36,229.757 77.612,229.757 78.863,229.757 82.108,229.757 83.36,229.757 84.612,229.757 85.863,229.757 88.674,229.758 89.48,229.758 90.286,229.758 91.091,229.758 91.897,229.758 92.703,229.758 88.674,230.564 89.48,230.564 90.286,230.564 91.091,230.564 91.897,230.564 92.703,230.564 75.108,231.008 76.36,231.008 77.612,231.008 78.863,231.008 82.108,231.008 83.36,231.008 84.612,231.008 85.863,231.008 88.674,231.369 89.48,231.369 90.286,231.369 91.091,231.369 91.897,231.369 92.703,231.369 88.674,232.175 89.48,232.175 90.286,232.175 91.091,232.175 91.897,232.175 92.703,232.175 75.108,232.26 76.36,232.26 77.612,232.26 78.863,232.26 82.108,232.26 83.36,232.26 84.612,232.26 85.863,232.26 88.674,232.981 89.48,232.981 90.286,232.981 91.091,232.981 91.897,232.981 92.703,232.981
SW2_1: C394.2 L12.1 R298.2 R620.2 T15.1 T15.2 T15.3 T16.5 T16.6 T16.7 T16.8 U37.17 | length 7.6
  L1 w0.5: T15.1@79.789,163.201 v1(80.876,163.201) ; T15.2@79.789,164.471 v1(80.876,164.471) ; T15.3@79.789,165.741 v1(80.876,165.741) ; T16.5@79.835,169.38 v1(80.922,169.38) ; T16.6@79.835,170.65 v1(80.922,170.65) ; T16.7@79.835,171.92 v1(80.922,171.92) ; T16.8@79.835,173.19 v1(80.922,173.19)
  other v1: 76.514,169.417 77.766,169.417 79.017,169.417 76.514,170.668 77.766,170.668 79.017,170.668 76.514,171.92 77.766,171.92 79.017,171.92 76.514,173.172 77.766,173.172 79.017,173.172
SW2_2: C435.2 L20.1 R302.1 R316.2 T19.1 T19.2 T19.3 T20.5 T20.6 T20.7 T20.8 U38.17 | length 12.3
  L1 w0.254: U38.17@65.953,204.714 67.394,204.714 67.796,204.312 C435.2@67.796,203.864 ; R302.1@66.453,202.163 66.794,202.163 67.796,203.166 C435.2@67.796,203.864 ; 70.746,200.92 C435.2@67.796,203.864
  L1 w0.5: v1(79.842,193.746) T19.1@80.929,193.746 ; v1(79.842,195.016) T19.2@80.929,195.016 ; v1(79.842,196.286) T19.3@80.929,196.286
  other v1: 77.578,200.189 78.83,200.189 80.081,200.189 77.578,201.44 78.83,201.44 80.081,201.44 77.578,202.692 78.83,202.692 80.081,202.692 77.578,203.944 78.83,203.944 80.081,203.944
SYNC_WR_R: R904.1 U1.C12
TD_A_N: D1.2 D1.7 T21.10 U39.2
TD_A_P: D1.1 D1.8 T21.11 U39.1
TD_B_N: D1.4 D1.5 T21.5 U39.5
TD_B_P: D1.3 D1.6 T21.4 U39.4
TD_C_N: D2.2 D2.7 T21.2 U39.8
TD_C_P: D2.1 D2.8 T21.3 U39.7
TD_D_N: D2.4 D2.5 T21.9 U39.11
TD_D_P: D2.3 D2.6 T21.8 U39.10
TTC_0: R810.1
TTC_3: R804.1
uart0_RxD: R779.1 U57.12
uart0_TxD: R778.1 U57.11
uart1_RxD: R776.1 U57.13
uart1_TxD: R777.1 U57.14
uart_FPGA_RxD_R: R909.1 U1.B12
uart_FPGA_TxD_R: R910.1 U1.A12
US2_FTDI_UART1_RXD: R910.2 U79.13
US2_FTDI_UART1_TXD: R909.2 U79.14
US+_DxN: R279.1 R286.1 U1.V15
  other v5: 179.397,302.539
US+_DxP: R282.1 R283.1 U1.V14
  other v5: 179.397,301.539
US+_GND_PS_ADC: C627.1 C628.1 FB39.2 U1.W21
  other v5: 180.397,308.539
US+_GNDADC: C629.1 C630.1 FB41.2 U1.R14 U1.U14 U1.U15
  other v5: 176.397,301.539 178.397,301.539 178.397,302.539
US+_MGTRref: R173.1 U1.K7
  other v3: 171.397,294.539
US+_MGTRref_K8: R695.2 U1.K8
  other v3: 171.397,295.539
US+_MGTVccAux: C605.2 C606.2 C607.2 C610.2 C611.2 C756.2 C759.2 L16.2 R212.2 R363.1 R364.1 R365.1 R515.1 R522.1 R523.2 R531.1 R546.2 R548.1 R549.2 R551.1 R552.2 R554.1 R555.2 R557.1 R607.2 R659.1 R660.2 R661.1 R662.2 R663.1 R664.2 R735.1 R736.2 R765.1 R766.2 R817.1 R818.2 R820.1 R821.2 R823.1 R824.2 R847.1 R848.2 R849.1 R850.2 R852.1 R853.2 R855.1 R856.2 R858.1 R859.2 R861.2 R921.1 R922.2 R923.1 R924.2 R925.1 R926.2 R927.1 R928.2 R929.1 R930.2 R931.1 R932.2 R933.1 R934.2 R935.1 R936.2 R937.1 R938.2 R939.1 R940.2 R941.1 R942.2 R943.1 R944.2 R945.1 R946.2 R947.1 R948.2 R949.1 R950.2 R951.1 R952.2 R953.1 R954.2 R955.1 R956.2 R957.1 R958.2 R959.1 R960.2 U1.AA4 U1.AC15 U1.AD3 U1.AD8 U1.AE11 U1.AF14 U1.AG7 U1.AG17 U1.AH10 U1.D13 U1.E10 U1.E16 U1.G10 U1.G12 U1.H15 U1.H25 U1.K25 U1.L27 U15.1 U15.7 U15.8 U15.16 U36_U_Translator_I2C1.2 U36_U_Translator_I2C4.2 U79.15
  other v3: 166.397,297.539 168.397,297.539
  other v5: 182.397,291.539 168.397,299.539 165.397,300.539 169.397,302.539 184.397,302.539 188.397,304.539
US+_POR_OVE: R693.1 U1.Y6
  other v5: 181.397,293.539
US+_Pudc_B: R694.2 R696.1 U1.W7
  other v5: 180.397,294.539
US+_Vcc_PS_ADC: C627.2 C628.2 FB38.2 U1.W22 | length 1.8
  L1 w0.254: v1(198.768,309.397) 198.819,309.448 FB38.2@200.559,309.448
  other v5: 180.397,309.539
US+_Vcc_PS_Batt: B1.1 C747.1 C748.2 R276.1 U1.U20
  other v5: 178.397,307.539
US+_Vcc_PS_DDR_504: C616.2 C617.2 C618.2 C619.2 C620.2 C621.2 C622.2 C753.1 C754.2 C755.2 L18.2 R220.2 U1.AA24 U1.AB27 U1.AC25 U1.AD28 U1.AE26 U1.AG27 U1.AK26 | length 6.7
  L1 w0.116: v4(182.909,315.027) U1.AB27@183.397,314.539 ; v4(183.91,312.052) U1.AC25@184.397,312.539 ; v4(184.91,315.052) U1.AD28@185.397,315.539 ; U1.AE26@186.397,313.539 v4(186.884,314.027) ; v4(187.909,315.027) U1.AG27@188.397,314.539 ; U1.AK26@191.397,313.539 v4(191.884,314.027)
  L3 (Sign) w0.254: v4(182.909,315.027) v22@182.909,315.531 ; v4(183.91,312.052) v22@184.266,312.408 ; v4(184.91,315.052) v22@184.91,315.556 ; v22(187.897,315.544) 187.909,315.531 v4(187.909,315.027) ; v4(191.884,314.027) v22@192.241,313.671
  other v22: 184.266,312.427 192.259,313.67 182.897,315.544 184.897,315.569
US+_Vcc_PS_DDR_PLL: C631.2 C632.2 FB42.2 U1.U18 U1.U19
  other v5: 178.397,305.539 178.397,306.539
US+_Vcc_PS_IntFp: C738.1 C739.1 C740.2 C744.2 C745.2 C751.1 C752.2 C762.1 C763.2 R271.2 R617.2 U1.AA18 U1.AA20 U1.AA21 U1.AA22 U1.L11 U1.L13 U1.L17 U1.M12 U1.M14 U1.M16 U1.M18 U1.N11 U1.N13 U1.N15 U1.N17 U1.P12 U1.P14 U1.P16 U1.R10 U1.R11 U1.R13 U1.R17 U1.T9 U1.T10 U1.T12 U1.T16 U1.U8 U1.U9 U1.U10 U1.U11 U1.U13 U1.U17 U1.V8 U1.V10 U1.V12 U1.V16 U1.V17 U1.V18 U1.V19 U1.W11 U1.W13 U1.W15 U1.W17 U1.W19 U1.W20 U1.Y12 U1.Y14 U1.Y16 U1.Y17 U1.Y18 U1.Y19 U1.Y20 U1.Y22 U72.8 U72.9
  other v3: 178.397,295.539 179.397,295.539 177.397,296.539 178.397,296.539 176.397,297.539 177.397,297.539 178.397,297.539 179.397,297.539 172.397,298.539 174.397,298.539 176.397,298.539 178.397,298.539
  other v5: 180.397,298.539 173.397,299.539 175.397,299.539 177.397,299.539 179.397,299.539 181.397,299.539 172.397,300.539 174.397,300.539 176.397,300.539 178.397,300.539 180.397,300.539 173.397,301.539 175.397,301.539 181.397,301.539 174.397,302.539 180.397,302.539 173.397,303.539 175.397,303.539 177.397,303.539 179.397,303.539 181.397,303.539 172.397,304.539 174.397,304.539 176.397,304.539 178.397,304.539 179.397,304.539 180.397,304.539 181.397,304.539 173.397,305.539 179.397,305.539 181.397,305.539 182.397,305.539 179.397,306.539 180.397,306.539 181.397,306.539 180.397,307.539 181.397,307.539 182.397,307.539 182.397,308.539 181.397,309.539 182.397,309.539
  other v8: 142.777,289.801 144.53,289.801 146.282,289.801 139.272,289.801 141.025,289.801 139.272,291.554 141.025,291.554 142.777,291.554 144.53,291.554 146.282,291.554 142.777,293.306 144.53,293.306 146.282,293.306 139.272,293.306 141.025,293.306 139.272,295.059 141.025,295.059 142.777,295.059 144.53,295.059 146.282,295.059 142.777,296.812 144.53,296.812 146.282,296.812 139.272,296.812 141.025,296.812 139.272,298.564 141.025,298.564 142.777,298.564 144.53,298.564 146.282,298.564 142.777,300.317 144.53,300.317 146.282,300.317 139.272,300.317 141.025,300.317 139.272,302.07 141.025,302.07 142.777,302.069 144.53,302.069 146.282,302.069
US+_Vcc_PS_IntFpDDR: C764.1 C765.2
US+_VccADC: C629.2 C630.2 FB40.2 U1.R15
  other v5: 176.397,302.539
US+_VN: J29.1 U1.T15
  other v5: 177.397,302.539
US+_VP: J29.2 U1.T14
  other v5: 177.397,301.539
US_PADI: C535.2 R374.1 U1.M21 X5.1 | length 3.5
  L1 w0.2: X5.1@147.843,332.125 X5.1@147.823,332.105 C535.2@147.823,330.314 147.823,329.597 148.198,329.222 R374.1@148.623,329.222
  other v5: 173.397,308.539
US_PADO: C536.2 R374.2 U1.N21 X5.2 | length 3.5
  L1 w0.2: R374.2@149.523,329.222 149.948,329.222 150.323,329.597 C536.2@150.323,330.314 X5.2@150.323,332.105
  other v5: 174.397,308.539
US_PS_DONE: R357.1 U1.N22 U43.6
  other v5: 174.397,309.539
US_PS_Err_Out: U1.R22 U43.3
  other v5: 176.397,309.539
US_PS_Err_Status: U1.R20 U43.4
  other v5: 176.397,307.539
US_PS_Init_B: R353.2 U1.N18 U43.5
  other v5: 174.397,305.539
US_PS_JTAG_TCK: R346.2 R1028.2 U1.L19
US_PS_JTAG_TDI: R347.2 R1026.2 U1.L20
US_PS_JTAG_TDO: R1029.2 U1.M20
  other v5: 173.397,307.539
US_PS_JTAG_TMS: R348.2 R1027.2 U1.L21
US_PS_Mode0: P2.4 R349.1 S1.1 U1.R18
  other v5: 176.397,305.539
US_PS_Mode2: P2.2 R351.1 S1.3 U1.P21
  other v5: 175.397,308.539
US_PS_Mode3: P2.1 R352.1 S1.4 U1.P22
  other v5: 175.397,309.539
US_PS_Prog_B: R356.2 R367.1 S2.1 S2.2 U1.M19
  other v5: 173.397,306.539
US_PS_Ref_Clk: R375.2 U1.P19
  other v5: 175.397,306.539
USB2_CLK: R362.2 U45.1
USB2_D0: R116.2 U45.3
USB2_D1: R117.2 U45.4
USB2_D2: R115.2 U45.5
USB2_D3: R119.2 U45.6
USB2_D4: R120.2 U45.7
USB2_D5: R121.2 U45.9
USB2_D6: R122.2 U45.10
USB2_D7: R802.1 U45.13
USB2_DIR: R800.1 U45.31
USB2_NXT: R801.1 U45.2
USB2_STP: R118.2 U45.29
USB_D_N: C537.2 D13.2 U45.19
USB_D_P: C537.3 D13.1 U45.18
USB_En_Vout: U45.17 U46.A2
USB_OSC_IN: C736.2 R491.1 U45.26 X7.1
USB_OSC_Out: C737.2 R491.2 U45.25 X7.3
USB_RS0: R376.1 U45.8
USB_RS1: R377.1 U45.11
USB_RS2: R378.1 U45.14
USB_RX_C_N: C537.5 C543.2 D14.1 D14.10
USB_RX_C_P: C537.6 C542.2 D14.2 D14.9
USB_RX_N: C543.1 U1.J26
USB_RX_P: C542.1 U1.J25
USB_TX_C_N: C537.8 C541.2 D14.4 D14.7
USB_TX_C_P: C537.9 C540.2 D14.5 D14.6
USB_TX_N: C541.1 U1.H28
USB_TX_P: C540.1 U1.H27
USB_Vbus: R490.1 U45.22
USB_Vdd33: C731.2 U45.20
USB_Vout: C538.2 C539.2 C734.2 FB26.1 R490.2 U46.C2 U46.D1 U46.D2 U46.E1 U46.E2 U46.F1 U46.F2
uSD_CD: J28.9 R381.1 R782.1 U47.D3
uSD_CLK: R96.2 R97.1 U47.C1 | length 2.8
  L16 w0.098: U47.C1@135.527,335.404 136.416,335.404 136.924,334.896 R96.2@138.087,334.896
uSD_CMD: R95.2 U47.D2 | length 5.4
  L14 (Sign) w0.098: v23(135.127,335.004) 136.067,335.004 137.004,334.067 v23(137.004,332.204)
  L16 w0.098: v23(137.004,332.204) 137.436,331.772 R95.2@138.087,331.772
uSD_D0: R87.2 U47.D1 | length 3.8
  L16 w0.098: U47.D1@135.527,335.004 135.824,335.004 136.719,334.109 136.719,333.577 137.483,332.814 R87.2@138.087,332.814
uSD_D1: R88.2 U47.E1 | length 5.5
  L16 w0.098: U47.E1@135.527,334.604 136.391,333.741 136.391,331.48 137.14,330.731 R88.2@138.087,330.731
uSD_D2: R89.2 U47.A1 | length 4.1
  L16 w0.098: U47.A1@135.527,336.204 135.527,337.474 136.073,338.021 R89.2@138.087,338.021
uSD_D3: R90.2 U47.B1 | length 2.6
  L16 w0.098: U47.B1@135.527,335.804 135.788,335.804 135.921,335.938 R90.2@138.087,335.938
uSD_D4: R91.2 U47.B2 | length 3.5
  L14 (Sign) w0.098: v23(135.127,335.804) 135.127,335.944 v23(136.099,336.916)
  L16 w0.098: v23(136.099,336.916) 136.167,336.916 136.23,336.979 R91.2@138.087,336.979
uSD_D5: R92.2 U47.A2 | length 4.9
  L16 w0.098: U47.A2@135.129,336.204 135.127,337.538 136.651,339.062 R92.2@138.087,339.062
uSD_D6: R93.2 U47.A3 | length 5.9
  L16 w0.098: U47.A3@134.727,336.204 134.727,337.729 137.102,340.103 R93.2@138.087,340.103
uSD_D7: R94.2 U47.E3
V_KEY: C609.2 D24.2 R647.2 R648.2 R653.1 T24.1 T26.1 T28.1
V_PoE+: C595.2 C596.2 D3.1 D4.1 D27.1 R149.2 R324.2 T34.5 U65.18 | length 20.3
  L1 w0.254: R149.2@34.773,204.343 34.798,204.318 U65.18@36.92,204.318
  L16 w0.5: v6(27.345,228.551) C595.2@28.639,228.551 ; v6(28.639,229.845) C595.2@28.639,228.551 ; v6(29.932,228.551) C595.2@28.639,228.551 ; v6(35.686,223.896) D4.1@36.98,223.896 ; v6(36.98,225.19) D4.1@36.98,223.896 ; v6(38.274,223.896) D4.1@36.98,223.896 ; v6(45.554,223.832) D3.1@46.848,223.832 ; v6(46.848,222.539) D3.1@46.848,223.832 ; v6(46.848,225.126) D3.1@46.848,223.832 ; v6(48.141,223.832) D3.1@46.848,223.832 ; v6(48.998,226.657) R324.2@50.292,226.657 v6(50.292,227.951) ; v6(52.54,227.889) C596.2@52.54,226.595 v6(53.834,226.595)
VBB: C344.1 R257.1 U33.3 U33.4
VC1~: D3.4 T21.13 | length 21.6
  L16 w1: T21.13@40.432,251.716 44.386,247.762 44.386,235.194 D3.4@46.848,232.732
VC2~: D3.3 T21.14 | length 22.4
  L16 w1: T21.14@40.432,240.536 40.432,239.625 34.468,233.66 34.468,231.356 36.767,229.057 39.738,229.057 41.748,231.066 D3.3@41.748,232.732
VC3~: D4.4 T21.15 | length 22.8
  L16 w1: D4.4@36.98,232.796 36.98,233.601 42.608,239.23 42.608,245.567 38.972,249.203 T21.15@38.972,251.716
VC4~: D4.3 T21.16 | length 11.9
  L16 w1: D4.3@31.88,232.796 31.88,235.613 36.803,240.536 T21.16@38.972,240.536
Vcc_CLK_Mux_Fine: C326.2 C327.2 C328.2 C329.2 FB23.2 R250.1 R251.1 R259.1 R260.1 R386.1 R486.1 R488.2 U31.5 U32.5
VCCINT: C598.2 D26.2 R669.1 U65.4 U65.14 | length 8.4
  L1 w0.254: C598.2@37.846,208.912 38.26,208.498 U65.14@38.26,206.158 ; R669.1@38.887,200.831 39.26,201.204 U65.4@39.26,202.478
  L1 w0.5: D26.2@34.353,208.547 36.347,208.547 36.713,208.912 C598.2@37.846,208.912
VCCO_1: C398.2 R289.2 R293.1 R295.1 R296.1 U37.2 U37.4 U37.9 U37.32 | length 1
  L1 w0.254: R293.1@60.881,178.317 R289.2@60.881,179.317
VCCO_2: C439.2 R307.2 R310.1 R313.1 R314.1 U38.2 U38.4 U38.9 U38.32 | length 6.6
  L1 w0.254: R307.2@58.845,206.596 59.525,206.596 59.643,206.714 U38.4@61.453,206.714 ; C439.2@58.845,209.529 R310.1@58.845,208.526 60.003,208.526 60.815,207.714 U38.2@61.453,207.714
VDD_APLL1: C88.1 C110.2 FB13.2 U16.49
VDD_APLL2: C89.1 C127.2 FB15.2 U16.37
VDD_CLK_MUX_DIV_3.3V: C336.2 C337.2 C338.2 C340.2 FB24.2 U33.1 U33.8 U33.9 U33.12
VDD_DIG: C93.1 C165.2 C590.2 FB21.2 FB37.1 R1.2 R125.1 R127.2 R128.2 R366.1 R544.2 U16.8
VDD_IN0: C63.1 C101.2 FB8.2 U16.3
VDD_IN1: C64.1 C105.2 FB10.2 U16.16
VDD_IN2: C67.1 C109.2 FB12.2 U16.9
VDD_IN3: C70.1 C126.2 FB14.2 U16.4
VDD_TCXO: C92.1 C148.2 FB19.2 U16.19
VDD_XO: C90.1 C144.2 FB17.2 U16.42
VDDO_0: C75.1 C143.2 FB16.2 U16.21
VDDO_1: C76.1 C147.2 FB18.2 U16.25
VDDO_6: C77.1 C164.2 FB20.2 U16.59
VDDO_7: C81.1 C180.2 FB22.2 U16.63
VDDO_23: C82.1 C102.2 FB9.2 U16.30
VDDO_45: C83.1 C106.2 FB11.2 U16.50
VLDO: C544.2 R383.2 U47.B4
Vout1_1: C406.2 C407.2 C408.2 C409.2 C410.2 C411.2 C412.2 C413.2 C414.2 C415.2 C416.2 C417.2 L11.2 R448_U_Pomiar_pradu_napiecia_3.1 U64_U_Pomiar_pradu_napiecia_3.10 | length 10.2
  L1 w0.3: R448_U_Pomiar_pradu_napiecia_3.1@107.759,180.301 107.759,181.902 108.017,182.159 U64_U_Pomiar_pradu_napiecia_3.10@116.278,182.159
Vout1_2: C447.2 C448.2 C449.2 C450.2 C451.2 C452.2 C453.2 C454.2 C455.2 C456.2 C457.2 C458.2 L19.2 R448_U_Pomiar_pradu_napiecia_5.1 U64_U_Pomiar_pradu_napiecia_5.10
Vout2_1: C418.2 C419.2 C420.2 C421.2 C422.2 C423.2 C424.2 C425.2 C426.2 C427.2 C428.2 C429.2 L12.2 R448_U_Pomiar_pradu_napiecia_4.1 U64_U_Pomiar_pradu_napiecia_4.10
Vout2_2: C459.2 C460.2 C461.2 C462.2 C463.2 C464.2 C465.2 C466.2 C467.2 C468.2 C469.2 C470.2
Vout_1_Selector: C4.1 C5.1 C6.1 C7.1 C8.2 C9.2 C10.2 C11.2 C20.2 C21.2 C22.2 C23.2 C24.2 C25.2 C26.2 C27.2 R15.2 U4.7 U5.1 U5.8 | length 39.1
  L1 w0.5: v1(37.904,169.788) C4.1@38.991,169.788 ; v1(37.904,170.893) C4.1@38.991,170.893 ; v1(37.904,171.99) C4.1@38.991,171.99 ; v1(37.904,173.243) C5.1@38.991,173.243 ; v1(37.904,174.348) C5.1@38.991,174.348 ; v1(37.904,175.445) C5.1@38.991,175.445 ; v1(37.904,176.697) C7.1@38.991,176.697 ; v1(37.904,177.802) C7.1@38.991,177.802 ; v1(37.904,178.899) C7.1@38.991,178.899 ; v1(37.904,180.152) C6.1@38.991,180.152 ; v1(37.904,181.257) C6.1@38.991,181.257 ; v1(37.904,182.353) C6.1@38.991,182.353 ; C4.1@38.991,170.337 v1(40.078,170.337) ; C4.1@38.991,171.442 v1(40.078,171.442) ; C5.1@38.991,173.791 v1(40.078,173.791) ; C5.1@38.991,174.896 v1(40.078,174.896) ; C7.1@38.991,177.246 v1(40.078,177.246) ; C7.1@38.991,178.351 v1(40.078,178.351) ; C6.1@38.991,180.7 v1(40.078,180.7) ; C6.1@38.991,181.805 v1(40.078,181.805) ; v1(53.932,163.773) C20.2@55.019,163.774 ; v1(53.932,164.497) C20.2@55.019,164.497 ; v1(53.959,166.505) C27.2@55.046,166.505 ; v1(53.959,168.403) C22.2@55.046,168.403 ; v1(53.959,170.301) C21.2@55.046,170.301 ; v1(53.959,172.199) C24.2@55.046,172.199 ; v1(53.959,174.096) C25.2@55.046,174.096 ; v1(53.959,175.994) C23.2@55.046,175.994 ; v1(53.959,165.781) C27.2@55.046,165.781 ; v1(53.959,167.679) C22.2@55.046,167.679 ; v1(53.959,169.577) C21.2@55.046,169.577 ; v1(53.959,171.475) C24.2@55.046,171.475 ; v1(53.959,173.373) C25.2@55.046,173.373 ; v1(53.959,175.27) C23.2@55.046,175.27 ; v1(53.989,177.168) C26.2@55.076,177.168 ; v1(53.989,177.892) C26.2@55.076,177.892
  other v6: 50.48,171.336 49.821,172.073 49.233,172.838 50.481,172.838 49.233,177.161 50.481,177.161 49.821,177.926 50.48,178.663 46.94,180.658 47.599,181.395 46.939,182.16 48.188,182.16
  other v12: 49.06,174.6 49.06,175.4 48.36,183.921
Vout_2_Selector: C12.1 C13.1 C14.1 C15.1 C16.2 C17.2 C18.2 C19.2 C28.2 C29.2 C30.2 C31.2 C32.2 C33.2 C34.2 C35.2 R677.2 R678.2 U4.1 U4.8 U48.7 | length 40.8
  L1 w0.5: v1(37.823,183.811) C12.1@38.91,183.811 ; v1(37.823,184.916) C12.1@38.91,184.916 ; v1(37.823,186.012) C12.1@38.91,186.012 ; v1(37.823,187.256) C15.1@38.91,187.256 ; v1(37.823,188.361) C15.1@38.91,188.361 ; v1(37.823,189.458) C15.1@38.91,189.457 ; v1(37.823,190.701) C13.1@38.91,190.701 ; v1(37.823,191.806) C13.1@38.91,191.806 ; v1(37.823,192.903) C13.1@38.91,192.903 ; v1(37.823,194.146) C14.1@38.91,194.146 ; v1(37.823,195.251) C14.1@38.91,195.251 ; v1(37.823,196.348) C14.1@38.91,196.348 ; C12.1@38.91,184.359 v1(39.997,184.359) ; C12.1@38.91,185.464 v1(39.997,185.464) ; C15.1@38.91,187.804 v1(39.997,187.804) ; C15.1@38.91,188.909 v1(39.997,188.909) ; C13.1@38.91,191.249 v1(39.997,191.249) ; C13.1@38.91,192.354 v1(39.997,192.354) ; C14.1@38.91,194.694 v1(39.997,194.694) ; C14.1@38.91,195.799 v1(39.997,195.799) ; v6(43.658,191.22) R678.2@43.658,192.033 ; v6(44.716,191.22) R677.2@44.716,192.033 ; v1(53.971,179.205) C31.2@55.058,179.205 ; v1(53.971,179.929) C31.2@55.058,179.929 ; v1(53.971,181.103) C30.2@55.058,181.103 ; v1(53.971,181.827) C30.2@55.058,181.827 ; v1(53.971,183.001) C32.2@55.058,183.001 ; v1(53.971,183.725) C32.2@55.058,183.725 ; v1(53.971,184.899) C29.2@55.058,184.899 ; v1(53.971,185.623) C29.2@55.058,185.623 ; v1(53.971,186.796) C28.2@55.058,186.796 ; v1(53.971,187.52) C28.2@55.058,187.52 ; v1(53.971,188.694) C33.2@55.058,188.694 ; v1(53.971,189.418) C33.2@55.058,189.418 ; v1(53.971,190.592) C34.2@55.058,190.592 ; v1(53.971,191.316) C34.2@55.058,191.316 ; v1(53.997,192.534) C35.2@55.084,192.534 ; v1(53.996,193.258) C35.2@55.083,193.258
  other v6: 50.48,180.658 49.821,181.395 49.233,182.16 50.481,182.16 49.233,186.483 50.481,186.483 49.821,187.248 50.48,187.985 46.907,190.32 47.566,191.057 46.906,191.822 48.155,191.821
  other v12: 49.06,183.921 49.06,184.721 48.327,193.583
Vout_5V@10A_INA: L20.2 R448_U_Pomiar_pradu_napiecia_6.1 U64_U_Pomiar_pradu_napiecia_6.10
VPHY_FTDI: C661.2 C662.2 FB44.2 U55.4
VPLL_FTDI: C659.2 C660.2 FB43.2 U55.9
VREF+_1: C61.2 C62.2 FB3.2 U12.44
VREF+_2: C73.2 C74.2 FB5.2 U13.44
VREF+_3: C57.2 C58.2 FB2.2
VSD_REF: R911.2 U47.C4
VVCO+_1: C86.2 C87.2 FB6.2 U12.39
VVCO+_2: C97.2 C98.2 FB7.2 U13.39
VVCO+_3: C68.2 C69.2 FB4.2
WR_LMK_CLK_HF1_N: U1.AJ1 U16.26 | length 0.7
  L1 w0.116: v4(189.909,288.052) U1.AJ1@190.397,288.539
WR_LMK_CLK_HF1_P: U1.AJ2 U16.27 | length 0.7
  L1 w0.116: v4(189.909,289.052) U1.AJ2@190.397,289.539
WR_LMK_CLK_HF2_N: U1.B16 U16.32
WR_LMK_CLK_HF2_P: U1.C17 U16.31
WR_LMK_CLK_HF3_N: U16.33
WR_LMK_CLK_HF3_P: U16.34
WR_LMK_CLK_HF4_N: U16.52
WR_LMK_CLK_HF4_P: U16.51
WR_LMK_CLK_HF5_N: U16.53
WR_LMK_CLK_HF5_P: U16.54
WR_LMK_CLK_HF6_N: U16.58
WR_LMK_CLK_HF6_P: U16.57
WR_LMK_CLK_HF7_N: U16.61
WR_LMK_CLK_HF7_P: U16.62
WR_LMK_CLK_IN_N: C42.1 R311.1 U16.2
WR_LMK_CLK_IN_P: C41.1 R311.2 U16.1
WR_LMK_CLK_LF_N: U16.15 U16.23
WR_LMK_CLK_LF_P: U16.14 U16.22
X1: C481.2 R335.2 U39.14 X4.1
X2: C480.2 R335.1 U39.15 X4.3
XO_LMK05028_P: C589.2 U16.43
pads on no net: C558.4 D28.1 J1_PCIE0.48 J1_PCIE0.50 J1_PCIE1.48 J1_PCIE1.50 J1_PCIE2.48 J1_PCIE2.50 J1_PCIE3.48 J1_PCIE3.50 J1_PCIE4.48 J1_PCIE4.50 J14.3 J27. J27.5 J27.6 J27.7 J27.8 J27.11 J27.13 J27.17 J27.19 J27.20 J27.22 J27.23 J27.24 J27.25 J27.26 J27.28 J27.30 J27.32 J27.34 J27.36 J27.40 J27.42 J27.44 J27.46 J27.48 J27.56 J27.58 J27.59 J28.MH1 J28.MH2 J32. J33. J33.17 J34. J34.17 J35. J35.17 MP1_PCIE0.1 MP1_PCIE1.1 MP1_PCIE2.1 MP1_PCIE3.1 MP1_PCIE4.1 MP2_PCIE0.1 MP2_PCIE1.1 MP2_PCIE2.1 MP2_PCIE3.1 MP2_PCIE4.1 MP3_PCIE0.1 MP3_PCIE1.1 MP3_PCIE2.1 MP3_PCIE3.1 MP3_PCIE4.1 P12.11 R100.1 R100.2 R867.2 R868.2 R869.2 R870.2 R883.2 R884.2 R885.2 R886.2 R913.2 R914.2 R915.2 R916.2 R917.2 R980.2 R981.2 R982.2 R983.2 R984.2 R985.2 R986.2 R987.2 R988.2 R989.2 R990.2 R991.2 R992.2 R993.2 R994.2 R995.2 R996.2 R997.2 R998.2 R999.2 R1000.2 R1004.2 R1005.2 R1006.2 R1007.2 R1008.2 R1009.2 R1010.2 R1011.2 R1012.2 R1013.2 R1014.2 R1015.2 R1016.2 R1017.2 R1018.2 R1019.2 R1020.2 R1021.2 R1022.2 R1023.2 R1024.2 R1025.2 R1035.2 T5. T6. T7. T8. T9. T10. T11. T12. T13. T14. T15. T16. T17. T18. T19. T20. T21.MH1 T21.MH2 T35. U1.A15 U1.AA8 U1.AA17 U1.AA26 U1.AA30 U1.AB5 U1.AB6 U1.AB8 U1.AB18 U1.AB19 U1.AB20 U1.AB21 U1.AB29 U1.AC7 U1.AC8 U1.AC13 U1.AC19 U1.AD7 U1.AD17 U1.AE3 U1.AE7 U1.AE10 U1.AE12 U1.AE17 U1.AF1 U1.AF2 U1.AF5 U1.AF6 U1.AF11 U1.AF12 U1.AF13 U1.AF15 U1.AF16 U1.AF17 U1.AG5 U1.AG6 U1.AG8 U1.AG9 U1.AG11 U1.AG14 U1.AG15 U1.AG19 U1.AH1 U1.AH4 U1.AH6 U1.AH7 U1.AH8 U1.AH11 U1.AH12 U1.AH14 U1.AJ6 U1.AJ7 U1.AJ12 U1.AJ27 U1.AK2 U1.AK3 U1.B15 U1.C13 U1.D14 U1.D15 U1.D17 U1.E12 U1.E13 U1.E14 U1.E15 U1.E17 U1.F12 U1.F13 U1.F15 U1.F16 U1.G13 U1.G15 U1.G16 U1.L25 U1.L26 U1.W9 U1.W10 U1.W26 U1.W27 U1.Y1 U1.Y9 U1.Y27 U1.Y29 U1.Y30 U8.T4 U9.T4 U10.T4 U11.T4 U13.42 U16.5 U16.6 U16.10 U16.11 U16.18 U30.6 U30.7 U30.8 U31.3 U31.4 U31.8 U31.13 U31.14 U31.15 U31.16 U32.8 U32.13 U32.14 U32.15 U32.16 U33.7 U35_I2C_Expander_00.7 U35_I2C_Expander_00.10 U35_I2C_Expander_01.7 U35_I2C_Expander_01.10 U35_I2C_Expander_02.7 U35_I2C_Expander_02.10 U35_I2C_Expander_10.7 U35_I2C_Expander_10.10 U35_I2C_Expander_11.7 U35_I2C_Expander_11.10 U35_I2C_Expander_12.7 U35_I2C_Expander_12.10 U35_I2C_Expander_16.7 U35_I2C_Expander_16.10 U35_I2C_Expander_17.7 U35_I2C_Expander_17.10 U35_I2C_Expander_18.7 U35_I2C_Expander_18.10 U35_I2C_Expander_Main_Rst.7 U35_I2C_Expander_Main_Rst.10 U35_I2C_Expander_PWR_CLK.7 U35_I2C_Expander_PWR_CLK.10 U35_I2C_Expander_PWR_Dist.7 U35_I2C_Expander_PWR_Dist.10 U35_I2C_Expander_SFP.7 U35_I2C_Expander_SFP.10 U39.18 U39.25 U39.26 U39.29 U39.32 U39.37 U39.38 U39.40 U40.6 U41.A1 U41.A2 U41.A7 U41.A8 U41.A9 U41.A10 U41.A11 U41.A12 U41.A13 U41.A14 U41.B1 U41.B7 U41.B8 U41.B9 U41.B10 U41.B11 U41.B12 U41.B13 U41.B14 U41.C1 U41.C3 U41.C5 U41.C7 U41.C8 U41.C9 U41.C10 U41.C11 U41.C12 U41.C13 U41.C14 U41.D1 U41.D2 U41.D3 U41.D4 U41.D12 U41.D13 U41.D14 U41.E1 U41.E2 U41.E3 U41.E5 U41.E8 U41.E9 U41.E10 U41.E12 U41.E13 U41.E14 U41.F1 U41.F2 U41.F3 U41.F10 U41.F12 U41.F13 U41.F14 U41.G1 U41.G2 U41.G3 U41.G10 U41.G12 U41.G13 U41.G14 U41.H1 U41.H2 U41.H3 U41.H5 U41.H12 U41.H13 U41.H14 U41.J1 U41.J2 U41.J3 U41.J12 U41.J13 U41.J14 U41.K1 U41.K2 U41.K3 U41.K6 U41.K7 U41.K10 U41.K12 U41.K13 U41.K14 U41.L1 U41.L2 U41.L3 U41.L12 U41.L13 U41.L14 U41.M1 U41.M2 U41.M3 U41.M7 U41.M8 U41.M9 U41.M10 U41.M11 U41.M12 U41.M13 U41.M14 U41.N1 U41.N3 U41.N6 U41.N7 U41.N8 U41.N9 U41.N10 U41.N11 U41.N12 U41.N13 U41.N14 U41.P1 U41.P2 U41.P7 U41.P8 U41.P9 U41.P10 U41.P11 U41.P12 U41.P13 U41.P14 U42.6 U44.8 U44.9 U45.12 U45.15 U45.16 U46.B3 U46.C4 U47.E2 U47.E4 U55.36 U55.60 U58.10 U58.11 U59_5V_to_3V3_for_FTDI.6 U59_U_5V_to_3V31.6 U59_U_5V_to_3V32.6 U59_U_5V_to_3V33.6 U60.8 U63.5 U65.1 U69.8 U73.3 U78.3 U78.4
copper on no net: | length 97.9
  L1 w0.116: 182.909,292.052 183.397,292.539 ; 182.909,293.052 183.397,293.539 ; 186.909,300.052 187.397,300.539 ; 206.324,342.392 v3(206.728,342.796) ; 211.541,342.801 211.938,342.405 v4(211.938,342.402) ; 370.718,242.339 v4(371.408,242.339) ; 374.352,239.977 v5(374.839,240.464) ; 374.809,249.091 v2(375.296,249.579) ; 376.803,243.901 v4(377.29,244.389)
  L1 w0.254: 27.941,762.827 28.583,762.827 29.733,761.677 31.157,761.677 31.454,761.974 31.454,762.396 31.51,762.452 ; 27.941,763.477 27.947,763.483 v2(29.391,763.483) ; 27.941,764.127 28.316,764.127 29.516,765.327 31.1,765.327 31.513,764.913 31.513,764.533 ; 28.982,732.274 29.884,732.274 30.949,731.209 32.199,731.209 32.493,731.503 32.493,731.903 34.525,731.903 ; 28.982,732.924 v2(30.518,732.924) ; 28.982,733.574 29.749,733.574 30.949,734.774 32.237,734.774 32.493,734.518 32.493,733.968 34.525,733.968 ; 31.482,762.424 33.286,762.424 33.322,762.459 ; 31.513,763.489 31.514,763.49 v2(32.479,763.49) ; 31.513,764.541 33.325,764.541 ; 32.101,763.496 33.326,763.496 ; 32.493,732.924 v2(33.531,732.924) 34.525,732.924 ; 44.949,775.047 45.853,775.047 46.695,774.205 47.985,774.205 48.177,774.396 48.177,774.732 49.99,774.732 ; 44.949,775.697 v2(46.145,775.697) ; 44.949,776.347 45.724,776.347 46.606,777.229 48.028,777.229 48.177,777.08 48.177,776.682 49.99,776.682 ; 45.26,753.123 46.551,753.123 47.851,751.823 49.388,751.823 49.738,752.173 49.738,752.623 51.554,752.623 ; 45.26,753.773 45.281,753.752 v2(47.327,753.752) ; 45.26,754.423 46.715,754.423 47.851,755.558 49.388,755.558 49.713,755.234 49.713,754.781 49.738,754.756 51.554,754.756 ; 48.177,775.697 v2(49.078,775.697) 49.99,775.697 ; 49.738,753.731 49.758,753.752 v2(50.687,753.752) 50.698,753.741 51.544,753.741 51.554,753.731
  L1 w0.5: v1(42.597,17.328) 42.597,18.415 ; v1(42.597,20.128) 42.597,21.215 ; 43.145,18.415 v1(43.145,19.502) ; 43.145,21.215 v1(43.145,22.302) ; v1(43.694,17.328) 43.694,18.415 ; v1(43.694,20.128) 43.694,21.215 ; 44.25,18.415 v1(44.25,19.502) ; 44.25,21.215 v1(44.25,22.302) ; v1(44.799,17.328) 44.799,18.415 ; v1(44.799,20.128) 44.799,21.215
  L5 (Sign) w0.116: v28(371.685,243.799) v28(372.706,242.779)
  L3 (Sign) w0.092: 212.405,343.017 v22(212.801,342.621)
  L14 (Sign) w0.254: v2(29.391,763.483) 32.472,763.483 v2(32.479,763.49) ; v2(30.518,732.924) v2(33.531,732.924) ; v2(46.145,775.697) v2(49.078,775.697) ; v2(47.327,753.752) v2(50.687,753.752)
  other v3: 195.377,344.081
  other v5: 181.397,288.539
  other v7: 413.931,156.87 426.974,156.896 420.484,157.213 407.099,157.328 413.804,162.052 419.329,162.115 431.406,162.113 425.386,162.141 407.797,162.611 363.601,171.336 370.967,171.336 377.901,171.336 385.267,171.336 392.633,171.336 399.986,171.336 407.352,171.336 414.719,171.336 422.084,171.336 429.45,171.336 436.816,171.336 443.738,171.336 451.104,171.336 458.47,171.336 465.836,171.336 473.202,171.336 480.555,171.336 487.921,171.336 495.287,171.336 502.653,171.336 510.019,171.336 517.385,171.336 363.106,180.556 393.827,180.556 424.548,180.556 455.282,180.556 486.004,180.556 516.725,180.556 546.189,180.556 576.91,180.556 607.631,180.556 638.111,180.556 668.833,180.556 698.284,180.556 727.748,180.556 757.199,180.556 786.651,180.556 816.115,180.556 845.566,180.556 875.03,180.556 363.106,190.792 393.827,190.792 424.548,190.792 455.282,190.792 486.004,190.792 516.725,190.792 546.189,190.792 576.91,190.792 607.631,190.792 638.111,190.792 668.833,190.792 698.284,190.792 727.748,190.792 757.199,190.792 786.651,190.792 816.115,190.792 845.566,190.792 875.03,190.792 363.106,201.028 392.557,201.028 422.008,201.028 451.472,201.028 480.924,201.028 510.375,201.028 538.569,201.028 568.02,201.028 597.484,201.028 626.682,201.028 656.133,201.028 684.327,201.028 712.508,201.028 740.689,201.028 768.883,201.028 797.065,201.028 825.259,201.028 853.44,201.028 363.106,211.264 394.081,211.264 425.056,211.264 456.044,211.264 487.02,211.264 517.995,211.264 548.983,211.264 579.958,211.264 610.933,211.264 641.668,211.264 363.106,221.501 396.875,221.501 291.516,475.577 286.55,477.545 292.138,481.889 310.299,484.721 298.615,484.772 282.943,484.886 304.775,485.33 291.122,487.426 282.651,489.623 306.067,490.69 299.022,490.918 282.88,494.703 290.271,494.982 313.512,496.341 301.447,496.564 307.416,496.786
  other v20: 170.237,267.894 252.59,267.894 62.485,362.892 144.837,362.892 227.19,362.892
  other v21: 145.237,267.894 227.59,267.894 87.485,362.892 169.837,362.892 252.19,362.892
  other v31: 375.296,249.579

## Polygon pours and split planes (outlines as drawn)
US+_Vcc_PS_IntFp on L1 "US+_VCC_PS_INTFP_L01_P099" (solid, pour order 99): 145.706,304.356 148.104,301.958 148.104,289.481 146.012,287.388 138.648,287.388 138.102,287.934 138.112,287.945 138.112,303.81 138.659,304.356
CSP on L1 "L1-CSP" (solid, pour order 279): 35.344,235.28 43.258,235.28 45.949,232.589 45.949,230.226 44.005,228.282 36.106,228.282 34.023,230.365 34.023,234.036 35.242,235.255
no net on L1 "L1-No Net" (solid, pour order 269): 91.618,222.154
